
VERSION 5.7 ;
BUSBITCHARS "[]" ;
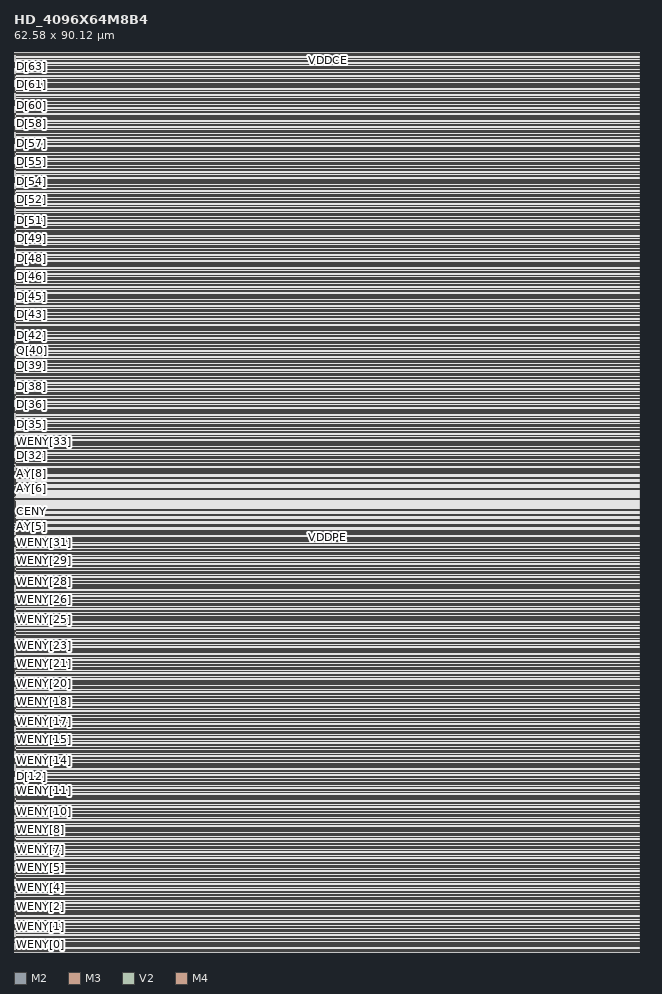
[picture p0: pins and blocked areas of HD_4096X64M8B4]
MACRO HD_4096X64M8B4
	FOREIGN HD_4096X64M8B4 0 0 ;
	SYMMETRY X Y ;
	SIZE 62.58 BY 90.12 ;
	CLASS BLOCK ;
	PIN AY[0]
		USE SIGNAL ;
		DIRECTION OUTPUT ;
		SHAPE ABUTMENT ;
		PORT
			 LAYER M2 ;
			RECT 0.0714 44.5114 0.1097 44.549 ;
			 LAYER M3 ;
			RECT 0.0714 44.5114 0.1097 44.6118 ;
			 LAYER V2 ;
			RECT 0.0831 44.5235 0.098 44.5361 ;
		END

		ANTENNADIFFAREA 0.00194719 ;
		ANTENNAPARTIALMETALAREA 0.00195671 ;
	END AY[0]

	PIN AY[10]
		USE SIGNAL ;
		DIRECTION OUTPUT ;
		SHAPE ABUTMENT ;
		PORT
			 LAYER M3 ;
			RECT 0.0714 47.0714 0.1097 47.1718 ;
		END

		ANTENNADIFFAREA 0.00194719 ;
		ANTENNAPARTIALMETALAREA 0.00195671 ;
	END AY[10]

	PIN AY[11]
		USE SIGNAL ;
		DIRECTION OUTPUT ;
		SHAPE ABUTMENT ;
		PORT
			 LAYER M2 ;
			RECT 0.0098 47.8871 0.0481 47.9247 ;
			 LAYER M3 ;
			RECT 0.0098 47.8243 0.0481 47.9247 ;
			 LAYER V2 ;
			RECT 0.0215 47.8992 0.0364 47.9118 ;
		END

		ANTENNADIFFAREA 0.00194719 ;
		ANTENNAPARTIALMETALAREA 0.00195671 ;
	END AY[11]

	PIN AY[1]
		USE SIGNAL ;
		DIRECTION OUTPUT ;
		SHAPE ABUTMENT ;
		PORT
			 LAYER M2 ;
			RECT 0.0714 44.8125 0.1097 44.8502 ;
			 LAYER M3 ;
			RECT 0.0714 44.8125 0.1097 44.9129 ;
			 LAYER V2 ;
			RECT 0.0831 44.8247 0.098 44.8373 ;
		END

		ANTENNADIFFAREA 0.00194719 ;
		ANTENNAPARTIALMETALAREA 0.00195671 ;
	END AY[1]

	PIN AY[2]
		USE SIGNAL ;
		DIRECTION OUTPUT ;
		SHAPE ABUTMENT ;
		PORT
			 LAYER M2 ;
			RECT 0.0714 44.9631 0.1097 45.0008 ;
			 LAYER M3 ;
			RECT 0.0714 44.9631 0.1097 45.0635 ;
			 LAYER V2 ;
			RECT 0.0831 44.9753 0.098 44.9878 ;
		END

		ANTENNADIFFAREA 0.00194719 ;
		ANTENNAPARTIALMETALAREA 0.00195671 ;
	END AY[2]

	PIN AY[3]
		USE SIGNAL ;
		DIRECTION OUTPUT ;
		SHAPE ABUTMENT ;
		PORT
			 LAYER M2 ;
			RECT 0.0098 45.6282 0.0481 45.6659 ;
			 LAYER M3 ;
			RECT 0.0098 45.5655 0.0481 45.6659 ;
			 LAYER V2 ;
			RECT 0.0215 45.6404 0.0364 45.6529 ;
		END

		ANTENNADIFFAREA 0.00194719 ;
		ANTENNAPARTIALMETALAREA 0.00195671 ;
	END AY[3]

	PIN AY[4]
		USE SIGNAL ;
		DIRECTION OUTPUT ;
		SHAPE ABUTMENT ;
		PORT
			 LAYER M2 ;
			RECT 0.0098 44.7247 0.0481 44.7624 ;
			 LAYER M3 ;
			RECT 0.0098 44.662 0.0481 44.7624 ;
			 LAYER V2 ;
			RECT 0.0215 44.7369 0.0364 44.7494 ;
		END

		ANTENNADIFFAREA 0.00194719 ;
		ANTENNAPARTIALMETALAREA 0.00195671 ;
	END AY[4]

	PIN AY[5]
		USE SIGNAL ;
		DIRECTION OUTPUT ;
		SHAPE ABUTMENT ;
		PORT
			 LAYER M2 ;
			RECT 0.0714 43.3067 0.1097 43.3443 ;
			 LAYER M3 ;
			RECT 0.0714 43.3067 0.1097 43.4071 ;
			 LAYER V2 ;
			RECT 0.0831 43.3188 0.098 43.3314 ;
		END

		ANTENNADIFFAREA 0.00194719 ;
		ANTENNAPARTIALMETALAREA 0.00195671 ;
	END AY[5]

	PIN AY[6]
		USE SIGNAL ;
		DIRECTION OUTPUT ;
		SHAPE ABUTMENT ;
		PORT
			 LAYER M2 ;
			RECT 0.0098 46.3812 0.0481 46.4188 ;
		END

		ANTENNADIFFAREA 0.00194719 ;
		ANTENNAPARTIALMETALAREA 0.00195671 ;
	END AY[6]

	PIN AY[7]
		USE SIGNAL ;
		DIRECTION OUTPUT ;
		SHAPE ABUTMENT ;
		PORT
			 LAYER M2 ;
			RECT 0.0714 46.1678 0.1097 46.2055 ;
			 LAYER M3 ;
			RECT 0.0714 46.1678 0.1097 46.2682 ;
			 LAYER V2 ;
			RECT 0.0831 46.18 0.098 46.1925 ;
		END

		ANTENNADIFFAREA 0.00194719 ;
		ANTENNAPARTIALMETALAREA 0.00195671 ;
	END AY[7]

	PIN AY[8]
		USE SIGNAL ;
		DIRECTION OUTPUT ;
		SHAPE ABUTMENT ;
		PORT
			 LAYER M2 ;
			RECT 0.0098 47.0714 0.0481 47.109 ;
		END

		ANTENNADIFFAREA 0.00194719 ;
		ANTENNAPARTIALMETALAREA 0.00195671 ;
	END AY[8]

	PIN AY[9]
		USE SIGNAL ;
		DIRECTION OUTPUT ;
		SHAPE ABUTMENT ;
		PORT
			 LAYER M2 ;
			RECT 0.0714 47.3725 0.1097 47.4102 ;
			 LAYER M3 ;
			RECT 0.0714 47.3725 0.1097 47.4729 ;
			 LAYER V2 ;
			RECT 0.0831 47.3847 0.098 47.3973 ;
		END

		ANTENNADIFFAREA 0.00194719 ;
		ANTENNAPARTIALMETALAREA 0.00195671 ;
	END AY[9]

	PIN A[0]
		USE SIGNAL ;
		DIRECTION INPUT ;
		SHAPE ABUTMENT ;
		PORT
			 LAYER M2 ;
			RECT 0.0098 44.2729 0.0481 44.3106 ;
			 LAYER M3 ;
			RECT 0.0098 44.2102 0.0481 44.3106 ;
			 LAYER V2 ;
			RECT 0.0215 44.2851 0.0364 44.2976 ;
		END

		ANTENNAGATEAREA 0.00027817 ;
		ANTENNADIFFAREA 0.00194719 ;
		ANTENNAPARTIALMETALAREA 0.00195671 ;
	END A[0]

	PIN A[10]
		USE SIGNAL ;
		DIRECTION INPUT ;
		SHAPE ABUTMENT ;
		PORT
			 LAYER M2 ;
			RECT 0.0098 47.4353 0.0481 47.4729 ;
			 LAYER M3 ;
			RECT 0.0098 47.3725 0.0481 47.4729 ;
			 LAYER V2 ;
			RECT 0.0215 47.4475 0.0364 47.46 ;
		END

		ANTENNAGATEAREA 0.00027817 ;
		ANTENNADIFFAREA 0.00194719 ;
		ANTENNAPARTIALMETALAREA 0.00195671 ;
	END A[10]

	PIN A[11]
		USE SIGNAL ;
		DIRECTION INPUT ;
		SHAPE ABUTMENT ;
		PORT
			 LAYER M2 ;
			RECT 0.0098 47.1341 0.0481 47.1718 ;
		END

		ANTENNAGATEAREA 0.00027817 ;
		ANTENNADIFFAREA 0.00194719 ;
		ANTENNAPARTIALMETALAREA 0.00195671 ;
	END A[11]

	PIN A[1]
		USE SIGNAL ;
		DIRECTION INPUT ;
		SHAPE ABUTMENT ;
		PORT
			 LAYER M2 ;
			RECT 0.0098 43.52 0.0481 43.5576 ;
			 LAYER M3 ;
			RECT 0.0098 43.4573 0.0481 43.5576 ;
			 LAYER V2 ;
			RECT 0.0215 43.5322 0.0364 43.5447 ;
		END

		ANTENNAGATEAREA 0.00027817 ;
		ANTENNADIFFAREA 0.00194719 ;
		ANTENNAPARTIALMETALAREA 0.00195671 ;
	END A[1]

	PIN A[2]
		USE SIGNAL ;
		DIRECTION INPUT ;
		SHAPE ABUTMENT ;
		PORT
			 LAYER M2 ;
			RECT 0.0714 46.9208 0.1097 46.9584 ;
			 LAYER M3 ;
			RECT 0.0714 46.9208 0.1097 47.0212 ;
			 LAYER V2 ;
			RECT 0.0831 46.9329 0.098 46.9455 ;
		END

		ANTENNAGATEAREA 0.00027817 ;
		ANTENNADIFFAREA 0.00194719 ;
		ANTENNAPARTIALMETALAREA 0.00195671 ;
	END A[2]

	PIN A[3]
		USE SIGNAL ;
		DIRECTION INPUT ;
		SHAPE ABUTMENT ;
		PORT
			 LAYER M2 ;
			RECT 0.0098 45.7788 0.0481 45.8165 ;
			 LAYER M3 ;
			RECT 0.0098 45.7161 0.0481 45.8165 ;
			 LAYER V2 ;
			RECT 0.0215 45.791 0.0364 45.8035 ;
		END

		ANTENNAGATEAREA 0.00027817 ;
		ANTENNADIFFAREA 0.00194719 ;
		ANTENNAPARTIALMETALAREA 0.00195671 ;
	END A[3]

	PIN A[4]
		USE SIGNAL ;
		DIRECTION INPUT ;
		SHAPE ABUTMENT ;
		PORT
			 LAYER M2 ;
			RECT 0.0098 45.1765 0.0481 45.2141 ;
			 LAYER M3 ;
			RECT 0.0098 45.1137 0.0481 45.2141 ;
			 LAYER V2 ;
			RECT 0.0215 45.1886 0.0364 45.2012 ;
		END

		ANTENNAGATEAREA 0.00027817 ;
		ANTENNADIFFAREA 0.00194719 ;
		ANTENNAPARTIALMETALAREA 0.00195671 ;
	END A[4]

	PIN A[5]
		USE SIGNAL ;
		DIRECTION INPUT ;
		SHAPE ABUTMENT ;
		PORT
			 LAYER M2 ;
			RECT 0.0714 44.3608 0.1097 44.3984 ;
			 LAYER M3 ;
			RECT 0.0714 44.3608 0.1097 44.4612 ;
			 LAYER V2 ;
			RECT 0.0831 44.3729 0.098 44.3855 ;
		END

		ANTENNAGATEAREA 0.00027817 ;
		ANTENNADIFFAREA 0.00194719 ;
		ANTENNAPARTIALMETALAREA 0.00195671 ;
	END A[5]

	PIN A[6]
		USE SIGNAL ;
		DIRECTION INPUT ;
		SHAPE ABUTMENT ;
		PORT
			 LAYER M2 ;
			RECT 0.0098 45.9294 0.0481 45.9671 ;
			 LAYER M3 ;
			RECT 0.0098 45.8667 0.0481 45.9671 ;
			 LAYER V2 ;
			RECT 0.0215 45.9416 0.0364 45.9541 ;
		END

		ANTENNAGATEAREA 0.00027817 ;
		ANTENNADIFFAREA 0.00194719 ;
		ANTENNAPARTIALMETALAREA 0.00195671 ;
	END A[6]

	PIN A[7]
		USE SIGNAL ;
		DIRECTION INPUT ;
		SHAPE ABUTMENT ;
		PORT
			 LAYER M2 ;
			RECT 0.0098 46.5318 0.0481 46.5694 ;
		END

		ANTENNAGATEAREA 0.00027817 ;
		ANTENNADIFFAREA 0.00194719 ;
		ANTENNAPARTIALMETALAREA 0.00195671 ;
	END A[7]

	PIN A[8]
		USE SIGNAL ;
		DIRECTION INPUT ;
		SHAPE ABUTMENT ;
		PORT
			 LAYER M2 ;
			RECT 0.0098 46.8329 0.0481 46.8706 ;
			 LAYER M3 ;
			RECT 0.0098 46.7702 0.0481 46.8706 ;
			 LAYER V2 ;
			RECT 0.0215 46.8451 0.0364 46.8576 ;
		END

		ANTENNAGATEAREA 0.00027817 ;
		ANTENNADIFFAREA 0.00194719 ;
		ANTENNAPARTIALMETALAREA 0.00195671 ;
	END A[8]

	PIN A[9]
		USE SIGNAL ;
		DIRECTION INPUT ;
		SHAPE ABUTMENT ;
		PORT
			 LAYER M2 ;
			RECT 0.0098 46.9835 0.0481 47.0212 ;
			 LAYER M3 ;
			RECT 0.0098 46.9208 0.0481 47.0212 ;
			 LAYER V2 ;
			RECT 0.0215 46.9957 0.0364 47.0082 ;
		END

		ANTENNAGATEAREA 0.00027817 ;
		ANTENNADIFFAREA 0.00194719 ;
		ANTENNAPARTIALMETALAREA 0.00195671 ;
	END A[9]

	PIN CEN
		USE SIGNAL ;
		DIRECTION INPUT ;
		SHAPE ABUTMENT ;
		PORT
			 LAYER M2 ;
			RECT 0.0714 47.9749 0.1097 48.0125 ;
			 LAYER M3 ;
			RECT 0.0714 47.9749 0.1097 48.0753 ;
			 LAYER V2 ;
			RECT 0.0831 47.9871 0.098 47.9996 ;
		END

		ANTENNAGATEAREA 0.00027817 ;
		ANTENNADIFFAREA 0.00194719 ;
		ANTENNAPARTIALMETALAREA 0.00195671 ;
	END CEN

	PIN CENY
		USE SIGNAL ;
		DIRECTION OUTPUT ;
		SHAPE ABUTMENT ;
		PORT
			 LAYER M2 ;
			RECT 0.0098 44.1224 0.0481 44.16 ;
		END

		ANTENNADIFFAREA 0.00194719 ;
		ANTENNAPARTIALMETALAREA 0.00195671 ;
	END CENY

	PIN CLK
		USE SIGNAL ;
		DIRECTION INPUT ;
		SHAPE ABUTMENT ;
		PORT
			 LAYER M2 ;
			RECT 0.0098 44.5741 0.0481 44.6118 ;
			 LAYER M3 ;
			RECT 0.0098 44.5114 0.0481 44.6118 ;
			 LAYER V2 ;
			RECT 0.0215 44.5863 0.0364 44.5988 ;
		END

		ANTENNAGATEAREA 0.00027817 ;
		ANTENNADIFFAREA 0.00194719 ;
		ANTENNAPARTIALMETALAREA 0.00195671 ;
	END CLK

	PIN DFTRAMBYP
		USE SIGNAL ;
		DIRECTION INPUT ;
		SHAPE ABUTMENT ;
		PORT
			 LAYER M2 ;
			RECT 0.0714 43.0055 0.1097 43.0431 ;
			 LAYER M3 ;
			RECT 0.0714 43.0055 0.1097 43.1059 ;
			 LAYER V2 ;
			RECT 0.0831 43.0176 0.098 43.0302 ;
		END

		ANTENNAGATEAREA 0.00027817 ;
		ANTENNADIFFAREA 0.00194719 ;
		ANTENNAPARTIALMETALAREA 0.00195671 ;
	END DFTRAMBYP

	PIN D[0]
		USE SIGNAL ;
		DIRECTION INPUT ;
		SHAPE ABUTMENT ;
		PORT
			 LAYER M2 ;
			RECT 0.0098 1.3678 0.0481 1.4055 ;
			 LAYER M3 ;
			RECT 0.0098 1.3678 0.0481 1.4682 ;
			 LAYER V2 ;
			RECT 0.0215 1.3808 0.0364 1.3933 ;
		END

		ANTENNAGATEAREA 0.00027817 ;
		ANTENNADIFFAREA 0.00194719 ;
		ANTENNAPARTIALMETALAREA 0.00195671 ;
	END D[0]

	PIN D[10]
		USE SIGNAL ;
		DIRECTION INPUT ;
		SHAPE ABUTMENT ;
		PORT
			 LAYER M2 ;
			RECT 0.0098 14.1678 0.0481 14.2055 ;
			 LAYER M3 ;
			RECT 0.0098 14.1678 0.0481 14.2682 ;
			 LAYER V2 ;
			RECT 0.0215 14.1808 0.0364 14.1933 ;
		END

		ANTENNAGATEAREA 0.00027817 ;
		ANTENNADIFFAREA 0.00194719 ;
		ANTENNAPARTIALMETALAREA 0.00195671 ;
	END D[10]

	PIN D[11]
		USE SIGNAL ;
		DIRECTION INPUT ;
		SHAPE ABUTMENT ;
		PORT
			 LAYER M2 ;
			RECT 0.0098 15.4478 0.0481 15.4855 ;
			 LAYER M3 ;
			RECT 0.0098 15.4478 0.0481 15.5482 ;
			 LAYER V2 ;
			RECT 0.0215 15.4608 0.0364 15.4733 ;
		END

		ANTENNAGATEAREA 0.00027817 ;
		ANTENNADIFFAREA 0.00194719 ;
		ANTENNAPARTIALMETALAREA 0.00195671 ;
	END D[11]

	PIN D[12]
		USE SIGNAL ;
		DIRECTION INPUT ;
		SHAPE ABUTMENT ;
		PORT
			 LAYER M2 ;
			RECT 0.0098 16.7278 0.0481 16.7655 ;
			 LAYER M3 ;
			RECT 0.0098 16.7278 0.0481 16.8282 ;
			 LAYER V2 ;
			RECT 0.0215 16.7408 0.0364 16.7533 ;
		END

		ANTENNAGATEAREA 0.00027817 ;
		ANTENNADIFFAREA 0.00194719 ;
		ANTENNAPARTIALMETALAREA 0.00195671 ;
	END D[12]

	PIN D[13]
		USE SIGNAL ;
		DIRECTION INPUT ;
		SHAPE ABUTMENT ;
		PORT
			 LAYER M2 ;
			RECT 0.0098 18.0078 0.0481 18.0455 ;
			 LAYER M3 ;
			RECT 0.0098 18.0078 0.0481 18.1082 ;
			 LAYER V2 ;
			RECT 0.0215 18.0208 0.0364 18.0333 ;
		END

		ANTENNAGATEAREA 0.00027817 ;
		ANTENNADIFFAREA 0.00194719 ;
		ANTENNAPARTIALMETALAREA 0.00195671 ;
	END D[13]

	PIN D[14]
		USE SIGNAL ;
		DIRECTION INPUT ;
		SHAPE ABUTMENT ;
		PORT
			 LAYER M2 ;
			RECT 0.0098 19.2878 0.0481 19.3255 ;
			 LAYER M3 ;
			RECT 0.0098 19.2878 0.0481 19.3882 ;
			 LAYER V2 ;
			RECT 0.0215 19.3008 0.0364 19.3133 ;
		END

		ANTENNAGATEAREA 0.00027817 ;
		ANTENNADIFFAREA 0.00194719 ;
		ANTENNAPARTIALMETALAREA 0.00195671 ;
	END D[14]

	PIN D[15]
		USE SIGNAL ;
		DIRECTION INPUT ;
		SHAPE ABUTMENT ;
		PORT
			 LAYER M2 ;
			RECT 0.0098 20.5678 0.0481 20.6055 ;
			 LAYER M3 ;
			RECT 0.0098 20.5678 0.0481 20.6682 ;
			 LAYER V2 ;
			RECT 0.0215 20.5808 0.0364 20.5933 ;
		END

		ANTENNAGATEAREA 0.00027817 ;
		ANTENNADIFFAREA 0.00194719 ;
		ANTENNAPARTIALMETALAREA 0.00195671 ;
	END D[15]

	PIN D[16]
		USE SIGNAL ;
		DIRECTION INPUT ;
		SHAPE ABUTMENT ;
		PORT
			 LAYER M2 ;
			RECT 0.0098 21.8478 0.0481 21.8855 ;
			 LAYER M3 ;
			RECT 0.0098 21.8478 0.0481 21.9482 ;
			 LAYER V2 ;
			RECT 0.0215 21.8608 0.0364 21.8733 ;
		END

		ANTENNAGATEAREA 0.00027817 ;
		ANTENNADIFFAREA 0.00194719 ;
		ANTENNAPARTIALMETALAREA 0.00195671 ;
	END D[16]

	PIN D[17]
		USE SIGNAL ;
		DIRECTION INPUT ;
		SHAPE ABUTMENT ;
		PORT
			 LAYER M2 ;
			RECT 0.0098 23.1278 0.0481 23.1655 ;
			 LAYER M3 ;
			RECT 0.0098 23.1278 0.0481 23.2282 ;
			 LAYER V2 ;
			RECT 0.0215 23.1408 0.0364 23.1533 ;
		END

		ANTENNAGATEAREA 0.00027817 ;
		ANTENNADIFFAREA 0.00194719 ;
		ANTENNAPARTIALMETALAREA 0.00195671 ;
	END D[17]

	PIN D[18]
		USE SIGNAL ;
		DIRECTION INPUT ;
		SHAPE ABUTMENT ;
		PORT
			 LAYER M2 ;
			RECT 0.0098 24.4078 0.0481 24.4455 ;
			 LAYER M3 ;
			RECT 0.0098 24.4078 0.0481 24.5082 ;
			 LAYER V2 ;
			RECT 0.0215 24.4208 0.0364 24.4333 ;
		END

		ANTENNAGATEAREA 0.00027817 ;
		ANTENNADIFFAREA 0.00194719 ;
		ANTENNAPARTIALMETALAREA 0.00195671 ;
	END D[18]

	PIN D[19]
		USE SIGNAL ;
		DIRECTION INPUT ;
		SHAPE ABUTMENT ;
		PORT
			 LAYER M2 ;
			RECT 0.0098 25.6878 0.0481 25.7255 ;
			 LAYER M3 ;
			RECT 0.0098 25.6878 0.0481 25.7882 ;
			 LAYER V2 ;
			RECT 0.0215 25.7008 0.0364 25.7133 ;
		END

		ANTENNAGATEAREA 0.00027817 ;
		ANTENNADIFFAREA 0.00194719 ;
		ANTENNAPARTIALMETALAREA 0.00195671 ;
	END D[19]

	PIN D[1]
		USE SIGNAL ;
		DIRECTION INPUT ;
		SHAPE ABUTMENT ;
		PORT
			 LAYER M2 ;
			RECT 0.0098 2.6478 0.0481 2.6855 ;
			 LAYER M3 ;
			RECT 0.0098 2.6478 0.0481 2.7482 ;
			 LAYER V2 ;
			RECT 0.0215 2.6608 0.0364 2.6733 ;
		END

		ANTENNAGATEAREA 0.00027817 ;
		ANTENNADIFFAREA 0.00194719 ;
		ANTENNAPARTIALMETALAREA 0.00195671 ;
	END D[1]

	PIN D[20]
		USE SIGNAL ;
		DIRECTION INPUT ;
		SHAPE ABUTMENT ;
		PORT
			 LAYER M2 ;
			RECT 0.0098 26.9678 0.0481 27.0055 ;
			 LAYER M3 ;
			RECT 0.0098 26.9678 0.0481 27.0682 ;
			 LAYER V2 ;
			RECT 0.0215 26.9808 0.0364 26.9933 ;
		END

		ANTENNAGATEAREA 0.00027817 ;
		ANTENNADIFFAREA 0.00194719 ;
		ANTENNAPARTIALMETALAREA 0.00195671 ;
	END D[20]

	PIN D[21]
		USE SIGNAL ;
		DIRECTION INPUT ;
		SHAPE ABUTMENT ;
		PORT
			 LAYER M2 ;
			RECT 0.0098 28.2478 0.0481 28.2855 ;
			 LAYER M3 ;
			RECT 0.0098 28.2478 0.0481 28.3482 ;
			 LAYER V2 ;
			RECT 0.0215 28.2608 0.0364 28.2733 ;
		END

		ANTENNAGATEAREA 0.00027817 ;
		ANTENNADIFFAREA 0.00194719 ;
		ANTENNAPARTIALMETALAREA 0.00195671 ;
	END D[21]

	PIN D[22]
		USE SIGNAL ;
		DIRECTION INPUT ;
		SHAPE ABUTMENT ;
		PORT
			 LAYER M2 ;
			RECT 0.0098 29.5278 0.0481 29.5655 ;
			 LAYER M3 ;
			RECT 0.0098 29.5278 0.0481 29.6282 ;
			 LAYER V2 ;
			RECT 0.0215 29.5408 0.0364 29.5533 ;
		END

		ANTENNAGATEAREA 0.00027817 ;
		ANTENNADIFFAREA 0.00194719 ;
		ANTENNAPARTIALMETALAREA 0.00195671 ;
	END D[22]

	PIN D[23]
		USE SIGNAL ;
		DIRECTION INPUT ;
		SHAPE ABUTMENT ;
		PORT
			 LAYER M2 ;
			RECT 0.0098 30.8078 0.0481 30.8455 ;
			 LAYER M3 ;
			RECT 0.0098 30.8078 0.0481 30.9082 ;
			 LAYER V2 ;
			RECT 0.0215 30.8208 0.0364 30.8333 ;
		END

		ANTENNAGATEAREA 0.00027817 ;
		ANTENNADIFFAREA 0.00194719 ;
		ANTENNAPARTIALMETALAREA 0.00195671 ;
	END D[23]

	PIN D[24]
		USE SIGNAL ;
		DIRECTION INPUT ;
		SHAPE ABUTMENT ;
		PORT
			 LAYER M2 ;
			RECT 0.0098 32.0878 0.0481 32.1255 ;
			 LAYER M3 ;
			RECT 0.0098 32.0878 0.0481 32.1882 ;
			 LAYER V2 ;
			RECT 0.0215 32.1008 0.0364 32.1133 ;
		END

		ANTENNAGATEAREA 0.00027817 ;
		ANTENNADIFFAREA 0.00194719 ;
		ANTENNAPARTIALMETALAREA 0.00195671 ;
	END D[24]

	PIN D[25]
		USE SIGNAL ;
		DIRECTION INPUT ;
		SHAPE ABUTMENT ;
		PORT
			 LAYER M2 ;
			RECT 0.0098 33.3678 0.0481 33.4055 ;
			 LAYER M3 ;
			RECT 0.0098 33.3678 0.0481 33.4682 ;
			 LAYER V2 ;
			RECT 0.0215 33.3808 0.0364 33.3933 ;
		END

		ANTENNAGATEAREA 0.00027817 ;
		ANTENNADIFFAREA 0.00194719 ;
		ANTENNAPARTIALMETALAREA 0.00195671 ;
	END D[25]

	PIN D[26]
		USE SIGNAL ;
		DIRECTION INPUT ;
		SHAPE ABUTMENT ;
		PORT
			 LAYER M2 ;
			RECT 0.0098 34.6478 0.0481 34.6855 ;
			 LAYER M3 ;
			RECT 0.0098 34.6478 0.0481 34.7482 ;
			 LAYER V2 ;
			RECT 0.0215 34.6608 0.0364 34.6733 ;
		END

		ANTENNAGATEAREA 0.00027817 ;
		ANTENNADIFFAREA 0.00194719 ;
		ANTENNAPARTIALMETALAREA 0.00195671 ;
	END D[26]

	PIN D[27]
		USE SIGNAL ;
		DIRECTION INPUT ;
		SHAPE ABUTMENT ;
		PORT
			 LAYER M2 ;
			RECT 0.0098 35.9278 0.0481 35.9655 ;
			 LAYER M3 ;
			RECT 0.0098 35.9278 0.0481 36.0282 ;
			 LAYER V2 ;
			RECT 0.0215 35.9408 0.0364 35.9533 ;
		END

		ANTENNAGATEAREA 0.00027817 ;
		ANTENNADIFFAREA 0.00194719 ;
		ANTENNAPARTIALMETALAREA 0.00195671 ;
	END D[27]

	PIN D[28]
		USE SIGNAL ;
		DIRECTION INPUT ;
		SHAPE ABUTMENT ;
		PORT
			 LAYER M2 ;
			RECT 0.0098 37.2078 0.0481 37.2455 ;
			 LAYER M3 ;
			RECT 0.0098 37.2078 0.0481 37.3082 ;
			 LAYER V2 ;
			RECT 0.0215 37.2208 0.0364 37.2333 ;
		END

		ANTENNAGATEAREA 0.00027817 ;
		ANTENNADIFFAREA 0.00194719 ;
		ANTENNAPARTIALMETALAREA 0.00195671 ;
	END D[28]

	PIN D[29]
		USE SIGNAL ;
		DIRECTION INPUT ;
		SHAPE ABUTMENT ;
		PORT
			 LAYER M2 ;
			RECT 0.0098 38.4878 0.0481 38.5255 ;
			 LAYER M3 ;
			RECT 0.0098 38.4878 0.0481 38.5882 ;
			 LAYER V2 ;
			RECT 0.0215 38.5008 0.0364 38.5133 ;
		END

		ANTENNAGATEAREA 0.00027817 ;
		ANTENNADIFFAREA 0.00194719 ;
		ANTENNAPARTIALMETALAREA 0.00195671 ;
	END D[29]

	PIN D[2]
		USE SIGNAL ;
		DIRECTION INPUT ;
		SHAPE ABUTMENT ;
		PORT
			 LAYER M2 ;
			RECT 0.0098 3.9278 0.0481 3.9655 ;
			 LAYER M3 ;
			RECT 0.0098 3.9278 0.0481 4.0282 ;
			 LAYER V2 ;
			RECT 0.0215 3.9408 0.0364 3.9533 ;
		END

		ANTENNAGATEAREA 0.00027817 ;
		ANTENNADIFFAREA 0.00194719 ;
		ANTENNAPARTIALMETALAREA 0.00195671 ;
	END D[2]

	PIN D[30]
		USE SIGNAL ;
		DIRECTION INPUT ;
		SHAPE ABUTMENT ;
		PORT
			 LAYER M2 ;
			RECT 0.0098 39.7678 0.0481 39.8055 ;
			 LAYER M3 ;
			RECT 0.0098 39.7678 0.0481 39.8682 ;
			 LAYER V2 ;
			RECT 0.0215 39.7808 0.0364 39.7933 ;
		END

		ANTENNAGATEAREA 0.00027817 ;
		ANTENNADIFFAREA 0.00194719 ;
		ANTENNAPARTIALMETALAREA 0.00195671 ;
	END D[30]

	PIN D[31]
		USE SIGNAL ;
		DIRECTION INPUT ;
		SHAPE ABUTMENT ;
		PORT
			 LAYER M2 ;
			RECT 0.0098 41.0478 0.0481 41.0855 ;
			 LAYER M3 ;
			RECT 0.0098 41.0478 0.0481 41.1482 ;
			 LAYER V2 ;
			RECT 0.0215 41.0608 0.0364 41.0733 ;
		END

		ANTENNAGATEAREA 0.00027817 ;
		ANTENNADIFFAREA 0.00194719 ;
		ANTENNAPARTIALMETALAREA 0.00195671 ;
	END D[31]

	PIN D[32]
		USE SIGNAL ;
		DIRECTION INPUT ;
		SHAPE ABUTMENT ;
		PORT
			 LAYER M2 ;
			RECT 0.0098 48.9851 0.0481 49.0227 ;
			 LAYER M3 ;
			RECT 0.0098 48.9224 0.0481 49.0227 ;
			 LAYER V2 ;
			RECT 0.0215 48.9973 0.0364 49.0098 ;
		END

		ANTENNAGATEAREA 0.00027817 ;
		ANTENNADIFFAREA 0.00194719 ;
		ANTENNAPARTIALMETALAREA 0.00195671 ;
	END D[32]

	PIN D[33]
		USE SIGNAL ;
		DIRECTION INPUT ;
		SHAPE ABUTMENT ;
		PORT
			 LAYER M2 ;
			RECT 0.0098 50.2651 0.0481 50.3027 ;
			 LAYER M3 ;
			RECT 0.0098 50.2024 0.0481 50.3027 ;
			 LAYER V2 ;
			RECT 0.0215 50.2773 0.0364 50.2898 ;
		END

		ANTENNAGATEAREA 0.00027817 ;
		ANTENNADIFFAREA 0.00194719 ;
		ANTENNAPARTIALMETALAREA 0.00195671 ;
	END D[33]

	PIN D[34]
		USE SIGNAL ;
		DIRECTION INPUT ;
		SHAPE ABUTMENT ;
		PORT
			 LAYER M2 ;
			RECT 0.0098 51.5451 0.0481 51.5827 ;
			 LAYER M3 ;
			RECT 0.0098 51.4824 0.0481 51.5827 ;
			 LAYER V2 ;
			RECT 0.0215 51.5573 0.0364 51.5698 ;
		END

		ANTENNAGATEAREA 0.00027817 ;
		ANTENNADIFFAREA 0.00194719 ;
		ANTENNAPARTIALMETALAREA 0.00195671 ;
	END D[34]

	PIN D[35]
		USE SIGNAL ;
		DIRECTION INPUT ;
		SHAPE ABUTMENT ;
		PORT
			 LAYER M2 ;
			RECT 0.0098 52.8251 0.0481 52.8627 ;
			 LAYER M3 ;
			RECT 0.0098 52.7624 0.0481 52.8627 ;
			 LAYER V2 ;
			RECT 0.0215 52.8373 0.0364 52.8498 ;
		END

		ANTENNAGATEAREA 0.00027817 ;
		ANTENNADIFFAREA 0.00194719 ;
		ANTENNAPARTIALMETALAREA 0.00195671 ;
	END D[35]

	PIN D[36]
		USE SIGNAL ;
		DIRECTION INPUT ;
		SHAPE ABUTMENT ;
		PORT
			 LAYER M2 ;
			RECT 0.0098 54.1051 0.0481 54.1427 ;
			 LAYER M3 ;
			RECT 0.0098 54.0424 0.0481 54.1427 ;
			 LAYER V2 ;
			RECT 0.0215 54.1173 0.0364 54.1298 ;
		END

		ANTENNAGATEAREA 0.00027817 ;
		ANTENNADIFFAREA 0.00194719 ;
		ANTENNAPARTIALMETALAREA 0.00195671 ;
	END D[36]

	PIN D[37]
		USE SIGNAL ;
		DIRECTION INPUT ;
		SHAPE ABUTMENT ;
		PORT
			 LAYER M2 ;
			RECT 0.0098 55.3851 0.0481 55.4227 ;
			 LAYER M3 ;
			RECT 0.0098 55.3224 0.0481 55.4227 ;
			 LAYER V2 ;
			RECT 0.0215 55.3973 0.0364 55.4098 ;
		END

		ANTENNAGATEAREA 0.00027817 ;
		ANTENNADIFFAREA 0.00194719 ;
		ANTENNAPARTIALMETALAREA 0.00195671 ;
	END D[37]

	PIN D[38]
		USE SIGNAL ;
		DIRECTION INPUT ;
		SHAPE ABUTMENT ;
		PORT
			 LAYER M2 ;
			RECT 0.0098 56.6651 0.0481 56.7027 ;
			 LAYER M3 ;
			RECT 0.0098 56.6024 0.0481 56.7027 ;
			 LAYER V2 ;
			RECT 0.0215 56.6773 0.0364 56.6898 ;
		END

		ANTENNAGATEAREA 0.00027817 ;
		ANTENNADIFFAREA 0.00194719 ;
		ANTENNAPARTIALMETALAREA 0.00195671 ;
	END D[38]

	PIN D[39]
		USE SIGNAL ;
		DIRECTION INPUT ;
		SHAPE ABUTMENT ;
		PORT
			 LAYER M2 ;
			RECT 0.0098 57.9451 0.0481 57.9827 ;
			 LAYER M3 ;
			RECT 0.0098 57.8824 0.0481 57.9827 ;
			 LAYER V2 ;
			RECT 0.0215 57.9573 0.0364 57.9698 ;
		END

		ANTENNAGATEAREA 0.00027817 ;
		ANTENNADIFFAREA 0.00194719 ;
		ANTENNAPARTIALMETALAREA 0.00195671 ;
	END D[39]

	PIN D[3]
		USE SIGNAL ;
		DIRECTION INPUT ;
		SHAPE ABUTMENT ;
		PORT
			 LAYER M2 ;
			RECT 0.0098 5.2078 0.0481 5.2455 ;
			 LAYER M3 ;
			RECT 0.0098 5.2078 0.0481 5.3082 ;
			 LAYER V2 ;
			RECT 0.0215 5.2208 0.0364 5.2333 ;
		END

		ANTENNAGATEAREA 0.00027817 ;
		ANTENNADIFFAREA 0.00194719 ;
		ANTENNAPARTIALMETALAREA 0.00195671 ;
	END D[3]

	PIN D[40]
		USE SIGNAL ;
		DIRECTION INPUT ;
		SHAPE ABUTMENT ;
		PORT
			 LAYER M2 ;
			RECT 0.0098 59.2251 0.0481 59.2627 ;
			 LAYER M3 ;
			RECT 0.0098 59.1624 0.0481 59.2627 ;
			 LAYER V2 ;
			RECT 0.0215 59.2373 0.0364 59.2498 ;
		END

		ANTENNAGATEAREA 0.00027817 ;
		ANTENNADIFFAREA 0.00194719 ;
		ANTENNAPARTIALMETALAREA 0.00195671 ;
	END D[40]

	PIN D[41]
		USE SIGNAL ;
		DIRECTION INPUT ;
		SHAPE ABUTMENT ;
		PORT
			 LAYER M2 ;
			RECT 0.0098 60.5051 0.0481 60.5427 ;
			 LAYER M3 ;
			RECT 0.0098 60.4424 0.0481 60.5427 ;
			 LAYER V2 ;
			RECT 0.0215 60.5173 0.0364 60.5298 ;
		END

		ANTENNAGATEAREA 0.00027817 ;
		ANTENNADIFFAREA 0.00194719 ;
		ANTENNAPARTIALMETALAREA 0.00195671 ;
	END D[41]

	PIN D[42]
		USE SIGNAL ;
		DIRECTION INPUT ;
		SHAPE ABUTMENT ;
		PORT
			 LAYER M2 ;
			RECT 0.0098 61.7851 0.0481 61.8227 ;
			 LAYER M3 ;
			RECT 0.0098 61.7224 0.0481 61.8227 ;
			 LAYER V2 ;
			RECT 0.0215 61.7973 0.0364 61.8098 ;
		END

		ANTENNAGATEAREA 0.00027817 ;
		ANTENNADIFFAREA 0.00194719 ;
		ANTENNAPARTIALMETALAREA 0.00195671 ;
	END D[42]

	PIN D[43]
		USE SIGNAL ;
		DIRECTION INPUT ;
		SHAPE ABUTMENT ;
		PORT
			 LAYER M2 ;
			RECT 0.0098 63.0651 0.0481 63.1027 ;
			 LAYER M3 ;
			RECT 0.0098 63.0024 0.0481 63.1027 ;
			 LAYER V2 ;
			RECT 0.0215 63.0773 0.0364 63.0898 ;
		END

		ANTENNAGATEAREA 0.00027817 ;
		ANTENNADIFFAREA 0.00194719 ;
		ANTENNAPARTIALMETALAREA 0.00195671 ;
	END D[43]

	PIN D[44]
		USE SIGNAL ;
		DIRECTION INPUT ;
		SHAPE ABUTMENT ;
		PORT
			 LAYER M2 ;
			RECT 0.0098 64.3451 0.0481 64.3827 ;
			 LAYER M3 ;
			RECT 0.0098 64.2824 0.0481 64.3827 ;
			 LAYER V2 ;
			RECT 0.0215 64.3573 0.0364 64.3698 ;
		END

		ANTENNAGATEAREA 0.00027817 ;
		ANTENNADIFFAREA 0.00194719 ;
		ANTENNAPARTIALMETALAREA 0.00195671 ;
	END D[44]

	PIN D[45]
		USE SIGNAL ;
		DIRECTION INPUT ;
		SHAPE ABUTMENT ;
		PORT
			 LAYER M2 ;
			RECT 0.0098 65.6251 0.0481 65.6627 ;
			 LAYER M3 ;
			RECT 0.0098 65.5624 0.0481 65.6627 ;
			 LAYER V2 ;
			RECT 0.0215 65.6373 0.0364 65.6498 ;
		END

		ANTENNAGATEAREA 0.00027817 ;
		ANTENNADIFFAREA 0.00194719 ;
		ANTENNAPARTIALMETALAREA 0.00195671 ;
	END D[45]

	PIN D[46]
		USE SIGNAL ;
		DIRECTION INPUT ;
		SHAPE ABUTMENT ;
		PORT
			 LAYER M2 ;
			RECT 0.0098 66.9051 0.0481 66.9427 ;
			 LAYER M3 ;
			RECT 0.0098 66.8424 0.0481 66.9427 ;
			 LAYER V2 ;
			RECT 0.0215 66.9173 0.0364 66.9298 ;
		END

		ANTENNAGATEAREA 0.00027817 ;
		ANTENNADIFFAREA 0.00194719 ;
		ANTENNAPARTIALMETALAREA 0.00195671 ;
	END D[46]

	PIN D[47]
		USE SIGNAL ;
		DIRECTION INPUT ;
		SHAPE ABUTMENT ;
		PORT
			 LAYER M2 ;
			RECT 0.0098 68.1851 0.0481 68.2227 ;
			 LAYER M3 ;
			RECT 0.0098 68.1224 0.0481 68.2227 ;
			 LAYER V2 ;
			RECT 0.0215 68.1973 0.0364 68.2098 ;
		END

		ANTENNAGATEAREA 0.00027817 ;
		ANTENNADIFFAREA 0.00194719 ;
		ANTENNAPARTIALMETALAREA 0.00195671 ;
	END D[47]

	PIN D[48]
		USE SIGNAL ;
		DIRECTION INPUT ;
		SHAPE ABUTMENT ;
		PORT
			 LAYER M2 ;
			RECT 0.0098 69.4651 0.0481 69.5027 ;
			 LAYER M3 ;
			RECT 0.0098 69.4024 0.0481 69.5027 ;
			 LAYER V2 ;
			RECT 0.0215 69.4773 0.0364 69.4898 ;
		END

		ANTENNAGATEAREA 0.00027817 ;
		ANTENNADIFFAREA 0.00194719 ;
		ANTENNAPARTIALMETALAREA 0.00195671 ;
	END D[48]

	PIN D[49]
		USE SIGNAL ;
		DIRECTION INPUT ;
		SHAPE ABUTMENT ;
		PORT
			 LAYER M2 ;
			RECT 0.0098 70.7451 0.0481 70.7827 ;
			 LAYER M3 ;
			RECT 0.0098 70.6824 0.0481 70.7827 ;
			 LAYER V2 ;
			RECT 0.0215 70.7573 0.0364 70.7698 ;
		END

		ANTENNAGATEAREA 0.00027817 ;
		ANTENNADIFFAREA 0.00194719 ;
		ANTENNAPARTIALMETALAREA 0.00195671 ;
	END D[49]

	PIN D[4]
		USE SIGNAL ;
		DIRECTION INPUT ;
		SHAPE ABUTMENT ;
		PORT
			 LAYER M2 ;
			RECT 0.0098 6.4878 0.0481 6.5255 ;
			 LAYER M3 ;
			RECT 0.0098 6.4878 0.0481 6.5882 ;
			 LAYER V2 ;
			RECT 0.0215 6.5008 0.0364 6.5133 ;
		END

		ANTENNAGATEAREA 0.00027817 ;
		ANTENNADIFFAREA 0.00194719 ;
		ANTENNAPARTIALMETALAREA 0.00195671 ;
	END D[4]

	PIN D[50]
		USE SIGNAL ;
		DIRECTION INPUT ;
		SHAPE ABUTMENT ;
		PORT
			 LAYER M2 ;
			RECT 0.0098 72.0251 0.0481 72.0627 ;
			 LAYER M3 ;
			RECT 0.0098 71.9624 0.0481 72.0627 ;
			 LAYER V2 ;
			RECT 0.0215 72.0373 0.0364 72.0498 ;
		END

		ANTENNAGATEAREA 0.00027817 ;
		ANTENNADIFFAREA 0.00194719 ;
		ANTENNAPARTIALMETALAREA 0.00195671 ;
	END D[50]

	PIN D[51]
		USE SIGNAL ;
		DIRECTION INPUT ;
		SHAPE ABUTMENT ;
		PORT
			 LAYER M2 ;
			RECT 0.0098 73.3051 0.0481 73.3427 ;
			 LAYER M3 ;
			RECT 0.0098 73.2424 0.0481 73.3427 ;
			 LAYER V2 ;
			RECT 0.0215 73.3173 0.0364 73.3298 ;
		END

		ANTENNAGATEAREA 0.00027817 ;
		ANTENNADIFFAREA 0.00194719 ;
		ANTENNAPARTIALMETALAREA 0.00195671 ;
	END D[51]

	PIN D[52]
		USE SIGNAL ;
		DIRECTION INPUT ;
		SHAPE ABUTMENT ;
		PORT
			 LAYER M2 ;
			RECT 0.0098 74.5851 0.0481 74.6227 ;
			 LAYER M3 ;
			RECT 0.0098 74.5224 0.0481 74.6227 ;
			 LAYER V2 ;
			RECT 0.0215 74.5973 0.0364 74.6098 ;
		END

		ANTENNAGATEAREA 0.00027817 ;
		ANTENNADIFFAREA 0.00194719 ;
		ANTENNAPARTIALMETALAREA 0.00195671 ;
	END D[52]

	PIN D[53]
		USE SIGNAL ;
		DIRECTION INPUT ;
		SHAPE ABUTMENT ;
		PORT
			 LAYER M2 ;
			RECT 0.0098 75.8651 0.0481 75.9027 ;
			 LAYER M3 ;
			RECT 0.0098 75.8024 0.0481 75.9027 ;
			 LAYER V2 ;
			RECT 0.0215 75.8773 0.0364 75.8898 ;
		END

		ANTENNAGATEAREA 0.00027817 ;
		ANTENNADIFFAREA 0.00194719 ;
		ANTENNAPARTIALMETALAREA 0.00195671 ;
	END D[53]

	PIN D[54]
		USE SIGNAL ;
		DIRECTION INPUT ;
		SHAPE ABUTMENT ;
		PORT
			 LAYER M2 ;
			RECT 0.0098 77.1451 0.0481 77.1827 ;
			 LAYER M3 ;
			RECT 0.0098 77.0824 0.0481 77.1827 ;
			 LAYER V2 ;
			RECT 0.0215 77.1573 0.0364 77.1698 ;
		END

		ANTENNAGATEAREA 0.00027817 ;
		ANTENNADIFFAREA 0.00194719 ;
		ANTENNAPARTIALMETALAREA 0.00195671 ;
	END D[54]

	PIN D[55]
		USE SIGNAL ;
		DIRECTION INPUT ;
		SHAPE ABUTMENT ;
		PORT
			 LAYER M2 ;
			RECT 0.0098 78.4251 0.0481 78.4627 ;
			 LAYER M3 ;
			RECT 0.0098 78.3624 0.0481 78.4627 ;
			 LAYER V2 ;
			RECT 0.0215 78.4373 0.0364 78.4498 ;
		END

		ANTENNAGATEAREA 0.00027817 ;
		ANTENNADIFFAREA 0.00194719 ;
		ANTENNAPARTIALMETALAREA 0.00195671 ;
	END D[55]

	PIN D[56]
		USE SIGNAL ;
		DIRECTION INPUT ;
		SHAPE ABUTMENT ;
		PORT
			 LAYER M2 ;
			RECT 0.0098 79.7051 0.0481 79.7427 ;
			 LAYER M3 ;
			RECT 0.0098 79.6424 0.0481 79.7427 ;
			 LAYER V2 ;
			RECT 0.0215 79.7173 0.0364 79.7298 ;
		END

		ANTENNAGATEAREA 0.00027817 ;
		ANTENNADIFFAREA 0.00194719 ;
		ANTENNAPARTIALMETALAREA 0.00195671 ;
	END D[56]

	PIN D[57]
		USE SIGNAL ;
		DIRECTION INPUT ;
		SHAPE ABUTMENT ;
		PORT
			 LAYER M2 ;
			RECT 0.0098 80.9851 0.0481 81.0227 ;
			 LAYER M3 ;
			RECT 0.0098 80.9224 0.0481 81.0227 ;
			 LAYER V2 ;
			RECT 0.0215 80.9973 0.0364 81.0098 ;
		END

		ANTENNAGATEAREA 0.00027817 ;
		ANTENNADIFFAREA 0.00194719 ;
		ANTENNAPARTIALMETALAREA 0.00195671 ;
	END D[57]

	PIN D[58]
		USE SIGNAL ;
		DIRECTION INPUT ;
		SHAPE ABUTMENT ;
		PORT
			 LAYER M2 ;
			RECT 0.0098 82.2651 0.0481 82.3027 ;
			 LAYER M3 ;
			RECT 0.0098 82.2024 0.0481 82.3027 ;
			 LAYER V2 ;
			RECT 0.0215 82.2773 0.0364 82.2898 ;
		END

		ANTENNAGATEAREA 0.00027817 ;
		ANTENNADIFFAREA 0.00194719 ;
		ANTENNAPARTIALMETALAREA 0.00195671 ;
	END D[58]

	PIN D[59]
		USE SIGNAL ;
		DIRECTION INPUT ;
		SHAPE ABUTMENT ;
		PORT
			 LAYER M2 ;
			RECT 0.0098 83.5451 0.0481 83.5827 ;
			 LAYER M3 ;
			RECT 0.0098 83.4824 0.0481 83.5827 ;
			 LAYER V2 ;
			RECT 0.0215 83.5573 0.0364 83.5698 ;
		END

		ANTENNAGATEAREA 0.00027817 ;
		ANTENNADIFFAREA 0.00194719 ;
		ANTENNAPARTIALMETALAREA 0.00195671 ;
	END D[59]

	PIN D[5]
		USE SIGNAL ;
		DIRECTION INPUT ;
		SHAPE ABUTMENT ;
		PORT
			 LAYER M2 ;
			RECT 0.0098 7.7678 0.0481 7.8055 ;
			 LAYER M3 ;
			RECT 0.0098 7.7678 0.0481 7.8682 ;
			 LAYER V2 ;
			RECT 0.0215 7.7808 0.0364 7.7933 ;
		END

		ANTENNAGATEAREA 0.00027817 ;
		ANTENNADIFFAREA 0.00194719 ;
		ANTENNAPARTIALMETALAREA 0.00195671 ;
	END D[5]

	PIN D[60]
		USE SIGNAL ;
		DIRECTION INPUT ;
		SHAPE ABUTMENT ;
		PORT
			 LAYER M2 ;
			RECT 0.0098 84.8251 0.0481 84.8627 ;
			 LAYER M3 ;
			RECT 0.0098 84.7624 0.0481 84.8627 ;
			 LAYER V2 ;
			RECT 0.0215 84.8373 0.0364 84.8498 ;
		END

		ANTENNAGATEAREA 0.00027817 ;
		ANTENNADIFFAREA 0.00194719 ;
		ANTENNAPARTIALMETALAREA 0.00195671 ;
	END D[60]

	PIN D[61]
		USE SIGNAL ;
		DIRECTION INPUT ;
		SHAPE ABUTMENT ;
		PORT
			 LAYER M2 ;
			RECT 0.0098 86.1051 0.0481 86.1427 ;
			 LAYER M3 ;
			RECT 0.0098 86.0424 0.0481 86.1427 ;
			 LAYER V2 ;
			RECT 0.0215 86.1173 0.0364 86.1298 ;
		END

		ANTENNAGATEAREA 0.00027817 ;
		ANTENNADIFFAREA 0.00194719 ;
		ANTENNAPARTIALMETALAREA 0.00195671 ;
	END D[61]

	PIN D[62]
		USE SIGNAL ;
		DIRECTION INPUT ;
		SHAPE ABUTMENT ;
		PORT
			 LAYER M2 ;
			RECT 0.0098 87.3851 0.0481 87.4227 ;
			 LAYER M3 ;
			RECT 0.0098 87.3224 0.0481 87.4227 ;
			 LAYER V2 ;
			RECT 0.0215 87.3973 0.0364 87.4098 ;
		END

		ANTENNAGATEAREA 0.00027817 ;
		ANTENNADIFFAREA 0.00194719 ;
		ANTENNAPARTIALMETALAREA 0.00195671 ;
	END D[62]

	PIN D[63]
		USE SIGNAL ;
		DIRECTION INPUT ;
		SHAPE ABUTMENT ;
		PORT
			 LAYER M2 ;
			RECT 0.0098 88.6651 0.0481 88.7027 ;
			 LAYER M3 ;
			RECT 0.0098 88.6024 0.0481 88.7027 ;
			 LAYER V2 ;
			RECT 0.0215 88.6773 0.0364 88.6898 ;
		END

		ANTENNAGATEAREA 0.00027817 ;
		ANTENNADIFFAREA 0.00194719 ;
		ANTENNAPARTIALMETALAREA 0.00195671 ;
	END D[63]

	PIN D[6]
		USE SIGNAL ;
		DIRECTION INPUT ;
		SHAPE ABUTMENT ;
		PORT
			 LAYER M2 ;
			RECT 0.0098 9.0478 0.0481 9.0855 ;
			 LAYER M3 ;
			RECT 0.0098 9.0478 0.0481 9.1482 ;
			 LAYER V2 ;
			RECT 0.0215 9.0608 0.0364 9.0733 ;
		END

		ANTENNAGATEAREA 0.00027817 ;
		ANTENNADIFFAREA 0.00194719 ;
		ANTENNAPARTIALMETALAREA 0.00195671 ;
	END D[6]

	PIN D[7]
		USE SIGNAL ;
		DIRECTION INPUT ;
		SHAPE ABUTMENT ;
		PORT
			 LAYER M2 ;
			RECT 0.0098 10.3278 0.0481 10.3655 ;
			 LAYER M3 ;
			RECT 0.0098 10.3278 0.0481 10.4282 ;
			 LAYER V2 ;
			RECT 0.0215 10.3408 0.0364 10.3533 ;
		END

		ANTENNAGATEAREA 0.00027817 ;
		ANTENNADIFFAREA 0.00194719 ;
		ANTENNAPARTIALMETALAREA 0.00195671 ;
	END D[7]

	PIN D[8]
		USE SIGNAL ;
		DIRECTION INPUT ;
		SHAPE ABUTMENT ;
		PORT
			 LAYER M2 ;
			RECT 0.0098 11.6078 0.0481 11.6455 ;
			 LAYER M3 ;
			RECT 0.0098 11.6078 0.0481 11.7082 ;
			 LAYER V2 ;
			RECT 0.0215 11.6208 0.0364 11.6333 ;
		END

		ANTENNAGATEAREA 0.00027817 ;
		ANTENNADIFFAREA 0.00194719 ;
		ANTENNAPARTIALMETALAREA 0.00195671 ;
	END D[8]

	PIN D[9]
		USE SIGNAL ;
		DIRECTION INPUT ;
		SHAPE ABUTMENT ;
		PORT
			 LAYER M2 ;
			RECT 0.0098 12.8878 0.0481 12.9255 ;
			 LAYER M3 ;
			RECT 0.0098 12.8878 0.0481 12.9882 ;
			 LAYER V2 ;
			RECT 0.0215 12.9008 0.0364 12.9133 ;
		END

		ANTENNAGATEAREA 0.00027817 ;
		ANTENNADIFFAREA 0.00194719 ;
		ANTENNAPARTIALMETALAREA 0.00195671 ;
	END D[9]

	PIN EMAS
		USE SIGNAL ;
		DIRECTION INPUT ;
		SHAPE ABUTMENT ;
		PORT
			 LAYER M2 ;
			RECT 0.0714 43.6078 0.1097 43.6455 ;
			 LAYER M3 ;
			RECT 0.0714 43.6078 0.1097 43.7082 ;
			 LAYER V2 ;
			RECT 0.0831 43.62 0.098 43.6325 ;
		END

		ANTENNAGATEAREA 0.00027817 ;
		ANTENNADIFFAREA 0.00194719 ;
		ANTENNAPARTIALMETALAREA 0.00195671 ;
	END EMAS

	PIN EMAW[0]
		USE SIGNAL ;
		DIRECTION INPUT ;
		SHAPE ABUTMENT ;
		PORT
			 LAYER M2 ;
			RECT 0.0714 42.4031 0.1097 42.4408 ;
			 LAYER M3 ;
			RECT 0.0714 42.4031 0.1097 42.5035 ;
			 LAYER V2 ;
			RECT 0.0831 42.4153 0.098 42.4278 ;
		END

		ANTENNAGATEAREA 0.00027817 ;
		ANTENNADIFFAREA 0.00194719 ;
		ANTENNAPARTIALMETALAREA 0.00195671 ;
	END EMAW[0]

	PIN EMAW[1]
		USE SIGNAL ;
		DIRECTION INPUT ;
		SHAPE ABUTMENT ;
		PORT
			 LAYER M2 ;
			RECT 0.0098 42.4659 0.0481 42.5035 ;
			 LAYER M3 ;
			RECT 0.0098 42.4031 0.0481 42.5035 ;
			 LAYER V2 ;
			RECT 0.0215 42.478 0.0364 42.4906 ;
		END

		ANTENNAGATEAREA 0.00027817 ;
		ANTENNADIFFAREA 0.00194719 ;
		ANTENNAPARTIALMETALAREA 0.00195671 ;
	END EMAW[1]

	PIN EMA[0]
		USE SIGNAL ;
		DIRECTION INPUT ;
		SHAPE ABUTMENT ;
		PORT
			 LAYER M2 ;
			RECT 0.0098 42.1647 0.0481 42.2024 ;
			 LAYER M3 ;
			RECT 0.0098 42.102 0.0481 42.2024 ;
			 LAYER V2 ;
			RECT 0.0215 42.1769 0.0364 42.1894 ;
		END

		ANTENNAGATEAREA 0.00027817 ;
		ANTENNADIFFAREA 0.00194719 ;
		ANTENNAPARTIALMETALAREA 0.00195671 ;
	END EMA[0]

	PIN EMA[1]
		USE SIGNAL ;
		DIRECTION INPUT ;
		SHAPE ABUTMENT ;
		PORT
			 LAYER M2 ;
			RECT 0.0714 42.2525 0.1097 42.2902 ;
			 LAYER M3 ;
			RECT 0.0714 42.2525 0.1097 42.3529 ;
			 LAYER V2 ;
			RECT 0.0831 42.2647 0.098 42.2773 ;
		END

		ANTENNAGATEAREA 0.00027817 ;
		ANTENNADIFFAREA 0.00194719 ;
		ANTENNAPARTIALMETALAREA 0.00195671 ;
	END EMA[1]

	PIN EMA[2]
		USE SIGNAL ;
		DIRECTION INPUT ;
		SHAPE ABUTMENT ;
		PORT
			 LAYER M2 ;
			RECT 0.0714 43.1561 0.1097 43.1937 ;
			 LAYER M3 ;
			RECT 0.0714 43.1561 0.1097 43.2565 ;
			 LAYER V2 ;
			RECT 0.0831 43.1682 0.098 43.1808 ;
		END

		ANTENNAGATEAREA 0.00027817 ;
		ANTENNADIFFAREA 0.00194719 ;
		ANTENNAPARTIALMETALAREA 0.00195671 ;
	END EMA[2]

	PIN GWEN
		USE SIGNAL ;
		DIRECTION INPUT ;
		SHAPE ABUTMENT ;
		PORT
			 LAYER M2 ;
			RECT 0.0098 43.0682 0.0481 43.1059 ;
			 LAYER M3 ;
			RECT 0.0098 43.0055 0.0481 43.1059 ;
			 LAYER V2 ;
			RECT 0.0215 43.0804 0.0364 43.0929 ;
		END

		ANTENNAGATEAREA 0.00027817 ;
		ANTENNADIFFAREA 0.00194719 ;
		ANTENNAPARTIALMETALAREA 0.00195671 ;
	END GWEN

	PIN GWENY
		USE SIGNAL ;
		DIRECTION OUTPUT ;
		SHAPE ABUTMENT ;
		PORT
			 LAYER M2 ;
			RECT 0.0714 43.7584 0.1097 43.7961 ;
			 LAYER M3 ;
			RECT 0.0714 43.7584 0.1097 43.8588 ;
			 LAYER V2 ;
			RECT 0.0831 43.7706 0.098 43.7831 ;
		END

		ANTENNADIFFAREA 0.00194719 ;
		ANTENNAPARTIALMETALAREA 0.00195671 ;
	END GWENY

	PIN Q[0]
		USE SIGNAL ;
		DIRECTION OUTPUT ;
		SHAPE ABUTMENT ;
		PORT
			 LAYER M2 ;
			RECT 0.0098 1.0918 0.0481 1.1922 ;
			 LAYER M3 ;
			RECT 0.0098 1.0918 0.0481 1.1922 ;
			 LAYER V2 ;
			RECT 0.021 1.1667 0.0359 1.1792 ;
		END

		ANTENNADIFFAREA 0.00194719 ;
		ANTENNAPARTIALMETALAREA 0.00195671 ;
	END Q[0]

	PIN Q[10]
		USE SIGNAL ;
		DIRECTION OUTPUT ;
		SHAPE ABUTMENT ;
		PORT
			 LAYER M2 ;
			RECT 0.0098 13.8918 0.0481 13.9922 ;
			 LAYER M3 ;
			RECT 0.0098 13.8918 0.0481 13.9922 ;
			 LAYER V2 ;
			RECT 0.021 13.9667 0.0359 13.9792 ;
		END

		ANTENNADIFFAREA 0.00194719 ;
		ANTENNAPARTIALMETALAREA 0.00195671 ;
	END Q[10]

	PIN Q[11]
		USE SIGNAL ;
		DIRECTION OUTPUT ;
		SHAPE ABUTMENT ;
		PORT
			 LAYER M2 ;
			RECT 0.0098 15.1718 0.0481 15.2722 ;
			 LAYER M3 ;
			RECT 0.0098 15.1718 0.0481 15.2722 ;
			 LAYER V2 ;
			RECT 0.021 15.2467 0.0359 15.2592 ;
		END

		ANTENNADIFFAREA 0.00194719 ;
		ANTENNAPARTIALMETALAREA 0.00195671 ;
	END Q[11]

	PIN Q[12]
		USE SIGNAL ;
		DIRECTION OUTPUT ;
		SHAPE ABUTMENT ;
		PORT
			 LAYER M2 ;
			RECT 0.0098 16.4518 0.0481 16.5522 ;
			 LAYER M3 ;
			RECT 0.0098 16.4518 0.0481 16.5522 ;
			 LAYER V2 ;
			RECT 0.021 16.5267 0.0359 16.5392 ;
		END

		ANTENNADIFFAREA 0.00194719 ;
		ANTENNAPARTIALMETALAREA 0.00195671 ;
	END Q[12]

	PIN Q[13]
		USE SIGNAL ;
		DIRECTION OUTPUT ;
		SHAPE ABUTMENT ;
		PORT
			 LAYER M2 ;
			RECT 0.0098 17.7318 0.0481 17.8322 ;
			 LAYER M3 ;
			RECT 0.0098 17.7318 0.0481 17.8322 ;
			 LAYER V2 ;
			RECT 0.021 17.8067 0.0359 17.8192 ;
		END

		ANTENNADIFFAREA 0.00194719 ;
		ANTENNAPARTIALMETALAREA 0.00195671 ;
	END Q[13]

	PIN Q[14]
		USE SIGNAL ;
		DIRECTION OUTPUT ;
		SHAPE ABUTMENT ;
		PORT
			 LAYER M2 ;
			RECT 0.0098 19.0118 0.0481 19.1122 ;
			 LAYER M3 ;
			RECT 0.0098 19.0118 0.0481 19.1122 ;
			 LAYER V2 ;
			RECT 0.021 19.0867 0.0359 19.0992 ;
		END

		ANTENNADIFFAREA 0.00194719 ;
		ANTENNAPARTIALMETALAREA 0.00195671 ;
	END Q[14]

	PIN Q[15]
		USE SIGNAL ;
		DIRECTION OUTPUT ;
		SHAPE ABUTMENT ;
		PORT
			 LAYER M2 ;
			RECT 0.0098 20.2918 0.0481 20.3922 ;
			 LAYER M3 ;
			RECT 0.0098 20.2918 0.0481 20.3922 ;
			 LAYER V2 ;
			RECT 0.021 20.3667 0.0359 20.3792 ;
		END

		ANTENNADIFFAREA 0.00194719 ;
		ANTENNAPARTIALMETALAREA 0.00195671 ;
	END Q[15]

	PIN Q[16]
		USE SIGNAL ;
		DIRECTION OUTPUT ;
		SHAPE ABUTMENT ;
		PORT
			 LAYER M2 ;
			RECT 0.0098 21.5718 0.0481 21.6722 ;
			 LAYER M3 ;
			RECT 0.0098 21.5718 0.0481 21.6722 ;
			 LAYER V2 ;
			RECT 0.021 21.6467 0.0359 21.6592 ;
		END

		ANTENNADIFFAREA 0.00194719 ;
		ANTENNAPARTIALMETALAREA 0.00195671 ;
	END Q[16]

	PIN Q[17]
		USE SIGNAL ;
		DIRECTION OUTPUT ;
		SHAPE ABUTMENT ;
		PORT
			 LAYER M2 ;
			RECT 0.0098 22.8518 0.0481 22.9522 ;
			 LAYER M3 ;
			RECT 0.0098 22.8518 0.0481 22.9522 ;
			 LAYER V2 ;
			RECT 0.021 22.9267 0.0359 22.9392 ;
		END

		ANTENNADIFFAREA 0.00194719 ;
		ANTENNAPARTIALMETALAREA 0.00195671 ;
	END Q[17]

	PIN Q[18]
		USE SIGNAL ;
		DIRECTION OUTPUT ;
		SHAPE ABUTMENT ;
		PORT
			 LAYER M2 ;
			RECT 0.0098 24.1318 0.0481 24.2322 ;
			 LAYER M3 ;
			RECT 0.0098 24.1318 0.0481 24.2322 ;
			 LAYER V2 ;
			RECT 0.021 24.2067 0.0359 24.2192 ;
		END

		ANTENNADIFFAREA 0.00194719 ;
		ANTENNAPARTIALMETALAREA 0.00195671 ;
	END Q[18]

	PIN Q[19]
		USE SIGNAL ;
		DIRECTION OUTPUT ;
		SHAPE ABUTMENT ;
		PORT
			 LAYER M2 ;
			RECT 0.0098 25.4118 0.0481 25.5122 ;
			 LAYER M3 ;
			RECT 0.0098 25.4118 0.0481 25.5122 ;
			 LAYER V2 ;
			RECT 0.021 25.4867 0.0359 25.4992 ;
		END

		ANTENNADIFFAREA 0.00194719 ;
		ANTENNAPARTIALMETALAREA 0.00195671 ;
	END Q[19]

	PIN Q[1]
		USE SIGNAL ;
		DIRECTION OUTPUT ;
		SHAPE ABUTMENT ;
		PORT
			 LAYER M2 ;
			RECT 0.0098 2.3718 0.0481 2.4722 ;
			 LAYER M3 ;
			RECT 0.0098 2.3718 0.0481 2.4722 ;
			 LAYER V2 ;
			RECT 0.021 2.4467 0.0359 2.4592 ;
		END

		ANTENNADIFFAREA 0.00194719 ;
		ANTENNAPARTIALMETALAREA 0.00195671 ;
	END Q[1]

	PIN Q[20]
		USE SIGNAL ;
		DIRECTION OUTPUT ;
		SHAPE ABUTMENT ;
		PORT
			 LAYER M2 ;
			RECT 0.0098 26.6918 0.0481 26.7922 ;
			 LAYER M3 ;
			RECT 0.0098 26.6918 0.0481 26.7922 ;
			 LAYER V2 ;
			RECT 0.021 26.7667 0.0359 26.7792 ;
		END

		ANTENNADIFFAREA 0.00194719 ;
		ANTENNAPARTIALMETALAREA 0.00195671 ;
	END Q[20]

	PIN Q[21]
		USE SIGNAL ;
		DIRECTION OUTPUT ;
		SHAPE ABUTMENT ;
		PORT
			 LAYER M2 ;
			RECT 0.0098 27.9718 0.0481 28.0722 ;
			 LAYER M3 ;
			RECT 0.0098 27.9718 0.0481 28.0722 ;
			 LAYER V2 ;
			RECT 0.021 28.0467 0.0359 28.0592 ;
		END

		ANTENNADIFFAREA 0.00194719 ;
		ANTENNAPARTIALMETALAREA 0.00195671 ;
	END Q[21]

	PIN Q[22]
		USE SIGNAL ;
		DIRECTION OUTPUT ;
		SHAPE ABUTMENT ;
		PORT
			 LAYER M2 ;
			RECT 0.0098 29.2518 0.0481 29.3522 ;
			 LAYER M3 ;
			RECT 0.0098 29.2518 0.0481 29.3522 ;
			 LAYER V2 ;
			RECT 0.021 29.3267 0.0359 29.3392 ;
		END

		ANTENNADIFFAREA 0.00194719 ;
		ANTENNAPARTIALMETALAREA 0.00195671 ;
	END Q[22]

	PIN Q[23]
		USE SIGNAL ;
		DIRECTION OUTPUT ;
		SHAPE ABUTMENT ;
		PORT
			 LAYER M2 ;
			RECT 0.0098 30.5318 0.0481 30.6322 ;
			 LAYER M3 ;
			RECT 0.0098 30.5318 0.0481 30.6322 ;
			 LAYER V2 ;
			RECT 0.021 30.6067 0.0359 30.6192 ;
		END

		ANTENNADIFFAREA 0.00194719 ;
		ANTENNAPARTIALMETALAREA 0.00195671 ;
	END Q[23]

	PIN Q[24]
		USE SIGNAL ;
		DIRECTION OUTPUT ;
		SHAPE ABUTMENT ;
		PORT
			 LAYER M2 ;
			RECT 0.0098 31.8118 0.0481 31.9122 ;
			 LAYER M3 ;
			RECT 0.0098 31.8118 0.0481 31.9122 ;
			 LAYER V2 ;
			RECT 0.021 31.8867 0.0359 31.8992 ;
		END

		ANTENNADIFFAREA 0.00194719 ;
		ANTENNAPARTIALMETALAREA 0.00195671 ;
	END Q[24]

	PIN Q[25]
		USE SIGNAL ;
		DIRECTION OUTPUT ;
		SHAPE ABUTMENT ;
		PORT
			 LAYER M2 ;
			RECT 0.0098 33.0918 0.0481 33.1922 ;
			 LAYER M3 ;
			RECT 0.0098 33.0918 0.0481 33.1922 ;
			 LAYER V2 ;
			RECT 0.021 33.1667 0.0359 33.1792 ;
		END

		ANTENNADIFFAREA 0.00194719 ;
		ANTENNAPARTIALMETALAREA 0.00195671 ;
	END Q[25]

	PIN Q[26]
		USE SIGNAL ;
		DIRECTION OUTPUT ;
		SHAPE ABUTMENT ;
		PORT
			 LAYER M2 ;
			RECT 0.0098 34.3718 0.0481 34.4722 ;
			 LAYER M3 ;
			RECT 0.0098 34.3718 0.0481 34.4722 ;
			 LAYER V2 ;
			RECT 0.021 34.4467 0.0359 34.4592 ;
		END

		ANTENNADIFFAREA 0.00194719 ;
		ANTENNAPARTIALMETALAREA 0.00195671 ;
	END Q[26]

	PIN Q[27]
		USE SIGNAL ;
		DIRECTION OUTPUT ;
		SHAPE ABUTMENT ;
		PORT
			 LAYER M2 ;
			RECT 0.0098 35.6518 0.0481 35.7522 ;
			 LAYER M3 ;
			RECT 0.0098 35.6518 0.0481 35.7522 ;
			 LAYER V2 ;
			RECT 0.021 35.7267 0.0359 35.7392 ;
		END

		ANTENNADIFFAREA 0.00194719 ;
		ANTENNAPARTIALMETALAREA 0.00195671 ;
	END Q[27]

	PIN Q[28]
		USE SIGNAL ;
		DIRECTION OUTPUT ;
		SHAPE ABUTMENT ;
		PORT
			 LAYER M2 ;
			RECT 0.0098 36.9318 0.0481 37.0322 ;
			 LAYER M3 ;
			RECT 0.0098 36.9318 0.0481 37.0322 ;
			 LAYER V2 ;
			RECT 0.021 37.0067 0.0359 37.0192 ;
		END

		ANTENNADIFFAREA 0.00194719 ;
		ANTENNAPARTIALMETALAREA 0.00195671 ;
	END Q[28]

	PIN Q[29]
		USE SIGNAL ;
		DIRECTION OUTPUT ;
		SHAPE ABUTMENT ;
		PORT
			 LAYER M2 ;
			RECT 0.0098 38.2118 0.0481 38.3122 ;
			 LAYER M3 ;
			RECT 0.0098 38.2118 0.0481 38.3122 ;
			 LAYER V2 ;
			RECT 0.021 38.2867 0.0359 38.2992 ;
		END

		ANTENNADIFFAREA 0.00194719 ;
		ANTENNAPARTIALMETALAREA 0.00195671 ;
	END Q[29]

	PIN Q[2]
		USE SIGNAL ;
		DIRECTION OUTPUT ;
		SHAPE ABUTMENT ;
		PORT
			 LAYER M2 ;
			RECT 0.0098 3.6518 0.0481 3.7522 ;
			 LAYER M3 ;
			RECT 0.0098 3.6518 0.0481 3.7522 ;
			 LAYER V2 ;
			RECT 0.021 3.7267 0.0359 3.7392 ;
		END

		ANTENNADIFFAREA 0.00194719 ;
		ANTENNAPARTIALMETALAREA 0.00195671 ;
	END Q[2]

	PIN Q[30]
		USE SIGNAL ;
		DIRECTION OUTPUT ;
		SHAPE ABUTMENT ;
		PORT
			 LAYER M2 ;
			RECT 0.0098 39.4918 0.0481 39.5922 ;
			 LAYER M3 ;
			RECT 0.0098 39.4918 0.0481 39.5922 ;
			 LAYER V2 ;
			RECT 0.021 39.5667 0.0359 39.5792 ;
		END

		ANTENNADIFFAREA 0.00194719 ;
		ANTENNAPARTIALMETALAREA 0.00195671 ;
	END Q[30]

	PIN Q[31]
		USE SIGNAL ;
		DIRECTION OUTPUT ;
		SHAPE ABUTMENT ;
		PORT
			 LAYER M2 ;
			RECT 0.0098 40.7718 0.0481 40.8722 ;
			 LAYER M3 ;
			RECT 0.0098 40.7718 0.0481 40.8722 ;
			 LAYER V2 ;
			RECT 0.021 40.8467 0.0359 40.8592 ;
		END

		ANTENNADIFFAREA 0.00194719 ;
		ANTENNAPARTIALMETALAREA 0.00195671 ;
	END Q[31]

	PIN Q[32]
		USE SIGNAL ;
		DIRECTION OUTPUT ;
		SHAPE ABUTMENT ;
		PORT
			 LAYER M2 ;
			RECT 0.0098 49.1984 0.0481 49.2988 ;
			 LAYER M3 ;
			RECT 0.0098 49.1984 0.0481 49.2988 ;
			 LAYER V2 ;
			RECT 0.021 49.2114 0.0359 49.2239 ;
		END

		ANTENNADIFFAREA 0.00194719 ;
		ANTENNAPARTIALMETALAREA 0.00195671 ;
	END Q[32]

	PIN Q[33]
		USE SIGNAL ;
		DIRECTION OUTPUT ;
		SHAPE ABUTMENT ;
		PORT
			 LAYER M2 ;
			RECT 0.0098 50.4784 0.0481 50.5788 ;
			 LAYER M3 ;
			RECT 0.0098 50.4784 0.0481 50.5788 ;
			 LAYER V2 ;
			RECT 0.021 50.4914 0.0359 50.5039 ;
		END

		ANTENNADIFFAREA 0.00194719 ;
		ANTENNAPARTIALMETALAREA 0.00195671 ;
	END Q[33]

	PIN Q[34]
		USE SIGNAL ;
		DIRECTION OUTPUT ;
		SHAPE ABUTMENT ;
		PORT
			 LAYER M2 ;
			RECT 0.0098 51.7584 0.0481 51.8588 ;
			 LAYER M3 ;
			RECT 0.0098 51.7584 0.0481 51.8588 ;
			 LAYER V2 ;
			RECT 0.021 51.7714 0.0359 51.7839 ;
		END

		ANTENNADIFFAREA 0.00194719 ;
		ANTENNAPARTIALMETALAREA 0.00195671 ;
	END Q[34]

	PIN Q[35]
		USE SIGNAL ;
		DIRECTION OUTPUT ;
		SHAPE ABUTMENT ;
		PORT
			 LAYER M2 ;
			RECT 0.0098 53.0384 0.0481 53.1388 ;
			 LAYER M3 ;
			RECT 0.0098 53.0384 0.0481 53.1388 ;
			 LAYER V2 ;
			RECT 0.021 53.0514 0.0359 53.0639 ;
		END

		ANTENNADIFFAREA 0.00194719 ;
		ANTENNAPARTIALMETALAREA 0.00195671 ;
	END Q[35]

	PIN Q[36]
		USE SIGNAL ;
		DIRECTION OUTPUT ;
		SHAPE ABUTMENT ;
		PORT
			 LAYER M2 ;
			RECT 0.0098 54.3184 0.0481 54.4188 ;
			 LAYER M3 ;
			RECT 0.0098 54.3184 0.0481 54.4188 ;
			 LAYER V2 ;
			RECT 0.021 54.3314 0.0359 54.3439 ;
		END

		ANTENNADIFFAREA 0.00194719 ;
		ANTENNAPARTIALMETALAREA 0.00195671 ;
	END Q[36]

	PIN Q[37]
		USE SIGNAL ;
		DIRECTION OUTPUT ;
		SHAPE ABUTMENT ;
		PORT
			 LAYER M2 ;
			RECT 0.0098 55.5984 0.0481 55.6988 ;
			 LAYER M3 ;
			RECT 0.0098 55.5984 0.0481 55.6988 ;
			 LAYER V2 ;
			RECT 0.021 55.6114 0.0359 55.6239 ;
		END

		ANTENNADIFFAREA 0.00194719 ;
		ANTENNAPARTIALMETALAREA 0.00195671 ;
	END Q[37]

	PIN Q[38]
		USE SIGNAL ;
		DIRECTION OUTPUT ;
		SHAPE ABUTMENT ;
		PORT
			 LAYER M2 ;
			RECT 0.0098 56.8784 0.0481 56.9788 ;
			 LAYER M3 ;
			RECT 0.0098 56.8784 0.0481 56.9788 ;
			 LAYER V2 ;
			RECT 0.021 56.8914 0.0359 56.9039 ;
		END

		ANTENNADIFFAREA 0.00194719 ;
		ANTENNAPARTIALMETALAREA 0.00195671 ;
	END Q[38]

	PIN Q[39]
		USE SIGNAL ;
		DIRECTION OUTPUT ;
		SHAPE ABUTMENT ;
		PORT
			 LAYER M2 ;
			RECT 0.0098 58.1584 0.0481 58.2588 ;
			 LAYER M3 ;
			RECT 0.0098 58.1584 0.0481 58.2588 ;
			 LAYER V2 ;
			RECT 0.021 58.1714 0.0359 58.1839 ;
		END

		ANTENNADIFFAREA 0.00194719 ;
		ANTENNAPARTIALMETALAREA 0.00195671 ;
	END Q[39]

	PIN Q[3]
		USE SIGNAL ;
		DIRECTION OUTPUT ;
		SHAPE ABUTMENT ;
		PORT
			 LAYER M2 ;
			RECT 0.0098 4.9318 0.0481 5.0322 ;
			 LAYER M3 ;
			RECT 0.0098 4.9318 0.0481 5.0322 ;
			 LAYER V2 ;
			RECT 0.021 5.0067 0.0359 5.0192 ;
		END

		ANTENNADIFFAREA 0.00194719 ;
		ANTENNAPARTIALMETALAREA 0.00195671 ;
	END Q[3]

	PIN Q[40]
		USE SIGNAL ;
		DIRECTION OUTPUT ;
		SHAPE ABUTMENT ;
		PORT
			 LAYER M2 ;
			RECT 0.0098 59.4384 0.0481 59.5388 ;
			 LAYER M3 ;
			RECT 0.0098 59.4384 0.0481 59.5388 ;
			 LAYER V2 ;
			RECT 0.021 59.4514 0.0359 59.4639 ;
		END

		ANTENNADIFFAREA 0.00194719 ;
		ANTENNAPARTIALMETALAREA 0.00195671 ;
	END Q[40]

	PIN Q[41]
		USE SIGNAL ;
		DIRECTION OUTPUT ;
		SHAPE ABUTMENT ;
		PORT
			 LAYER M2 ;
			RECT 0.0098 60.7184 0.0481 60.8188 ;
			 LAYER M3 ;
			RECT 0.0098 60.7184 0.0481 60.8188 ;
			 LAYER V2 ;
			RECT 0.021 60.7314 0.0359 60.7439 ;
		END

		ANTENNADIFFAREA 0.00194719 ;
		ANTENNAPARTIALMETALAREA 0.00195671 ;
	END Q[41]

	PIN Q[42]
		USE SIGNAL ;
		DIRECTION OUTPUT ;
		SHAPE ABUTMENT ;
		PORT
			 LAYER M2 ;
			RECT 0.0098 61.9984 0.0481 62.0988 ;
			 LAYER M3 ;
			RECT 0.0098 61.9984 0.0481 62.0988 ;
			 LAYER V2 ;
			RECT 0.021 62.0114 0.0359 62.0239 ;
		END

		ANTENNADIFFAREA 0.00194719 ;
		ANTENNAPARTIALMETALAREA 0.00195671 ;
	END Q[42]

	PIN Q[43]
		USE SIGNAL ;
		DIRECTION OUTPUT ;
		SHAPE ABUTMENT ;
		PORT
			 LAYER M2 ;
			RECT 0.0098 63.2784 0.0481 63.3788 ;
			 LAYER M3 ;
			RECT 0.0098 63.2784 0.0481 63.3788 ;
			 LAYER V2 ;
			RECT 0.021 63.2914 0.0359 63.3039 ;
		END

		ANTENNADIFFAREA 0.00194719 ;
		ANTENNAPARTIALMETALAREA 0.00195671 ;
	END Q[43]

	PIN Q[44]
		USE SIGNAL ;
		DIRECTION OUTPUT ;
		SHAPE ABUTMENT ;
		PORT
			 LAYER M2 ;
			RECT 0.0098 64.5584 0.0481 64.6588 ;
			 LAYER M3 ;
			RECT 0.0098 64.5584 0.0481 64.6588 ;
			 LAYER V2 ;
			RECT 0.021 64.5714 0.0359 64.5839 ;
		END

		ANTENNADIFFAREA 0.00194719 ;
		ANTENNAPARTIALMETALAREA 0.00195671 ;
	END Q[44]

	PIN Q[45]
		USE SIGNAL ;
		DIRECTION OUTPUT ;
		SHAPE ABUTMENT ;
		PORT
			 LAYER M2 ;
			RECT 0.0098 65.8384 0.0481 65.9388 ;
			 LAYER M3 ;
			RECT 0.0098 65.8384 0.0481 65.9388 ;
			 LAYER V2 ;
			RECT 0.021 65.8514 0.0359 65.8639 ;
		END

		ANTENNADIFFAREA 0.00194719 ;
		ANTENNAPARTIALMETALAREA 0.00195671 ;
	END Q[45]

	PIN Q[46]
		USE SIGNAL ;
		DIRECTION OUTPUT ;
		SHAPE ABUTMENT ;
		PORT
			 LAYER M2 ;
			RECT 0.0098 67.1184 0.0481 67.2188 ;
			 LAYER M3 ;
			RECT 0.0098 67.1184 0.0481 67.2188 ;
			 LAYER V2 ;
			RECT 0.021 67.1314 0.0359 67.1439 ;
		END

		ANTENNADIFFAREA 0.00194719 ;
		ANTENNAPARTIALMETALAREA 0.00195671 ;
	END Q[46]

	PIN Q[47]
		USE SIGNAL ;
		DIRECTION OUTPUT ;
		SHAPE ABUTMENT ;
		PORT
			 LAYER M2 ;
			RECT 0.0098 68.3984 0.0481 68.4988 ;
			 LAYER M3 ;
			RECT 0.0098 68.3984 0.0481 68.4988 ;
			 LAYER V2 ;
			RECT 0.021 68.4114 0.0359 68.4239 ;
		END

		ANTENNADIFFAREA 0.00194719 ;
		ANTENNAPARTIALMETALAREA 0.00195671 ;
	END Q[47]

	PIN Q[48]
		USE SIGNAL ;
		DIRECTION OUTPUT ;
		SHAPE ABUTMENT ;
		PORT
			 LAYER M2 ;
			RECT 0.0098 69.6784 0.0481 69.7788 ;
			 LAYER M3 ;
			RECT 0.0098 69.6784 0.0481 69.7788 ;
			 LAYER V2 ;
			RECT 0.021 69.6914 0.0359 69.7039 ;
		END

		ANTENNADIFFAREA 0.00194719 ;
		ANTENNAPARTIALMETALAREA 0.00195671 ;
	END Q[48]

	PIN Q[49]
		USE SIGNAL ;
		DIRECTION OUTPUT ;
		SHAPE ABUTMENT ;
		PORT
			 LAYER M2 ;
			RECT 0.0098 70.9584 0.0481 71.0588 ;
			 LAYER M3 ;
			RECT 0.0098 70.9584 0.0481 71.0588 ;
			 LAYER V2 ;
			RECT 0.021 70.9714 0.0359 70.9839 ;
		END

		ANTENNADIFFAREA 0.00194719 ;
		ANTENNAPARTIALMETALAREA 0.00195671 ;
	END Q[49]

	PIN Q[4]
		USE SIGNAL ;
		DIRECTION OUTPUT ;
		SHAPE ABUTMENT ;
		PORT
			 LAYER M2 ;
			RECT 0.0098 6.2118 0.0481 6.3122 ;
			 LAYER M3 ;
			RECT 0.0098 6.2118 0.0481 6.3122 ;
			 LAYER V2 ;
			RECT 0.021 6.2867 0.0359 6.2992 ;
		END

		ANTENNADIFFAREA 0.00194719 ;
		ANTENNAPARTIALMETALAREA 0.00195671 ;
	END Q[4]

	PIN Q[50]
		USE SIGNAL ;
		DIRECTION OUTPUT ;
		SHAPE ABUTMENT ;
		PORT
			 LAYER M2 ;
			RECT 0.0098 72.2384 0.0481 72.3388 ;
			 LAYER M3 ;
			RECT 0.0098 72.2384 0.0481 72.3388 ;
			 LAYER V2 ;
			RECT 0.021 72.2514 0.0359 72.2639 ;
		END

		ANTENNADIFFAREA 0.00194719 ;
		ANTENNAPARTIALMETALAREA 0.00195671 ;
	END Q[50]

	PIN Q[51]
		USE SIGNAL ;
		DIRECTION OUTPUT ;
		SHAPE ABUTMENT ;
		PORT
			 LAYER M2 ;
			RECT 0.0098 73.5184 0.0481 73.6188 ;
			 LAYER M3 ;
			RECT 0.0098 73.5184 0.0481 73.6188 ;
			 LAYER V2 ;
			RECT 0.021 73.5314 0.0359 73.5439 ;
		END

		ANTENNADIFFAREA 0.00194719 ;
		ANTENNAPARTIALMETALAREA 0.00195671 ;
	END Q[51]

	PIN Q[52]
		USE SIGNAL ;
		DIRECTION OUTPUT ;
		SHAPE ABUTMENT ;
		PORT
			 LAYER M2 ;
			RECT 0.0098 74.7984 0.0481 74.8988 ;
			 LAYER M3 ;
			RECT 0.0098 74.7984 0.0481 74.8988 ;
			 LAYER V2 ;
			RECT 0.021 74.8114 0.0359 74.8239 ;
		END

		ANTENNADIFFAREA 0.00194719 ;
		ANTENNAPARTIALMETALAREA 0.00195671 ;
	END Q[52]

	PIN Q[53]
		USE SIGNAL ;
		DIRECTION OUTPUT ;
		SHAPE ABUTMENT ;
		PORT
			 LAYER M2 ;
			RECT 0.0098 76.0784 0.0481 76.1788 ;
			 LAYER M3 ;
			RECT 0.0098 76.0784 0.0481 76.1788 ;
			 LAYER V2 ;
			RECT 0.021 76.0914 0.0359 76.1039 ;
		END

		ANTENNADIFFAREA 0.00194719 ;
		ANTENNAPARTIALMETALAREA 0.00195671 ;
	END Q[53]

	PIN Q[54]
		USE SIGNAL ;
		DIRECTION OUTPUT ;
		SHAPE ABUTMENT ;
		PORT
			 LAYER M2 ;
			RECT 0.0098 77.3584 0.0481 77.4588 ;
			 LAYER M3 ;
			RECT 0.0098 77.3584 0.0481 77.4588 ;
			 LAYER V2 ;
			RECT 0.021 77.3714 0.0359 77.3839 ;
		END

		ANTENNADIFFAREA 0.00194719 ;
		ANTENNAPARTIALMETALAREA 0.00195671 ;
	END Q[54]

	PIN Q[55]
		USE SIGNAL ;
		DIRECTION OUTPUT ;
		SHAPE ABUTMENT ;
		PORT
			 LAYER M2 ;
			RECT 0.0098 78.6384 0.0481 78.7388 ;
			 LAYER M3 ;
			RECT 0.0098 78.6384 0.0481 78.7388 ;
			 LAYER V2 ;
			RECT 0.021 78.6514 0.0359 78.6639 ;
		END

		ANTENNADIFFAREA 0.00194719 ;
		ANTENNAPARTIALMETALAREA 0.00195671 ;
	END Q[55]

	PIN Q[56]
		USE SIGNAL ;
		DIRECTION OUTPUT ;
		SHAPE ABUTMENT ;
		PORT
			 LAYER M2 ;
			RECT 0.0098 79.9184 0.0481 80.0188 ;
			 LAYER M3 ;
			RECT 0.0098 79.9184 0.0481 80.0188 ;
			 LAYER V2 ;
			RECT 0.021 79.9314 0.0359 79.9439 ;
		END

		ANTENNADIFFAREA 0.00194719 ;
		ANTENNAPARTIALMETALAREA 0.00195671 ;
	END Q[56]

	PIN Q[57]
		USE SIGNAL ;
		DIRECTION OUTPUT ;
		SHAPE ABUTMENT ;
		PORT
			 LAYER M2 ;
			RECT 0.0098 81.1984 0.0481 81.2988 ;
			 LAYER M3 ;
			RECT 0.0098 81.1984 0.0481 81.2988 ;
			 LAYER V2 ;
			RECT 0.021 81.2114 0.0359 81.2239 ;
		END

		ANTENNADIFFAREA 0.00194719 ;
		ANTENNAPARTIALMETALAREA 0.00195671 ;
	END Q[57]

	PIN Q[58]
		USE SIGNAL ;
		DIRECTION OUTPUT ;
		SHAPE ABUTMENT ;
		PORT
			 LAYER M2 ;
			RECT 0.0098 82.4784 0.0481 82.5788 ;
			 LAYER M3 ;
			RECT 0.0098 82.4784 0.0481 82.5788 ;
			 LAYER V2 ;
			RECT 0.021 82.4914 0.0359 82.5039 ;
		END

		ANTENNADIFFAREA 0.00194719 ;
		ANTENNAPARTIALMETALAREA 0.00195671 ;
	END Q[58]

	PIN Q[59]
		USE SIGNAL ;
		DIRECTION OUTPUT ;
		SHAPE ABUTMENT ;
		PORT
			 LAYER M2 ;
			RECT 0.0098 83.7584 0.0481 83.8588 ;
			 LAYER M3 ;
			RECT 0.0098 83.7584 0.0481 83.8588 ;
			 LAYER V2 ;
			RECT 0.021 83.7714 0.0359 83.7839 ;
		END

		ANTENNADIFFAREA 0.00194719 ;
		ANTENNAPARTIALMETALAREA 0.00195671 ;
	END Q[59]

	PIN Q[5]
		USE SIGNAL ;
		DIRECTION OUTPUT ;
		SHAPE ABUTMENT ;
		PORT
			 LAYER M2 ;
			RECT 0.0098 7.4918 0.0481 7.5922 ;
			 LAYER M3 ;
			RECT 0.0098 7.4918 0.0481 7.5922 ;
			 LAYER V2 ;
			RECT 0.021 7.5667 0.0359 7.5792 ;
		END

		ANTENNADIFFAREA 0.00194719 ;
		ANTENNAPARTIALMETALAREA 0.00195671 ;
	END Q[5]

	PIN Q[60]
		USE SIGNAL ;
		DIRECTION OUTPUT ;
		SHAPE ABUTMENT ;
		PORT
			 LAYER M2 ;
			RECT 0.0098 85.0384 0.0481 85.1388 ;
			 LAYER M3 ;
			RECT 0.0098 85.0384 0.0481 85.1388 ;
			 LAYER V2 ;
			RECT 0.021 85.0514 0.0359 85.0639 ;
		END

		ANTENNADIFFAREA 0.00194719 ;
		ANTENNAPARTIALMETALAREA 0.00195671 ;
	END Q[60]

	PIN Q[61]
		USE SIGNAL ;
		DIRECTION OUTPUT ;
		SHAPE ABUTMENT ;
		PORT
			 LAYER M2 ;
			RECT 0.0098 86.3184 0.0481 86.4188 ;
			 LAYER M3 ;
			RECT 0.0098 86.3184 0.0481 86.4188 ;
			 LAYER V2 ;
			RECT 0.021 86.3314 0.0359 86.3439 ;
		END

		ANTENNADIFFAREA 0.00194719 ;
		ANTENNAPARTIALMETALAREA 0.00195671 ;
	END Q[61]

	PIN Q[62]
		USE SIGNAL ;
		DIRECTION OUTPUT ;
		SHAPE ABUTMENT ;
		PORT
			 LAYER M2 ;
			RECT 0.0098 87.5984 0.0481 87.6988 ;
			 LAYER M3 ;
			RECT 0.0098 87.5984 0.0481 87.6988 ;
			 LAYER V2 ;
			RECT 0.021 87.6114 0.0359 87.6239 ;
		END

		ANTENNADIFFAREA 0.00194719 ;
		ANTENNAPARTIALMETALAREA 0.00195671 ;
	END Q[62]

	PIN Q[63]
		USE SIGNAL ;
		DIRECTION OUTPUT ;
		SHAPE ABUTMENT ;
		PORT
			 LAYER M2 ;
			RECT 0.0098 88.8784 0.0481 88.9788 ;
			 LAYER M3 ;
			RECT 0.0098 88.8784 0.0481 88.9788 ;
			 LAYER V2 ;
			RECT 0.021 88.8914 0.0359 88.9039 ;
		END

		ANTENNADIFFAREA 0.00194719 ;
		ANTENNAPARTIALMETALAREA 0.00195671 ;
	END Q[63]

	PIN Q[6]
		USE SIGNAL ;
		DIRECTION OUTPUT ;
		SHAPE ABUTMENT ;
		PORT
			 LAYER M2 ;
			RECT 0.0098 8.7718 0.0481 8.8722 ;
			 LAYER M3 ;
			RECT 0.0098 8.7718 0.0481 8.8722 ;
			 LAYER V2 ;
			RECT 0.021 8.8467 0.0359 8.8592 ;
		END

		ANTENNADIFFAREA 0.00194719 ;
		ANTENNAPARTIALMETALAREA 0.00195671 ;
	END Q[6]

	PIN Q[7]
		USE SIGNAL ;
		DIRECTION OUTPUT ;
		SHAPE ABUTMENT ;
		PORT
			 LAYER M2 ;
			RECT 0.0098 10.0518 0.0481 10.1522 ;
			 LAYER M3 ;
			RECT 0.0098 10.0518 0.0481 10.1522 ;
			 LAYER V2 ;
			RECT 0.021 10.1267 0.0359 10.1392 ;
		END

		ANTENNADIFFAREA 0.00194719 ;
		ANTENNAPARTIALMETALAREA 0.00195671 ;
	END Q[7]

	PIN Q[8]
		USE SIGNAL ;
		DIRECTION OUTPUT ;
		SHAPE ABUTMENT ;
		PORT
			 LAYER M2 ;
			RECT 0.0098 11.3318 0.0481 11.4322 ;
			 LAYER M3 ;
			RECT 0.0098 11.3318 0.0481 11.4322 ;
			 LAYER V2 ;
			RECT 0.021 11.4067 0.0359 11.4192 ;
		END

		ANTENNADIFFAREA 0.00194719 ;
		ANTENNAPARTIALMETALAREA 0.00195671 ;
	END Q[8]

	PIN Q[9]
		USE SIGNAL ;
		DIRECTION OUTPUT ;
		SHAPE ABUTMENT ;
		PORT
			 LAYER M2 ;
			RECT 0.0098 12.6118 0.0481 12.7122 ;
			 LAYER M3 ;
			RECT 0.0098 12.6118 0.0481 12.7122 ;
			 LAYER V2 ;
			RECT 0.021 12.6867 0.0359 12.6992 ;
		END

		ANTENNADIFFAREA 0.00194719 ;
		ANTENNAPARTIALMETALAREA 0.00195671 ;
	END Q[9]

	PIN RAWL
		USE SIGNAL ;
		DIRECTION INPUT ;
		SHAPE ABUTMENT ;
		PORT
			 LAYER M2 ;
			RECT 0.0714 41.6502 0.1097 41.6878 ;
			 LAYER M3 ;
			RECT 0.0714 41.6502 0.1097 41.7506 ;
			 LAYER V2 ;
			RECT 0.0831 41.6624 0.098 41.6749 ;
		END

		ANTENNAGATEAREA 0.00027817 ;
		ANTENNADIFFAREA 0.00194719 ;
		ANTENNAPARTIALMETALAREA 0.00195671 ;
	END RAWL

	PIN RAWLM[0]
		USE SIGNAL ;
		DIRECTION INPUT ;
		SHAPE ABUTMENT ;
		PORT
			 LAYER M2 ;
			RECT 0.0098 45.4149 0.0481 45.4525 ;
		END

		ANTENNAGATEAREA 0.00027817 ;
		ANTENNADIFFAREA 0.00194719 ;
		ANTENNAPARTIALMETALAREA 0.00195671 ;
	END RAWLM[0]

	PIN RAWLM[1]
		USE SIGNAL ;
		DIRECTION INPUT ;
		SHAPE ABUTMENT ;
		PORT
			 LAYER M3 ;
			RECT 0.0714 46.3184 0.1097 46.4188 ;
		END

		ANTENNAGATEAREA 0.00027817 ;
		ANTENNADIFFAREA 0.00194719 ;
		ANTENNAPARTIALMETALAREA 0.00195671 ;
	END RAWLM[1]

	PIN RET1N
		USE SIGNAL ;
		DIRECTION INPUT ;
		SHAPE ABUTMENT ;
		PORT
			 LAYER M2 ;
			RECT 0.0098 43.2188 0.0481 43.2565 ;
			 LAYER M3 ;
			RECT 0.0098 43.1561 0.0481 43.2565 ;
			 LAYER V2 ;
			RECT 0.0215 43.231 0.0364 43.2435 ;
		END

		ANTENNAGATEAREA 0.00027817 ;
		ANTENNADIFFAREA 0.00194719 ;
		ANTENNAPARTIALMETALAREA 0.00195671 ;
	END RET1N

	PIN SE
		USE SIGNAL ;
		DIRECTION INPUT ;
		SHAPE ABUTMENT ;
		PORT
			 LAYER M3 ;
			RECT 0.0714 46.469 0.1097 46.5694 ;
		END

		ANTENNAGATEAREA 0.00027817 ;
		ANTENNADIFFAREA 0.00194719 ;
		ANTENNAPARTIALMETALAREA 0.00195671 ;
	END SE

	PIN SI[0]
		USE SIGNAL ;
		DIRECTION INPUT ;
		SHAPE ABUTMENT ;
		PORT
			 LAYER M2 ;
			RECT 0.0714 0.0627 0.1097 0.1004 ;
			 LAYER M3 ;
			RECT 0.0714 0.0627 0.1097 0.1631 ;
			 LAYER V2 ;
			RECT 0.0831 0.0749 0.098 0.0875 ;
		END

		ANTENNAGATEAREA 0.00027817 ;
		ANTENNADIFFAREA 0.00194719 ;
		ANTENNAPARTIALMETALAREA 0.00195671 ;
	END SI[0]

	PIN SI[1]
		USE SIGNAL ;
		DIRECTION INPUT ;
		SHAPE ABUTMENT ;
		PORT
			 LAYER M2 ;
			RECT 0.0714 89.9702 0.1097 90.0078 ;
			 LAYER M3 ;
			RECT 0.0714 89.9075 0.1097 90.0078 ;
			 LAYER V2 ;
			RECT 0.0831 89.9831 0.098 89.9957 ;
		END

		ANTENNAGATEAREA 0.00027817 ;
		ANTENNADIFFAREA 0.00194719 ;
		ANTENNAPARTIALMETALAREA 0.00195671 ;
	END SI[1]

	PIN SO[0]
		USE SIGNAL ;
		DIRECTION OUTPUT ;
		SHAPE ABUTMENT ;
		PORT
			 LAYER M2 ;
			RECT 0.0714 47.222 0.1097 47.2596 ;
			 LAYER M3 ;
			RECT 0.0714 47.222 0.1097 47.3224 ;
			 LAYER V2 ;
			RECT 0.0831 47.2341 0.098 47.2467 ;
		END

		ANTENNADIFFAREA 0.00194719 ;
		ANTENNAPARTIALMETALAREA 0.00195671 ;
	END SO[0]

	PIN SO[1]
		USE SIGNAL ;
		DIRECTION OUTPUT ;
		SHAPE ABUTMENT ;
		PORT
			 LAYER M2 ;
			RECT 0.0714 45.2643 0.1097 45.302 ;
			 LAYER M3 ;
			RECT 0.0714 45.2643 0.1097 45.3647 ;
			 LAYER V2 ;
			RECT 0.0831 45.2765 0.098 45.289 ;
		END

		ANTENNADIFFAREA 0.00194719 ;
		ANTENNAPARTIALMETALAREA 0.00195671 ;
	END SO[1]

	PIN STOV
		USE SIGNAL ;
		DIRECTION INPUT ;
		SHAPE ABUTMENT ;
		PORT
			 LAYER M2 ;
			RECT 0.0098 43.6706 0.0481 43.7082 ;
			 LAYER M3 ;
			RECT 0.0098 43.6078 0.0481 43.7082 ;
			 LAYER V2 ;
			RECT 0.0215 43.6827 0.0364 43.6953 ;
		END

		ANTENNAGATEAREA 0.00027817 ;
		ANTENNADIFFAREA 0.00194719 ;
		ANTENNAPARTIALMETALAREA 0.00195671 ;
	END STOV

	PIN TA[0]
		USE SIGNAL ;
		DIRECTION INPUT ;
		SHAPE ABUTMENT ;
		PORT
			 LAYER M2 ;
			RECT 0.0098 44.4235 0.0481 44.4612 ;
			 LAYER M3 ;
			RECT 0.0098 44.3608 0.0481 44.4612 ;
			 LAYER V2 ;
			RECT 0.0215 44.4357 0.0364 44.4482 ;
		END

		ANTENNAGATEAREA 0.00027817 ;
		ANTENNADIFFAREA 0.00194719 ;
		ANTENNAPARTIALMETALAREA 0.00195671 ;
	END TA[0]

	PIN TA[10]
		USE SIGNAL ;
		DIRECTION INPUT ;
		SHAPE ABUTMENT ;
		PORT
			 LAYER M2 ;
			RECT 0.0714 47.8243 0.1097 47.862 ;
			 LAYER M3 ;
			RECT 0.0714 47.8243 0.1097 47.9247 ;
			 LAYER V2 ;
			RECT 0.0831 47.8365 0.098 47.849 ;
		END

		ANTENNAGATEAREA 0.00027817 ;
		ANTENNADIFFAREA 0.00194719 ;
		ANTENNAPARTIALMETALAREA 0.00195671 ;
	END TA[10]

	PIN TA[11]
		USE SIGNAL ;
		DIRECTION INPUT ;
		SHAPE ABUTMENT ;
		PORT
			 LAYER M2 ;
			RECT 0.0098 48.0376 0.0481 48.0753 ;
			 LAYER M3 ;
			RECT 0.0098 47.9749 0.0481 48.0753 ;
			 LAYER V2 ;
			RECT 0.0215 48.0498 0.0364 48.0624 ;
		END

		ANTENNAGATEAREA 0.00027817 ;
		ANTENNADIFFAREA 0.00194719 ;
		ANTENNAPARTIALMETALAREA 0.00195671 ;
	END TA[11]

	PIN TA[1]
		USE SIGNAL ;
		DIRECTION INPUT ;
		SHAPE ABUTMENT ;
		PORT
			 LAYER M2 ;
			RECT 0.0714 44.662 0.1097 44.6996 ;
			 LAYER M3 ;
			RECT 0.0714 44.662 0.1097 44.7624 ;
			 LAYER V2 ;
			RECT 0.0831 44.6741 0.098 44.6867 ;
		END

		ANTENNAGATEAREA 0.00027817 ;
		ANTENNADIFFAREA 0.00194719 ;
		ANTENNAPARTIALMETALAREA 0.00195671 ;
	END TA[1]

	PIN TA[2]
		USE SIGNAL ;
		DIRECTION INPUT ;
		SHAPE ABUTMENT ;
		PORT
			 LAYER M2 ;
			RECT 0.0098 45.0259 0.0481 45.0635 ;
			 LAYER M3 ;
			RECT 0.0098 44.9631 0.0481 45.0635 ;
			 LAYER V2 ;
			RECT 0.0215 45.038 0.0364 45.0506 ;
		END

		ANTENNAGATEAREA 0.00027817 ;
		ANTENNADIFFAREA 0.00194719 ;
		ANTENNAPARTIALMETALAREA 0.00195671 ;
	END TA[2]

	PIN TA[3]
		USE SIGNAL ;
		DIRECTION INPUT ;
		SHAPE ABUTMENT ;
		PORT
			 LAYER M2 ;
			RECT 0.0714 45.7161 0.1097 45.7537 ;
			 LAYER M3 ;
			RECT 0.0714 45.7161 0.1097 45.8165 ;
			 LAYER V2 ;
			RECT 0.0831 45.7282 0.098 45.7408 ;
		END

		ANTENNAGATEAREA 0.00027817 ;
		ANTENNADIFFAREA 0.00194719 ;
		ANTENNAPARTIALMETALAREA 0.00195671 ;
	END TA[3]

	PIN TA[4]
		USE SIGNAL ;
		DIRECTION INPUT ;
		SHAPE ABUTMENT ;
		PORT
			 LAYER M2 ;
			RECT 0.0098 44.8753 0.0481 44.9129 ;
			 LAYER M3 ;
			RECT 0.0098 44.8125 0.0481 44.9129 ;
			 LAYER V2 ;
			RECT 0.0215 44.8875 0.0364 44.9 ;
		END

		ANTENNAGATEAREA 0.00027817 ;
		ANTENNADIFFAREA 0.00194719 ;
		ANTENNAPARTIALMETALAREA 0.00195671 ;
	END TA[4]

	PIN TA[5]
		USE SIGNAL ;
		DIRECTION INPUT ;
		SHAPE ABUTMENT ;
		PORT
			 LAYER M2 ;
			RECT 0.0098 43.3694 0.0481 43.4071 ;
			 LAYER M3 ;
			RECT 0.0098 43.3067 0.0481 43.4071 ;
			 LAYER V2 ;
			RECT 0.0215 43.3816 0.0364 43.3941 ;
		END

		ANTENNAGATEAREA 0.00027817 ;
		ANTENNADIFFAREA 0.00194719 ;
		ANTENNAPARTIALMETALAREA 0.00195671 ;
	END TA[5]

	PIN TA[6]
		USE SIGNAL ;
		DIRECTION INPUT ;
		SHAPE ABUTMENT ;
		PORT
			 LAYER M2 ;
			RECT 0.0098 46.0173 0.0481 46.0549 ;
		END

		ANTENNAGATEAREA 0.00027817 ;
		ANTENNADIFFAREA 0.00194719 ;
		ANTENNAPARTIALMETALAREA 0.00195671 ;
	END TA[6]

	PIN TA[7]
		USE SIGNAL ;
		DIRECTION INPUT ;
		SHAPE ABUTMENT ;
		PORT
			 LAYER M2 ;
			RECT 0.0098 46.469 0.0481 46.5067 ;
		END

		ANTENNAGATEAREA 0.00027817 ;
		ANTENNADIFFAREA 0.00194719 ;
		ANTENNAPARTIALMETALAREA 0.00195671 ;
	END TA[7]

	PIN TA[8]
		USE SIGNAL ;
		DIRECTION INPUT ;
		SHAPE ABUTMENT ;
		PORT
			 LAYER M2 ;
			RECT 0.0098 47.2847 0.0481 47.3224 ;
			 LAYER M3 ;
			RECT 0.0098 47.222 0.0481 47.3224 ;
			 LAYER V2 ;
			RECT 0.0215 47.2969 0.0364 47.3094 ;
		END

		ANTENNAGATEAREA 0.00027817 ;
		ANTENNADIFFAREA 0.00194719 ;
		ANTENNAPARTIALMETALAREA 0.00195671 ;
	END TA[8]

	PIN TA[9]
		USE SIGNAL ;
		DIRECTION INPUT ;
		SHAPE ABUTMENT ;
		PORT
			 LAYER M2 ;
			RECT 0.0714 46.7702 0.1097 46.8078 ;
			 LAYER M3 ;
			RECT 0.0714 46.7702 0.1097 46.8706 ;
			 LAYER V2 ;
			RECT 0.0831 46.7824 0.098 46.7949 ;
		END

		ANTENNAGATEAREA 0.00027817 ;
		ANTENNADIFFAREA 0.00194719 ;
		ANTENNAPARTIALMETALAREA 0.00195671 ;
	END TA[9]

	PIN TCEN
		USE SIGNAL ;
		DIRECTION INPUT ;
		SHAPE ABUTMENT ;
		PORT
			 LAYER M2 ;
			RECT 0.0098 43.8212 0.0481 43.8588 ;
			 LAYER M3 ;
			RECT 0.0098 43.7584 0.0481 43.8588 ;
			 LAYER V2 ;
			RECT 0.0215 43.8333 0.0364 43.8459 ;
		END

		ANTENNAGATEAREA 0.00027817 ;
		ANTENNADIFFAREA 0.00194719 ;
		ANTENNAPARTIALMETALAREA 0.00195671 ;
	END TCEN

	PIN TD[0]
		USE SIGNAL ;
		DIRECTION INPUT ;
		SHAPE ABUTMENT ;
		PORT
			 LAYER M2 ;
			RECT 0.0098 0.9663 0.0481 1.0039 ;
			 LAYER M3 ;
			RECT 0.0098 0.9663 0.0481 1.0667 ;
			 LAYER V2 ;
			RECT 0.0215 0.9792 0.0364 0.9918 ;
		END

		ANTENNAGATEAREA 0.00027817 ;
		ANTENNADIFFAREA 0.00194719 ;
		ANTENNAPARTIALMETALAREA 0.00195671 ;
	END TD[0]

	PIN TD[10]
		USE SIGNAL ;
		DIRECTION INPUT ;
		SHAPE ABUTMENT ;
		PORT
			 LAYER M2 ;
			RECT 0.0098 13.7663 0.0481 13.8039 ;
			 LAYER M3 ;
			RECT 0.0098 13.7663 0.0481 13.8667 ;
			 LAYER V2 ;
			RECT 0.0215 13.7792 0.0364 13.7918 ;
		END

		ANTENNAGATEAREA 0.00027817 ;
		ANTENNADIFFAREA 0.00194719 ;
		ANTENNAPARTIALMETALAREA 0.00195671 ;
	END TD[10]

	PIN TD[11]
		USE SIGNAL ;
		DIRECTION INPUT ;
		SHAPE ABUTMENT ;
		PORT
			 LAYER M2 ;
			RECT 0.0098 15.0463 0.0481 15.0839 ;
			 LAYER M3 ;
			RECT 0.0098 15.0463 0.0481 15.1467 ;
			 LAYER V2 ;
			RECT 0.0215 15.0592 0.0364 15.0718 ;
		END

		ANTENNAGATEAREA 0.00027817 ;
		ANTENNADIFFAREA 0.00194719 ;
		ANTENNAPARTIALMETALAREA 0.00195671 ;
	END TD[11]

	PIN TD[12]
		USE SIGNAL ;
		DIRECTION INPUT ;
		SHAPE ABUTMENT ;
		PORT
			 LAYER M2 ;
			RECT 0.0098 16.3263 0.0481 16.3639 ;
			 LAYER M3 ;
			RECT 0.0098 16.3263 0.0481 16.4267 ;
			 LAYER V2 ;
			RECT 0.0215 16.3392 0.0364 16.3518 ;
		END

		ANTENNAGATEAREA 0.00027817 ;
		ANTENNADIFFAREA 0.00194719 ;
		ANTENNAPARTIALMETALAREA 0.00195671 ;
	END TD[12]

	PIN TD[13]
		USE SIGNAL ;
		DIRECTION INPUT ;
		SHAPE ABUTMENT ;
		PORT
			 LAYER M2 ;
			RECT 0.0098 17.6063 0.0481 17.6439 ;
			 LAYER M3 ;
			RECT 0.0098 17.6063 0.0481 17.7067 ;
			 LAYER V2 ;
			RECT 0.0215 17.6192 0.0364 17.6318 ;
		END

		ANTENNAGATEAREA 0.00027817 ;
		ANTENNADIFFAREA 0.00194719 ;
		ANTENNAPARTIALMETALAREA 0.00195671 ;
	END TD[13]

	PIN TD[14]
		USE SIGNAL ;
		DIRECTION INPUT ;
		SHAPE ABUTMENT ;
		PORT
			 LAYER M2 ;
			RECT 0.0098 18.8863 0.0481 18.9239 ;
			 LAYER M3 ;
			RECT 0.0098 18.8863 0.0481 18.9867 ;
			 LAYER V2 ;
			RECT 0.0215 18.8992 0.0364 18.9118 ;
		END

		ANTENNAGATEAREA 0.00027817 ;
		ANTENNADIFFAREA 0.00194719 ;
		ANTENNAPARTIALMETALAREA 0.00195671 ;
	END TD[14]

	PIN TD[15]
		USE SIGNAL ;
		DIRECTION INPUT ;
		SHAPE ABUTMENT ;
		PORT
			 LAYER M2 ;
			RECT 0.0098 20.1663 0.0481 20.2039 ;
			 LAYER M3 ;
			RECT 0.0098 20.1663 0.0481 20.2667 ;
			 LAYER V2 ;
			RECT 0.0215 20.1792 0.0364 20.1918 ;
		END

		ANTENNAGATEAREA 0.00027817 ;
		ANTENNADIFFAREA 0.00194719 ;
		ANTENNAPARTIALMETALAREA 0.00195671 ;
	END TD[15]

	PIN TD[16]
		USE SIGNAL ;
		DIRECTION INPUT ;
		SHAPE ABUTMENT ;
		PORT
			 LAYER M2 ;
			RECT 0.0098 21.4463 0.0481 21.4839 ;
			 LAYER M3 ;
			RECT 0.0098 21.4463 0.0481 21.5467 ;
			 LAYER V2 ;
			RECT 0.0215 21.4592 0.0364 21.4718 ;
		END

		ANTENNAGATEAREA 0.00027817 ;
		ANTENNADIFFAREA 0.00194719 ;
		ANTENNAPARTIALMETALAREA 0.00195671 ;
	END TD[16]

	PIN TD[17]
		USE SIGNAL ;
		DIRECTION INPUT ;
		SHAPE ABUTMENT ;
		PORT
			 LAYER M2 ;
			RECT 0.0098 22.7263 0.0481 22.7639 ;
			 LAYER M3 ;
			RECT 0.0098 22.7263 0.0481 22.8267 ;
			 LAYER V2 ;
			RECT 0.0215 22.7392 0.0364 22.7518 ;
		END

		ANTENNAGATEAREA 0.00027817 ;
		ANTENNADIFFAREA 0.00194719 ;
		ANTENNAPARTIALMETALAREA 0.00195671 ;
	END TD[17]

	PIN TD[18]
		USE SIGNAL ;
		DIRECTION INPUT ;
		SHAPE ABUTMENT ;
		PORT
			 LAYER M2 ;
			RECT 0.0098 24.0063 0.0481 24.0439 ;
			 LAYER M3 ;
			RECT 0.0098 24.0063 0.0481 24.1067 ;
			 LAYER V2 ;
			RECT 0.0215 24.0192 0.0364 24.0318 ;
		END

		ANTENNAGATEAREA 0.00027817 ;
		ANTENNADIFFAREA 0.00194719 ;
		ANTENNAPARTIALMETALAREA 0.00195671 ;
	END TD[18]

	PIN TD[19]
		USE SIGNAL ;
		DIRECTION INPUT ;
		SHAPE ABUTMENT ;
		PORT
			 LAYER M2 ;
			RECT 0.0098 25.2863 0.0481 25.3239 ;
			 LAYER M3 ;
			RECT 0.0098 25.2863 0.0481 25.3867 ;
			 LAYER V2 ;
			RECT 0.0215 25.2992 0.0364 25.3118 ;
		END

		ANTENNAGATEAREA 0.00027817 ;
		ANTENNADIFFAREA 0.00194719 ;
		ANTENNAPARTIALMETALAREA 0.00195671 ;
	END TD[19]

	PIN TD[1]
		USE SIGNAL ;
		DIRECTION INPUT ;
		SHAPE ABUTMENT ;
		PORT
			 LAYER M2 ;
			RECT 0.0098 2.2463 0.0481 2.2839 ;
			 LAYER M3 ;
			RECT 0.0098 2.2463 0.0481 2.3467 ;
			 LAYER V2 ;
			RECT 0.0215 2.2592 0.0364 2.2718 ;
		END

		ANTENNAGATEAREA 0.00027817 ;
		ANTENNADIFFAREA 0.00194719 ;
		ANTENNAPARTIALMETALAREA 0.00195671 ;
	END TD[1]

	PIN TD[20]
		USE SIGNAL ;
		DIRECTION INPUT ;
		SHAPE ABUTMENT ;
		PORT
			 LAYER M2 ;
			RECT 0.0098 26.5663 0.0481 26.6039 ;
			 LAYER M3 ;
			RECT 0.0098 26.5663 0.0481 26.6667 ;
			 LAYER V2 ;
			RECT 0.0215 26.5792 0.0364 26.5918 ;
		END

		ANTENNAGATEAREA 0.00027817 ;
		ANTENNADIFFAREA 0.00194719 ;
		ANTENNAPARTIALMETALAREA 0.00195671 ;
	END TD[20]

	PIN TD[21]
		USE SIGNAL ;
		DIRECTION INPUT ;
		SHAPE ABUTMENT ;
		PORT
			 LAYER M2 ;
			RECT 0.0098 27.8463 0.0481 27.8839 ;
			 LAYER M3 ;
			RECT 0.0098 27.8463 0.0481 27.9467 ;
			 LAYER V2 ;
			RECT 0.0215 27.8592 0.0364 27.8718 ;
		END

		ANTENNAGATEAREA 0.00027817 ;
		ANTENNADIFFAREA 0.00194719 ;
		ANTENNAPARTIALMETALAREA 0.00195671 ;
	END TD[21]

	PIN TD[22]
		USE SIGNAL ;
		DIRECTION INPUT ;
		SHAPE ABUTMENT ;
		PORT
			 LAYER M2 ;
			RECT 0.0098 29.1263 0.0481 29.1639 ;
			 LAYER M3 ;
			RECT 0.0098 29.1263 0.0481 29.2267 ;
			 LAYER V2 ;
			RECT 0.0215 29.1392 0.0364 29.1518 ;
		END

		ANTENNAGATEAREA 0.00027817 ;
		ANTENNADIFFAREA 0.00194719 ;
		ANTENNAPARTIALMETALAREA 0.00195671 ;
	END TD[22]

	PIN TD[23]
		USE SIGNAL ;
		DIRECTION INPUT ;
		SHAPE ABUTMENT ;
		PORT
			 LAYER M2 ;
			RECT 0.0098 30.4063 0.0481 30.4439 ;
			 LAYER M3 ;
			RECT 0.0098 30.4063 0.0481 30.5067 ;
			 LAYER V2 ;
			RECT 0.0215 30.4192 0.0364 30.4318 ;
		END

		ANTENNAGATEAREA 0.00027817 ;
		ANTENNADIFFAREA 0.00194719 ;
		ANTENNAPARTIALMETALAREA 0.00195671 ;
	END TD[23]

	PIN TD[24]
		USE SIGNAL ;
		DIRECTION INPUT ;
		SHAPE ABUTMENT ;
		PORT
			 LAYER M2 ;
			RECT 0.0098 31.6863 0.0481 31.7239 ;
			 LAYER M3 ;
			RECT 0.0098 31.6863 0.0481 31.7867 ;
			 LAYER V2 ;
			RECT 0.0215 31.6992 0.0364 31.7118 ;
		END

		ANTENNAGATEAREA 0.00027817 ;
		ANTENNADIFFAREA 0.00194719 ;
		ANTENNAPARTIALMETALAREA 0.00195671 ;
	END TD[24]

	PIN TD[25]
		USE SIGNAL ;
		DIRECTION INPUT ;
		SHAPE ABUTMENT ;
		PORT
			 LAYER M2 ;
			RECT 0.0098 32.9663 0.0481 33.0039 ;
			 LAYER M3 ;
			RECT 0.0098 32.9663 0.0481 33.0667 ;
			 LAYER V2 ;
			RECT 0.0215 32.9792 0.0364 32.9918 ;
		END

		ANTENNAGATEAREA 0.00027817 ;
		ANTENNADIFFAREA 0.00194719 ;
		ANTENNAPARTIALMETALAREA 0.00195671 ;
	END TD[25]

	PIN TD[26]
		USE SIGNAL ;
		DIRECTION INPUT ;
		SHAPE ABUTMENT ;
		PORT
			 LAYER M2 ;
			RECT 0.0098 34.2463 0.0481 34.2839 ;
			 LAYER M3 ;
			RECT 0.0098 34.2463 0.0481 34.3467 ;
			 LAYER V2 ;
			RECT 0.0215 34.2592 0.0364 34.2718 ;
		END

		ANTENNAGATEAREA 0.00027817 ;
		ANTENNADIFFAREA 0.00194719 ;
		ANTENNAPARTIALMETALAREA 0.00195671 ;
	END TD[26]

	PIN TD[27]
		USE SIGNAL ;
		DIRECTION INPUT ;
		SHAPE ABUTMENT ;
		PORT
			 LAYER M2 ;
			RECT 0.0098 35.5263 0.0481 35.5639 ;
			 LAYER M3 ;
			RECT 0.0098 35.5263 0.0481 35.6267 ;
			 LAYER V2 ;
			RECT 0.0215 35.5392 0.0364 35.5518 ;
		END

		ANTENNAGATEAREA 0.00027817 ;
		ANTENNADIFFAREA 0.00194719 ;
		ANTENNAPARTIALMETALAREA 0.00195671 ;
	END TD[27]

	PIN TD[28]
		USE SIGNAL ;
		DIRECTION INPUT ;
		SHAPE ABUTMENT ;
		PORT
			 LAYER M2 ;
			RECT 0.0098 36.8063 0.0481 36.8439 ;
			 LAYER M3 ;
			RECT 0.0098 36.8063 0.0481 36.9067 ;
			 LAYER V2 ;
			RECT 0.0215 36.8192 0.0364 36.8318 ;
		END

		ANTENNAGATEAREA 0.00027817 ;
		ANTENNADIFFAREA 0.00194719 ;
		ANTENNAPARTIALMETALAREA 0.00195671 ;
	END TD[28]

	PIN TD[29]
		USE SIGNAL ;
		DIRECTION INPUT ;
		SHAPE ABUTMENT ;
		PORT
			 LAYER M2 ;
			RECT 0.0098 38.0863 0.0481 38.1239 ;
			 LAYER M3 ;
			RECT 0.0098 38.0863 0.0481 38.1867 ;
			 LAYER V2 ;
			RECT 0.0215 38.0992 0.0364 38.1118 ;
		END

		ANTENNAGATEAREA 0.00027817 ;
		ANTENNADIFFAREA 0.00194719 ;
		ANTENNAPARTIALMETALAREA 0.00195671 ;
	END TD[29]

	PIN TD[2]
		USE SIGNAL ;
		DIRECTION INPUT ;
		SHAPE ABUTMENT ;
		PORT
			 LAYER M2 ;
			RECT 0.0098 3.5263 0.0481 3.5639 ;
			 LAYER M3 ;
			RECT 0.0098 3.5263 0.0481 3.6267 ;
			 LAYER V2 ;
			RECT 0.0215 3.5392 0.0364 3.5518 ;
		END

		ANTENNAGATEAREA 0.00027817 ;
		ANTENNADIFFAREA 0.00194719 ;
		ANTENNAPARTIALMETALAREA 0.00195671 ;
	END TD[2]

	PIN TD[30]
		USE SIGNAL ;
		DIRECTION INPUT ;
		SHAPE ABUTMENT ;
		PORT
			 LAYER M2 ;
			RECT 0.0098 39.3663 0.0481 39.4039 ;
			 LAYER M3 ;
			RECT 0.0098 39.3663 0.0481 39.4667 ;
			 LAYER V2 ;
			RECT 0.0215 39.3792 0.0364 39.3918 ;
		END

		ANTENNAGATEAREA 0.00027817 ;
		ANTENNADIFFAREA 0.00194719 ;
		ANTENNAPARTIALMETALAREA 0.00195671 ;
	END TD[30]

	PIN TD[31]
		USE SIGNAL ;
		DIRECTION INPUT ;
		SHAPE ABUTMENT ;
		PORT
			 LAYER M2 ;
			RECT 0.0098 40.6463 0.0481 40.6839 ;
			 LAYER M3 ;
			RECT 0.0098 40.6463 0.0481 40.7467 ;
			 LAYER V2 ;
			RECT 0.0215 40.6592 0.0364 40.6718 ;
		END

		ANTENNAGATEAREA 0.00027817 ;
		ANTENNADIFFAREA 0.00194719 ;
		ANTENNAPARTIALMETALAREA 0.00195671 ;
	END TD[31]

	PIN TD[32]
		USE SIGNAL ;
		DIRECTION INPUT ;
		SHAPE ABUTMENT ;
		PORT
			 LAYER M2 ;
			RECT 0.0098 49.3867 0.0481 49.4243 ;
			 LAYER M3 ;
			RECT 0.0098 49.3239 0.0481 49.4243 ;
			 LAYER V2 ;
			RECT 0.0215 49.3988 0.0364 49.4114 ;
		END

		ANTENNAGATEAREA 0.00027817 ;
		ANTENNADIFFAREA 0.00194719 ;
		ANTENNAPARTIALMETALAREA 0.00195671 ;
	END TD[32]

	PIN TD[33]
		USE SIGNAL ;
		DIRECTION INPUT ;
		SHAPE ABUTMENT ;
		PORT
			 LAYER M2 ;
			RECT 0.0098 50.6667 0.0481 50.7043 ;
			 LAYER M3 ;
			RECT 0.0098 50.6039 0.0481 50.7043 ;
			 LAYER V2 ;
			RECT 0.0215 50.6788 0.0364 50.6914 ;
		END

		ANTENNAGATEAREA 0.00027817 ;
		ANTENNADIFFAREA 0.00194719 ;
		ANTENNAPARTIALMETALAREA 0.00195671 ;
	END TD[33]

	PIN TD[34]
		USE SIGNAL ;
		DIRECTION INPUT ;
		SHAPE ABUTMENT ;
		PORT
			 LAYER M2 ;
			RECT 0.0098 51.9467 0.0481 51.9843 ;
			 LAYER M3 ;
			RECT 0.0098 51.8839 0.0481 51.9843 ;
			 LAYER V2 ;
			RECT 0.0215 51.9588 0.0364 51.9714 ;
		END

		ANTENNAGATEAREA 0.00027817 ;
		ANTENNADIFFAREA 0.00194719 ;
		ANTENNAPARTIALMETALAREA 0.00195671 ;
	END TD[34]

	PIN TD[35]
		USE SIGNAL ;
		DIRECTION INPUT ;
		SHAPE ABUTMENT ;
		PORT
			 LAYER M2 ;
			RECT 0.0098 53.2267 0.0481 53.2643 ;
			 LAYER M3 ;
			RECT 0.0098 53.1639 0.0481 53.2643 ;
			 LAYER V2 ;
			RECT 0.0215 53.2388 0.0364 53.2514 ;
		END

		ANTENNAGATEAREA 0.00027817 ;
		ANTENNADIFFAREA 0.00194719 ;
		ANTENNAPARTIALMETALAREA 0.00195671 ;
	END TD[35]

	PIN TD[36]
		USE SIGNAL ;
		DIRECTION INPUT ;
		SHAPE ABUTMENT ;
		PORT
			 LAYER M2 ;
			RECT 0.0098 54.5067 0.0481 54.5443 ;
			 LAYER M3 ;
			RECT 0.0098 54.4439 0.0481 54.5443 ;
			 LAYER V2 ;
			RECT 0.0215 54.5188 0.0364 54.5314 ;
		END

		ANTENNAGATEAREA 0.00027817 ;
		ANTENNADIFFAREA 0.00194719 ;
		ANTENNAPARTIALMETALAREA 0.00195671 ;
	END TD[36]

	PIN TD[37]
		USE SIGNAL ;
		DIRECTION INPUT ;
		SHAPE ABUTMENT ;
		PORT
			 LAYER M2 ;
			RECT 0.0098 55.7867 0.0481 55.8243 ;
			 LAYER M3 ;
			RECT 0.0098 55.7239 0.0481 55.8243 ;
			 LAYER V2 ;
			RECT 0.0215 55.7988 0.0364 55.8114 ;
		END

		ANTENNAGATEAREA 0.00027817 ;
		ANTENNADIFFAREA 0.00194719 ;
		ANTENNAPARTIALMETALAREA 0.00195671 ;
	END TD[37]

	PIN TD[38]
		USE SIGNAL ;
		DIRECTION INPUT ;
		SHAPE ABUTMENT ;
		PORT
			 LAYER M2 ;
			RECT 0.0098 57.0667 0.0481 57.1043 ;
			 LAYER M3 ;
			RECT 0.0098 57.0039 0.0481 57.1043 ;
			 LAYER V2 ;
			RECT 0.0215 57.0788 0.0364 57.0914 ;
		END

		ANTENNAGATEAREA 0.00027817 ;
		ANTENNADIFFAREA 0.00194719 ;
		ANTENNAPARTIALMETALAREA 0.00195671 ;
	END TD[38]

	PIN TD[39]
		USE SIGNAL ;
		DIRECTION INPUT ;
		SHAPE ABUTMENT ;
		PORT
			 LAYER M2 ;
			RECT 0.0098 58.3467 0.0481 58.3843 ;
			 LAYER M3 ;
			RECT 0.0098 58.2839 0.0481 58.3843 ;
			 LAYER V2 ;
			RECT 0.0215 58.3588 0.0364 58.3714 ;
		END

		ANTENNAGATEAREA 0.00027817 ;
		ANTENNADIFFAREA 0.00194719 ;
		ANTENNAPARTIALMETALAREA 0.00195671 ;
	END TD[39]

	PIN TD[3]
		USE SIGNAL ;
		DIRECTION INPUT ;
		SHAPE ABUTMENT ;
		PORT
			 LAYER M2 ;
			RECT 0.0098 4.8063 0.0481 4.8439 ;
			 LAYER M3 ;
			RECT 0.0098 4.8063 0.0481 4.9067 ;
			 LAYER V2 ;
			RECT 0.0215 4.8192 0.0364 4.8318 ;
		END

		ANTENNAGATEAREA 0.00027817 ;
		ANTENNADIFFAREA 0.00194719 ;
		ANTENNAPARTIALMETALAREA 0.00195671 ;
	END TD[3]

	PIN TD[40]
		USE SIGNAL ;
		DIRECTION INPUT ;
		SHAPE ABUTMENT ;
		PORT
			 LAYER M2 ;
			RECT 0.0098 59.6267 0.0481 59.6643 ;
			 LAYER M3 ;
			RECT 0.0098 59.5639 0.0481 59.6643 ;
			 LAYER V2 ;
			RECT 0.0215 59.6388 0.0364 59.6514 ;
		END

		ANTENNAGATEAREA 0.00027817 ;
		ANTENNADIFFAREA 0.00194719 ;
		ANTENNAPARTIALMETALAREA 0.00195671 ;
	END TD[40]

	PIN TD[41]
		USE SIGNAL ;
		DIRECTION INPUT ;
		SHAPE ABUTMENT ;
		PORT
			 LAYER M2 ;
			RECT 0.0098 60.9067 0.0481 60.9443 ;
			 LAYER M3 ;
			RECT 0.0098 60.8439 0.0481 60.9443 ;
			 LAYER V2 ;
			RECT 0.0215 60.9188 0.0364 60.9314 ;
		END

		ANTENNAGATEAREA 0.00027817 ;
		ANTENNADIFFAREA 0.00194719 ;
		ANTENNAPARTIALMETALAREA 0.00195671 ;
	END TD[41]

	PIN TD[42]
		USE SIGNAL ;
		DIRECTION INPUT ;
		SHAPE ABUTMENT ;
		PORT
			 LAYER M2 ;
			RECT 0.0098 62.1867 0.0481 62.2243 ;
			 LAYER M3 ;
			RECT 0.0098 62.1239 0.0481 62.2243 ;
			 LAYER V2 ;
			RECT 0.0215 62.1988 0.0364 62.2114 ;
		END

		ANTENNAGATEAREA 0.00027817 ;
		ANTENNADIFFAREA 0.00194719 ;
		ANTENNAPARTIALMETALAREA 0.00195671 ;
	END TD[42]

	PIN TD[43]
		USE SIGNAL ;
		DIRECTION INPUT ;
		SHAPE ABUTMENT ;
		PORT
			 LAYER M2 ;
			RECT 0.0098 63.4667 0.0481 63.5043 ;
			 LAYER M3 ;
			RECT 0.0098 63.4039 0.0481 63.5043 ;
			 LAYER V2 ;
			RECT 0.0215 63.4788 0.0364 63.4914 ;
		END

		ANTENNAGATEAREA 0.00027817 ;
		ANTENNADIFFAREA 0.00194719 ;
		ANTENNAPARTIALMETALAREA 0.00195671 ;
	END TD[43]

	PIN TD[44]
		USE SIGNAL ;
		DIRECTION INPUT ;
		SHAPE ABUTMENT ;
		PORT
			 LAYER M2 ;
			RECT 0.0098 64.7467 0.0481 64.7843 ;
			 LAYER M3 ;
			RECT 0.0098 64.6839 0.0481 64.7843 ;
			 LAYER V2 ;
			RECT 0.0215 64.7588 0.0364 64.7714 ;
		END

		ANTENNAGATEAREA 0.00027817 ;
		ANTENNADIFFAREA 0.00194719 ;
		ANTENNAPARTIALMETALAREA 0.00195671 ;
	END TD[44]

	PIN TD[45]
		USE SIGNAL ;
		DIRECTION INPUT ;
		SHAPE ABUTMENT ;
		PORT
			 LAYER M2 ;
			RECT 0.0098 66.0267 0.0481 66.0643 ;
			 LAYER M3 ;
			RECT 0.0098 65.9639 0.0481 66.0643 ;
			 LAYER V2 ;
			RECT 0.0215 66.0388 0.0364 66.0514 ;
		END

		ANTENNAGATEAREA 0.00027817 ;
		ANTENNADIFFAREA 0.00194719 ;
		ANTENNAPARTIALMETALAREA 0.00195671 ;
	END TD[45]

	PIN TD[46]
		USE SIGNAL ;
		DIRECTION INPUT ;
		SHAPE ABUTMENT ;
		PORT
			 LAYER M2 ;
			RECT 0.0098 67.3067 0.0481 67.3443 ;
			 LAYER M3 ;
			RECT 0.0098 67.2439 0.0481 67.3443 ;
			 LAYER V2 ;
			RECT 0.0215 67.3188 0.0364 67.3314 ;
		END

		ANTENNAGATEAREA 0.00027817 ;
		ANTENNADIFFAREA 0.00194719 ;
		ANTENNAPARTIALMETALAREA 0.00195671 ;
	END TD[46]

	PIN TD[47]
		USE SIGNAL ;
		DIRECTION INPUT ;
		SHAPE ABUTMENT ;
		PORT
			 LAYER M2 ;
			RECT 0.0098 68.5867 0.0481 68.6243 ;
			 LAYER M3 ;
			RECT 0.0098 68.5239 0.0481 68.6243 ;
			 LAYER V2 ;
			RECT 0.0215 68.5988 0.0364 68.6114 ;
		END

		ANTENNAGATEAREA 0.00027817 ;
		ANTENNADIFFAREA 0.00194719 ;
		ANTENNAPARTIALMETALAREA 0.00195671 ;
	END TD[47]

	PIN TD[48]
		USE SIGNAL ;
		DIRECTION INPUT ;
		SHAPE ABUTMENT ;
		PORT
			 LAYER M2 ;
			RECT 0.0098 69.8667 0.0481 69.9043 ;
			 LAYER M3 ;
			RECT 0.0098 69.8039 0.0481 69.9043 ;
			 LAYER V2 ;
			RECT 0.0215 69.8788 0.0364 69.8914 ;
		END

		ANTENNAGATEAREA 0.00027817 ;
		ANTENNADIFFAREA 0.00194719 ;
		ANTENNAPARTIALMETALAREA 0.00195671 ;
	END TD[48]

	PIN TD[49]
		USE SIGNAL ;
		DIRECTION INPUT ;
		SHAPE ABUTMENT ;
		PORT
			 LAYER M2 ;
			RECT 0.0098 71.1467 0.0481 71.1843 ;
			 LAYER M3 ;
			RECT 0.0098 71.0839 0.0481 71.1843 ;
			 LAYER V2 ;
			RECT 0.0215 71.1588 0.0364 71.1714 ;
		END

		ANTENNAGATEAREA 0.00027817 ;
		ANTENNADIFFAREA 0.00194719 ;
		ANTENNAPARTIALMETALAREA 0.00195671 ;
	END TD[49]

	PIN TD[4]
		USE SIGNAL ;
		DIRECTION INPUT ;
		SHAPE ABUTMENT ;
		PORT
			 LAYER M2 ;
			RECT 0.0098 6.0863 0.0481 6.1239 ;
			 LAYER M3 ;
			RECT 0.0098 6.0863 0.0481 6.1867 ;
			 LAYER V2 ;
			RECT 0.0215 6.0992 0.0364 6.1118 ;
		END

		ANTENNAGATEAREA 0.00027817 ;
		ANTENNADIFFAREA 0.00194719 ;
		ANTENNAPARTIALMETALAREA 0.00195671 ;
	END TD[4]

	PIN TD[50]
		USE SIGNAL ;
		DIRECTION INPUT ;
		SHAPE ABUTMENT ;
		PORT
			 LAYER M2 ;
			RECT 0.0098 72.4267 0.0481 72.4643 ;
			 LAYER M3 ;
			RECT 0.0098 72.3639 0.0481 72.4643 ;
			 LAYER V2 ;
			RECT 0.0215 72.4388 0.0364 72.4514 ;
		END

		ANTENNAGATEAREA 0.00027817 ;
		ANTENNADIFFAREA 0.00194719 ;
		ANTENNAPARTIALMETALAREA 0.00195671 ;
	END TD[50]

	PIN TD[51]
		USE SIGNAL ;
		DIRECTION INPUT ;
		SHAPE ABUTMENT ;
		PORT
			 LAYER M2 ;
			RECT 0.0098 73.7067 0.0481 73.7443 ;
			 LAYER M3 ;
			RECT 0.0098 73.6439 0.0481 73.7443 ;
			 LAYER V2 ;
			RECT 0.0215 73.7188 0.0364 73.7314 ;
		END

		ANTENNAGATEAREA 0.00027817 ;
		ANTENNADIFFAREA 0.00194719 ;
		ANTENNAPARTIALMETALAREA 0.00195671 ;
	END TD[51]

	PIN TD[52]
		USE SIGNAL ;
		DIRECTION INPUT ;
		SHAPE ABUTMENT ;
		PORT
			 LAYER M2 ;
			RECT 0.0098 74.9867 0.0481 75.0243 ;
			 LAYER M3 ;
			RECT 0.0098 74.9239 0.0481 75.0243 ;
			 LAYER V2 ;
			RECT 0.0215 74.9988 0.0364 75.0114 ;
		END

		ANTENNAGATEAREA 0.00027817 ;
		ANTENNADIFFAREA 0.00194719 ;
		ANTENNAPARTIALMETALAREA 0.00195671 ;
	END TD[52]

	PIN TD[53]
		USE SIGNAL ;
		DIRECTION INPUT ;
		SHAPE ABUTMENT ;
		PORT
			 LAYER M2 ;
			RECT 0.0098 76.2667 0.0481 76.3043 ;
			 LAYER M3 ;
			RECT 0.0098 76.2039 0.0481 76.3043 ;
			 LAYER V2 ;
			RECT 0.0215 76.2788 0.0364 76.2914 ;
		END

		ANTENNAGATEAREA 0.00027817 ;
		ANTENNADIFFAREA 0.00194719 ;
		ANTENNAPARTIALMETALAREA 0.00195671 ;
	END TD[53]

	PIN TD[54]
		USE SIGNAL ;
		DIRECTION INPUT ;
		SHAPE ABUTMENT ;
		PORT
			 LAYER M2 ;
			RECT 0.0098 77.5467 0.0481 77.5843 ;
			 LAYER M3 ;
			RECT 0.0098 77.4839 0.0481 77.5843 ;
			 LAYER V2 ;
			RECT 0.0215 77.5588 0.0364 77.5714 ;
		END

		ANTENNAGATEAREA 0.00027817 ;
		ANTENNADIFFAREA 0.00194719 ;
		ANTENNAPARTIALMETALAREA 0.00195671 ;
	END TD[54]

	PIN TD[55]
		USE SIGNAL ;
		DIRECTION INPUT ;
		SHAPE ABUTMENT ;
		PORT
			 LAYER M2 ;
			RECT 0.0098 78.8267 0.0481 78.8643 ;
			 LAYER M3 ;
			RECT 0.0098 78.7639 0.0481 78.8643 ;
			 LAYER V2 ;
			RECT 0.0215 78.8388 0.0364 78.8514 ;
		END

		ANTENNAGATEAREA 0.00027817 ;
		ANTENNADIFFAREA 0.00194719 ;
		ANTENNAPARTIALMETALAREA 0.00195671 ;
	END TD[55]

	PIN TD[56]
		USE SIGNAL ;
		DIRECTION INPUT ;
		SHAPE ABUTMENT ;
		PORT
			 LAYER M2 ;
			RECT 0.0098 80.1067 0.0481 80.1443 ;
			 LAYER M3 ;
			RECT 0.0098 80.0439 0.0481 80.1443 ;
			 LAYER V2 ;
			RECT 0.0215 80.1188 0.0364 80.1314 ;
		END

		ANTENNAGATEAREA 0.00027817 ;
		ANTENNADIFFAREA 0.00194719 ;
		ANTENNAPARTIALMETALAREA 0.00195671 ;
	END TD[56]

	PIN TD[57]
		USE SIGNAL ;
		DIRECTION INPUT ;
		SHAPE ABUTMENT ;
		PORT
			 LAYER M2 ;
			RECT 0.0098 81.3867 0.0481 81.4243 ;
			 LAYER M3 ;
			RECT 0.0098 81.3239 0.0481 81.4243 ;
			 LAYER V2 ;
			RECT 0.0215 81.3988 0.0364 81.4114 ;
		END

		ANTENNAGATEAREA 0.00027817 ;
		ANTENNADIFFAREA 0.00194719 ;
		ANTENNAPARTIALMETALAREA 0.00195671 ;
	END TD[57]

	PIN TD[58]
		USE SIGNAL ;
		DIRECTION INPUT ;
		SHAPE ABUTMENT ;
		PORT
			 LAYER M2 ;
			RECT 0.0098 82.6667 0.0481 82.7043 ;
			 LAYER M3 ;
			RECT 0.0098 82.6039 0.0481 82.7043 ;
			 LAYER V2 ;
			RECT 0.0215 82.6788 0.0364 82.6914 ;
		END

		ANTENNAGATEAREA 0.00027817 ;
		ANTENNADIFFAREA 0.00194719 ;
		ANTENNAPARTIALMETALAREA 0.00195671 ;
	END TD[58]

	PIN TD[59]
		USE SIGNAL ;
		DIRECTION INPUT ;
		SHAPE ABUTMENT ;
		PORT
			 LAYER M2 ;
			RECT 0.0098 83.9467 0.0481 83.9843 ;
			 LAYER M3 ;
			RECT 0.0098 83.8839 0.0481 83.9843 ;
			 LAYER V2 ;
			RECT 0.0215 83.9588 0.0364 83.9714 ;
		END

		ANTENNAGATEAREA 0.00027817 ;
		ANTENNADIFFAREA 0.00194719 ;
		ANTENNAPARTIALMETALAREA 0.00195671 ;
	END TD[59]

	PIN TD[5]
		USE SIGNAL ;
		DIRECTION INPUT ;
		SHAPE ABUTMENT ;
		PORT
			 LAYER M2 ;
			RECT 0.0098 7.3663 0.0481 7.4039 ;
			 LAYER M3 ;
			RECT 0.0098 7.3663 0.0481 7.4667 ;
			 LAYER V2 ;
			RECT 0.0215 7.3792 0.0364 7.3918 ;
		END

		ANTENNAGATEAREA 0.00027817 ;
		ANTENNADIFFAREA 0.00194719 ;
		ANTENNAPARTIALMETALAREA 0.00195671 ;
	END TD[5]

	PIN TD[60]
		USE SIGNAL ;
		DIRECTION INPUT ;
		SHAPE ABUTMENT ;
		PORT
			 LAYER M2 ;
			RECT 0.0098 85.2267 0.0481 85.2643 ;
			 LAYER M3 ;
			RECT 0.0098 85.1639 0.0481 85.2643 ;
			 LAYER V2 ;
			RECT 0.0215 85.2388 0.0364 85.2514 ;
		END

		ANTENNAGATEAREA 0.00027817 ;
		ANTENNADIFFAREA 0.00194719 ;
		ANTENNAPARTIALMETALAREA 0.00195671 ;
	END TD[60]

	PIN TD[61]
		USE SIGNAL ;
		DIRECTION INPUT ;
		SHAPE ABUTMENT ;
		PORT
			 LAYER M2 ;
			RECT 0.0098 86.5067 0.0481 86.5443 ;
			 LAYER M3 ;
			RECT 0.0098 86.4439 0.0481 86.5443 ;
			 LAYER V2 ;
			RECT 0.0215 86.5188 0.0364 86.5314 ;
		END

		ANTENNAGATEAREA 0.00027817 ;
		ANTENNADIFFAREA 0.00194719 ;
		ANTENNAPARTIALMETALAREA 0.00195671 ;
	END TD[61]

	PIN TD[62]
		USE SIGNAL ;
		DIRECTION INPUT ;
		SHAPE ABUTMENT ;
		PORT
			 LAYER M2 ;
			RECT 0.0098 87.7867 0.0481 87.8243 ;
			 LAYER M3 ;
			RECT 0.0098 87.7239 0.0481 87.8243 ;
			 LAYER V2 ;
			RECT 0.0215 87.7988 0.0364 87.8114 ;
		END

		ANTENNAGATEAREA 0.00027817 ;
		ANTENNADIFFAREA 0.00194719 ;
		ANTENNAPARTIALMETALAREA 0.00195671 ;
	END TD[62]

	PIN TD[63]
		USE SIGNAL ;
		DIRECTION INPUT ;
		SHAPE ABUTMENT ;
		PORT
			 LAYER M2 ;
			RECT 0.0098 89.0667 0.0481 89.1043 ;
			 LAYER M3 ;
			RECT 0.0098 89.0039 0.0481 89.1043 ;
			 LAYER V2 ;
			RECT 0.0215 89.0788 0.0364 89.0914 ;
		END

		ANTENNAGATEAREA 0.00027817 ;
		ANTENNADIFFAREA 0.00194719 ;
		ANTENNAPARTIALMETALAREA 0.00195671 ;
	END TD[63]

	PIN TD[6]
		USE SIGNAL ;
		DIRECTION INPUT ;
		SHAPE ABUTMENT ;
		PORT
			 LAYER M2 ;
			RECT 0.0098 8.6463 0.0481 8.6839 ;
			 LAYER M3 ;
			RECT 0.0098 8.6463 0.0481 8.7467 ;
			 LAYER V2 ;
			RECT 0.0215 8.6592 0.0364 8.6718 ;
		END

		ANTENNAGATEAREA 0.00027817 ;
		ANTENNADIFFAREA 0.00194719 ;
		ANTENNAPARTIALMETALAREA 0.00195671 ;
	END TD[6]

	PIN TD[7]
		USE SIGNAL ;
		DIRECTION INPUT ;
		SHAPE ABUTMENT ;
		PORT
			 LAYER M2 ;
			RECT 0.0098 9.9263 0.0481 9.9639 ;
			 LAYER M3 ;
			RECT 0.0098 9.9263 0.0481 10.0267 ;
			 LAYER V2 ;
			RECT 0.0215 9.9392 0.0364 9.9518 ;
		END

		ANTENNAGATEAREA 0.00027817 ;
		ANTENNADIFFAREA 0.00194719 ;
		ANTENNAPARTIALMETALAREA 0.00195671 ;
	END TD[7]

	PIN TD[8]
		USE SIGNAL ;
		DIRECTION INPUT ;
		SHAPE ABUTMENT ;
		PORT
			 LAYER M2 ;
			RECT 0.0098 11.2063 0.0481 11.2439 ;
			 LAYER M3 ;
			RECT 0.0098 11.2063 0.0481 11.3067 ;
			 LAYER V2 ;
			RECT 0.0215 11.2192 0.0364 11.2318 ;
		END

		ANTENNAGATEAREA 0.00027817 ;
		ANTENNADIFFAREA 0.00194719 ;
		ANTENNAPARTIALMETALAREA 0.00195671 ;
	END TD[8]

	PIN TD[9]
		USE SIGNAL ;
		DIRECTION INPUT ;
		SHAPE ABUTMENT ;
		PORT
			 LAYER M2 ;
			RECT 0.0098 12.4863 0.0481 12.5239 ;
			 LAYER M3 ;
			RECT 0.0098 12.4863 0.0481 12.5867 ;
			 LAYER V2 ;
			RECT 0.0215 12.4992 0.0364 12.5118 ;
		END

		ANTENNAGATEAREA 0.00027817 ;
		ANTENNADIFFAREA 0.00194719 ;
		ANTENNAPARTIALMETALAREA 0.00195671 ;
	END TD[9]

	PIN TEN
		USE SIGNAL ;
		DIRECTION INPUT ;
		SHAPE ABUTMENT ;
		PORT
			 LAYER M2 ;
			RECT 0.0098 42.7671 0.0481 42.8047 ;
			 LAYER M3 ;
			RECT 0.0098 42.7043 0.0481 42.8047 ;
			 LAYER V2 ;
			RECT 0.0215 42.7792 0.0364 42.7918 ;
		END

		ANTENNAGATEAREA 0.00027817 ;
		ANTENNADIFFAREA 0.00194719 ;
		ANTENNAPARTIALMETALAREA 0.00195671 ;
	END TEN

	PIN TGWEN
		USE SIGNAL ;
		DIRECTION INPUT ;
		SHAPE ABUTMENT ;
		PORT
			 LAYER M2 ;
			RECT 0.0714 43.909 0.1097 43.9467 ;
			 LAYER M3 ;
			RECT 0.0714 43.909 0.1097 44.0094 ;
			 LAYER V2 ;
			RECT 0.0831 43.9212 0.098 43.9337 ;
		END

		ANTENNAGATEAREA 0.00027817 ;
		ANTENNADIFFAREA 0.00194719 ;
		ANTENNAPARTIALMETALAREA 0.00195671 ;
	END TGWEN

	PIN TWEN[0]
		USE SIGNAL ;
		DIRECTION INPUT ;
		SHAPE ABUTMENT ;
		PORT
			 LAYER M2 ;
			RECT 0.0714 1.4306 0.1097 1.4682 ;
			 LAYER M3 ;
			RECT 0.0714 1.3678 0.1097 1.4682 ;
			 LAYER V2 ;
			RECT 0.0831 1.4435 0.098 1.4561 ;
		END

		ANTENNAGATEAREA 0.00027817 ;
		ANTENNADIFFAREA 0.00194719 ;
		ANTENNAPARTIALMETALAREA 0.00195671 ;
	END TWEN[0]

	PIN TWEN[10]
		USE SIGNAL ;
		DIRECTION INPUT ;
		SHAPE ABUTMENT ;
		PORT
			 LAYER M2 ;
			RECT 0.0714 14.2306 0.1097 14.2682 ;
			 LAYER M3 ;
			RECT 0.0714 14.1678 0.1097 14.2682 ;
			 LAYER V2 ;
			RECT 0.0831 14.2435 0.098 14.2561 ;
		END

		ANTENNAGATEAREA 0.00027817 ;
		ANTENNADIFFAREA 0.00194719 ;
		ANTENNAPARTIALMETALAREA 0.00195671 ;
	END TWEN[10]

	PIN TWEN[11]
		USE SIGNAL ;
		DIRECTION INPUT ;
		SHAPE ABUTMENT ;
		PORT
			 LAYER M2 ;
			RECT 0.0714 15.5106 0.1097 15.5482 ;
			 LAYER M3 ;
			RECT 0.0714 15.4478 0.1097 15.5482 ;
			 LAYER V2 ;
			RECT 0.0831 15.5235 0.098 15.5361 ;
		END

		ANTENNAGATEAREA 0.00027817 ;
		ANTENNADIFFAREA 0.00194719 ;
		ANTENNAPARTIALMETALAREA 0.00195671 ;
	END TWEN[11]

	PIN TWEN[12]
		USE SIGNAL ;
		DIRECTION INPUT ;
		SHAPE ABUTMENT ;
		PORT
			 LAYER M2 ;
			RECT 0.0714 16.7906 0.1097 16.8282 ;
			 LAYER M3 ;
			RECT 0.0714 16.7278 0.1097 16.8282 ;
			 LAYER V2 ;
			RECT 0.0831 16.8035 0.098 16.8161 ;
		END

		ANTENNAGATEAREA 0.00027817 ;
		ANTENNADIFFAREA 0.00194719 ;
		ANTENNAPARTIALMETALAREA 0.00195671 ;
	END TWEN[12]

	PIN TWEN[13]
		USE SIGNAL ;
		DIRECTION INPUT ;
		SHAPE ABUTMENT ;
		PORT
			 LAYER M2 ;
			RECT 0.0714 18.0706 0.1097 18.1082 ;
			 LAYER M3 ;
			RECT 0.0714 18.0078 0.1097 18.1082 ;
			 LAYER V2 ;
			RECT 0.0831 18.0835 0.098 18.0961 ;
		END

		ANTENNAGATEAREA 0.00027817 ;
		ANTENNADIFFAREA 0.00194719 ;
		ANTENNAPARTIALMETALAREA 0.00195671 ;
	END TWEN[13]

	PIN TWEN[14]
		USE SIGNAL ;
		DIRECTION INPUT ;
		SHAPE ABUTMENT ;
		PORT
			 LAYER M2 ;
			RECT 0.0714 19.3506 0.1097 19.3882 ;
			 LAYER M3 ;
			RECT 0.0714 19.2878 0.1097 19.3882 ;
			 LAYER V2 ;
			RECT 0.0831 19.3635 0.098 19.3761 ;
		END

		ANTENNAGATEAREA 0.00027817 ;
		ANTENNADIFFAREA 0.00194719 ;
		ANTENNAPARTIALMETALAREA 0.00195671 ;
	END TWEN[14]

	PIN TWEN[15]
		USE SIGNAL ;
		DIRECTION INPUT ;
		SHAPE ABUTMENT ;
		PORT
			 LAYER M2 ;
			RECT 0.0714 20.6306 0.1097 20.6682 ;
			 LAYER M3 ;
			RECT 0.0714 20.5678 0.1097 20.6682 ;
			 LAYER V2 ;
			RECT 0.0831 20.6435 0.098 20.6561 ;
		END

		ANTENNAGATEAREA 0.00027817 ;
		ANTENNADIFFAREA 0.00194719 ;
		ANTENNAPARTIALMETALAREA 0.00195671 ;
	END TWEN[15]

	PIN TWEN[16]
		USE SIGNAL ;
		DIRECTION INPUT ;
		SHAPE ABUTMENT ;
		PORT
			 LAYER M2 ;
			RECT 0.0714 21.9106 0.1097 21.9482 ;
			 LAYER M3 ;
			RECT 0.0714 21.8478 0.1097 21.9482 ;
			 LAYER V2 ;
			RECT 0.0831 21.9235 0.098 21.9361 ;
		END

		ANTENNAGATEAREA 0.00027817 ;
		ANTENNADIFFAREA 0.00194719 ;
		ANTENNAPARTIALMETALAREA 0.00195671 ;
	END TWEN[16]

	PIN TWEN[17]
		USE SIGNAL ;
		DIRECTION INPUT ;
		SHAPE ABUTMENT ;
		PORT
			 LAYER M2 ;
			RECT 0.0714 23.1906 0.1097 23.2282 ;
			 LAYER M3 ;
			RECT 0.0714 23.1278 0.1097 23.2282 ;
			 LAYER V2 ;
			RECT 0.0831 23.2035 0.098 23.2161 ;
		END

		ANTENNAGATEAREA 0.00027817 ;
		ANTENNADIFFAREA 0.00194719 ;
		ANTENNAPARTIALMETALAREA 0.00195671 ;
	END TWEN[17]

	PIN TWEN[18]
		USE SIGNAL ;
		DIRECTION INPUT ;
		SHAPE ABUTMENT ;
		PORT
			 LAYER M2 ;
			RECT 0.0714 24.4706 0.1097 24.5082 ;
			 LAYER M3 ;
			RECT 0.0714 24.4078 0.1097 24.5082 ;
			 LAYER V2 ;
			RECT 0.0831 24.4835 0.098 24.4961 ;
		END

		ANTENNAGATEAREA 0.00027817 ;
		ANTENNADIFFAREA 0.00194719 ;
		ANTENNAPARTIALMETALAREA 0.00195671 ;
	END TWEN[18]

	PIN TWEN[19]
		USE SIGNAL ;
		DIRECTION INPUT ;
		SHAPE ABUTMENT ;
		PORT
			 LAYER M2 ;
			RECT 0.0714 25.7506 0.1097 25.7882 ;
			 LAYER M3 ;
			RECT 0.0714 25.6878 0.1097 25.7882 ;
			 LAYER V2 ;
			RECT 0.0831 25.7635 0.098 25.7761 ;
		END

		ANTENNAGATEAREA 0.00027817 ;
		ANTENNADIFFAREA 0.00194719 ;
		ANTENNAPARTIALMETALAREA 0.00195671 ;
	END TWEN[19]

	PIN TWEN[1]
		USE SIGNAL ;
		DIRECTION INPUT ;
		SHAPE ABUTMENT ;
		PORT
			 LAYER M2 ;
			RECT 0.0714 2.7106 0.1097 2.7482 ;
			 LAYER M3 ;
			RECT 0.0714 2.6478 0.1097 2.7482 ;
			 LAYER V2 ;
			RECT 0.0831 2.7235 0.098 2.7361 ;
		END

		ANTENNAGATEAREA 0.00027817 ;
		ANTENNADIFFAREA 0.00194719 ;
		ANTENNAPARTIALMETALAREA 0.00195671 ;
	END TWEN[1]

	PIN TWEN[20]
		USE SIGNAL ;
		DIRECTION INPUT ;
		SHAPE ABUTMENT ;
		PORT
			 LAYER M2 ;
			RECT 0.0714 27.0306 0.1097 27.0682 ;
			 LAYER M3 ;
			RECT 0.0714 26.9678 0.1097 27.0682 ;
			 LAYER V2 ;
			RECT 0.0831 27.0435 0.098 27.0561 ;
		END

		ANTENNAGATEAREA 0.00027817 ;
		ANTENNADIFFAREA 0.00194719 ;
		ANTENNAPARTIALMETALAREA 0.00195671 ;
	END TWEN[20]

	PIN TWEN[21]
		USE SIGNAL ;
		DIRECTION INPUT ;
		SHAPE ABUTMENT ;
		PORT
			 LAYER M2 ;
			RECT 0.0714 28.3106 0.1097 28.3482 ;
			 LAYER M3 ;
			RECT 0.0714 28.2478 0.1097 28.3482 ;
			 LAYER V2 ;
			RECT 0.0831 28.3235 0.098 28.3361 ;
		END

		ANTENNAGATEAREA 0.00027817 ;
		ANTENNADIFFAREA 0.00194719 ;
		ANTENNAPARTIALMETALAREA 0.00195671 ;
	END TWEN[21]

	PIN TWEN[22]
		USE SIGNAL ;
		DIRECTION INPUT ;
		SHAPE ABUTMENT ;
		PORT
			 LAYER M2 ;
			RECT 0.0714 29.5906 0.1097 29.6282 ;
			 LAYER M3 ;
			RECT 0.0714 29.5278 0.1097 29.6282 ;
			 LAYER V2 ;
			RECT 0.0831 29.6035 0.098 29.6161 ;
		END

		ANTENNAGATEAREA 0.00027817 ;
		ANTENNADIFFAREA 0.00194719 ;
		ANTENNAPARTIALMETALAREA 0.00195671 ;
	END TWEN[22]

	PIN TWEN[23]
		USE SIGNAL ;
		DIRECTION INPUT ;
		SHAPE ABUTMENT ;
		PORT
			 LAYER M2 ;
			RECT 0.0714 30.8706 0.1097 30.9082 ;
			 LAYER M3 ;
			RECT 0.0714 30.8078 0.1097 30.9082 ;
			 LAYER V2 ;
			RECT 0.0831 30.8835 0.098 30.8961 ;
		END

		ANTENNAGATEAREA 0.00027817 ;
		ANTENNADIFFAREA 0.00194719 ;
		ANTENNAPARTIALMETALAREA 0.00195671 ;
	END TWEN[23]

	PIN TWEN[24]
		USE SIGNAL ;
		DIRECTION INPUT ;
		SHAPE ABUTMENT ;
		PORT
			 LAYER M2 ;
			RECT 0.0714 32.1506 0.1097 32.1882 ;
			 LAYER M3 ;
			RECT 0.0714 32.0878 0.1097 32.1882 ;
			 LAYER V2 ;
			RECT 0.0831 32.1635 0.098 32.1761 ;
		END

		ANTENNAGATEAREA 0.00027817 ;
		ANTENNADIFFAREA 0.00194719 ;
		ANTENNAPARTIALMETALAREA 0.00195671 ;
	END TWEN[24]

	PIN TWEN[25]
		USE SIGNAL ;
		DIRECTION INPUT ;
		SHAPE ABUTMENT ;
		PORT
			 LAYER M2 ;
			RECT 0.0714 33.4306 0.1097 33.4682 ;
			 LAYER M3 ;
			RECT 0.0714 33.3678 0.1097 33.4682 ;
			 LAYER V2 ;
			RECT 0.0831 33.4435 0.098 33.4561 ;
		END

		ANTENNAGATEAREA 0.00027817 ;
		ANTENNADIFFAREA 0.00194719 ;
		ANTENNAPARTIALMETALAREA 0.00195671 ;
	END TWEN[25]

	PIN TWEN[26]
		USE SIGNAL ;
		DIRECTION INPUT ;
		SHAPE ABUTMENT ;
		PORT
			 LAYER M2 ;
			RECT 0.0714 34.7106 0.1097 34.7482 ;
			 LAYER M3 ;
			RECT 0.0714 34.6478 0.1097 34.7482 ;
			 LAYER V2 ;
			RECT 0.0831 34.7235 0.098 34.7361 ;
		END

		ANTENNAGATEAREA 0.00027817 ;
		ANTENNADIFFAREA 0.00194719 ;
		ANTENNAPARTIALMETALAREA 0.00195671 ;
	END TWEN[26]

	PIN TWEN[27]
		USE SIGNAL ;
		DIRECTION INPUT ;
		SHAPE ABUTMENT ;
		PORT
			 LAYER M2 ;
			RECT 0.0714 35.9906 0.1097 36.0282 ;
			 LAYER M3 ;
			RECT 0.0714 35.9278 0.1097 36.0282 ;
			 LAYER V2 ;
			RECT 0.0831 36.0035 0.098 36.0161 ;
		END

		ANTENNAGATEAREA 0.00027817 ;
		ANTENNADIFFAREA 0.00194719 ;
		ANTENNAPARTIALMETALAREA 0.00195671 ;
	END TWEN[27]

	PIN TWEN[28]
		USE SIGNAL ;
		DIRECTION INPUT ;
		SHAPE ABUTMENT ;
		PORT
			 LAYER M2 ;
			RECT 0.0714 37.2706 0.1097 37.3082 ;
			 LAYER M3 ;
			RECT 0.0714 37.2078 0.1097 37.3082 ;
			 LAYER V2 ;
			RECT 0.0831 37.2835 0.098 37.2961 ;
		END

		ANTENNAGATEAREA 0.00027817 ;
		ANTENNADIFFAREA 0.00194719 ;
		ANTENNAPARTIALMETALAREA 0.00195671 ;
	END TWEN[28]

	PIN TWEN[29]
		USE SIGNAL ;
		DIRECTION INPUT ;
		SHAPE ABUTMENT ;
		PORT
			 LAYER M2 ;
			RECT 0.0714 38.5506 0.1097 38.5882 ;
			 LAYER M3 ;
			RECT 0.0714 38.4878 0.1097 38.5882 ;
			 LAYER V2 ;
			RECT 0.0831 38.5635 0.098 38.5761 ;
		END

		ANTENNAGATEAREA 0.00027817 ;
		ANTENNADIFFAREA 0.00194719 ;
		ANTENNAPARTIALMETALAREA 0.00195671 ;
	END TWEN[29]

	PIN TWEN[2]
		USE SIGNAL ;
		DIRECTION INPUT ;
		SHAPE ABUTMENT ;
		PORT
			 LAYER M2 ;
			RECT 0.0714 3.9906 0.1097 4.0282 ;
			 LAYER M3 ;
			RECT 0.0714 3.9278 0.1097 4.0282 ;
			 LAYER V2 ;
			RECT 0.0831 4.0035 0.098 4.0161 ;
		END

		ANTENNAGATEAREA 0.00027817 ;
		ANTENNADIFFAREA 0.00194719 ;
		ANTENNAPARTIALMETALAREA 0.00195671 ;
	END TWEN[2]

	PIN TWEN[30]
		USE SIGNAL ;
		DIRECTION INPUT ;
		SHAPE ABUTMENT ;
		PORT
			 LAYER M2 ;
			RECT 0.0714 39.8306 0.1097 39.8682 ;
			 LAYER M3 ;
			RECT 0.0714 39.7678 0.1097 39.8682 ;
			 LAYER V2 ;
			RECT 0.0831 39.8435 0.098 39.8561 ;
		END

		ANTENNAGATEAREA 0.00027817 ;
		ANTENNADIFFAREA 0.00194719 ;
		ANTENNAPARTIALMETALAREA 0.00195671 ;
	END TWEN[30]

	PIN TWEN[31]
		USE SIGNAL ;
		DIRECTION INPUT ;
		SHAPE ABUTMENT ;
		PORT
			 LAYER M2 ;
			RECT 0.0714 41.1106 0.1097 41.1482 ;
			 LAYER M3 ;
			RECT 0.0714 41.0478 0.1097 41.1482 ;
			 LAYER V2 ;
			RECT 0.0831 41.1235 0.098 41.1361 ;
		END

		ANTENNAGATEAREA 0.00027817 ;
		ANTENNADIFFAREA 0.00194719 ;
		ANTENNAPARTIALMETALAREA 0.00195671 ;
	END TWEN[31]

	PIN TWEN[32]
		USE SIGNAL ;
		DIRECTION INPUT ;
		SHAPE ABUTMENT ;
		PORT
			 LAYER M2 ;
			RECT 0.0714 48.9224 0.1097 48.96 ;
			 LAYER M3 ;
			RECT 0.0714 48.9224 0.1097 49.0227 ;
			 LAYER V2 ;
			RECT 0.0831 48.9345 0.098 48.9471 ;
		END

		ANTENNAGATEAREA 0.00027817 ;
		ANTENNADIFFAREA 0.00194719 ;
		ANTENNAPARTIALMETALAREA 0.00195671 ;
	END TWEN[32]

	PIN TWEN[33]
		USE SIGNAL ;
		DIRECTION INPUT ;
		SHAPE ABUTMENT ;
		PORT
			 LAYER M2 ;
			RECT 0.0714 50.2024 0.1097 50.24 ;
			 LAYER M3 ;
			RECT 0.0714 50.2024 0.1097 50.3027 ;
			 LAYER V2 ;
			RECT 0.0831 50.2145 0.098 50.2271 ;
		END

		ANTENNAGATEAREA 0.00027817 ;
		ANTENNADIFFAREA 0.00194719 ;
		ANTENNAPARTIALMETALAREA 0.00195671 ;
	END TWEN[33]

	PIN TWEN[34]
		USE SIGNAL ;
		DIRECTION INPUT ;
		SHAPE ABUTMENT ;
		PORT
			 LAYER M2 ;
			RECT 0.0714 51.4824 0.1097 51.52 ;
			 LAYER M3 ;
			RECT 0.0714 51.4824 0.1097 51.5827 ;
			 LAYER V2 ;
			RECT 0.0831 51.4945 0.098 51.5071 ;
		END

		ANTENNAGATEAREA 0.00027817 ;
		ANTENNADIFFAREA 0.00194719 ;
		ANTENNAPARTIALMETALAREA 0.00195671 ;
	END TWEN[34]

	PIN TWEN[35]
		USE SIGNAL ;
		DIRECTION INPUT ;
		SHAPE ABUTMENT ;
		PORT
			 LAYER M2 ;
			RECT 0.0714 52.7624 0.1097 52.8 ;
			 LAYER M3 ;
			RECT 0.0714 52.7624 0.1097 52.8627 ;
			 LAYER V2 ;
			RECT 0.0831 52.7745 0.098 52.7871 ;
		END

		ANTENNAGATEAREA 0.00027817 ;
		ANTENNADIFFAREA 0.00194719 ;
		ANTENNAPARTIALMETALAREA 0.00195671 ;
	END TWEN[35]

	PIN TWEN[36]
		USE SIGNAL ;
		DIRECTION INPUT ;
		SHAPE ABUTMENT ;
		PORT
			 LAYER M2 ;
			RECT 0.0714 54.0424 0.1097 54.08 ;
			 LAYER M3 ;
			RECT 0.0714 54.0424 0.1097 54.1427 ;
			 LAYER V2 ;
			RECT 0.0831 54.0545 0.098 54.0671 ;
		END

		ANTENNAGATEAREA 0.00027817 ;
		ANTENNADIFFAREA 0.00194719 ;
		ANTENNAPARTIALMETALAREA 0.00195671 ;
	END TWEN[36]

	PIN TWEN[37]
		USE SIGNAL ;
		DIRECTION INPUT ;
		SHAPE ABUTMENT ;
		PORT
			 LAYER M2 ;
			RECT 0.0714 55.3224 0.1097 55.36 ;
			 LAYER M3 ;
			RECT 0.0714 55.3224 0.1097 55.4227 ;
			 LAYER V2 ;
			RECT 0.0831 55.3345 0.098 55.3471 ;
		END

		ANTENNAGATEAREA 0.00027817 ;
		ANTENNADIFFAREA 0.00194719 ;
		ANTENNAPARTIALMETALAREA 0.00195671 ;
	END TWEN[37]

	PIN TWEN[38]
		USE SIGNAL ;
		DIRECTION INPUT ;
		SHAPE ABUTMENT ;
		PORT
			 LAYER M2 ;
			RECT 0.0714 56.6024 0.1097 56.64 ;
			 LAYER M3 ;
			RECT 0.0714 56.6024 0.1097 56.7027 ;
			 LAYER V2 ;
			RECT 0.0831 56.6145 0.098 56.6271 ;
		END

		ANTENNAGATEAREA 0.00027817 ;
		ANTENNADIFFAREA 0.00194719 ;
		ANTENNAPARTIALMETALAREA 0.00195671 ;
	END TWEN[38]

	PIN TWEN[39]
		USE SIGNAL ;
		DIRECTION INPUT ;
		SHAPE ABUTMENT ;
		PORT
			 LAYER M2 ;
			RECT 0.0714 57.8824 0.1097 57.92 ;
			 LAYER M3 ;
			RECT 0.0714 57.8824 0.1097 57.9827 ;
			 LAYER V2 ;
			RECT 0.0831 57.8945 0.098 57.9071 ;
		END

		ANTENNAGATEAREA 0.00027817 ;
		ANTENNADIFFAREA 0.00194719 ;
		ANTENNAPARTIALMETALAREA 0.00195671 ;
	END TWEN[39]

	PIN TWEN[3]
		USE SIGNAL ;
		DIRECTION INPUT ;
		SHAPE ABUTMENT ;
		PORT
			 LAYER M2 ;
			RECT 0.0714 5.2706 0.1097 5.3082 ;
			 LAYER M3 ;
			RECT 0.0714 5.2078 0.1097 5.3082 ;
			 LAYER V2 ;
			RECT 0.0831 5.2835 0.098 5.2961 ;
		END

		ANTENNAGATEAREA 0.00027817 ;
		ANTENNADIFFAREA 0.00194719 ;
		ANTENNAPARTIALMETALAREA 0.00195671 ;
	END TWEN[3]

	PIN TWEN[40]
		USE SIGNAL ;
		DIRECTION INPUT ;
		SHAPE ABUTMENT ;
		PORT
			 LAYER M2 ;
			RECT 0.0714 59.1624 0.1097 59.2 ;
			 LAYER M3 ;
			RECT 0.0714 59.1624 0.1097 59.2627 ;
			 LAYER V2 ;
			RECT 0.0831 59.1745 0.098 59.1871 ;
		END

		ANTENNAGATEAREA 0.00027817 ;
		ANTENNADIFFAREA 0.00194719 ;
		ANTENNAPARTIALMETALAREA 0.00195671 ;
	END TWEN[40]

	PIN TWEN[41]
		USE SIGNAL ;
		DIRECTION INPUT ;
		SHAPE ABUTMENT ;
		PORT
			 LAYER M2 ;
			RECT 0.0714 60.4424 0.1097 60.48 ;
			 LAYER M3 ;
			RECT 0.0714 60.4424 0.1097 60.5427 ;
			 LAYER V2 ;
			RECT 0.0831 60.4545 0.098 60.4671 ;
		END

		ANTENNAGATEAREA 0.00027817 ;
		ANTENNADIFFAREA 0.00194719 ;
		ANTENNAPARTIALMETALAREA 0.00195671 ;
	END TWEN[41]

	PIN TWEN[42]
		USE SIGNAL ;
		DIRECTION INPUT ;
		SHAPE ABUTMENT ;
		PORT
			 LAYER M2 ;
			RECT 0.0714 61.7224 0.1097 61.76 ;
			 LAYER M3 ;
			RECT 0.0714 61.7224 0.1097 61.8227 ;
			 LAYER V2 ;
			RECT 0.0831 61.7345 0.098 61.7471 ;
		END

		ANTENNAGATEAREA 0.00027817 ;
		ANTENNADIFFAREA 0.00194719 ;
		ANTENNAPARTIALMETALAREA 0.00195671 ;
	END TWEN[42]

	PIN TWEN[43]
		USE SIGNAL ;
		DIRECTION INPUT ;
		SHAPE ABUTMENT ;
		PORT
			 LAYER M2 ;
			RECT 0.0714 63.0024 0.1097 63.04 ;
			 LAYER M3 ;
			RECT 0.0714 63.0024 0.1097 63.1027 ;
			 LAYER V2 ;
			RECT 0.0831 63.0145 0.098 63.0271 ;
		END

		ANTENNAGATEAREA 0.00027817 ;
		ANTENNADIFFAREA 0.00194719 ;
		ANTENNAPARTIALMETALAREA 0.00195671 ;
	END TWEN[43]

	PIN TWEN[44]
		USE SIGNAL ;
		DIRECTION INPUT ;
		SHAPE ABUTMENT ;
		PORT
			 LAYER M2 ;
			RECT 0.0714 64.2824 0.1097 64.32 ;
			 LAYER M3 ;
			RECT 0.0714 64.2824 0.1097 64.3827 ;
			 LAYER V2 ;
			RECT 0.0831 64.2945 0.098 64.3071 ;
		END

		ANTENNAGATEAREA 0.00027817 ;
		ANTENNADIFFAREA 0.00194719 ;
		ANTENNAPARTIALMETALAREA 0.00195671 ;
	END TWEN[44]

	PIN TWEN[45]
		USE SIGNAL ;
		DIRECTION INPUT ;
		SHAPE ABUTMENT ;
		PORT
			 LAYER M2 ;
			RECT 0.0714 65.5624 0.1097 65.6 ;
			 LAYER M3 ;
			RECT 0.0714 65.5624 0.1097 65.6627 ;
			 LAYER V2 ;
			RECT 0.0831 65.5745 0.098 65.5871 ;
		END

		ANTENNAGATEAREA 0.00027817 ;
		ANTENNADIFFAREA 0.00194719 ;
		ANTENNAPARTIALMETALAREA 0.00195671 ;
	END TWEN[45]

	PIN TWEN[46]
		USE SIGNAL ;
		DIRECTION INPUT ;
		SHAPE ABUTMENT ;
		PORT
			 LAYER M2 ;
			RECT 0.0714 66.8424 0.1097 66.88 ;
			 LAYER M3 ;
			RECT 0.0714 66.8424 0.1097 66.9427 ;
			 LAYER V2 ;
			RECT 0.0831 66.8545 0.098 66.8671 ;
		END

		ANTENNAGATEAREA 0.00027817 ;
		ANTENNADIFFAREA 0.00194719 ;
		ANTENNAPARTIALMETALAREA 0.00195671 ;
	END TWEN[46]

	PIN TWEN[47]
		USE SIGNAL ;
		DIRECTION INPUT ;
		SHAPE ABUTMENT ;
		PORT
			 LAYER M2 ;
			RECT 0.0714 68.1224 0.1097 68.16 ;
			 LAYER M3 ;
			RECT 0.0714 68.1224 0.1097 68.2227 ;
			 LAYER V2 ;
			RECT 0.0831 68.1345 0.098 68.1471 ;
		END

		ANTENNAGATEAREA 0.00027817 ;
		ANTENNADIFFAREA 0.00194719 ;
		ANTENNAPARTIALMETALAREA 0.00195671 ;
	END TWEN[47]

	PIN TWEN[48]
		USE SIGNAL ;
		DIRECTION INPUT ;
		SHAPE ABUTMENT ;
		PORT
			 LAYER M2 ;
			RECT 0.0714 69.4024 0.1097 69.44 ;
			 LAYER M3 ;
			RECT 0.0714 69.4024 0.1097 69.5027 ;
			 LAYER V2 ;
			RECT 0.0831 69.4145 0.098 69.4271 ;
		END

		ANTENNAGATEAREA 0.00027817 ;
		ANTENNADIFFAREA 0.00194719 ;
		ANTENNAPARTIALMETALAREA 0.00195671 ;
	END TWEN[48]

	PIN TWEN[49]
		USE SIGNAL ;
		DIRECTION INPUT ;
		SHAPE ABUTMENT ;
		PORT
			 LAYER M2 ;
			RECT 0.0714 70.6824 0.1097 70.72 ;
			 LAYER M3 ;
			RECT 0.0714 70.6824 0.1097 70.7827 ;
			 LAYER V2 ;
			RECT 0.0831 70.6945 0.098 70.7071 ;
		END

		ANTENNAGATEAREA 0.00027817 ;
		ANTENNADIFFAREA 0.00194719 ;
		ANTENNAPARTIALMETALAREA 0.00195671 ;
	END TWEN[49]

	PIN TWEN[4]
		USE SIGNAL ;
		DIRECTION INPUT ;
		SHAPE ABUTMENT ;
		PORT
			 LAYER M2 ;
			RECT 0.0714 6.5506 0.1097 6.5882 ;
			 LAYER M3 ;
			RECT 0.0714 6.4878 0.1097 6.5882 ;
			 LAYER V2 ;
			RECT 0.0831 6.5635 0.098 6.5761 ;
		END

		ANTENNAGATEAREA 0.00027817 ;
		ANTENNADIFFAREA 0.00194719 ;
		ANTENNAPARTIALMETALAREA 0.00195671 ;
	END TWEN[4]

	PIN TWEN[50]
		USE SIGNAL ;
		DIRECTION INPUT ;
		SHAPE ABUTMENT ;
		PORT
			 LAYER M2 ;
			RECT 0.0714 71.9624 0.1097 72 ;
			 LAYER M3 ;
			RECT 0.0714 71.9624 0.1097 72.0627 ;
			 LAYER V2 ;
			RECT 0.0831 71.9745 0.098 71.9871 ;
		END

		ANTENNAGATEAREA 0.00027817 ;
		ANTENNADIFFAREA 0.00194719 ;
		ANTENNAPARTIALMETALAREA 0.00195671 ;
	END TWEN[50]

	PIN TWEN[51]
		USE SIGNAL ;
		DIRECTION INPUT ;
		SHAPE ABUTMENT ;
		PORT
			 LAYER M2 ;
			RECT 0.0714 73.2424 0.1097 73.28 ;
			 LAYER M3 ;
			RECT 0.0714 73.2424 0.1097 73.3427 ;
			 LAYER V2 ;
			RECT 0.0831 73.2545 0.098 73.2671 ;
		END

		ANTENNAGATEAREA 0.00027817 ;
		ANTENNADIFFAREA 0.00194719 ;
		ANTENNAPARTIALMETALAREA 0.00195671 ;
	END TWEN[51]

	PIN TWEN[52]
		USE SIGNAL ;
		DIRECTION INPUT ;
		SHAPE ABUTMENT ;
		PORT
			 LAYER M2 ;
			RECT 0.0714 74.5224 0.1097 74.56 ;
			 LAYER M3 ;
			RECT 0.0714 74.5224 0.1097 74.6227 ;
			 LAYER V2 ;
			RECT 0.0831 74.5345 0.098 74.5471 ;
		END

		ANTENNAGATEAREA 0.00027817 ;
		ANTENNADIFFAREA 0.00194719 ;
		ANTENNAPARTIALMETALAREA 0.00195671 ;
	END TWEN[52]

	PIN TWEN[53]
		USE SIGNAL ;
		DIRECTION INPUT ;
		SHAPE ABUTMENT ;
		PORT
			 LAYER M2 ;
			RECT 0.0714 75.8024 0.1097 75.84 ;
			 LAYER M3 ;
			RECT 0.0714 75.8024 0.1097 75.9027 ;
			 LAYER V2 ;
			RECT 0.0831 75.8145 0.098 75.8271 ;
		END

		ANTENNAGATEAREA 0.00027817 ;
		ANTENNADIFFAREA 0.00194719 ;
		ANTENNAPARTIALMETALAREA 0.00195671 ;
	END TWEN[53]

	PIN TWEN[54]
		USE SIGNAL ;
		DIRECTION INPUT ;
		SHAPE ABUTMENT ;
		PORT
			 LAYER M2 ;
			RECT 0.0714 77.0824 0.1097 77.12 ;
			 LAYER M3 ;
			RECT 0.0714 77.0824 0.1097 77.1827 ;
			 LAYER V2 ;
			RECT 0.0831 77.0945 0.098 77.1071 ;
		END

		ANTENNAGATEAREA 0.00027817 ;
		ANTENNADIFFAREA 0.00194719 ;
		ANTENNAPARTIALMETALAREA 0.00195671 ;
	END TWEN[54]

	PIN TWEN[55]
		USE SIGNAL ;
		DIRECTION INPUT ;
		SHAPE ABUTMENT ;
		PORT
			 LAYER M2 ;
			RECT 0.0714 78.3624 0.1097 78.4 ;
			 LAYER M3 ;
			RECT 0.0714 78.3624 0.1097 78.4627 ;
			 LAYER V2 ;
			RECT 0.0831 78.3745 0.098 78.3871 ;
		END

		ANTENNAGATEAREA 0.00027817 ;
		ANTENNADIFFAREA 0.00194719 ;
		ANTENNAPARTIALMETALAREA 0.00195671 ;
	END TWEN[55]

	PIN TWEN[56]
		USE SIGNAL ;
		DIRECTION INPUT ;
		SHAPE ABUTMENT ;
		PORT
			 LAYER M2 ;
			RECT 0.0714 79.6424 0.1097 79.68 ;
			 LAYER M3 ;
			RECT 0.0714 79.6424 0.1097 79.7427 ;
			 LAYER V2 ;
			RECT 0.0831 79.6545 0.098 79.6671 ;
		END

		ANTENNAGATEAREA 0.00027817 ;
		ANTENNADIFFAREA 0.00194719 ;
		ANTENNAPARTIALMETALAREA 0.00195671 ;
	END TWEN[56]

	PIN TWEN[57]
		USE SIGNAL ;
		DIRECTION INPUT ;
		SHAPE ABUTMENT ;
		PORT
			 LAYER M2 ;
			RECT 0.0714 80.9224 0.1097 80.96 ;
			 LAYER M3 ;
			RECT 0.0714 80.9224 0.1097 81.0227 ;
			 LAYER V2 ;
			RECT 0.0831 80.9345 0.098 80.9471 ;
		END

		ANTENNAGATEAREA 0.00027817 ;
		ANTENNADIFFAREA 0.00194719 ;
		ANTENNAPARTIALMETALAREA 0.00195671 ;
	END TWEN[57]

	PIN TWEN[58]
		USE SIGNAL ;
		DIRECTION INPUT ;
		SHAPE ABUTMENT ;
		PORT
			 LAYER M2 ;
			RECT 0.0714 82.2024 0.1097 82.24 ;
			 LAYER M3 ;
			RECT 0.0714 82.2024 0.1097 82.3027 ;
			 LAYER V2 ;
			RECT 0.0831 82.2145 0.098 82.2271 ;
		END

		ANTENNAGATEAREA 0.00027817 ;
		ANTENNADIFFAREA 0.00194719 ;
		ANTENNAPARTIALMETALAREA 0.00195671 ;
	END TWEN[58]

	PIN TWEN[59]
		USE SIGNAL ;
		DIRECTION INPUT ;
		SHAPE ABUTMENT ;
		PORT
			 LAYER M2 ;
			RECT 0.0714 83.4824 0.1097 83.52 ;
			 LAYER M3 ;
			RECT 0.0714 83.4824 0.1097 83.5827 ;
			 LAYER V2 ;
			RECT 0.0831 83.4945 0.098 83.5071 ;
		END

		ANTENNAGATEAREA 0.00027817 ;
		ANTENNADIFFAREA 0.00194719 ;
		ANTENNAPARTIALMETALAREA 0.00195671 ;
	END TWEN[59]

	PIN TWEN[5]
		USE SIGNAL ;
		DIRECTION INPUT ;
		SHAPE ABUTMENT ;
		PORT
			 LAYER M2 ;
			RECT 0.0714 7.8306 0.1097 7.8682 ;
			 LAYER M3 ;
			RECT 0.0714 7.7678 0.1097 7.8682 ;
			 LAYER V2 ;
			RECT 0.0831 7.8435 0.098 7.8561 ;
		END

		ANTENNAGATEAREA 0.00027817 ;
		ANTENNADIFFAREA 0.00194719 ;
		ANTENNAPARTIALMETALAREA 0.00195671 ;
	END TWEN[5]

	PIN TWEN[60]
		USE SIGNAL ;
		DIRECTION INPUT ;
		SHAPE ABUTMENT ;
		PORT
			 LAYER M2 ;
			RECT 0.0714 84.7624 0.1097 84.8 ;
			 LAYER M3 ;
			RECT 0.0714 84.7624 0.1097 84.8627 ;
			 LAYER V2 ;
			RECT 0.0831 84.7745 0.098 84.7871 ;
		END

		ANTENNAGATEAREA 0.00027817 ;
		ANTENNADIFFAREA 0.00194719 ;
		ANTENNAPARTIALMETALAREA 0.00195671 ;
	END TWEN[60]

	PIN TWEN[61]
		USE SIGNAL ;
		DIRECTION INPUT ;
		SHAPE ABUTMENT ;
		PORT
			 LAYER M2 ;
			RECT 0.0714 86.0424 0.1097 86.08 ;
			 LAYER M3 ;
			RECT 0.0714 86.0424 0.1097 86.1427 ;
			 LAYER V2 ;
			RECT 0.0831 86.0545 0.098 86.0671 ;
		END

		ANTENNAGATEAREA 0.00027817 ;
		ANTENNADIFFAREA 0.00194719 ;
		ANTENNAPARTIALMETALAREA 0.00195671 ;
	END TWEN[61]

	PIN TWEN[62]
		USE SIGNAL ;
		DIRECTION INPUT ;
		SHAPE ABUTMENT ;
		PORT
			 LAYER M2 ;
			RECT 0.0714 87.3224 0.1097 87.36 ;
			 LAYER M3 ;
			RECT 0.0714 87.3224 0.1097 87.4227 ;
			 LAYER V2 ;
			RECT 0.0831 87.3345 0.098 87.3471 ;
		END

		ANTENNAGATEAREA 0.00027817 ;
		ANTENNADIFFAREA 0.00194719 ;
		ANTENNAPARTIALMETALAREA 0.00195671 ;
	END TWEN[62]

	PIN TWEN[63]
		USE SIGNAL ;
		DIRECTION INPUT ;
		SHAPE ABUTMENT ;
		PORT
			 LAYER M2 ;
			RECT 0.0714 88.6024 0.1097 88.64 ;
			 LAYER M3 ;
			RECT 0.0714 88.6024 0.1097 88.7027 ;
			 LAYER V2 ;
			RECT 0.0831 88.6145 0.098 88.6271 ;
		END

		ANTENNAGATEAREA 0.00027817 ;
		ANTENNADIFFAREA 0.00194719 ;
		ANTENNAPARTIALMETALAREA 0.00195671 ;
	END TWEN[63]

	PIN TWEN[6]
		USE SIGNAL ;
		DIRECTION INPUT ;
		SHAPE ABUTMENT ;
		PORT
			 LAYER M2 ;
			RECT 0.0714 9.1106 0.1097 9.1482 ;
			 LAYER M3 ;
			RECT 0.0714 9.0478 0.1097 9.1482 ;
			 LAYER V2 ;
			RECT 0.0831 9.1235 0.098 9.1361 ;
		END

		ANTENNAGATEAREA 0.00027817 ;
		ANTENNADIFFAREA 0.00194719 ;
		ANTENNAPARTIALMETALAREA 0.00195671 ;
	END TWEN[6]

	PIN TWEN[7]
		USE SIGNAL ;
		DIRECTION INPUT ;
		SHAPE ABUTMENT ;
		PORT
			 LAYER M2 ;
			RECT 0.0714 10.3906 0.1097 10.4282 ;
			 LAYER M3 ;
			RECT 0.0714 10.3278 0.1097 10.4282 ;
			 LAYER V2 ;
			RECT 0.0831 10.4035 0.098 10.4161 ;
		END

		ANTENNAGATEAREA 0.00027817 ;
		ANTENNADIFFAREA 0.00194719 ;
		ANTENNAPARTIALMETALAREA 0.00195671 ;
	END TWEN[7]

	PIN TWEN[8]
		USE SIGNAL ;
		DIRECTION INPUT ;
		SHAPE ABUTMENT ;
		PORT
			 LAYER M2 ;
			RECT 0.0714 11.6706 0.1097 11.7082 ;
			 LAYER M3 ;
			RECT 0.0714 11.6078 0.1097 11.7082 ;
			 LAYER V2 ;
			RECT 0.0831 11.6835 0.098 11.6961 ;
		END

		ANTENNAGATEAREA 0.00027817 ;
		ANTENNADIFFAREA 0.00194719 ;
		ANTENNAPARTIALMETALAREA 0.00195671 ;
	END TWEN[8]

	PIN TWEN[9]
		USE SIGNAL ;
		DIRECTION INPUT ;
		SHAPE ABUTMENT ;
		PORT
			 LAYER M2 ;
			RECT 0.0714 12.9506 0.1097 12.9882 ;
			 LAYER M3 ;
			RECT 0.0714 12.8878 0.1097 12.9882 ;
			 LAYER V2 ;
			RECT 0.0831 12.9635 0.098 12.9761 ;
		END

		ANTENNAGATEAREA 0.00027817 ;
		ANTENNADIFFAREA 0.00194719 ;
		ANTENNAPARTIALMETALAREA 0.00195671 ;
	END TWEN[9]

	PIN VDDCE
		USE POWER ;
		DIRECTION INOUT ;
		PORT
			 LAYER M4 ;
			RECT 0.2105 89.229 62.601 89.2761 ;
		END

		PORT
			 LAYER M4 ;
			RECT 0.2105 68.749 62.601 68.7961 ;
		END

		PORT
			 LAYER M4 ;
			RECT 0.2105 68.109 62.601 68.1561 ;
		END

		PORT
			 LAYER M4 ;
			RECT 0.2105 67.469 62.601 67.5161 ;
		END

		PORT
			 LAYER M4 ;
			RECT 0.2105 87.949 62.601 87.9961 ;
		END

		PORT
			 LAYER M4 ;
			RECT 0.2105 66.829 62.601 66.8761 ;
		END

		PORT
			 LAYER M4 ;
			RECT 0.2105 66.189 62.601 66.2361 ;
		END

		PORT
			 LAYER M4 ;
			RECT 0.2105 65.549 62.601 65.5961 ;
		END

		PORT
			 LAYER M4 ;
			RECT 0.2105 64.909 62.601 64.9561 ;
		END

		PORT
			 LAYER M4 ;
			RECT 0.2105 64.269 62.601 64.3161 ;
		END

		PORT
			 LAYER M4 ;
			RECT 0.2105 63.629 62.601 63.6761 ;
		END

		PORT
			 LAYER M4 ;
			RECT 0.2105 62.989 62.601 63.0361 ;
		END

		PORT
			 LAYER M4 ;
			RECT 0.2105 62.349 62.601 62.3961 ;
		END

		PORT
			 LAYER M4 ;
			RECT 0.2105 61.709 62.601 61.7561 ;
		END

		PORT
			 LAYER M4 ;
			RECT 0.2105 61.069 62.601 61.1161 ;
		END

		PORT
			 LAYER M4 ;
			RECT 0.2105 87.309 62.601 87.3561 ;
		END

		PORT
			 LAYER M4 ;
			RECT 0.2105 60.429 62.601 60.4761 ;
		END

		PORT
			 LAYER M4 ;
			RECT 0.2105 59.789 62.601 59.8361 ;
		END

		PORT
			 LAYER M4 ;
			RECT 0.2105 59.149 62.601 59.1961 ;
		END

		PORT
			 LAYER M4 ;
			RECT 0.2105 58.509 62.601 58.5561 ;
		END

		PORT
			 LAYER M4 ;
			RECT 0.2105 57.869 62.601 57.9161 ;
		END

		PORT
			 LAYER M4 ;
			RECT 0.2105 57.229 62.601 57.2761 ;
		END

		PORT
			 LAYER M4 ;
			RECT 0.2105 56.589 62.601 56.6361 ;
		END

		PORT
			 LAYER M4 ;
			RECT 0.2105 55.949 62.601 55.9961 ;
		END

		PORT
			 LAYER M4 ;
			RECT 0.2105 55.309 62.601 55.3561 ;
		END

		PORT
			 LAYER M4 ;
			RECT 0.2105 54.669 62.601 54.7161 ;
		END

		PORT
			 LAYER M4 ;
			RECT 0.2105 86.669 62.601 86.7161 ;
		END

		PORT
			 LAYER M4 ;
			RECT 0.2105 54.029 62.601 54.0761 ;
		END

		PORT
			 LAYER M4 ;
			RECT 0.2105 53.389 62.601 53.4361 ;
		END

		PORT
			 LAYER M4 ;
			RECT 0.2105 52.749 62.601 52.7961 ;
		END

		PORT
			 LAYER M4 ;
			RECT 0.2105 52.109 62.601 52.1561 ;
		END

		PORT
			 LAYER M4 ;
			RECT 0.2105 51.469 62.601 51.5161 ;
		END

		PORT
			 LAYER M4 ;
			RECT 0.2105 50.829 62.601 50.8761 ;
		END

		PORT
			 LAYER M4 ;
			RECT 0.2105 50.189 62.601 50.2361 ;
		END

		PORT
			 LAYER M4 ;
			RECT 0.2105 49.549 62.601 49.5961 ;
		END

		PORT
			 LAYER M4 ;
			RECT 0.2105 48.909 62.601 48.9561 ;
		END

		PORT
			 LAYER M4 ;
			RECT 0.2105 86.029 62.601 86.0761 ;
		END

		PORT
			 LAYER M4 ;
			RECT 0.2105 85.389 62.601 85.4361 ;
		END

		PORT
			 LAYER M4 ;
			RECT 0.2105 41.1145 62.601 41.1616 ;
		END

		PORT
			 LAYER M4 ;
			RECT 0.2105 40.4745 62.601 40.5216 ;
		END

		PORT
			 LAYER M4 ;
			RECT 0.2105 39.8345 62.601 39.8816 ;
		END

		PORT
			 LAYER M4 ;
			RECT 0.2105 39.1945 62.601 39.2416 ;
		END

		PORT
			 LAYER M4 ;
			RECT 0.2105 38.5545 62.601 38.6016 ;
		END

		PORT
			 LAYER M4 ;
			RECT 0.2105 37.9145 62.601 37.9616 ;
		END

		PORT
			 LAYER M4 ;
			RECT 0.2105 37.2745 62.601 37.3216 ;
		END

		PORT
			 LAYER M4 ;
			RECT 0.2105 36.6345 62.601 36.6816 ;
		END

		PORT
			 LAYER M4 ;
			RECT 0.2105 35.9945 62.601 36.0416 ;
		END

		PORT
			 LAYER M4 ;
			RECT 0.2105 35.3545 62.601 35.4016 ;
		END

		PORT
			 LAYER M4 ;
			RECT 0.2105 84.749 62.601 84.7961 ;
		END

		PORT
			 LAYER M4 ;
			RECT 0.2105 34.7145 62.601 34.7616 ;
		END

		PORT
			 LAYER M4 ;
			RECT 0.2105 34.0745 62.601 34.1216 ;
		END

		PORT
			 LAYER M4 ;
			RECT 0.2105 33.4345 62.601 33.4816 ;
		END

		PORT
			 LAYER M4 ;
			RECT 0.2105 32.7945 62.601 32.8416 ;
		END

		PORT
			 LAYER M4 ;
			RECT 0.2105 32.1545 62.601 32.2016 ;
		END

		PORT
			 LAYER M4 ;
			RECT 0.2105 31.5145 62.601 31.5616 ;
		END

		PORT
			 LAYER M4 ;
			RECT 0.2105 30.8745 62.601 30.9216 ;
		END

		PORT
			 LAYER M4 ;
			RECT 0.2105 30.2345 62.601 30.2816 ;
		END

		PORT
			 LAYER M4 ;
			RECT 0.2105 29.5945 62.601 29.6416 ;
		END

		PORT
			 LAYER M4 ;
			RECT 0.2105 28.9545 62.601 29.0016 ;
		END

		PORT
			 LAYER M4 ;
			RECT 0.2105 84.109 62.601 84.1561 ;
		END

		PORT
			 LAYER M4 ;
			RECT 0.2105 28.3145 62.601 28.3616 ;
		END

		PORT
			 LAYER M4 ;
			RECT 0.2105 27.6745 62.601 27.7216 ;
		END

		PORT
			 LAYER M4 ;
			RECT 0.2105 27.0345 62.601 27.0816 ;
		END

		PORT
			 LAYER M4 ;
			RECT 0.2105 26.3945 62.601 26.4416 ;
		END

		PORT
			 LAYER M4 ;
			RECT 0.2105 25.7545 62.601 25.8016 ;
		END

		PORT
			 LAYER M4 ;
			RECT 0.2105 25.1145 62.601 25.1616 ;
		END

		PORT
			 LAYER M4 ;
			RECT 0.2105 24.4745 62.601 24.5216 ;
		END

		PORT
			 LAYER M4 ;
			RECT 0.2105 23.8345 62.601 23.8816 ;
		END

		PORT
			 LAYER M4 ;
			RECT 0.2105 23.1945 62.601 23.2416 ;
		END

		PORT
			 LAYER M4 ;
			RECT 0.2105 22.5545 62.601 22.6016 ;
		END

		PORT
			 LAYER M4 ;
			RECT 0.2105 83.469 62.601 83.5161 ;
		END

		PORT
			 LAYER M4 ;
			RECT 0.2105 21.9145 62.601 21.9616 ;
		END

		PORT
			 LAYER M4 ;
			RECT 0.2105 21.2745 62.601 21.3216 ;
		END

		PORT
			 LAYER M4 ;
			RECT 0.2105 20.6345 62.601 20.6816 ;
		END

		PORT
			 LAYER M4 ;
			RECT 0.2105 19.9945 62.601 20.0416 ;
		END

		PORT
			 LAYER M4 ;
			RECT 0.2105 19.3545 62.601 19.4016 ;
		END

		PORT
			 LAYER M4 ;
			RECT 0.2105 18.7145 62.601 18.7616 ;
		END

		PORT
			 LAYER M4 ;
			RECT 0.2105 18.0745 62.601 18.1216 ;
		END

		PORT
			 LAYER M4 ;
			RECT 0.2105 17.4345 62.601 17.4816 ;
		END

		PORT
			 LAYER M4 ;
			RECT 0.2105 16.7945 62.601 16.8416 ;
		END

		PORT
			 LAYER M4 ;
			RECT 0.2105 16.1545 62.601 16.2016 ;
		END

		PORT
			 LAYER M4 ;
			RECT 0.2105 82.829 62.601 82.8761 ;
		END

		PORT
			 LAYER M4 ;
			RECT 0.2105 15.5145 62.601 15.5616 ;
		END

		PORT
			 LAYER M4 ;
			RECT 0.2105 14.8745 62.601 14.9216 ;
		END

		PORT
			 LAYER M4 ;
			RECT 0.2105 14.2345 62.601 14.2816 ;
		END

		PORT
			 LAYER M4 ;
			RECT 0.2105 13.5945 62.601 13.6416 ;
		END

		PORT
			 LAYER M4 ;
			RECT 0.2105 12.9545 62.601 13.0016 ;
		END

		PORT
			 LAYER M4 ;
			RECT 0.2105 12.3145 62.601 12.3616 ;
		END

		PORT
			 LAYER M4 ;
			RECT 0.2105 11.6745 62.601 11.7216 ;
		END

		PORT
			 LAYER M4 ;
			RECT 0.2105 11.0345 62.601 11.0816 ;
		END

		PORT
			 LAYER M4 ;
			RECT 0.2105 10.3945 62.601 10.4416 ;
		END

		PORT
			 LAYER M4 ;
			RECT 0.2105 9.7545 62.601 9.8016 ;
		END

		PORT
			 LAYER M4 ;
			RECT 0.2105 82.189 62.601 82.2361 ;
		END

		PORT
			 LAYER M4 ;
			RECT 0.2105 9.1145 62.601 9.1616 ;
		END

		PORT
			 LAYER M4 ;
			RECT 0.2105 8.4745 62.601 8.5216 ;
		END

		PORT
			 LAYER M4 ;
			RECT 0.2105 7.8345 62.601 7.8816 ;
		END

		PORT
			 LAYER M4 ;
			RECT 0.2105 7.1945 62.601 7.2416 ;
		END

		PORT
			 LAYER M4 ;
			RECT 0.2105 6.5545 62.601 6.6016 ;
		END

		PORT
			 LAYER M4 ;
			RECT 0.2105 5.9145 62.601 5.9616 ;
		END

		PORT
			 LAYER M4 ;
			RECT 0.2105 5.2745 62.601 5.3216 ;
		END

		PORT
			 LAYER M4 ;
			RECT 0.2105 4.6345 62.601 4.6816 ;
		END

		PORT
			 LAYER M4 ;
			RECT 0.2105 3.9945 62.601 4.0416 ;
		END

		PORT
			 LAYER M4 ;
			RECT 0.2105 3.3545 62.601 3.4016 ;
		END

		PORT
			 LAYER M4 ;
			RECT 0.2105 81.549 62.601 81.5961 ;
		END

		PORT
			 LAYER M4 ;
			RECT 0.2105 2.7145 62.601 2.7616 ;
		END

		PORT
			 LAYER M4 ;
			RECT 0.2105 2.0745 62.601 2.1216 ;
		END

		PORT
			 LAYER M4 ;
			RECT 0.2105 1.4345 62.601 1.4816 ;
		END

		PORT
			 LAYER M4 ;
			RECT 0.2105 0.7945 62.601 0.8416 ;
		END

		PORT
			 LAYER M4 ;
			RECT 0.2105 80.909 62.601 80.9561 ;
		END

		PORT
			 LAYER M4 ;
			RECT 0.2105 80.269 62.601 80.3161 ;
		END

		PORT
			 LAYER M4 ;
			RECT 0.2105 79.629 62.601 79.6761 ;
		END

		PORT
			 LAYER M4 ;
			RECT 0.2105 78.989 62.601 79.0361 ;
		END

		PORT
			 LAYER M4 ;
			RECT 0.2105 78.349 62.601 78.3961 ;
		END

		PORT
			 LAYER M4 ;
			RECT 0.2105 77.709 62.601 77.7561 ;
		END

		PORT
			 LAYER M4 ;
			RECT 0.2105 77.069 62.601 77.1161 ;
		END

		PORT
			 LAYER M4 ;
			RECT 0.2105 76.429 62.601 76.4761 ;
		END

		PORT
			 LAYER M4 ;
			RECT 0.2105 75.789 62.601 75.8361 ;
		END

		PORT
			 LAYER M4 ;
			RECT 0.2105 75.149 62.601 75.1961 ;
		END

		PORT
			 LAYER M4 ;
			RECT 0.2105 74.509 62.601 74.5561 ;
		END

		PORT
			 LAYER M4 ;
			RECT 0.2105 73.869 62.601 73.9161 ;
		END

		PORT
			 LAYER M4 ;
			RECT 0.2105 88.589 62.601 88.6361 ;
		END

		PORT
			 LAYER M4 ;
			RECT 0.2105 73.229 62.601 73.2761 ;
		END

		PORT
			 LAYER M4 ;
			RECT 0.2105 72.589 62.601 72.6361 ;
		END

		PORT
			 LAYER M4 ;
			RECT 0.2105 71.949 62.601 71.9961 ;
		END

		PORT
			 LAYER M4 ;
			RECT 0.2105 71.309 62.601 71.3561 ;
		END

		PORT
			 LAYER M4 ;
			RECT 0.2105 70.669 62.601 70.7161 ;
		END

		PORT
			 LAYER M4 ;
			RECT 0.2105 70.029 62.601 70.0761 ;
		END

		PORT
			 LAYER M4 ;
			RECT 0.2105 69.389 62.601 69.4361 ;
		END

		PORT
			 LAYER M4 ;
			RECT 0.2105 89.9859 62.601 90.0173 ;
		END

		PORT
			 LAYER M4 ;
			RECT 0.2105 0.0533 62.601 0.0847 ;
		END

		PORT
			 LAYER M4 ;
			RECT 0.2105 41.8275 62.601 41.8745 ;
		END

		PORT
			 LAYER M4 ;
			RECT 0.2105 42.1192 62.601 42.1663 ;
		END

		PORT
			 LAYER M4 ;
			RECT 0.2105 48.0737 62.601 48.1208 ;
		END

		PORT
			 LAYER M4 ;
			RECT 0.2105 48.3655 62.601 48.4125 ;
		END

		PORT
			 LAYER M4 ;
			RECT 0.2105 41.2643 62.601 41.2957 ;
		END

		PORT
			 LAYER M4 ;
			RECT 0.2105 48.7784 62.601 48.8098 ;
		END

		PORT
			 LAYER M4 ;
			RECT 0.2105 89.8604 62.601 89.8918 ;
		END

		PORT
			 LAYER M4 ;
			RECT 0.2105 0.1788 62.601 0.2102 ;
		END

	END VDDCE

	PIN VDDPE
		USE POWER ;
		DIRECTION INOUT ;
		PORT
			 LAYER M4 ;
			RECT 0.2105 89.462 62.601 89.509 ;
		END

		PORT
			 LAYER M4 ;
			RECT 0.2105 88.182 62.601 88.229 ;
		END

		PORT
			 LAYER M4 ;
			RECT 0.2105 68.982 62.601 69.029 ;
		END

		PORT
			 LAYER M4 ;
			RECT 0.2105 68.342 62.601 68.389 ;
		END

		PORT
			 LAYER M4 ;
			RECT 0.2105 67.702 62.601 67.749 ;
		END

		PORT
			 LAYER M4 ;
			RECT 0.2105 67.062 62.601 67.109 ;
		END

		PORT
			 LAYER M4 ;
			RECT 0.2105 66.422 62.601 66.469 ;
		END

		PORT
			 LAYER M4 ;
			RECT 0.2105 65.782 62.601 65.829 ;
		END

		PORT
			 LAYER M4 ;
			RECT 0.2105 65.142 62.601 65.189 ;
		END

		PORT
			 LAYER M4 ;
			RECT 0.2105 64.502 62.601 64.549 ;
		END

		PORT
			 LAYER M4 ;
			RECT 0.2105 63.862 62.601 63.909 ;
		END

		PORT
			 LAYER M4 ;
			RECT 0.2105 63.222 62.601 63.269 ;
		END

		PORT
			 LAYER M4 ;
			RECT 0.2105 87.542 62.601 87.589 ;
		END

		PORT
			 LAYER M4 ;
			RECT 0.2105 62.582 62.601 62.629 ;
		END

		PORT
			 LAYER M4 ;
			RECT 0.2105 61.942 62.601 61.989 ;
		END

		PORT
			 LAYER M4 ;
			RECT 0.2105 61.302 62.601 61.349 ;
		END

		PORT
			 LAYER M4 ;
			RECT 0.2105 60.662 62.601 60.709 ;
		END

		PORT
			 LAYER M4 ;
			RECT 0.2105 60.022 62.601 60.069 ;
		END

		PORT
			 LAYER M4 ;
			RECT 0.2105 59.382 62.601 59.429 ;
		END

		PORT
			 LAYER M4 ;
			RECT 0.2105 58.742 62.601 58.789 ;
		END

		PORT
			 LAYER M4 ;
			RECT 0.2105 58.102 62.601 58.149 ;
		END

		PORT
			 LAYER M4 ;
			RECT 0.2105 57.462 62.601 57.509 ;
		END

		PORT
			 LAYER M4 ;
			RECT 0.2105 56.822 62.601 56.869 ;
		END

		PORT
			 LAYER M4 ;
			RECT 0.2105 86.902 62.601 86.949 ;
		END

		PORT
			 LAYER M4 ;
			RECT 0.2105 56.182 62.601 56.229 ;
		END

		PORT
			 LAYER M4 ;
			RECT 0.2105 55.542 62.601 55.589 ;
		END

		PORT
			 LAYER M4 ;
			RECT 0.2105 54.902 62.601 54.949 ;
		END

		PORT
			 LAYER M4 ;
			RECT 0.2105 54.262 62.601 54.309 ;
		END

		PORT
			 LAYER M4 ;
			RECT 0.2105 53.622 62.601 53.669 ;
		END

		PORT
			 LAYER M4 ;
			RECT 0.2105 52.982 62.601 53.029 ;
		END

		PORT
			 LAYER M4 ;
			RECT 0.2105 52.342 62.601 52.389 ;
		END

		PORT
			 LAYER M4 ;
			RECT 0.2105 51.702 62.601 51.749 ;
		END

		PORT
			 LAYER M4 ;
			RECT 0.2105 51.062 62.601 51.109 ;
		END

		PORT
			 LAYER M4 ;
			RECT 0.2105 50.422 62.601 50.469 ;
		END

		PORT
			 LAYER M4 ;
			RECT 0.2105 86.262 62.601 86.309 ;
		END

		PORT
			 LAYER M4 ;
			RECT 0.2105 49.782 62.601 49.829 ;
		END

		PORT
			 LAYER M4 ;
			RECT 0.2105 49.142 62.601 49.189 ;
		END

		PORT
			 LAYER M4 ;
			RECT 0.2105 85.622 62.601 85.669 ;
		END

		PORT
			 LAYER M4 ;
			RECT 0.2105 40.8816 62.601 40.9286 ;
		END

		PORT
			 LAYER M4 ;
			RECT 0.2105 40.2416 62.601 40.2886 ;
		END

		PORT
			 LAYER M4 ;
			RECT 0.2105 39.6016 62.601 39.6486 ;
		END

		PORT
			 LAYER M4 ;
			RECT 0.2105 38.9616 62.601 39.0086 ;
		END

		PORT
			 LAYER M4 ;
			RECT 0.2105 38.3216 62.601 38.3686 ;
		END

		PORT
			 LAYER M4 ;
			RECT 0.2105 37.6816 62.601 37.7286 ;
		END

		PORT
			 LAYER M4 ;
			RECT 0.2105 37.0416 62.601 37.0886 ;
		END

		PORT
			 LAYER M4 ;
			RECT 0.2105 84.982 62.601 85.029 ;
		END

		PORT
			 LAYER M4 ;
			RECT 0.2105 36.4016 62.601 36.4486 ;
		END

		PORT
			 LAYER M4 ;
			RECT 0.2105 35.7616 62.601 35.8086 ;
		END

		PORT
			 LAYER M4 ;
			RECT 0.2105 35.1216 62.601 35.1686 ;
		END

		PORT
			 LAYER M4 ;
			RECT 0.2105 34.4816 62.601 34.5286 ;
		END

		PORT
			 LAYER M4 ;
			RECT 0.2105 33.8416 62.601 33.8886 ;
		END

		PORT
			 LAYER M4 ;
			RECT 0.2105 33.2016 62.601 33.2486 ;
		END

		PORT
			 LAYER M4 ;
			RECT 0.2105 32.5616 62.601 32.6086 ;
		END

		PORT
			 LAYER M4 ;
			RECT 0.2105 31.9216 62.601 31.9686 ;
		END

		PORT
			 LAYER M4 ;
			RECT 0.2105 31.2816 62.601 31.3286 ;
		END

		PORT
			 LAYER M4 ;
			RECT 0.2105 30.6416 62.601 30.6886 ;
		END

		PORT
			 LAYER M4 ;
			RECT 0.2105 84.342 62.601 84.389 ;
		END

		PORT
			 LAYER M4 ;
			RECT 0.2105 30.0016 62.601 30.0486 ;
		END

		PORT
			 LAYER M4 ;
			RECT 0.2105 29.3616 62.601 29.4086 ;
		END

		PORT
			 LAYER M4 ;
			RECT 0.2105 28.7216 62.601 28.7686 ;
		END

		PORT
			 LAYER M4 ;
			RECT 0.2105 28.0816 62.601 28.1286 ;
		END

		PORT
			 LAYER M4 ;
			RECT 0.2105 27.4416 62.601 27.4886 ;
		END

		PORT
			 LAYER M4 ;
			RECT 0.2105 26.8016 62.601 26.8486 ;
		END

		PORT
			 LAYER M4 ;
			RECT 0.2105 26.1616 62.601 26.2086 ;
		END

		PORT
			 LAYER M4 ;
			RECT 0.2105 25.5216 62.601 25.5686 ;
		END

		PORT
			 LAYER M4 ;
			RECT 0.2105 24.8816 62.601 24.9286 ;
		END

		PORT
			 LAYER M4 ;
			RECT 0.2105 24.2416 62.601 24.2886 ;
		END

		PORT
			 LAYER M4 ;
			RECT 0.2105 83.702 62.601 83.749 ;
		END

		PORT
			 LAYER M4 ;
			RECT 0.2105 23.6016 62.601 23.6486 ;
		END

		PORT
			 LAYER M4 ;
			RECT 0.2105 22.9616 62.601 23.0086 ;
		END

		PORT
			 LAYER M4 ;
			RECT 0.2105 22.3216 62.601 22.3686 ;
		END

		PORT
			 LAYER M4 ;
			RECT 0.2105 21.6816 62.601 21.7286 ;
		END

		PORT
			 LAYER M4 ;
			RECT 0.2105 21.0416 62.601 21.0886 ;
		END

		PORT
			 LAYER M4 ;
			RECT 0.2105 20.4016 62.601 20.4486 ;
		END

		PORT
			 LAYER M4 ;
			RECT 0.2105 19.7616 62.601 19.8086 ;
		END

		PORT
			 LAYER M4 ;
			RECT 0.2105 19.1216 62.601 19.1686 ;
		END

		PORT
			 LAYER M4 ;
			RECT 0.2105 18.4816 62.601 18.5286 ;
		END

		PORT
			 LAYER M4 ;
			RECT 0.2105 17.8416 62.601 17.8886 ;
		END

		PORT
			 LAYER M4 ;
			RECT 0.2105 83.062 62.601 83.109 ;
		END

		PORT
			 LAYER M4 ;
			RECT 0.2105 17.2016 62.601 17.2486 ;
		END

		PORT
			 LAYER M4 ;
			RECT 0.2105 16.5616 62.601 16.6086 ;
		END

		PORT
			 LAYER M4 ;
			RECT 0.2105 15.9216 62.601 15.9686 ;
		END

		PORT
			 LAYER M4 ;
			RECT 0.2105 15.2816 62.601 15.3286 ;
		END

		PORT
			 LAYER M4 ;
			RECT 0.2105 14.6416 62.601 14.6886 ;
		END

		PORT
			 LAYER M4 ;
			RECT 0.2105 14.0016 62.601 14.0486 ;
		END

		PORT
			 LAYER M4 ;
			RECT 0.2105 13.3616 62.601 13.4086 ;
		END

		PORT
			 LAYER M4 ;
			RECT 0.2105 12.7216 62.601 12.7686 ;
		END

		PORT
			 LAYER M4 ;
			RECT 0.2105 12.0816 62.601 12.1286 ;
		END

		PORT
			 LAYER M4 ;
			RECT 0.2105 11.4416 62.601 11.4886 ;
		END

		PORT
			 LAYER M4 ;
			RECT 0.2105 82.422 62.601 82.469 ;
		END

		PORT
			 LAYER M4 ;
			RECT 0.2105 10.8016 62.601 10.8486 ;
		END

		PORT
			 LAYER M4 ;
			RECT 0.2105 10.1616 62.601 10.2086 ;
		END

		PORT
			 LAYER M4 ;
			RECT 0.2105 9.5216 62.601 9.5686 ;
		END

		PORT
			 LAYER M4 ;
			RECT 0.2105 8.8816 62.601 8.9286 ;
		END

		PORT
			 LAYER M4 ;
			RECT 0.2105 8.2416 62.601 8.2886 ;
		END

		PORT
			 LAYER M4 ;
			RECT 0.2105 7.6016 62.601 7.6486 ;
		END

		PORT
			 LAYER M4 ;
			RECT 0.2105 6.9616 62.601 7.0086 ;
		END

		PORT
			 LAYER M4 ;
			RECT 0.2105 6.3216 62.601 6.3686 ;
		END

		PORT
			 LAYER M4 ;
			RECT 0.2105 5.6816 62.601 5.7286 ;
		END

		PORT
			 LAYER M4 ;
			RECT 0.2105 5.0416 62.601 5.0886 ;
		END

		PORT
			 LAYER M4 ;
			RECT 0.2105 81.782 62.601 81.829 ;
		END

		PORT
			 LAYER M4 ;
			RECT 0.2105 4.4016 62.601 4.4486 ;
		END

		PORT
			 LAYER M4 ;
			RECT 0.2105 3.7616 62.601 3.8086 ;
		END

		PORT
			 LAYER M4 ;
			RECT 0.2105 3.1216 62.601 3.1686 ;
		END

		PORT
			 LAYER M4 ;
			RECT 0.2105 2.4816 62.601 2.5286 ;
		END

		PORT
			 LAYER M4 ;
			RECT 0.2105 1.8416 62.601 1.8886 ;
		END

		PORT
			 LAYER M4 ;
			RECT 0.2105 1.2016 62.601 1.2486 ;
		END

		PORT
			 LAYER M4 ;
			RECT 0.2105 0.5616 62.601 0.6086 ;
		END

		PORT
			 LAYER M4 ;
			RECT 0.2105 81.142 62.601 81.189 ;
		END

		PORT
			 LAYER M4 ;
			RECT 0.2105 80.502 62.601 80.549 ;
		END

		PORT
			 LAYER M4 ;
			RECT 0.2105 79.862 62.601 79.909 ;
		END

		PORT
			 LAYER M4 ;
			RECT 0.2105 79.222 62.601 79.269 ;
		END

		PORT
			 LAYER M4 ;
			RECT 0.2105 78.582 62.601 78.629 ;
		END

		PORT
			 LAYER M4 ;
			RECT 0.2105 77.942 62.601 77.989 ;
		END

		PORT
			 LAYER M4 ;
			RECT 0.2105 77.302 62.601 77.349 ;
		END

		PORT
			 LAYER M4 ;
			RECT 0.2105 76.662 62.601 76.709 ;
		END

		PORT
			 LAYER M4 ;
			RECT 0.2105 76.022 62.601 76.069 ;
		END

		PORT
			 LAYER M4 ;
			RECT 0.2105 88.822 62.601 88.869 ;
		END

		PORT
			 LAYER M4 ;
			RECT 0.2105 75.382 62.601 75.429 ;
		END

		PORT
			 LAYER M4 ;
			RECT 0.2105 74.742 62.601 74.789 ;
		END

		PORT
			 LAYER M4 ;
			RECT 0.2105 74.102 62.601 74.149 ;
		END

		PORT
			 LAYER M4 ;
			RECT 0.2105 73.462 62.601 73.509 ;
		END

		PORT
			 LAYER M4 ;
			RECT 0.2105 72.822 62.601 72.869 ;
		END

		PORT
			 LAYER M4 ;
			RECT 0.2105 72.182 62.601 72.229 ;
		END

		PORT
			 LAYER M4 ;
			RECT 0.2105 71.542 62.601 71.589 ;
		END

		PORT
			 LAYER M4 ;
			RECT 0.2105 70.902 62.601 70.949 ;
		END

		PORT
			 LAYER M4 ;
			RECT 0.2105 70.262 62.601 70.309 ;
		END

		PORT
			 LAYER M4 ;
			RECT 0.2105 69.622 62.601 69.669 ;
		END

		PORT
			 LAYER M4 ;
			RECT 0.2105 41.4682 62.601 41.5153 ;
		END

		PORT
			 LAYER M4 ;
			RECT 0.2105 41.9059 62.601 41.9529 ;
		END

		PORT
			 LAYER M4 ;
			RECT 0.2105 42.1976 62.601 42.2447 ;
		END

		PORT
			 LAYER M4 ;
			RECT 0.2105 42.7247 62.601 42.7718 ;
		END

		PORT
			 LAYER M4 ;
			RECT 0.2105 43.2518 62.601 43.2988 ;
		END

		PORT
			 LAYER M4 ;
			RECT 0.2105 43.7788 62.601 43.8259 ;
		END

		PORT
			 LAYER M4 ;
			RECT 0.2105 44.3059 62.601 44.3529 ;
		END

		PORT
			 LAYER M4 ;
			RECT 0.2105 45.36 62.601 45.4071 ;
		END

		PORT
			 LAYER M4 ;
			RECT 0.2105 46.4141 62.601 46.4612 ;
		END

		PORT
			 LAYER M4 ;
			RECT 0.2105 46.9412 62.601 46.9882 ;
		END

		PORT
			 LAYER M4 ;
			RECT 0.2105 47.4682 62.601 47.5153 ;
		END

		PORT
			 LAYER M4 ;
			RECT 0.2105 47.9953 62.601 48.0424 ;
		END

		PORT
			 LAYER M4 ;
			RECT 0.2105 48.2871 62.601 48.3341 ;
		END

		PORT
			 LAYER M4 ;
			RECT 0.2105 41.3271 62.601 41.3584 ;
		END

		PORT
			 LAYER M4 ;
			RECT 0.2105 48.7157 62.601 48.7471 ;
		END

	END VDDPE

	PIN VSSE
		USE GROUND ;
		DIRECTION INOUT ;
		PORT
			 LAYER M4 ;
			RECT 0.2105 41.2016 62.601 41.2329 ;
		END

		PORT
			 LAYER M4 ;
			RECT 0.2105 48.8412 62.601 48.8725 ;
		END

		PORT
			 LAYER M4 ;
			RECT 0.2105 89.9231 62.601 89.9545 ;
		END

		PORT
			 LAYER M4 ;
			RECT 0.2105 0.1161 62.601 0.1475 ;
		END

		PORT
			 LAYER M4 ;
			RECT 0.2105 48.1522 62.601 48.1992 ;
		END

		PORT
			 LAYER M4 ;
			RECT 0.2105 41.3898 62.601 41.4369 ;
		END

		PORT
			 LAYER M4 ;
			RECT 0.2105 42.0408 62.601 42.0878 ;
		END

		PORT
			 LAYER M4 ;
			RECT 0.2105 42.6463 62.601 42.6933 ;
		END

		PORT
			 LAYER M4 ;
			RECT 0.2105 43.1733 62.601 43.2204 ;
		END

		PORT
			 LAYER M4 ;
			RECT 0.2105 43.7004 62.601 43.7475 ;
		END

		PORT
			 LAYER M4 ;
			RECT 0.2105 44.2275 62.601 44.2745 ;
		END

		PORT
			 LAYER M4 ;
			RECT 0.2105 45.2816 62.601 45.3286 ;
		END

		PORT
			 LAYER M4 ;
			RECT 0.2105 46.3357 62.601 46.3827 ;
		END

		PORT
			 LAYER M4 ;
			RECT 0.2105 46.8627 62.601 46.9098 ;
		END

		PORT
			 LAYER M4 ;
			RECT 0.2105 47.3898 62.601 47.4369 ;
		END

		PORT
			 LAYER M4 ;
			RECT 0.2105 47.9169 62.601 47.9639 ;
		END

		PORT
			 LAYER M4 ;
			RECT 0.2105 89.7733 62.601 89.8204 ;
		END

		PORT
			 LAYER M4 ;
			RECT 0.2105 68.6533 62.601 68.7004 ;
		END

		PORT
			 LAYER M4 ;
			RECT 0.2105 68.0133 62.601 68.0604 ;
		END

		PORT
			 LAYER M4 ;
			RECT 0.2105 67.3733 62.601 67.4204 ;
		END

		PORT
			 LAYER M4 ;
			RECT 0.2105 66.7333 62.601 66.7804 ;
		END

		PORT
			 LAYER M4 ;
			RECT 0.2105 66.0933 62.601 66.1404 ;
		END

		PORT
			 LAYER M4 ;
			RECT 0.2105 65.4533 62.601 65.5004 ;
		END

		PORT
			 LAYER M4 ;
			RECT 0.2105 87.8533 62.601 87.9004 ;
		END

		PORT
			 LAYER M4 ;
			RECT 0.2105 64.8133 62.601 64.8604 ;
		END

		PORT
			 LAYER M4 ;
			RECT 0.2105 64.1733 62.601 64.2204 ;
		END

		PORT
			 LAYER M4 ;
			RECT 0.2105 63.5333 62.601 63.5804 ;
		END

		PORT
			 LAYER M4 ;
			RECT 0.2105 62.8933 62.601 62.9404 ;
		END

		PORT
			 LAYER M4 ;
			RECT 0.2105 62.2533 62.601 62.3004 ;
		END

		PORT
			 LAYER M4 ;
			RECT 0.2105 61.6133 62.601 61.6604 ;
		END

		PORT
			 LAYER M4 ;
			RECT 0.2105 60.9733 62.601 61.0204 ;
		END

		PORT
			 LAYER M4 ;
			RECT 0.2105 60.3333 62.601 60.3804 ;
		END

		PORT
			 LAYER M4 ;
			RECT 0.2105 59.6933 62.601 59.7404 ;
		END

		PORT
			 LAYER M4 ;
			RECT 0.2105 59.0533 62.601 59.1004 ;
		END

		PORT
			 LAYER M4 ;
			RECT 0.2105 87.2133 62.601 87.2604 ;
		END

		PORT
			 LAYER M4 ;
			RECT 0.2105 58.4133 62.601 58.4604 ;
		END

		PORT
			 LAYER M4 ;
			RECT 0.2105 57.7733 62.601 57.8204 ;
		END

		PORT
			 LAYER M4 ;
			RECT 0.2105 57.1333 62.601 57.1804 ;
		END

		PORT
			 LAYER M4 ;
			RECT 0.2105 56.4933 62.601 56.5404 ;
		END

		PORT
			 LAYER M4 ;
			RECT 0.2105 55.8533 62.601 55.9004 ;
		END

		PORT
			 LAYER M4 ;
			RECT 0.2105 55.2133 62.601 55.2604 ;
		END

		PORT
			 LAYER M4 ;
			RECT 0.2105 54.5733 62.601 54.6204 ;
		END

		PORT
			 LAYER M4 ;
			RECT 0.2105 53.9333 62.601 53.9804 ;
		END

		PORT
			 LAYER M4 ;
			RECT 0.2105 53.2933 62.601 53.3404 ;
		END

		PORT
			 LAYER M4 ;
			RECT 0.2105 52.6533 62.601 52.7004 ;
		END

		PORT
			 LAYER M4 ;
			RECT 0.2105 86.5733 62.601 86.6204 ;
		END

		PORT
			 LAYER M4 ;
			RECT 0.2105 52.0133 62.601 52.0604 ;
		END

		PORT
			 LAYER M4 ;
			RECT 0.2105 51.3733 62.601 51.4204 ;
		END

		PORT
			 LAYER M4 ;
			RECT 0.2105 50.7333 62.601 50.7804 ;
		END

		PORT
			 LAYER M4 ;
			RECT 0.2105 50.0933 62.601 50.1404 ;
		END

		PORT
			 LAYER M4 ;
			RECT 0.2105 49.4533 62.601 49.5004 ;
		END

		PORT
			 LAYER M4 ;
			RECT 0.2105 85.9333 62.601 85.9804 ;
		END

		PORT
			 LAYER M4 ;
			RECT 0.2105 40.5702 62.601 40.6173 ;
		END

		PORT
			 LAYER M4 ;
			RECT 0.2105 39.9302 62.601 39.9773 ;
		END

		PORT
			 LAYER M4 ;
			RECT 0.2105 39.2902 62.601 39.3373 ;
		END

		PORT
			 LAYER M4 ;
			RECT 0.2105 85.2933 62.601 85.3404 ;
		END

		PORT
			 LAYER M4 ;
			RECT 0.2105 38.6502 62.601 38.6973 ;
		END

		PORT
			 LAYER M4 ;
			RECT 0.2105 38.0102 62.601 38.0573 ;
		END

		PORT
			 LAYER M4 ;
			RECT 0.2105 37.3702 62.601 37.4173 ;
		END

		PORT
			 LAYER M4 ;
			RECT 0.2105 36.7302 62.601 36.7773 ;
		END

		PORT
			 LAYER M4 ;
			RECT 0.2105 36.0902 62.601 36.1373 ;
		END

		PORT
			 LAYER M4 ;
			RECT 0.2105 35.4502 62.601 35.4973 ;
		END

		PORT
			 LAYER M4 ;
			RECT 0.2105 34.8102 62.601 34.8573 ;
		END

		PORT
			 LAYER M4 ;
			RECT 0.2105 34.1702 62.601 34.2173 ;
		END

		PORT
			 LAYER M4 ;
			RECT 0.2105 33.5302 62.601 33.5773 ;
		END

		PORT
			 LAYER M4 ;
			RECT 0.2105 32.8902 62.601 32.9373 ;
		END

		PORT
			 LAYER M4 ;
			RECT 0.2105 84.6533 62.601 84.7004 ;
		END

		PORT
			 LAYER M4 ;
			RECT 0.2105 32.2502 62.601 32.2973 ;
		END

		PORT
			 LAYER M4 ;
			RECT 0.2105 31.6102 62.601 31.6573 ;
		END

		PORT
			 LAYER M4 ;
			RECT 0.2105 30.9702 62.601 31.0173 ;
		END

		PORT
			 LAYER M4 ;
			RECT 0.2105 30.3302 62.601 30.3773 ;
		END

		PORT
			 LAYER M4 ;
			RECT 0.2105 29.6902 62.601 29.7373 ;
		END

		PORT
			 LAYER M4 ;
			RECT 0.2105 29.0502 62.601 29.0973 ;
		END

		PORT
			 LAYER M4 ;
			RECT 0.2105 28.4102 62.601 28.4573 ;
		END

		PORT
			 LAYER M4 ;
			RECT 0.2105 27.7702 62.601 27.8173 ;
		END

		PORT
			 LAYER M4 ;
			RECT 0.2105 27.1302 62.601 27.1773 ;
		END

		PORT
			 LAYER M4 ;
			RECT 0.2105 26.4902 62.601 26.5373 ;
		END

		PORT
			 LAYER M4 ;
			RECT 0.2105 84.0133 62.601 84.0604 ;
		END

		PORT
			 LAYER M4 ;
			RECT 0.2105 25.8502 62.601 25.8973 ;
		END

		PORT
			 LAYER M4 ;
			RECT 0.2105 25.2102 62.601 25.2573 ;
		END

		PORT
			 LAYER M4 ;
			RECT 0.2105 24.5702 62.601 24.6173 ;
		END

		PORT
			 LAYER M4 ;
			RECT 0.2105 23.9302 62.601 23.9773 ;
		END

		PORT
			 LAYER M4 ;
			RECT 0.2105 23.2902 62.601 23.3373 ;
		END

		PORT
			 LAYER M4 ;
			RECT 0.2105 22.6502 62.601 22.6973 ;
		END

		PORT
			 LAYER M4 ;
			RECT 0.2105 22.0102 62.601 22.0573 ;
		END

		PORT
			 LAYER M4 ;
			RECT 0.2105 21.3702 62.601 21.4173 ;
		END

		PORT
			 LAYER M4 ;
			RECT 0.2105 20.7302 62.601 20.7773 ;
		END

		PORT
			 LAYER M4 ;
			RECT 0.2105 20.0902 62.601 20.1373 ;
		END

		PORT
			 LAYER M4 ;
			RECT 0.2105 83.3733 62.601 83.4204 ;
		END

		PORT
			 LAYER M4 ;
			RECT 0.2105 19.4502 62.601 19.4973 ;
		END

		PORT
			 LAYER M4 ;
			RECT 0.2105 18.8102 62.601 18.8573 ;
		END

		PORT
			 LAYER M4 ;
			RECT 0.2105 18.1702 62.601 18.2173 ;
		END

		PORT
			 LAYER M4 ;
			RECT 0.2105 17.5302 62.601 17.5773 ;
		END

		PORT
			 LAYER M4 ;
			RECT 0.2105 16.8902 62.601 16.9373 ;
		END

		PORT
			 LAYER M4 ;
			RECT 0.2105 16.2502 62.601 16.2973 ;
		END

		PORT
			 LAYER M4 ;
			RECT 0.2105 15.6102 62.601 15.6573 ;
		END

		PORT
			 LAYER M4 ;
			RECT 0.2105 14.9702 62.601 15.0173 ;
		END

		PORT
			 LAYER M4 ;
			RECT 0.2105 14.3302 62.601 14.3773 ;
		END

		PORT
			 LAYER M4 ;
			RECT 0.2105 13.6902 62.601 13.7373 ;
		END

		PORT
			 LAYER M4 ;
			RECT 0.2105 82.7333 62.601 82.7804 ;
		END

		PORT
			 LAYER M4 ;
			RECT 0.2105 13.0502 62.601 13.0973 ;
		END

		PORT
			 LAYER M4 ;
			RECT 0.2105 12.4102 62.601 12.4573 ;
		END

		PORT
			 LAYER M4 ;
			RECT 0.2105 11.7702 62.601 11.8173 ;
		END

		PORT
			 LAYER M4 ;
			RECT 0.2105 11.1302 62.601 11.1773 ;
		END

		PORT
			 LAYER M4 ;
			RECT 0.2105 10.4902 62.601 10.5373 ;
		END

		PORT
			 LAYER M4 ;
			RECT 0.2105 9.8502 62.601 9.8973 ;
		END

		PORT
			 LAYER M4 ;
			RECT 0.2105 9.2102 62.601 9.2573 ;
		END

		PORT
			 LAYER M4 ;
			RECT 0.2105 8.5702 62.601 8.6173 ;
		END

		PORT
			 LAYER M4 ;
			RECT 0.2105 7.9302 62.601 7.9773 ;
		END

		PORT
			 LAYER M4 ;
			RECT 0.2105 7.2902 62.601 7.3373 ;
		END

		PORT
			 LAYER M4 ;
			RECT 0.2105 82.0933 62.601 82.1404 ;
		END

		PORT
			 LAYER M4 ;
			RECT 0.2105 6.6502 62.601 6.6973 ;
		END

		PORT
			 LAYER M4 ;
			RECT 0.2105 6.0102 62.601 6.0573 ;
		END

		PORT
			 LAYER M4 ;
			RECT 0.2105 5.3702 62.601 5.4173 ;
		END

		PORT
			 LAYER M4 ;
			RECT 0.2105 4.7302 62.601 4.7773 ;
		END

		PORT
			 LAYER M4 ;
			RECT 0.2105 4.0902 62.601 4.1373 ;
		END

		PORT
			 LAYER M4 ;
			RECT 0.2105 3.4502 62.601 3.4973 ;
		END

		PORT
			 LAYER M4 ;
			RECT 0.2105 2.8102 62.601 2.8573 ;
		END

		PORT
			 LAYER M4 ;
			RECT 0.2105 2.1702 62.601 2.2173 ;
		END

		PORT
			 LAYER M4 ;
			RECT 0.2105 1.5302 62.601 1.5773 ;
		END

		PORT
			 LAYER M4 ;
			RECT 0.2105 0.8902 62.601 0.9373 ;
		END

		PORT
			 LAYER M4 ;
			RECT 0.2105 81.4533 62.601 81.5004 ;
		END

		PORT
			 LAYER M4 ;
			RECT 0.2105 0.2502 62.601 0.2973 ;
		END

		PORT
			 LAYER M4 ;
			RECT 0.2105 80.8133 62.601 80.8604 ;
		END

		PORT
			 LAYER M4 ;
			RECT 0.2105 80.1733 62.601 80.2204 ;
		END

		PORT
			 LAYER M4 ;
			RECT 0.2105 79.5333 62.601 79.5804 ;
		END

		PORT
			 LAYER M4 ;
			RECT 0.2105 78.8933 62.601 78.9404 ;
		END

		PORT
			 LAYER M4 ;
			RECT 0.2105 78.2533 62.601 78.3004 ;
		END

		PORT
			 LAYER M4 ;
			RECT 0.2105 89.1333 62.601 89.1804 ;
		END

		PORT
			 LAYER M4 ;
			RECT 0.2105 77.6133 62.601 77.6604 ;
		END

		PORT
			 LAYER M4 ;
			RECT 0.2105 76.9733 62.601 77.0204 ;
		END

		PORT
			 LAYER M4 ;
			RECT 0.2105 76.3333 62.601 76.3804 ;
		END

		PORT
			 LAYER M4 ;
			RECT 0.2105 75.6933 62.601 75.7404 ;
		END

		PORT
			 LAYER M4 ;
			RECT 0.2105 75.0533 62.601 75.1004 ;
		END

		PORT
			 LAYER M4 ;
			RECT 0.2105 74.4133 62.601 74.4604 ;
		END

		PORT
			 LAYER M4 ;
			RECT 0.2105 73.7733 62.601 73.8204 ;
		END

		PORT
			 LAYER M4 ;
			RECT 0.2105 73.1333 62.601 73.1804 ;
		END

		PORT
			 LAYER M4 ;
			RECT 0.2105 72.4933 62.601 72.5404 ;
		END

		PORT
			 LAYER M4 ;
			RECT 0.2105 71.8533 62.601 71.9004 ;
		END

		PORT
			 LAYER M4 ;
			RECT 0.2105 88.4933 62.601 88.5404 ;
		END

		PORT
			 LAYER M4 ;
			RECT 0.2105 71.2133 62.601 71.2604 ;
		END

		PORT
			 LAYER M4 ;
			RECT 0.2105 70.5733 62.601 70.6204 ;
		END

		PORT
			 LAYER M4 ;
			RECT 0.2105 69.9333 62.601 69.9804 ;
		END

		PORT
			 LAYER M4 ;
			RECT 0.2105 69.2933 62.601 69.3404 ;
		END

	END VSSE

	PIN WABL
		USE SIGNAL ;
		DIRECTION INPUT ;
		SHAPE ABUTMENT ;
		PORT
			 LAYER M2 ;
			RECT 0.0098 48.64 0.0481 48.6776 ;
			 LAYER M3 ;
			RECT 0.0098 48.5773 0.0481 48.6776 ;
			 LAYER V2 ;
			RECT 0.0215 48.6522 0.0364 48.6647 ;
		END

		ANTENNAGATEAREA 0.00027817 ;
		ANTENNADIFFAREA 0.00194719 ;
		ANTENNAPARTIALMETALAREA 0.00195671 ;
	END WABL

	PIN WABLM[0]
		USE SIGNAL ;
		DIRECTION INPUT ;
		SHAPE ABUTMENT ;
		PORT
			 LAYER M2 ;
			RECT 0.0714 41.4996 0.1097 41.5373 ;
			 LAYER M3 ;
			RECT 0.0714 41.4996 0.1097 41.6 ;
			 LAYER V2 ;
			RECT 0.0831 41.5118 0.098 41.5243 ;
		END

		ANTENNAGATEAREA 0.00027817 ;
		ANTENNADIFFAREA 0.00194719 ;
		ANTENNAPARTIALMETALAREA 0.00195671 ;
	END WABLM[0]

	PIN WABLM[1]
		USE SIGNAL ;
		DIRECTION INPUT ;
		SHAPE ABUTMENT ;
		PORT
			 LAYER M3 ;
			RECT 0.0714 46.0173 0.1097 46.1176 ;
		END

		ANTENNAGATEAREA 0.00027817 ;
		ANTENNADIFFAREA 0.00194719 ;
		ANTENNAPARTIALMETALAREA 0.00195671 ;
	END WABLM[1]

	PIN WENY[0]
		USE SIGNAL ;
		DIRECTION OUTPUT ;
		SHAPE ABUTMENT ;
		PORT
			 LAYER M2 ;
			RECT 0.0098 1.2424 0.0481 1.3427 ;
			 LAYER M3 ;
			RECT 0.0098 1.2424 0.0481 1.3427 ;
			 LAYER V2 ;
			RECT 0.021 1.2553 0.0359 1.2678 ;
		END

		ANTENNADIFFAREA 0.00194719 ;
		ANTENNAPARTIALMETALAREA 0.00195671 ;
	END WENY[0]

	PIN WENY[10]
		USE SIGNAL ;
		DIRECTION OUTPUT ;
		SHAPE ABUTMENT ;
		PORT
			 LAYER M2 ;
			RECT 0.0098 14.0424 0.0481 14.1427 ;
			 LAYER M3 ;
			RECT 0.0098 14.0424 0.0481 14.1427 ;
			 LAYER V2 ;
			RECT 0.021 14.0553 0.0359 14.0678 ;
		END

		ANTENNADIFFAREA 0.00194719 ;
		ANTENNAPARTIALMETALAREA 0.00195671 ;
	END WENY[10]

	PIN WENY[11]
		USE SIGNAL ;
		DIRECTION OUTPUT ;
		SHAPE ABUTMENT ;
		PORT
			 LAYER M2 ;
			RECT 0.0098 15.3224 0.0481 15.4227 ;
			 LAYER M3 ;
			RECT 0.0098 15.3224 0.0481 15.4227 ;
			 LAYER V2 ;
			RECT 0.021 15.3353 0.0359 15.3478 ;
		END

		ANTENNADIFFAREA 0.00194719 ;
		ANTENNAPARTIALMETALAREA 0.00195671 ;
	END WENY[11]

	PIN WENY[12]
		USE SIGNAL ;
		DIRECTION OUTPUT ;
		SHAPE ABUTMENT ;
		PORT
			 LAYER M2 ;
			RECT 0.0098 16.6024 0.0481 16.7027 ;
			 LAYER M3 ;
			RECT 0.0098 16.6024 0.0481 16.7027 ;
			 LAYER V2 ;
			RECT 0.021 16.6153 0.0359 16.6278 ;
		END

		ANTENNADIFFAREA 0.00194719 ;
		ANTENNAPARTIALMETALAREA 0.00195671 ;
	END WENY[12]

	PIN WENY[13]
		USE SIGNAL ;
		DIRECTION OUTPUT ;
		SHAPE ABUTMENT ;
		PORT
			 LAYER M2 ;
			RECT 0.0098 17.8824 0.0481 17.9827 ;
			 LAYER M3 ;
			RECT 0.0098 17.8824 0.0481 17.9827 ;
			 LAYER V2 ;
			RECT 0.021 17.8953 0.0359 17.9078 ;
		END

		ANTENNADIFFAREA 0.00194719 ;
		ANTENNAPARTIALMETALAREA 0.00195671 ;
	END WENY[13]

	PIN WENY[14]
		USE SIGNAL ;
		DIRECTION OUTPUT ;
		SHAPE ABUTMENT ;
		PORT
			 LAYER M2 ;
			RECT 0.0098 19.1624 0.0481 19.2627 ;
			 LAYER M3 ;
			RECT 0.0098 19.1624 0.0481 19.2627 ;
			 LAYER V2 ;
			RECT 0.021 19.1753 0.0359 19.1878 ;
		END

		ANTENNADIFFAREA 0.00194719 ;
		ANTENNAPARTIALMETALAREA 0.00195671 ;
	END WENY[14]

	PIN WENY[15]
		USE SIGNAL ;
		DIRECTION OUTPUT ;
		SHAPE ABUTMENT ;
		PORT
			 LAYER M2 ;
			RECT 0.0098 20.4424 0.0481 20.5427 ;
			 LAYER M3 ;
			RECT 0.0098 20.4424 0.0481 20.5427 ;
			 LAYER V2 ;
			RECT 0.021 20.4553 0.0359 20.4678 ;
		END

		ANTENNADIFFAREA 0.00194719 ;
		ANTENNAPARTIALMETALAREA 0.00195671 ;
	END WENY[15]

	PIN WENY[16]
		USE SIGNAL ;
		DIRECTION OUTPUT ;
		SHAPE ABUTMENT ;
		PORT
			 LAYER M2 ;
			RECT 0.0098 21.7224 0.0481 21.8227 ;
			 LAYER M3 ;
			RECT 0.0098 21.7224 0.0481 21.8227 ;
			 LAYER V2 ;
			RECT 0.021 21.7353 0.0359 21.7478 ;
		END

		ANTENNADIFFAREA 0.00194719 ;
		ANTENNAPARTIALMETALAREA 0.00195671 ;
	END WENY[16]

	PIN WENY[17]
		USE SIGNAL ;
		DIRECTION OUTPUT ;
		SHAPE ABUTMENT ;
		PORT
			 LAYER M2 ;
			RECT 0.0098 23.0024 0.0481 23.1027 ;
			 LAYER M3 ;
			RECT 0.0098 23.0024 0.0481 23.1027 ;
			 LAYER V2 ;
			RECT 0.021 23.0153 0.0359 23.0278 ;
		END

		ANTENNADIFFAREA 0.00194719 ;
		ANTENNAPARTIALMETALAREA 0.00195671 ;
	END WENY[17]

	PIN WENY[18]
		USE SIGNAL ;
		DIRECTION OUTPUT ;
		SHAPE ABUTMENT ;
		PORT
			 LAYER M2 ;
			RECT 0.0098 24.2824 0.0481 24.3827 ;
			 LAYER M3 ;
			RECT 0.0098 24.2824 0.0481 24.3827 ;
			 LAYER V2 ;
			RECT 0.021 24.2953 0.0359 24.3078 ;
		END

		ANTENNADIFFAREA 0.00194719 ;
		ANTENNAPARTIALMETALAREA 0.00195671 ;
	END WENY[18]

	PIN WENY[19]
		USE SIGNAL ;
		DIRECTION OUTPUT ;
		SHAPE ABUTMENT ;
		PORT
			 LAYER M2 ;
			RECT 0.0098 25.5624 0.0481 25.6627 ;
			 LAYER M3 ;
			RECT 0.0098 25.5624 0.0481 25.6627 ;
			 LAYER V2 ;
			RECT 0.021 25.5753 0.0359 25.5878 ;
		END

		ANTENNADIFFAREA 0.00194719 ;
		ANTENNAPARTIALMETALAREA 0.00195671 ;
	END WENY[19]

	PIN WENY[1]
		USE SIGNAL ;
		DIRECTION OUTPUT ;
		SHAPE ABUTMENT ;
		PORT
			 LAYER M2 ;
			RECT 0.0098 2.5224 0.0481 2.6227 ;
			 LAYER M3 ;
			RECT 0.0098 2.5224 0.0481 2.6227 ;
			 LAYER V2 ;
			RECT 0.021 2.5353 0.0359 2.5478 ;
		END

		ANTENNADIFFAREA 0.00194719 ;
		ANTENNAPARTIALMETALAREA 0.00195671 ;
	END WENY[1]

	PIN WENY[20]
		USE SIGNAL ;
		DIRECTION OUTPUT ;
		SHAPE ABUTMENT ;
		PORT
			 LAYER M2 ;
			RECT 0.0098 26.8424 0.0481 26.9427 ;
			 LAYER M3 ;
			RECT 0.0098 26.8424 0.0481 26.9427 ;
			 LAYER V2 ;
			RECT 0.021 26.8553 0.0359 26.8678 ;
		END

		ANTENNADIFFAREA 0.00194719 ;
		ANTENNAPARTIALMETALAREA 0.00195671 ;
	END WENY[20]

	PIN WENY[21]
		USE SIGNAL ;
		DIRECTION OUTPUT ;
		SHAPE ABUTMENT ;
		PORT
			 LAYER M2 ;
			RECT 0.0098 28.1224 0.0481 28.2227 ;
			 LAYER M3 ;
			RECT 0.0098 28.1224 0.0481 28.2227 ;
			 LAYER V2 ;
			RECT 0.021 28.1353 0.0359 28.1478 ;
		END

		ANTENNADIFFAREA 0.00194719 ;
		ANTENNAPARTIALMETALAREA 0.00195671 ;
	END WENY[21]

	PIN WENY[22]
		USE SIGNAL ;
		DIRECTION OUTPUT ;
		SHAPE ABUTMENT ;
		PORT
			 LAYER M2 ;
			RECT 0.0098 29.4024 0.0481 29.5027 ;
			 LAYER M3 ;
			RECT 0.0098 29.4024 0.0481 29.5027 ;
			 LAYER V2 ;
			RECT 0.021 29.4153 0.0359 29.4278 ;
		END

		ANTENNADIFFAREA 0.00194719 ;
		ANTENNAPARTIALMETALAREA 0.00195671 ;
	END WENY[22]

	PIN WENY[23]
		USE SIGNAL ;
		DIRECTION OUTPUT ;
		SHAPE ABUTMENT ;
		PORT
			 LAYER M2 ;
			RECT 0.0098 30.6824 0.0481 30.7827 ;
			 LAYER M3 ;
			RECT 0.0098 30.6824 0.0481 30.7827 ;
			 LAYER V2 ;
			RECT 0.021 30.6953 0.0359 30.7078 ;
		END

		ANTENNADIFFAREA 0.00194719 ;
		ANTENNAPARTIALMETALAREA 0.00195671 ;
	END WENY[23]

	PIN WENY[24]
		USE SIGNAL ;
		DIRECTION OUTPUT ;
		SHAPE ABUTMENT ;
		PORT
			 LAYER M2 ;
			RECT 0.0098 31.9624 0.0481 32.0627 ;
			 LAYER M3 ;
			RECT 0.0098 31.9624 0.0481 32.0627 ;
			 LAYER V2 ;
			RECT 0.021 31.9753 0.0359 31.9878 ;
		END

		ANTENNADIFFAREA 0.00194719 ;
		ANTENNAPARTIALMETALAREA 0.00195671 ;
	END WENY[24]

	PIN WENY[25]
		USE SIGNAL ;
		DIRECTION OUTPUT ;
		SHAPE ABUTMENT ;
		PORT
			 LAYER M2 ;
			RECT 0.0098 33.2424 0.0481 33.3427 ;
			 LAYER M3 ;
			RECT 0.0098 33.2424 0.0481 33.3427 ;
			 LAYER V2 ;
			RECT 0.021 33.2553 0.0359 33.2678 ;
		END

		ANTENNADIFFAREA 0.00194719 ;
		ANTENNAPARTIALMETALAREA 0.00195671 ;
	END WENY[25]

	PIN WENY[26]
		USE SIGNAL ;
		DIRECTION OUTPUT ;
		SHAPE ABUTMENT ;
		PORT
			 LAYER M2 ;
			RECT 0.0098 34.5224 0.0481 34.6227 ;
			 LAYER M3 ;
			RECT 0.0098 34.5224 0.0481 34.6227 ;
			 LAYER V2 ;
			RECT 0.021 34.5353 0.0359 34.5478 ;
		END

		ANTENNADIFFAREA 0.00194719 ;
		ANTENNAPARTIALMETALAREA 0.00195671 ;
	END WENY[26]

	PIN WENY[27]
		USE SIGNAL ;
		DIRECTION OUTPUT ;
		SHAPE ABUTMENT ;
		PORT
			 LAYER M2 ;
			RECT 0.0098 35.8024 0.0481 35.9027 ;
			 LAYER M3 ;
			RECT 0.0098 35.8024 0.0481 35.9027 ;
			 LAYER V2 ;
			RECT 0.021 35.8153 0.0359 35.8278 ;
		END

		ANTENNADIFFAREA 0.00194719 ;
		ANTENNAPARTIALMETALAREA 0.00195671 ;
	END WENY[27]

	PIN WENY[28]
		USE SIGNAL ;
		DIRECTION OUTPUT ;
		SHAPE ABUTMENT ;
		PORT
			 LAYER M2 ;
			RECT 0.0098 37.0824 0.0481 37.1827 ;
			 LAYER M3 ;
			RECT 0.0098 37.0824 0.0481 37.1827 ;
			 LAYER V2 ;
			RECT 0.021 37.0953 0.0359 37.1078 ;
		END

		ANTENNADIFFAREA 0.00194719 ;
		ANTENNAPARTIALMETALAREA 0.00195671 ;
	END WENY[28]

	PIN WENY[29]
		USE SIGNAL ;
		DIRECTION OUTPUT ;
		SHAPE ABUTMENT ;
		PORT
			 LAYER M2 ;
			RECT 0.0098 38.3624 0.0481 38.4627 ;
			 LAYER M3 ;
			RECT 0.0098 38.3624 0.0481 38.4627 ;
			 LAYER V2 ;
			RECT 0.021 38.3753 0.0359 38.3878 ;
		END

		ANTENNADIFFAREA 0.00194719 ;
		ANTENNAPARTIALMETALAREA 0.00195671 ;
	END WENY[29]

	PIN WENY[2]
		USE SIGNAL ;
		DIRECTION OUTPUT ;
		SHAPE ABUTMENT ;
		PORT
			 LAYER M2 ;
			RECT 0.0098 3.8024 0.0481 3.9027 ;
			 LAYER M3 ;
			RECT 0.0098 3.8024 0.0481 3.9027 ;
			 LAYER V2 ;
			RECT 0.021 3.8153 0.0359 3.8278 ;
		END

		ANTENNADIFFAREA 0.00194719 ;
		ANTENNAPARTIALMETALAREA 0.00195671 ;
	END WENY[2]

	PIN WENY[30]
		USE SIGNAL ;
		DIRECTION OUTPUT ;
		SHAPE ABUTMENT ;
		PORT
			 LAYER M2 ;
			RECT 0.0098 39.6424 0.0481 39.7427 ;
			 LAYER M3 ;
			RECT 0.0098 39.6424 0.0481 39.7427 ;
			 LAYER V2 ;
			RECT 0.021 39.6553 0.0359 39.6678 ;
		END

		ANTENNADIFFAREA 0.00194719 ;
		ANTENNAPARTIALMETALAREA 0.00195671 ;
	END WENY[30]

	PIN WENY[31]
		USE SIGNAL ;
		DIRECTION OUTPUT ;
		SHAPE ABUTMENT ;
		PORT
			 LAYER M2 ;
			RECT 0.0098 40.9224 0.0481 41.0227 ;
			 LAYER M3 ;
			RECT 0.0098 40.9224 0.0481 41.0227 ;
			 LAYER V2 ;
			RECT 0.021 40.9353 0.0359 40.9478 ;
		END

		ANTENNADIFFAREA 0.00194719 ;
		ANTENNAPARTIALMETALAREA 0.00195671 ;
	END WENY[31]

	PIN WENY[32]
		USE SIGNAL ;
		DIRECTION OUTPUT ;
		SHAPE ABUTMENT ;
		PORT
			 LAYER M2 ;
			RECT 0.0098 49.0478 0.0481 49.1482 ;
			 LAYER M3 ;
			RECT 0.0098 49.0478 0.0481 49.1482 ;
			 LAYER V2 ;
			RECT 0.021 49.1227 0.0359 49.1353 ;
		END

		ANTENNADIFFAREA 0.00194719 ;
		ANTENNAPARTIALMETALAREA 0.00195671 ;
	END WENY[32]

	PIN WENY[33]
		USE SIGNAL ;
		DIRECTION OUTPUT ;
		SHAPE ABUTMENT ;
		PORT
			 LAYER M2 ;
			RECT 0.0098 50.3278 0.0481 50.4282 ;
			 LAYER M3 ;
			RECT 0.0098 50.3278 0.0481 50.4282 ;
			 LAYER V2 ;
			RECT 0.021 50.4027 0.0359 50.4153 ;
		END

		ANTENNADIFFAREA 0.00194719 ;
		ANTENNAPARTIALMETALAREA 0.00195671 ;
	END WENY[33]

	PIN WENY[34]
		USE SIGNAL ;
		DIRECTION OUTPUT ;
		SHAPE ABUTMENT ;
		PORT
			 LAYER M2 ;
			RECT 0.0098 51.6078 0.0481 51.7082 ;
			 LAYER M3 ;
			RECT 0.0098 51.6078 0.0481 51.7082 ;
			 LAYER V2 ;
			RECT 0.021 51.6827 0.0359 51.6953 ;
		END

		ANTENNADIFFAREA 0.00194719 ;
		ANTENNAPARTIALMETALAREA 0.00195671 ;
	END WENY[34]

	PIN WENY[35]
		USE SIGNAL ;
		DIRECTION OUTPUT ;
		SHAPE ABUTMENT ;
		PORT
			 LAYER M2 ;
			RECT 0.0098 52.8878 0.0481 52.9882 ;
			 LAYER M3 ;
			RECT 0.0098 52.8878 0.0481 52.9882 ;
			 LAYER V2 ;
			RECT 0.021 52.9627 0.0359 52.9753 ;
		END

		ANTENNADIFFAREA 0.00194719 ;
		ANTENNAPARTIALMETALAREA 0.00195671 ;
	END WENY[35]

	PIN WENY[36]
		USE SIGNAL ;
		DIRECTION OUTPUT ;
		SHAPE ABUTMENT ;
		PORT
			 LAYER M2 ;
			RECT 0.0098 54.1678 0.0481 54.2682 ;
			 LAYER M3 ;
			RECT 0.0098 54.1678 0.0481 54.2682 ;
			 LAYER V2 ;
			RECT 0.021 54.2427 0.0359 54.2553 ;
		END

		ANTENNADIFFAREA 0.00194719 ;
		ANTENNAPARTIALMETALAREA 0.00195671 ;
	END WENY[36]

	PIN WENY[37]
		USE SIGNAL ;
		DIRECTION OUTPUT ;
		SHAPE ABUTMENT ;
		PORT
			 LAYER M2 ;
			RECT 0.0098 55.4478 0.0481 55.5482 ;
			 LAYER M3 ;
			RECT 0.0098 55.4478 0.0481 55.5482 ;
			 LAYER V2 ;
			RECT 0.021 55.5227 0.0359 55.5353 ;
		END

		ANTENNADIFFAREA 0.00194719 ;
		ANTENNAPARTIALMETALAREA 0.00195671 ;
	END WENY[37]

	PIN WENY[38]
		USE SIGNAL ;
		DIRECTION OUTPUT ;
		SHAPE ABUTMENT ;
		PORT
			 LAYER M2 ;
			RECT 0.0098 56.7278 0.0481 56.8282 ;
			 LAYER M3 ;
			RECT 0.0098 56.7278 0.0481 56.8282 ;
			 LAYER V2 ;
			RECT 0.021 56.8027 0.0359 56.8153 ;
		END

		ANTENNADIFFAREA 0.00194719 ;
		ANTENNAPARTIALMETALAREA 0.00195671 ;
	END WENY[38]

	PIN WENY[39]
		USE SIGNAL ;
		DIRECTION OUTPUT ;
		SHAPE ABUTMENT ;
		PORT
			 LAYER M2 ;
			RECT 0.0098 58.0078 0.0481 58.1082 ;
			 LAYER M3 ;
			RECT 0.0098 58.0078 0.0481 58.1082 ;
			 LAYER V2 ;
			RECT 0.021 58.0827 0.0359 58.0953 ;
		END

		ANTENNADIFFAREA 0.00194719 ;
		ANTENNAPARTIALMETALAREA 0.00195671 ;
	END WENY[39]

	PIN WENY[3]
		USE SIGNAL ;
		DIRECTION OUTPUT ;
		SHAPE ABUTMENT ;
		PORT
			 LAYER M2 ;
			RECT 0.0098 5.0824 0.0481 5.1827 ;
			 LAYER M3 ;
			RECT 0.0098 5.0824 0.0481 5.1827 ;
			 LAYER V2 ;
			RECT 0.021 5.0953 0.0359 5.1078 ;
		END

		ANTENNADIFFAREA 0.00194719 ;
		ANTENNAPARTIALMETALAREA 0.00195671 ;
	END WENY[3]

	PIN WENY[40]
		USE SIGNAL ;
		DIRECTION OUTPUT ;
		SHAPE ABUTMENT ;
		PORT
			 LAYER M2 ;
			RECT 0.0098 59.2878 0.0481 59.3882 ;
			 LAYER M3 ;
			RECT 0.0098 59.2878 0.0481 59.3882 ;
			 LAYER V2 ;
			RECT 0.021 59.3627 0.0359 59.3753 ;
		END

		ANTENNADIFFAREA 0.00194719 ;
		ANTENNAPARTIALMETALAREA 0.00195671 ;
	END WENY[40]

	PIN WENY[41]
		USE SIGNAL ;
		DIRECTION OUTPUT ;
		SHAPE ABUTMENT ;
		PORT
			 LAYER M2 ;
			RECT 0.0098 60.5678 0.0481 60.6682 ;
			 LAYER M3 ;
			RECT 0.0098 60.5678 0.0481 60.6682 ;
			 LAYER V2 ;
			RECT 0.021 60.6427 0.0359 60.6553 ;
		END

		ANTENNADIFFAREA 0.00194719 ;
		ANTENNAPARTIALMETALAREA 0.00195671 ;
	END WENY[41]

	PIN WENY[42]
		USE SIGNAL ;
		DIRECTION OUTPUT ;
		SHAPE ABUTMENT ;
		PORT
			 LAYER M2 ;
			RECT 0.0098 61.8478 0.0481 61.9482 ;
			 LAYER M3 ;
			RECT 0.0098 61.8478 0.0481 61.9482 ;
			 LAYER V2 ;
			RECT 0.021 61.9227 0.0359 61.9353 ;
		END

		ANTENNADIFFAREA 0.00194719 ;
		ANTENNAPARTIALMETALAREA 0.00195671 ;
	END WENY[42]

	PIN WENY[43]
		USE SIGNAL ;
		DIRECTION OUTPUT ;
		SHAPE ABUTMENT ;
		PORT
			 LAYER M2 ;
			RECT 0.0098 63.1278 0.0481 63.2282 ;
			 LAYER M3 ;
			RECT 0.0098 63.1278 0.0481 63.2282 ;
			 LAYER V2 ;
			RECT 0.021 63.2027 0.0359 63.2153 ;
		END

		ANTENNADIFFAREA 0.00194719 ;
		ANTENNAPARTIALMETALAREA 0.00195671 ;
	END WENY[43]

	PIN WENY[44]
		USE SIGNAL ;
		DIRECTION OUTPUT ;
		SHAPE ABUTMENT ;
		PORT
			 LAYER M2 ;
			RECT 0.0098 64.4078 0.0481 64.5082 ;
			 LAYER M3 ;
			RECT 0.0098 64.4078 0.0481 64.5082 ;
			 LAYER V2 ;
			RECT 0.021 64.4827 0.0359 64.4953 ;
		END

		ANTENNADIFFAREA 0.00194719 ;
		ANTENNAPARTIALMETALAREA 0.00195671 ;
	END WENY[44]

	PIN WENY[45]
		USE SIGNAL ;
		DIRECTION OUTPUT ;
		SHAPE ABUTMENT ;
		PORT
			 LAYER M2 ;
			RECT 0.0098 65.6878 0.0481 65.7882 ;
			 LAYER M3 ;
			RECT 0.0098 65.6878 0.0481 65.7882 ;
			 LAYER V2 ;
			RECT 0.021 65.7627 0.0359 65.7753 ;
		END

		ANTENNADIFFAREA 0.00194719 ;
		ANTENNAPARTIALMETALAREA 0.00195671 ;
	END WENY[45]

	PIN WENY[46]
		USE SIGNAL ;
		DIRECTION OUTPUT ;
		SHAPE ABUTMENT ;
		PORT
			 LAYER M2 ;
			RECT 0.0098 66.9678 0.0481 67.0682 ;
			 LAYER M3 ;
			RECT 0.0098 66.9678 0.0481 67.0682 ;
			 LAYER V2 ;
			RECT 0.021 67.0427 0.0359 67.0553 ;
		END

		ANTENNADIFFAREA 0.00194719 ;
		ANTENNAPARTIALMETALAREA 0.00195671 ;
	END WENY[46]

	PIN WENY[47]
		USE SIGNAL ;
		DIRECTION OUTPUT ;
		SHAPE ABUTMENT ;
		PORT
			 LAYER M2 ;
			RECT 0.0098 68.2478 0.0481 68.3482 ;
			 LAYER M3 ;
			RECT 0.0098 68.2478 0.0481 68.3482 ;
			 LAYER V2 ;
			RECT 0.021 68.3227 0.0359 68.3353 ;
		END

		ANTENNADIFFAREA 0.00194719 ;
		ANTENNAPARTIALMETALAREA 0.00195671 ;
	END WENY[47]

	PIN WENY[48]
		USE SIGNAL ;
		DIRECTION OUTPUT ;
		SHAPE ABUTMENT ;
		PORT
			 LAYER M2 ;
			RECT 0.0098 69.5278 0.0481 69.6282 ;
			 LAYER M3 ;
			RECT 0.0098 69.5278 0.0481 69.6282 ;
			 LAYER V2 ;
			RECT 0.021 69.6027 0.0359 69.6153 ;
		END

		ANTENNADIFFAREA 0.00194719 ;
		ANTENNAPARTIALMETALAREA 0.00195671 ;
	END WENY[48]

	PIN WENY[49]
		USE SIGNAL ;
		DIRECTION OUTPUT ;
		SHAPE ABUTMENT ;
		PORT
			 LAYER M2 ;
			RECT 0.0098 70.8078 0.0481 70.9082 ;
			 LAYER M3 ;
			RECT 0.0098 70.8078 0.0481 70.9082 ;
			 LAYER V2 ;
			RECT 0.021 70.8827 0.0359 70.8953 ;
		END

		ANTENNADIFFAREA 0.00194719 ;
		ANTENNAPARTIALMETALAREA 0.00195671 ;
	END WENY[49]

	PIN WENY[4]
		USE SIGNAL ;
		DIRECTION OUTPUT ;
		SHAPE ABUTMENT ;
		PORT
			 LAYER M2 ;
			RECT 0.0098 6.3624 0.0481 6.4627 ;
			 LAYER M3 ;
			RECT 0.0098 6.3624 0.0481 6.4627 ;
			 LAYER V2 ;
			RECT 0.021 6.3753 0.0359 6.3878 ;
		END

		ANTENNADIFFAREA 0.00194719 ;
		ANTENNAPARTIALMETALAREA 0.00195671 ;
	END WENY[4]

	PIN WENY[50]
		USE SIGNAL ;
		DIRECTION OUTPUT ;
		SHAPE ABUTMENT ;
		PORT
			 LAYER M2 ;
			RECT 0.0098 72.0878 0.0481 72.1882 ;
			 LAYER M3 ;
			RECT 0.0098 72.0878 0.0481 72.1882 ;
			 LAYER V2 ;
			RECT 0.021 72.1627 0.0359 72.1753 ;
		END

		ANTENNADIFFAREA 0.00194719 ;
		ANTENNAPARTIALMETALAREA 0.00195671 ;
	END WENY[50]

	PIN WENY[51]
		USE SIGNAL ;
		DIRECTION OUTPUT ;
		SHAPE ABUTMENT ;
		PORT
			 LAYER M2 ;
			RECT 0.0098 73.3678 0.0481 73.4682 ;
			 LAYER M3 ;
			RECT 0.0098 73.3678 0.0481 73.4682 ;
			 LAYER V2 ;
			RECT 0.021 73.4427 0.0359 73.4553 ;
		END

		ANTENNADIFFAREA 0.00194719 ;
		ANTENNAPARTIALMETALAREA 0.00195671 ;
	END WENY[51]

	PIN WENY[52]
		USE SIGNAL ;
		DIRECTION OUTPUT ;
		SHAPE ABUTMENT ;
		PORT
			 LAYER M2 ;
			RECT 0.0098 74.6478 0.0481 74.7482 ;
			 LAYER M3 ;
			RECT 0.0098 74.6478 0.0481 74.7482 ;
			 LAYER V2 ;
			RECT 0.021 74.7227 0.0359 74.7353 ;
		END

		ANTENNADIFFAREA 0.00194719 ;
		ANTENNAPARTIALMETALAREA 0.00195671 ;
	END WENY[52]

	PIN WENY[53]
		USE SIGNAL ;
		DIRECTION OUTPUT ;
		SHAPE ABUTMENT ;
		PORT
			 LAYER M2 ;
			RECT 0.0098 75.9278 0.0481 76.0282 ;
			 LAYER M3 ;
			RECT 0.0098 75.9278 0.0481 76.0282 ;
			 LAYER V2 ;
			RECT 0.021 76.0027 0.0359 76.0153 ;
		END

		ANTENNADIFFAREA 0.00194719 ;
		ANTENNAPARTIALMETALAREA 0.00195671 ;
	END WENY[53]

	PIN WENY[54]
		USE SIGNAL ;
		DIRECTION OUTPUT ;
		SHAPE ABUTMENT ;
		PORT
			 LAYER M2 ;
			RECT 0.0098 77.2078 0.0481 77.3082 ;
			 LAYER M3 ;
			RECT 0.0098 77.2078 0.0481 77.3082 ;
			 LAYER V2 ;
			RECT 0.021 77.2827 0.0359 77.2953 ;
		END

		ANTENNADIFFAREA 0.00194719 ;
		ANTENNAPARTIALMETALAREA 0.00195671 ;
	END WENY[54]

	PIN WENY[55]
		USE SIGNAL ;
		DIRECTION OUTPUT ;
		SHAPE ABUTMENT ;
		PORT
			 LAYER M2 ;
			RECT 0.0098 78.4878 0.0481 78.5882 ;
			 LAYER M3 ;
			RECT 0.0098 78.4878 0.0481 78.5882 ;
			 LAYER V2 ;
			RECT 0.021 78.5627 0.0359 78.5753 ;
		END

		ANTENNADIFFAREA 0.00194719 ;
		ANTENNAPARTIALMETALAREA 0.00195671 ;
	END WENY[55]

	PIN WENY[56]
		USE SIGNAL ;
		DIRECTION OUTPUT ;
		SHAPE ABUTMENT ;
		PORT
			 LAYER M2 ;
			RECT 0.0098 79.7678 0.0481 79.8682 ;
			 LAYER M3 ;
			RECT 0.0098 79.7678 0.0481 79.8682 ;
			 LAYER V2 ;
			RECT 0.021 79.8427 0.0359 79.8553 ;
		END

		ANTENNADIFFAREA 0.00194719 ;
		ANTENNAPARTIALMETALAREA 0.00195671 ;
	END WENY[56]

	PIN WENY[57]
		USE SIGNAL ;
		DIRECTION OUTPUT ;
		SHAPE ABUTMENT ;
		PORT
			 LAYER M2 ;
			RECT 0.0098 81.0478 0.0481 81.1482 ;
			 LAYER M3 ;
			RECT 0.0098 81.0478 0.0481 81.1482 ;
			 LAYER V2 ;
			RECT 0.021 81.1227 0.0359 81.1353 ;
		END

		ANTENNADIFFAREA 0.00194719 ;
		ANTENNAPARTIALMETALAREA 0.00195671 ;
	END WENY[57]

	PIN WENY[58]
		USE SIGNAL ;
		DIRECTION OUTPUT ;
		SHAPE ABUTMENT ;
		PORT
			 LAYER M2 ;
			RECT 0.0098 82.3278 0.0481 82.4282 ;
			 LAYER M3 ;
			RECT 0.0098 82.3278 0.0481 82.4282 ;
			 LAYER V2 ;
			RECT 0.021 82.4027 0.0359 82.4153 ;
		END

		ANTENNADIFFAREA 0.00194719 ;
		ANTENNAPARTIALMETALAREA 0.00195671 ;
	END WENY[58]

	PIN WENY[59]
		USE SIGNAL ;
		DIRECTION OUTPUT ;
		SHAPE ABUTMENT ;
		PORT
			 LAYER M2 ;
			RECT 0.0098 83.6078 0.0481 83.7082 ;
			 LAYER M3 ;
			RECT 0.0098 83.6078 0.0481 83.7082 ;
			 LAYER V2 ;
			RECT 0.021 83.6827 0.0359 83.6953 ;
		END

		ANTENNADIFFAREA 0.00194719 ;
		ANTENNAPARTIALMETALAREA 0.00195671 ;
	END WENY[59]

	PIN WENY[5]
		USE SIGNAL ;
		DIRECTION OUTPUT ;
		SHAPE ABUTMENT ;
		PORT
			 LAYER M2 ;
			RECT 0.0098 7.6424 0.0481 7.7427 ;
			 LAYER M3 ;
			RECT 0.0098 7.6424 0.0481 7.7427 ;
			 LAYER V2 ;
			RECT 0.021 7.6553 0.0359 7.6678 ;
		END

		ANTENNADIFFAREA 0.00194719 ;
		ANTENNAPARTIALMETALAREA 0.00195671 ;
	END WENY[5]

	PIN WENY[60]
		USE SIGNAL ;
		DIRECTION OUTPUT ;
		SHAPE ABUTMENT ;
		PORT
			 LAYER M2 ;
			RECT 0.0098 84.8878 0.0481 84.9882 ;
			 LAYER M3 ;
			RECT 0.0098 84.8878 0.0481 84.9882 ;
			 LAYER V2 ;
			RECT 0.021 84.9627 0.0359 84.9753 ;
		END

		ANTENNADIFFAREA 0.00194719 ;
		ANTENNAPARTIALMETALAREA 0.00195671 ;
	END WENY[60]

	PIN WENY[61]
		USE SIGNAL ;
		DIRECTION OUTPUT ;
		SHAPE ABUTMENT ;
		PORT
			 LAYER M2 ;
			RECT 0.0098 86.1678 0.0481 86.2682 ;
			 LAYER M3 ;
			RECT 0.0098 86.1678 0.0481 86.2682 ;
			 LAYER V2 ;
			RECT 0.021 86.2427 0.0359 86.2553 ;
		END

		ANTENNADIFFAREA 0.00194719 ;
		ANTENNAPARTIALMETALAREA 0.00195671 ;
	END WENY[61]

	PIN WENY[62]
		USE SIGNAL ;
		DIRECTION OUTPUT ;
		SHAPE ABUTMENT ;
		PORT
			 LAYER M2 ;
			RECT 0.0098 87.4478 0.0481 87.5482 ;
			 LAYER M3 ;
			RECT 0.0098 87.4478 0.0481 87.5482 ;
			 LAYER V2 ;
			RECT 0.021 87.5227 0.0359 87.5353 ;
		END

		ANTENNADIFFAREA 0.00194719 ;
		ANTENNAPARTIALMETALAREA 0.00195671 ;
	END WENY[62]

	PIN WENY[63]
		USE SIGNAL ;
		DIRECTION OUTPUT ;
		SHAPE ABUTMENT ;
		PORT
			 LAYER M2 ;
			RECT 0.0098 88.7278 0.0481 88.8282 ;
			 LAYER M3 ;
			RECT 0.0098 88.7278 0.0481 88.8282 ;
			 LAYER V2 ;
			RECT 0.021 88.8027 0.0359 88.8153 ;
		END

		ANTENNADIFFAREA 0.00194719 ;
		ANTENNAPARTIALMETALAREA 0.00195671 ;
	END WENY[63]

	PIN WENY[6]
		USE SIGNAL ;
		DIRECTION OUTPUT ;
		SHAPE ABUTMENT ;
		PORT
			 LAYER M2 ;
			RECT 0.0098 8.9224 0.0481 9.0227 ;
			 LAYER M3 ;
			RECT 0.0098 8.9224 0.0481 9.0227 ;
			 LAYER V2 ;
			RECT 0.021 8.9353 0.0359 8.9478 ;
		END

		ANTENNADIFFAREA 0.00194719 ;
		ANTENNAPARTIALMETALAREA 0.00195671 ;
	END WENY[6]

	PIN WENY[7]
		USE SIGNAL ;
		DIRECTION OUTPUT ;
		SHAPE ABUTMENT ;
		PORT
			 LAYER M2 ;
			RECT 0.0098 10.2024 0.0481 10.3027 ;
			 LAYER M3 ;
			RECT 0.0098 10.2024 0.0481 10.3027 ;
			 LAYER V2 ;
			RECT 0.021 10.2153 0.0359 10.2278 ;
		END

		ANTENNADIFFAREA 0.00194719 ;
		ANTENNAPARTIALMETALAREA 0.00195671 ;
	END WENY[7]

	PIN WENY[8]
		USE SIGNAL ;
		DIRECTION OUTPUT ;
		SHAPE ABUTMENT ;
		PORT
			 LAYER M2 ;
			RECT 0.0098 11.4824 0.0481 11.5827 ;
			 LAYER M3 ;
			RECT 0.0098 11.4824 0.0481 11.5827 ;
			 LAYER V2 ;
			RECT 0.021 11.4953 0.0359 11.5078 ;
		END

		ANTENNADIFFAREA 0.00194719 ;
		ANTENNAPARTIALMETALAREA 0.00195671 ;
	END WENY[8]

	PIN WENY[9]
		USE SIGNAL ;
		DIRECTION OUTPUT ;
		SHAPE ABUTMENT ;
		PORT
			 LAYER M2 ;
			RECT 0.0098 12.7624 0.0481 12.8627 ;
			 LAYER M3 ;
			RECT 0.0098 12.7624 0.0481 12.8627 ;
			 LAYER V2 ;
			RECT 0.021 12.7753 0.0359 12.7878 ;
		END

		ANTENNADIFFAREA 0.00194719 ;
		ANTENNAPARTIALMETALAREA 0.00195671 ;
	END WENY[9]

	PIN WEN[0]
		USE SIGNAL ;
		DIRECTION INPUT ;
		SHAPE ABUTMENT ;
		PORT
			 LAYER M2 ;
			RECT 0.0714 1.029 0.1097 1.0667 ;
			 LAYER M3 ;
			RECT 0.0714 0.9663 0.1097 1.0667 ;
			 LAYER V2 ;
			RECT 0.0831 1.042 0.098 1.0545 ;
		END

		ANTENNAGATEAREA 0.00027817 ;
		ANTENNADIFFAREA 0.00194719 ;
		ANTENNAPARTIALMETALAREA 0.00195671 ;
	END WEN[0]

	PIN WEN[10]
		USE SIGNAL ;
		DIRECTION INPUT ;
		SHAPE ABUTMENT ;
		PORT
			 LAYER M2 ;
			RECT 0.0714 13.829 0.1097 13.8667 ;
			 LAYER M3 ;
			RECT 0.0714 13.7663 0.1097 13.8667 ;
			 LAYER V2 ;
			RECT 0.0831 13.842 0.098 13.8545 ;
		END

		ANTENNAGATEAREA 0.00027817 ;
		ANTENNADIFFAREA 0.00194719 ;
		ANTENNAPARTIALMETALAREA 0.00195671 ;
	END WEN[10]

	PIN WEN[11]
		USE SIGNAL ;
		DIRECTION INPUT ;
		SHAPE ABUTMENT ;
		PORT
			 LAYER M2 ;
			RECT 0.0714 15.109 0.1097 15.1467 ;
			 LAYER M3 ;
			RECT 0.0714 15.0463 0.1097 15.1467 ;
			 LAYER V2 ;
			RECT 0.0831 15.122 0.098 15.1345 ;
		END

		ANTENNAGATEAREA 0.00027817 ;
		ANTENNADIFFAREA 0.00194719 ;
		ANTENNAPARTIALMETALAREA 0.00195671 ;
	END WEN[11]

	PIN WEN[12]
		USE SIGNAL ;
		DIRECTION INPUT ;
		SHAPE ABUTMENT ;
		PORT
			 LAYER M2 ;
			RECT 0.0714 16.389 0.1097 16.4267 ;
			 LAYER M3 ;
			RECT 0.0714 16.3263 0.1097 16.4267 ;
			 LAYER V2 ;
			RECT 0.0831 16.402 0.098 16.4145 ;
		END

		ANTENNAGATEAREA 0.00027817 ;
		ANTENNADIFFAREA 0.00194719 ;
		ANTENNAPARTIALMETALAREA 0.00195671 ;
	END WEN[12]

	PIN WEN[13]
		USE SIGNAL ;
		DIRECTION INPUT ;
		SHAPE ABUTMENT ;
		PORT
			 LAYER M2 ;
			RECT 0.0714 17.669 0.1097 17.7067 ;
			 LAYER M3 ;
			RECT 0.0714 17.6063 0.1097 17.7067 ;
			 LAYER V2 ;
			RECT 0.0831 17.682 0.098 17.6945 ;
		END

		ANTENNAGATEAREA 0.00027817 ;
		ANTENNADIFFAREA 0.00194719 ;
		ANTENNAPARTIALMETALAREA 0.00195671 ;
	END WEN[13]

	PIN WEN[14]
		USE SIGNAL ;
		DIRECTION INPUT ;
		SHAPE ABUTMENT ;
		PORT
			 LAYER M2 ;
			RECT 0.0714 18.949 0.1097 18.9867 ;
			 LAYER M3 ;
			RECT 0.0714 18.8863 0.1097 18.9867 ;
			 LAYER V2 ;
			RECT 0.0831 18.962 0.098 18.9745 ;
		END

		ANTENNAGATEAREA 0.00027817 ;
		ANTENNADIFFAREA 0.00194719 ;
		ANTENNAPARTIALMETALAREA 0.00195671 ;
	END WEN[14]

	PIN WEN[15]
		USE SIGNAL ;
		DIRECTION INPUT ;
		SHAPE ABUTMENT ;
		PORT
			 LAYER M2 ;
			RECT 0.0714 20.229 0.1097 20.2667 ;
			 LAYER M3 ;
			RECT 0.0714 20.1663 0.1097 20.2667 ;
			 LAYER V2 ;
			RECT 0.0831 20.242 0.098 20.2545 ;
		END

		ANTENNAGATEAREA 0.00027817 ;
		ANTENNADIFFAREA 0.00194719 ;
		ANTENNAPARTIALMETALAREA 0.00195671 ;
	END WEN[15]

	PIN WEN[16]
		USE SIGNAL ;
		DIRECTION INPUT ;
		SHAPE ABUTMENT ;
		PORT
			 LAYER M2 ;
			RECT 0.0714 21.509 0.1097 21.5467 ;
			 LAYER M3 ;
			RECT 0.0714 21.4463 0.1097 21.5467 ;
			 LAYER V2 ;
			RECT 0.0831 21.522 0.098 21.5345 ;
		END

		ANTENNAGATEAREA 0.00027817 ;
		ANTENNADIFFAREA 0.00194719 ;
		ANTENNAPARTIALMETALAREA 0.00195671 ;
	END WEN[16]

	PIN WEN[17]
		USE SIGNAL ;
		DIRECTION INPUT ;
		SHAPE ABUTMENT ;
		PORT
			 LAYER M2 ;
			RECT 0.0714 22.789 0.1097 22.8267 ;
			 LAYER M3 ;
			RECT 0.0714 22.7263 0.1097 22.8267 ;
			 LAYER V2 ;
			RECT 0.0831 22.802 0.098 22.8145 ;
		END

		ANTENNAGATEAREA 0.00027817 ;
		ANTENNADIFFAREA 0.00194719 ;
		ANTENNAPARTIALMETALAREA 0.00195671 ;
	END WEN[17]

	PIN WEN[18]
		USE SIGNAL ;
		DIRECTION INPUT ;
		SHAPE ABUTMENT ;
		PORT
			 LAYER M2 ;
			RECT 0.0714 24.069 0.1097 24.1067 ;
			 LAYER M3 ;
			RECT 0.0714 24.0063 0.1097 24.1067 ;
			 LAYER V2 ;
			RECT 0.0831 24.082 0.098 24.0945 ;
		END

		ANTENNAGATEAREA 0.00027817 ;
		ANTENNADIFFAREA 0.00194719 ;
		ANTENNAPARTIALMETALAREA 0.00195671 ;
	END WEN[18]

	PIN WEN[19]
		USE SIGNAL ;
		DIRECTION INPUT ;
		SHAPE ABUTMENT ;
		PORT
			 LAYER M2 ;
			RECT 0.0714 25.349 0.1097 25.3867 ;
			 LAYER M3 ;
			RECT 0.0714 25.2863 0.1097 25.3867 ;
			 LAYER V2 ;
			RECT 0.0831 25.362 0.098 25.3745 ;
		END

		ANTENNAGATEAREA 0.00027817 ;
		ANTENNADIFFAREA 0.00194719 ;
		ANTENNAPARTIALMETALAREA 0.00195671 ;
	END WEN[19]

	PIN WEN[1]
		USE SIGNAL ;
		DIRECTION INPUT ;
		SHAPE ABUTMENT ;
		PORT
			 LAYER M2 ;
			RECT 0.0714 2.309 0.1097 2.3467 ;
			 LAYER M3 ;
			RECT 0.0714 2.2463 0.1097 2.3467 ;
			 LAYER V2 ;
			RECT 0.0831 2.322 0.098 2.3345 ;
		END

		ANTENNAGATEAREA 0.00027817 ;
		ANTENNADIFFAREA 0.00194719 ;
		ANTENNAPARTIALMETALAREA 0.00195671 ;
	END WEN[1]

	PIN WEN[20]
		USE SIGNAL ;
		DIRECTION INPUT ;
		SHAPE ABUTMENT ;
		PORT
			 LAYER M2 ;
			RECT 0.0714 26.629 0.1097 26.6667 ;
			 LAYER M3 ;
			RECT 0.0714 26.5663 0.1097 26.6667 ;
			 LAYER V2 ;
			RECT 0.0831 26.642 0.098 26.6545 ;
		END

		ANTENNAGATEAREA 0.00027817 ;
		ANTENNADIFFAREA 0.00194719 ;
		ANTENNAPARTIALMETALAREA 0.00195671 ;
	END WEN[20]

	PIN WEN[21]
		USE SIGNAL ;
		DIRECTION INPUT ;
		SHAPE ABUTMENT ;
		PORT
			 LAYER M2 ;
			RECT 0.0714 27.909 0.1097 27.9467 ;
			 LAYER M3 ;
			RECT 0.0714 27.8463 0.1097 27.9467 ;
			 LAYER V2 ;
			RECT 0.0831 27.922 0.098 27.9345 ;
		END

		ANTENNAGATEAREA 0.00027817 ;
		ANTENNADIFFAREA 0.00194719 ;
		ANTENNAPARTIALMETALAREA 0.00195671 ;
	END WEN[21]

	PIN WEN[22]
		USE SIGNAL ;
		DIRECTION INPUT ;
		SHAPE ABUTMENT ;
		PORT
			 LAYER M2 ;
			RECT 0.0714 29.189 0.1097 29.2267 ;
			 LAYER M3 ;
			RECT 0.0714 29.1263 0.1097 29.2267 ;
			 LAYER V2 ;
			RECT 0.0831 29.202 0.098 29.2145 ;
		END

		ANTENNAGATEAREA 0.00027817 ;
		ANTENNADIFFAREA 0.00194719 ;
		ANTENNAPARTIALMETALAREA 0.00195671 ;
	END WEN[22]

	PIN WEN[23]
		USE SIGNAL ;
		DIRECTION INPUT ;
		SHAPE ABUTMENT ;
		PORT
			 LAYER M2 ;
			RECT 0.0714 30.469 0.1097 30.5067 ;
			 LAYER M3 ;
			RECT 0.0714 30.4063 0.1097 30.5067 ;
			 LAYER V2 ;
			RECT 0.0831 30.482 0.098 30.4945 ;
		END

		ANTENNAGATEAREA 0.00027817 ;
		ANTENNADIFFAREA 0.00194719 ;
		ANTENNAPARTIALMETALAREA 0.00195671 ;
	END WEN[23]

	PIN WEN[24]
		USE SIGNAL ;
		DIRECTION INPUT ;
		SHAPE ABUTMENT ;
		PORT
			 LAYER M2 ;
			RECT 0.0714 31.749 0.1097 31.7867 ;
			 LAYER M3 ;
			RECT 0.0714 31.6863 0.1097 31.7867 ;
			 LAYER V2 ;
			RECT 0.0831 31.762 0.098 31.7745 ;
		END

		ANTENNAGATEAREA 0.00027817 ;
		ANTENNADIFFAREA 0.00194719 ;
		ANTENNAPARTIALMETALAREA 0.00195671 ;
	END WEN[24]

	PIN WEN[25]
		USE SIGNAL ;
		DIRECTION INPUT ;
		SHAPE ABUTMENT ;
		PORT
			 LAYER M2 ;
			RECT 0.0714 33.029 0.1097 33.0667 ;
			 LAYER M3 ;
			RECT 0.0714 32.9663 0.1097 33.0667 ;
			 LAYER V2 ;
			RECT 0.0831 33.042 0.098 33.0545 ;
		END

		ANTENNAGATEAREA 0.00027817 ;
		ANTENNADIFFAREA 0.00194719 ;
		ANTENNAPARTIALMETALAREA 0.00195671 ;
	END WEN[25]

	PIN WEN[26]
		USE SIGNAL ;
		DIRECTION INPUT ;
		SHAPE ABUTMENT ;
		PORT
			 LAYER M2 ;
			RECT 0.0714 34.309 0.1097 34.3467 ;
			 LAYER M3 ;
			RECT 0.0714 34.2463 0.1097 34.3467 ;
			 LAYER V2 ;
			RECT 0.0831 34.322 0.098 34.3345 ;
		END

		ANTENNAGATEAREA 0.00027817 ;
		ANTENNADIFFAREA 0.00194719 ;
		ANTENNAPARTIALMETALAREA 0.00195671 ;
	END WEN[26]

	PIN WEN[27]
		USE SIGNAL ;
		DIRECTION INPUT ;
		SHAPE ABUTMENT ;
		PORT
			 LAYER M2 ;
			RECT 0.0714 35.589 0.1097 35.6267 ;
			 LAYER M3 ;
			RECT 0.0714 35.5263 0.1097 35.6267 ;
			 LAYER V2 ;
			RECT 0.0831 35.602 0.098 35.6145 ;
		END

		ANTENNAGATEAREA 0.00027817 ;
		ANTENNADIFFAREA 0.00194719 ;
		ANTENNAPARTIALMETALAREA 0.00195671 ;
	END WEN[27]

	PIN WEN[28]
		USE SIGNAL ;
		DIRECTION INPUT ;
		SHAPE ABUTMENT ;
		PORT
			 LAYER M2 ;
			RECT 0.0714 36.869 0.1097 36.9067 ;
			 LAYER M3 ;
			RECT 0.0714 36.8063 0.1097 36.9067 ;
			 LAYER V2 ;
			RECT 0.0831 36.882 0.098 36.8945 ;
		END

		ANTENNAGATEAREA 0.00027817 ;
		ANTENNADIFFAREA 0.00194719 ;
		ANTENNAPARTIALMETALAREA 0.00195671 ;
	END WEN[28]

	PIN WEN[29]
		USE SIGNAL ;
		DIRECTION INPUT ;
		SHAPE ABUTMENT ;
		PORT
			 LAYER M2 ;
			RECT 0.0714 38.149 0.1097 38.1867 ;
			 LAYER M3 ;
			RECT 0.0714 38.0863 0.1097 38.1867 ;
			 LAYER V2 ;
			RECT 0.0831 38.162 0.098 38.1745 ;
		END

		ANTENNAGATEAREA 0.00027817 ;
		ANTENNADIFFAREA 0.00194719 ;
		ANTENNAPARTIALMETALAREA 0.00195671 ;
	END WEN[29]

	PIN WEN[2]
		USE SIGNAL ;
		DIRECTION INPUT ;
		SHAPE ABUTMENT ;
		PORT
			 LAYER M2 ;
			RECT 0.0714 3.589 0.1097 3.6267 ;
			 LAYER M3 ;
			RECT 0.0714 3.5263 0.1097 3.6267 ;
			 LAYER V2 ;
			RECT 0.0831 3.602 0.098 3.6145 ;
		END

		ANTENNAGATEAREA 0.00027817 ;
		ANTENNADIFFAREA 0.00194719 ;
		ANTENNAPARTIALMETALAREA 0.00195671 ;
	END WEN[2]

	PIN WEN[30]
		USE SIGNAL ;
		DIRECTION INPUT ;
		SHAPE ABUTMENT ;
		PORT
			 LAYER M2 ;
			RECT 0.0714 39.429 0.1097 39.4667 ;
			 LAYER M3 ;
			RECT 0.0714 39.3663 0.1097 39.4667 ;
			 LAYER V2 ;
			RECT 0.0831 39.442 0.098 39.4545 ;
		END

		ANTENNAGATEAREA 0.00027817 ;
		ANTENNADIFFAREA 0.00194719 ;
		ANTENNAPARTIALMETALAREA 0.00195671 ;
	END WEN[30]

	PIN WEN[31]
		USE SIGNAL ;
		DIRECTION INPUT ;
		SHAPE ABUTMENT ;
		PORT
			 LAYER M2 ;
			RECT 0.0714 40.709 0.1097 40.7467 ;
			 LAYER M3 ;
			RECT 0.0714 40.6463 0.1097 40.7467 ;
			 LAYER V2 ;
			RECT 0.0831 40.722 0.098 40.7345 ;
		END

		ANTENNAGATEAREA 0.00027817 ;
		ANTENNADIFFAREA 0.00194719 ;
		ANTENNAPARTIALMETALAREA 0.00195671 ;
	END WEN[31]

	PIN WEN[32]
		USE SIGNAL ;
		DIRECTION INPUT ;
		SHAPE ABUTMENT ;
		PORT
			 LAYER M2 ;
			RECT 0.0714 49.3239 0.1097 49.3616 ;
			 LAYER M3 ;
			RECT 0.0714 49.3239 0.1097 49.4243 ;
			 LAYER V2 ;
			RECT 0.0831 49.3361 0.098 49.3486 ;
		END

		ANTENNAGATEAREA 0.00027817 ;
		ANTENNADIFFAREA 0.00194719 ;
		ANTENNAPARTIALMETALAREA 0.00195671 ;
	END WEN[32]

	PIN WEN[33]
		USE SIGNAL ;
		DIRECTION INPUT ;
		SHAPE ABUTMENT ;
		PORT
			 LAYER M2 ;
			RECT 0.0714 50.6039 0.1097 50.6416 ;
			 LAYER M3 ;
			RECT 0.0714 50.6039 0.1097 50.7043 ;
			 LAYER V2 ;
			RECT 0.0831 50.6161 0.098 50.6286 ;
		END

		ANTENNAGATEAREA 0.00027817 ;
		ANTENNADIFFAREA 0.00194719 ;
		ANTENNAPARTIALMETALAREA 0.00195671 ;
	END WEN[33]

	PIN WEN[34]
		USE SIGNAL ;
		DIRECTION INPUT ;
		SHAPE ABUTMENT ;
		PORT
			 LAYER M2 ;
			RECT 0.0714 51.8839 0.1097 51.9216 ;
			 LAYER M3 ;
			RECT 0.0714 51.8839 0.1097 51.9843 ;
			 LAYER V2 ;
			RECT 0.0831 51.8961 0.098 51.9086 ;
		END

		ANTENNAGATEAREA 0.00027817 ;
		ANTENNADIFFAREA 0.00194719 ;
		ANTENNAPARTIALMETALAREA 0.00195671 ;
	END WEN[34]

	PIN WEN[35]
		USE SIGNAL ;
		DIRECTION INPUT ;
		SHAPE ABUTMENT ;
		PORT
			 LAYER M2 ;
			RECT 0.0714 53.1639 0.1097 53.2016 ;
			 LAYER M3 ;
			RECT 0.0714 53.1639 0.1097 53.2643 ;
			 LAYER V2 ;
			RECT 0.0831 53.1761 0.098 53.1886 ;
		END

		ANTENNAGATEAREA 0.00027817 ;
		ANTENNADIFFAREA 0.00194719 ;
		ANTENNAPARTIALMETALAREA 0.00195671 ;
	END WEN[35]

	PIN WEN[36]
		USE SIGNAL ;
		DIRECTION INPUT ;
		SHAPE ABUTMENT ;
		PORT
			 LAYER M2 ;
			RECT 0.0714 54.4439 0.1097 54.4816 ;
			 LAYER M3 ;
			RECT 0.0714 54.4439 0.1097 54.5443 ;
			 LAYER V2 ;
			RECT 0.0831 54.4561 0.098 54.4686 ;
		END

		ANTENNAGATEAREA 0.00027817 ;
		ANTENNADIFFAREA 0.00194719 ;
		ANTENNAPARTIALMETALAREA 0.00195671 ;
	END WEN[36]

	PIN WEN[37]
		USE SIGNAL ;
		DIRECTION INPUT ;
		SHAPE ABUTMENT ;
		PORT
			 LAYER M2 ;
			RECT 0.0714 55.7239 0.1097 55.7616 ;
			 LAYER M3 ;
			RECT 0.0714 55.7239 0.1097 55.8243 ;
			 LAYER V2 ;
			RECT 0.0831 55.7361 0.098 55.7486 ;
		END

		ANTENNAGATEAREA 0.00027817 ;
		ANTENNADIFFAREA 0.00194719 ;
		ANTENNAPARTIALMETALAREA 0.00195671 ;
	END WEN[37]

	PIN WEN[38]
		USE SIGNAL ;
		DIRECTION INPUT ;
		SHAPE ABUTMENT ;
		PORT
			 LAYER M2 ;
			RECT 0.0714 57.0039 0.1097 57.0416 ;
			 LAYER M3 ;
			RECT 0.0714 57.0039 0.1097 57.1043 ;
			 LAYER V2 ;
			RECT 0.0831 57.0161 0.098 57.0286 ;
		END

		ANTENNAGATEAREA 0.00027817 ;
		ANTENNADIFFAREA 0.00194719 ;
		ANTENNAPARTIALMETALAREA 0.00195671 ;
	END WEN[38]

	PIN WEN[39]
		USE SIGNAL ;
		DIRECTION INPUT ;
		SHAPE ABUTMENT ;
		PORT
			 LAYER M2 ;
			RECT 0.0714 58.2839 0.1097 58.3216 ;
			 LAYER M3 ;
			RECT 0.0714 58.2839 0.1097 58.3843 ;
			 LAYER V2 ;
			RECT 0.0831 58.2961 0.098 58.3086 ;
		END

		ANTENNAGATEAREA 0.00027817 ;
		ANTENNADIFFAREA 0.00194719 ;
		ANTENNAPARTIALMETALAREA 0.00195671 ;
	END WEN[39]

	PIN WEN[3]
		USE SIGNAL ;
		DIRECTION INPUT ;
		SHAPE ABUTMENT ;
		PORT
			 LAYER M2 ;
			RECT 0.0714 4.869 0.1097 4.9067 ;
			 LAYER M3 ;
			RECT 0.0714 4.8063 0.1097 4.9067 ;
			 LAYER V2 ;
			RECT 0.0831 4.882 0.098 4.8945 ;
		END

		ANTENNAGATEAREA 0.00027817 ;
		ANTENNADIFFAREA 0.00194719 ;
		ANTENNAPARTIALMETALAREA 0.00195671 ;
	END WEN[3]

	PIN WEN[40]
		USE SIGNAL ;
		DIRECTION INPUT ;
		SHAPE ABUTMENT ;
		PORT
			 LAYER M2 ;
			RECT 0.0714 59.5639 0.1097 59.6016 ;
			 LAYER M3 ;
			RECT 0.0714 59.5639 0.1097 59.6643 ;
			 LAYER V2 ;
			RECT 0.0831 59.5761 0.098 59.5886 ;
		END

		ANTENNAGATEAREA 0.00027817 ;
		ANTENNADIFFAREA 0.00194719 ;
		ANTENNAPARTIALMETALAREA 0.00195671 ;
	END WEN[40]

	PIN WEN[41]
		USE SIGNAL ;
		DIRECTION INPUT ;
		SHAPE ABUTMENT ;
		PORT
			 LAYER M2 ;
			RECT 0.0714 60.8439 0.1097 60.8816 ;
			 LAYER M3 ;
			RECT 0.0714 60.8439 0.1097 60.9443 ;
			 LAYER V2 ;
			RECT 0.0831 60.8561 0.098 60.8686 ;
		END

		ANTENNAGATEAREA 0.00027817 ;
		ANTENNADIFFAREA 0.00194719 ;
		ANTENNAPARTIALMETALAREA 0.00195671 ;
	END WEN[41]

	PIN WEN[42]
		USE SIGNAL ;
		DIRECTION INPUT ;
		SHAPE ABUTMENT ;
		PORT
			 LAYER M2 ;
			RECT 0.0714 62.1239 0.1097 62.1616 ;
			 LAYER M3 ;
			RECT 0.0714 62.1239 0.1097 62.2243 ;
			 LAYER V2 ;
			RECT 0.0831 62.1361 0.098 62.1486 ;
		END

		ANTENNAGATEAREA 0.00027817 ;
		ANTENNADIFFAREA 0.00194719 ;
		ANTENNAPARTIALMETALAREA 0.00195671 ;
	END WEN[42]

	PIN WEN[43]
		USE SIGNAL ;
		DIRECTION INPUT ;
		SHAPE ABUTMENT ;
		PORT
			 LAYER M2 ;
			RECT 0.0714 63.4039 0.1097 63.4416 ;
			 LAYER M3 ;
			RECT 0.0714 63.4039 0.1097 63.5043 ;
			 LAYER V2 ;
			RECT 0.0831 63.4161 0.098 63.4286 ;
		END

		ANTENNAGATEAREA 0.00027817 ;
		ANTENNADIFFAREA 0.00194719 ;
		ANTENNAPARTIALMETALAREA 0.00195671 ;
	END WEN[43]

	PIN WEN[44]
		USE SIGNAL ;
		DIRECTION INPUT ;
		SHAPE ABUTMENT ;
		PORT
			 LAYER M2 ;
			RECT 0.0714 64.6839 0.1097 64.7216 ;
			 LAYER M3 ;
			RECT 0.0714 64.6839 0.1097 64.7843 ;
			 LAYER V2 ;
			RECT 0.0831 64.6961 0.098 64.7086 ;
		END

		ANTENNAGATEAREA 0.00027817 ;
		ANTENNADIFFAREA 0.00194719 ;
		ANTENNAPARTIALMETALAREA 0.00195671 ;
	END WEN[44]

	PIN WEN[45]
		USE SIGNAL ;
		DIRECTION INPUT ;
		SHAPE ABUTMENT ;
		PORT
			 LAYER M2 ;
			RECT 0.0714 65.9639 0.1097 66.0016 ;
			 LAYER M3 ;
			RECT 0.0714 65.9639 0.1097 66.0643 ;
			 LAYER V2 ;
			RECT 0.0831 65.9761 0.098 65.9886 ;
		END

		ANTENNAGATEAREA 0.00027817 ;
		ANTENNADIFFAREA 0.00194719 ;
		ANTENNAPARTIALMETALAREA 0.00195671 ;
	END WEN[45]

	PIN WEN[46]
		USE SIGNAL ;
		DIRECTION INPUT ;
		SHAPE ABUTMENT ;
		PORT
			 LAYER M2 ;
			RECT 0.0714 67.2439 0.1097 67.2816 ;
			 LAYER M3 ;
			RECT 0.0714 67.2439 0.1097 67.3443 ;
			 LAYER V2 ;
			RECT 0.0831 67.2561 0.098 67.2686 ;
		END

		ANTENNAGATEAREA 0.00027817 ;
		ANTENNADIFFAREA 0.00194719 ;
		ANTENNAPARTIALMETALAREA 0.00195671 ;
	END WEN[46]

	PIN WEN[47]
		USE SIGNAL ;
		DIRECTION INPUT ;
		SHAPE ABUTMENT ;
		PORT
			 LAYER M2 ;
			RECT 0.0714 68.5239 0.1097 68.5616 ;
			 LAYER M3 ;
			RECT 0.0714 68.5239 0.1097 68.6243 ;
			 LAYER V2 ;
			RECT 0.0831 68.5361 0.098 68.5486 ;
		END

		ANTENNAGATEAREA 0.00027817 ;
		ANTENNADIFFAREA 0.00194719 ;
		ANTENNAPARTIALMETALAREA 0.00195671 ;
	END WEN[47]

	PIN WEN[48]
		USE SIGNAL ;
		DIRECTION INPUT ;
		SHAPE ABUTMENT ;
		PORT
			 LAYER M2 ;
			RECT 0.0714 69.8039 0.1097 69.8416 ;
			 LAYER M3 ;
			RECT 0.0714 69.8039 0.1097 69.9043 ;
			 LAYER V2 ;
			RECT 0.0831 69.8161 0.098 69.8286 ;
		END

		ANTENNAGATEAREA 0.00027817 ;
		ANTENNADIFFAREA 0.00194719 ;
		ANTENNAPARTIALMETALAREA 0.00195671 ;
	END WEN[48]

	PIN WEN[49]
		USE SIGNAL ;
		DIRECTION INPUT ;
		SHAPE ABUTMENT ;
		PORT
			 LAYER M2 ;
			RECT 0.0714 71.0839 0.1097 71.1216 ;
			 LAYER M3 ;
			RECT 0.0714 71.0839 0.1097 71.1843 ;
			 LAYER V2 ;
			RECT 0.0831 71.0961 0.098 71.1086 ;
		END

		ANTENNAGATEAREA 0.00027817 ;
		ANTENNADIFFAREA 0.00194719 ;
		ANTENNAPARTIALMETALAREA 0.00195671 ;
	END WEN[49]

	PIN WEN[4]
		USE SIGNAL ;
		DIRECTION INPUT ;
		SHAPE ABUTMENT ;
		PORT
			 LAYER M2 ;
			RECT 0.0714 6.149 0.1097 6.1867 ;
			 LAYER M3 ;
			RECT 0.0714 6.0863 0.1097 6.1867 ;
			 LAYER V2 ;
			RECT 0.0831 6.162 0.098 6.1745 ;
		END

		ANTENNAGATEAREA 0.00027817 ;
		ANTENNADIFFAREA 0.00194719 ;
		ANTENNAPARTIALMETALAREA 0.00195671 ;
	END WEN[4]

	PIN WEN[50]
		USE SIGNAL ;
		DIRECTION INPUT ;
		SHAPE ABUTMENT ;
		PORT
			 LAYER M2 ;
			RECT 0.0714 72.3639 0.1097 72.4016 ;
			 LAYER M3 ;
			RECT 0.0714 72.3639 0.1097 72.4643 ;
			 LAYER V2 ;
			RECT 0.0831 72.3761 0.098 72.3886 ;
		END

		ANTENNAGATEAREA 0.00027817 ;
		ANTENNADIFFAREA 0.00194719 ;
		ANTENNAPARTIALMETALAREA 0.00195671 ;
	END WEN[50]

	PIN WEN[51]
		USE SIGNAL ;
		DIRECTION INPUT ;
		SHAPE ABUTMENT ;
		PORT
			 LAYER M2 ;
			RECT 0.0714 73.6439 0.1097 73.6816 ;
			 LAYER M3 ;
			RECT 0.0714 73.6439 0.1097 73.7443 ;
			 LAYER V2 ;
			RECT 0.0831 73.6561 0.098 73.6686 ;
		END

		ANTENNAGATEAREA 0.00027817 ;
		ANTENNADIFFAREA 0.00194719 ;
		ANTENNAPARTIALMETALAREA 0.00195671 ;
	END WEN[51]

	PIN WEN[52]
		USE SIGNAL ;
		DIRECTION INPUT ;
		SHAPE ABUTMENT ;
		PORT
			 LAYER M2 ;
			RECT 0.0714 74.9239 0.1097 74.9616 ;
			 LAYER M3 ;
			RECT 0.0714 74.9239 0.1097 75.0243 ;
			 LAYER V2 ;
			RECT 0.0831 74.9361 0.098 74.9486 ;
		END

		ANTENNAGATEAREA 0.00027817 ;
		ANTENNADIFFAREA 0.00194719 ;
		ANTENNAPARTIALMETALAREA 0.00195671 ;
	END WEN[52]

	PIN WEN[53]
		USE SIGNAL ;
		DIRECTION INPUT ;
		SHAPE ABUTMENT ;
		PORT
			 LAYER M2 ;
			RECT 0.0714 76.2039 0.1097 76.2416 ;
			 LAYER M3 ;
			RECT 0.0714 76.2039 0.1097 76.3043 ;
			 LAYER V2 ;
			RECT 0.0831 76.2161 0.098 76.2286 ;
		END

		ANTENNAGATEAREA 0.00027817 ;
		ANTENNADIFFAREA 0.00194719 ;
		ANTENNAPARTIALMETALAREA 0.00195671 ;
	END WEN[53]

	PIN WEN[54]
		USE SIGNAL ;
		DIRECTION INPUT ;
		SHAPE ABUTMENT ;
		PORT
			 LAYER M2 ;
			RECT 0.0714 77.4839 0.1097 77.5216 ;
			 LAYER M3 ;
			RECT 0.0714 77.4839 0.1097 77.5843 ;
			 LAYER V2 ;
			RECT 0.0831 77.4961 0.098 77.5086 ;
		END

		ANTENNAGATEAREA 0.00027817 ;
		ANTENNADIFFAREA 0.00194719 ;
		ANTENNAPARTIALMETALAREA 0.00195671 ;
	END WEN[54]

	PIN WEN[55]
		USE SIGNAL ;
		DIRECTION INPUT ;
		SHAPE ABUTMENT ;
		PORT
			 LAYER M2 ;
			RECT 0.0714 78.7639 0.1097 78.8016 ;
			 LAYER M3 ;
			RECT 0.0714 78.7639 0.1097 78.8643 ;
			 LAYER V2 ;
			RECT 0.0831 78.7761 0.098 78.7886 ;
		END

		ANTENNAGATEAREA 0.00027817 ;
		ANTENNADIFFAREA 0.00194719 ;
		ANTENNAPARTIALMETALAREA 0.00195671 ;
	END WEN[55]

	PIN WEN[56]
		USE SIGNAL ;
		DIRECTION INPUT ;
		SHAPE ABUTMENT ;
		PORT
			 LAYER M2 ;
			RECT 0.0714 80.0439 0.1097 80.0816 ;
			 LAYER M3 ;
			RECT 0.0714 80.0439 0.1097 80.1443 ;
			 LAYER V2 ;
			RECT 0.0831 80.0561 0.098 80.0686 ;
		END

		ANTENNAGATEAREA 0.00027817 ;
		ANTENNADIFFAREA 0.00194719 ;
		ANTENNAPARTIALMETALAREA 0.00195671 ;
	END WEN[56]

	PIN WEN[57]
		USE SIGNAL ;
		DIRECTION INPUT ;
		SHAPE ABUTMENT ;
		PORT
			 LAYER M2 ;
			RECT 0.0714 81.3239 0.1097 81.3616 ;
			 LAYER M3 ;
			RECT 0.0714 81.3239 0.1097 81.4243 ;
			 LAYER V2 ;
			RECT 0.0831 81.3361 0.098 81.3486 ;
		END

		ANTENNAGATEAREA 0.00027817 ;
		ANTENNADIFFAREA 0.00194719 ;
		ANTENNAPARTIALMETALAREA 0.00195671 ;
	END WEN[57]

	PIN WEN[58]
		USE SIGNAL ;
		DIRECTION INPUT ;
		SHAPE ABUTMENT ;
		PORT
			 LAYER M2 ;
			RECT 0.0714 82.6039 0.1097 82.6416 ;
			 LAYER M3 ;
			RECT 0.0714 82.6039 0.1097 82.7043 ;
			 LAYER V2 ;
			RECT 0.0831 82.6161 0.098 82.6286 ;
		END

		ANTENNAGATEAREA 0.00027817 ;
		ANTENNADIFFAREA 0.00194719 ;
		ANTENNAPARTIALMETALAREA 0.00195671 ;
	END WEN[58]

	PIN WEN[59]
		USE SIGNAL ;
		DIRECTION INPUT ;
		SHAPE ABUTMENT ;
		PORT
			 LAYER M2 ;
			RECT 0.0714 83.8839 0.1097 83.9216 ;
			 LAYER M3 ;
			RECT 0.0714 83.8839 0.1097 83.9843 ;
			 LAYER V2 ;
			RECT 0.0831 83.8961 0.098 83.9086 ;
		END

		ANTENNAGATEAREA 0.00027817 ;
		ANTENNADIFFAREA 0.00194719 ;
		ANTENNAPARTIALMETALAREA 0.00195671 ;
	END WEN[59]

	PIN WEN[5]
		USE SIGNAL ;
		DIRECTION INPUT ;
		SHAPE ABUTMENT ;
		PORT
			 LAYER M2 ;
			RECT 0.0714 7.429 0.1097 7.4667 ;
			 LAYER M3 ;
			RECT 0.0714 7.3663 0.1097 7.4667 ;
			 LAYER V2 ;
			RECT 0.0831 7.442 0.098 7.4545 ;
		END

		ANTENNAGATEAREA 0.00027817 ;
		ANTENNADIFFAREA 0.00194719 ;
		ANTENNAPARTIALMETALAREA 0.00195671 ;
	END WEN[5]

	PIN WEN[60]
		USE SIGNAL ;
		DIRECTION INPUT ;
		SHAPE ABUTMENT ;
		PORT
			 LAYER M2 ;
			RECT 0.0714 85.1639 0.1097 85.2016 ;
			 LAYER M3 ;
			RECT 0.0714 85.1639 0.1097 85.2643 ;
			 LAYER V2 ;
			RECT 0.0831 85.1761 0.098 85.1886 ;
		END

		ANTENNAGATEAREA 0.00027817 ;
		ANTENNADIFFAREA 0.00194719 ;
		ANTENNAPARTIALMETALAREA 0.00195671 ;
	END WEN[60]

	PIN WEN[61]
		USE SIGNAL ;
		DIRECTION INPUT ;
		SHAPE ABUTMENT ;
		PORT
			 LAYER M2 ;
			RECT 0.0714 86.4439 0.1097 86.4816 ;
			 LAYER M3 ;
			RECT 0.0714 86.4439 0.1097 86.5443 ;
			 LAYER V2 ;
			RECT 0.0831 86.4561 0.098 86.4686 ;
		END

		ANTENNAGATEAREA 0.00027817 ;
		ANTENNADIFFAREA 0.00194719 ;
		ANTENNAPARTIALMETALAREA 0.00195671 ;
	END WEN[61]

	PIN WEN[62]
		USE SIGNAL ;
		DIRECTION INPUT ;
		SHAPE ABUTMENT ;
		PORT
			 LAYER M2 ;
			RECT 0.0714 87.7239 0.1097 87.7616 ;
			 LAYER M3 ;
			RECT 0.0714 87.7239 0.1097 87.8243 ;
			 LAYER V2 ;
			RECT 0.0831 87.7361 0.098 87.7486 ;
		END

		ANTENNAGATEAREA 0.00027817 ;
		ANTENNADIFFAREA 0.00194719 ;
		ANTENNAPARTIALMETALAREA 0.00195671 ;
	END WEN[62]

	PIN WEN[63]
		USE SIGNAL ;
		DIRECTION INPUT ;
		SHAPE ABUTMENT ;
		PORT
			 LAYER M2 ;
			RECT 0.0714 89.0039 0.1097 89.0416 ;
			 LAYER M3 ;
			RECT 0.0714 89.0039 0.1097 89.1043 ;
			 LAYER V2 ;
			RECT 0.0831 89.0161 0.098 89.0286 ;
		END

		ANTENNAGATEAREA 0.00027817 ;
		ANTENNADIFFAREA 0.00194719 ;
		ANTENNAPARTIALMETALAREA 0.00195671 ;
	END WEN[63]

	PIN WEN[6]
		USE SIGNAL ;
		DIRECTION INPUT ;
		SHAPE ABUTMENT ;
		PORT
			 LAYER M2 ;
			RECT 0.0714 8.709 0.1097 8.7467 ;
			 LAYER M3 ;
			RECT 0.0714 8.6463 0.1097 8.7467 ;
			 LAYER V2 ;
			RECT 0.0831 8.722 0.098 8.7345 ;
		END

		ANTENNAGATEAREA 0.00027817 ;
		ANTENNADIFFAREA 0.00194719 ;
		ANTENNAPARTIALMETALAREA 0.00195671 ;
	END WEN[6]

	PIN WEN[7]
		USE SIGNAL ;
		DIRECTION INPUT ;
		SHAPE ABUTMENT ;
		PORT
			 LAYER M2 ;
			RECT 0.0714 9.989 0.1097 10.0267 ;
			 LAYER M3 ;
			RECT 0.0714 9.9263 0.1097 10.0267 ;
			 LAYER V2 ;
			RECT 0.0831 10.002 0.098 10.0145 ;
		END

		ANTENNAGATEAREA 0.00027817 ;
		ANTENNADIFFAREA 0.00194719 ;
		ANTENNAPARTIALMETALAREA 0.00195671 ;
	END WEN[7]

	PIN WEN[8]
		USE SIGNAL ;
		DIRECTION INPUT ;
		SHAPE ABUTMENT ;
		PORT
			 LAYER M2 ;
			RECT 0.0714 11.269 0.1097 11.3067 ;
			 LAYER M3 ;
			RECT 0.0714 11.2063 0.1097 11.3067 ;
			 LAYER V2 ;
			RECT 0.0831 11.282 0.098 11.2945 ;
		END

		ANTENNAGATEAREA 0.00027817 ;
		ANTENNADIFFAREA 0.00194719 ;
		ANTENNAPARTIALMETALAREA 0.00195671 ;
	END WEN[8]

	PIN WEN[9]
		USE SIGNAL ;
		DIRECTION INPUT ;
		SHAPE ABUTMENT ;
		PORT
			 LAYER M2 ;
			RECT 0.0714 12.549 0.1097 12.5867 ;
			 LAYER M3 ;
			RECT 0.0714 12.4863 0.1097 12.5867 ;
			 LAYER V2 ;
			RECT 0.0831 12.562 0.098 12.5745 ;
		END

		ANTENNAGATEAREA 0.00027817 ;
		ANTENNADIFFAREA 0.00194719 ;
		ANTENNAPARTIALMETALAREA 0.00195671 ;
	END WEN[9]

	OBS
		 LAYER M1 SPACING 0.012 ;
		RECT 0 0 62.601 90.0706 ;
		 LAYER M2 SPACING 0.012 ;
		RECT 0.133 0 62.601 90.0706 ;
		RECT 0 0 0.133 0.0439 ;
		RECT 0 0.182 0.133 0.9475 ;
		RECT 0.0714 1.0918 0.133 1.2235 ;
		RECT 0 1.211 0.133 1.2235 ;
		RECT 0.0714 1.2235 0.133 1.349 ;
		RECT 0 1.4871 0.133 2.2275 ;
		RECT 0.0714 2.3718 0.133 2.5035 ;
		RECT 0 2.491 0.133 2.5035 ;
		RECT 0.0714 2.5035 0.133 2.629 ;
		RECT 0 2.7671 0.133 3.5075 ;
		RECT 0.0714 3.6518 0.133 3.7835 ;
		RECT 0 3.771 0.133 3.7835 ;
		RECT 0.0714 3.7835 0.133 3.909 ;
		RECT 0 4.0471 0.133 4.7875 ;
		RECT 0.0714 4.9318 0.133 5.0635 ;
		RECT 0 5.051 0.133 5.0635 ;
		RECT 0.0714 5.0635 0.133 5.189 ;
		RECT 0 5.3271 0.133 6.0675 ;
		RECT 0.0714 6.2118 0.133 6.3435 ;
		RECT 0 6.331 0.133 6.3435 ;
		RECT 0.0714 6.3435 0.133 6.469 ;
		RECT 0 6.6071 0.133 7.3475 ;
		RECT 0.0714 7.4918 0.133 7.6235 ;
		RECT 0 7.611 0.133 7.6235 ;
		RECT 0.0714 7.6235 0.133 7.749 ;
		RECT 0 7.8871 0.133 8.6275 ;
		RECT 0.0714 8.7718 0.133 8.9035 ;
		RECT 0 8.891 0.133 8.9035 ;
		RECT 0.0714 8.9035 0.133 9.029 ;
		RECT 0 9.1671 0.133 9.9075 ;
		RECT 0.0714 10.0518 0.133 10.1835 ;
		RECT 0 10.171 0.133 10.1835 ;
		RECT 0.0714 10.1835 0.133 10.309 ;
		RECT 0 10.4471 0.133 11.1875 ;
		RECT 0.0714 11.3318 0.133 11.4635 ;
		RECT 0 11.451 0.133 11.4635 ;
		RECT 0.0714 11.4635 0.133 11.589 ;
		RECT 0 11.7271 0.133 12.4675 ;
		RECT 0.0714 12.6118 0.133 12.7435 ;
		RECT 0 12.731 0.133 12.7435 ;
		RECT 0.0714 12.7435 0.133 12.869 ;
		RECT 0 13.0071 0.133 13.7475 ;
		RECT 0.0714 13.8918 0.133 14.0235 ;
		RECT 0 14.011 0.133 14.0235 ;
		RECT 0.0714 14.0235 0.133 14.149 ;
		RECT 0 14.2871 0.133 15.0275 ;
		RECT 0.0714 15.1718 0.133 15.3035 ;
		RECT 0 15.291 0.133 15.3035 ;
		RECT 0.0714 15.3035 0.133 15.429 ;
		RECT 0 15.5671 0.133 16.3075 ;
		RECT 0.0714 16.4518 0.133 16.5835 ;
		RECT 0 16.571 0.133 16.5835 ;
		RECT 0.0714 16.5835 0.133 16.709 ;
		RECT 0 16.8471 0.133 17.5875 ;
		RECT 0.0714 17.7318 0.133 17.8635 ;
		RECT 0 17.851 0.133 17.8635 ;
		RECT 0.0714 17.8635 0.133 17.989 ;
		RECT 0 18.1271 0.133 18.8675 ;
		RECT 0.0714 19.0118 0.133 19.1435 ;
		RECT 0 19.131 0.133 19.1435 ;
		RECT 0.0714 19.1435 0.133 19.269 ;
		RECT 0 19.4071 0.133 20.1475 ;
		RECT 0.0714 20.2918 0.133 20.4235 ;
		RECT 0 20.411 0.133 20.4235 ;
		RECT 0.0714 20.4235 0.133 20.549 ;
		RECT 0 20.6871 0.133 21.4275 ;
		RECT 0.0714 21.5718 0.133 21.7035 ;
		RECT 0 21.691 0.133 21.7035 ;
		RECT 0.0714 21.7035 0.133 21.829 ;
		RECT 0 21.9671 0.133 22.7075 ;
		RECT 0.0714 22.8518 0.133 22.9835 ;
		RECT 0 22.971 0.133 22.9835 ;
		RECT 0.0714 22.9835 0.133 23.109 ;
		RECT 0 23.2471 0.133 23.9875 ;
		RECT 0.0714 24.1318 0.133 24.2635 ;
		RECT 0 24.251 0.133 24.2635 ;
		RECT 0.0714 24.2635 0.133 24.389 ;
		RECT 0 24.5271 0.133 25.2675 ;
		RECT 0.0714 25.4118 0.133 25.5435 ;
		RECT 0 25.531 0.133 25.5435 ;
		RECT 0.0714 25.5435 0.133 25.669 ;
		RECT 0 25.8071 0.133 26.5475 ;
		RECT 0.0714 26.6918 0.133 26.8235 ;
		RECT 0 26.811 0.133 26.8235 ;
		RECT 0.0714 26.8235 0.133 26.949 ;
		RECT 0 27.0871 0.133 27.8275 ;
		RECT 0.0714 27.9718 0.133 28.1035 ;
		RECT 0 28.091 0.133 28.1035 ;
		RECT 0.0714 28.1035 0.133 28.229 ;
		RECT 0 28.3671 0.133 29.1075 ;
		RECT 0.0714 29.2518 0.133 29.3835 ;
		RECT 0 29.371 0.133 29.3835 ;
		RECT 0.0714 29.3835 0.133 29.509 ;
		RECT 0 29.6471 0.133 30.3875 ;
		RECT 0.0714 30.5318 0.133 30.6635 ;
		RECT 0 30.651 0.133 30.6635 ;
		RECT 0.0714 30.6635 0.133 30.789 ;
		RECT 0 30.9271 0.133 31.6675 ;
		RECT 0.0714 31.8118 0.133 31.9435 ;
		RECT 0 31.931 0.133 31.9435 ;
		RECT 0.0714 31.9435 0.133 32.069 ;
		RECT 0 32.2071 0.133 32.9475 ;
		RECT 0.0714 33.0918 0.133 33.2235 ;
		RECT 0 33.211 0.133 33.2235 ;
		RECT 0.0714 33.2235 0.133 33.349 ;
		RECT 0 33.4871 0.133 34.2275 ;
		RECT 0.0714 34.3718 0.133 34.5035 ;
		RECT 0 34.491 0.133 34.5035 ;
		RECT 0.0714 34.5035 0.133 34.629 ;
		RECT 0 34.7671 0.133 35.5075 ;
		RECT 0.0714 35.6518 0.133 35.7835 ;
		RECT 0 35.771 0.133 35.7835 ;
		RECT 0.0714 35.7835 0.133 35.909 ;
		RECT 0 36.0471 0.133 36.7875 ;
		RECT 0.0714 36.9318 0.133 37.0635 ;
		RECT 0 37.051 0.133 37.0635 ;
		RECT 0.0714 37.0635 0.133 37.189 ;
		RECT 0 37.3271 0.133 38.0675 ;
		RECT 0.0714 38.2118 0.133 38.3435 ;
		RECT 0 38.331 0.133 38.3435 ;
		RECT 0.0714 38.3435 0.133 38.469 ;
		RECT 0 38.6071 0.133 39.3475 ;
		RECT 0.0714 39.4918 0.133 39.6235 ;
		RECT 0 39.611 0.133 39.6235 ;
		RECT 0.0714 39.6235 0.133 39.749 ;
		RECT 0 39.8871 0.133 40.6275 ;
		RECT 0.0714 40.7718 0.133 40.9035 ;
		RECT 0 40.891 0.133 40.9035 ;
		RECT 0.0714 40.9035 0.133 41.029 ;
		RECT 0 41.1671 0.133 41.4808 ;
		RECT 0 41.6188 0.133 41.6314 ;
		RECT 0 41.7694 0.133 42.0831 ;
		RECT 0 42.2212 0.133 42.2337 ;
		RECT 0 42.3718 0.133 42.3843 ;
		RECT 0 42.5224 0.133 42.6855 ;
		RECT 0 42.8235 0.133 42.9867 ;
		RECT 0 43.1247 0.133 43.1373 ;
		RECT 0 43.2753 0.133 43.2878 ;
		RECT 0 43.4259 0.133 43.4384 ;
		RECT 0 43.5765 0.133 43.589 ;
		RECT 0 43.7271 0.133 43.7396 ;
		RECT 0 43.8776 0.133 43.8902 ;
		RECT 0 44.0282 0.133 44.0408 ;
		RECT 0 44.1788 0.133 44.1914 ;
		RECT 0 44.3294 0.133 44.342 ;
		RECT 0 44.48 0.133 44.4925 ;
		RECT 0 44.6306 0.133 44.6431 ;
		RECT 0 44.7812 0.133 44.7937 ;
		RECT 0 44.9318 0.133 44.9443 ;
		RECT 0 45.0824 0.133 45.0949 ;
		RECT 0 45.2329 0.133 45.2455 ;
		RECT 0 45.3835 0.133 45.3961 ;
		RECT 0 45.5341 0.133 45.5467 ;
		RECT 0 45.6847 0.133 45.6973 ;
		RECT 0 45.8353 0.133 45.8478 ;
		RECT 0 45.9859 0.133 45.9984 ;
		RECT 0 46.1365 0.133 46.149 ;
		RECT 0 46.2871 0.133 46.2996 ;
		RECT 0 46.4376 0.133 46.4502 ;
		RECT 0 46.5882 0.133 46.7514 ;
		RECT 0 46.8894 0.133 46.902 ;
		RECT 0 47.04 0.133 47.0525 ;
		RECT 0 47.1906 0.133 47.2031 ;
		RECT 0 47.3412 0.133 47.3537 ;
		RECT 0 47.4918 0.133 47.8055 ;
		RECT 0 47.9435 0.133 47.9561 ;
		RECT 0 48.0941 0.133 48.5584 ;
		RECT 0 48.6965 0.133 48.9035 ;
		RECT 0.0714 49.0478 0.133 49.1796 ;
		RECT 0 49.1671 0.133 49.1796 ;
		RECT 0.0714 49.1796 0.133 49.3051 ;
		RECT 0 49.4431 0.133 50.1835 ;
		RECT 0.0714 50.3278 0.133 50.4596 ;
		RECT 0 50.4471 0.133 50.4596 ;
		RECT 0.0714 50.4596 0.133 50.5851 ;
		RECT 0 50.7231 0.133 51.4635 ;
		RECT 0.0714 51.6078 0.133 51.7396 ;
		RECT 0 51.7271 0.133 51.7396 ;
		RECT 0.0714 51.7396 0.133 51.8651 ;
		RECT 0 52.0031 0.133 52.7435 ;
		RECT 0.0714 52.8878 0.133 53.0196 ;
		RECT 0 53.0071 0.133 53.0196 ;
		RECT 0.0714 53.0196 0.133 53.1451 ;
		RECT 0 53.2831 0.133 54.0235 ;
		RECT 0.0714 54.1678 0.133 54.2996 ;
		RECT 0 54.2871 0.133 54.2996 ;
		RECT 0.0714 54.2996 0.133 54.4251 ;
		RECT 0 54.5631 0.133 55.3035 ;
		RECT 0.0714 55.4478 0.133 55.5796 ;
		RECT 0 55.5671 0.133 55.5796 ;
		RECT 0.0714 55.5796 0.133 55.7051 ;
		RECT 0 55.8431 0.133 56.5835 ;
		RECT 0.0714 56.7278 0.133 56.8596 ;
		RECT 0 56.8471 0.133 56.8596 ;
		RECT 0.0714 56.8596 0.133 56.9851 ;
		RECT 0 57.1231 0.133 57.8635 ;
		RECT 0.0714 58.0078 0.133 58.1396 ;
		RECT 0 58.1271 0.133 58.1396 ;
		RECT 0.0714 58.1396 0.133 58.2651 ;
		RECT 0 58.4031 0.133 59.1435 ;
		RECT 0.0714 59.2878 0.133 59.4196 ;
		RECT 0 59.4071 0.133 59.4196 ;
		RECT 0.0714 59.4196 0.133 59.5451 ;
		RECT 0 59.6831 0.133 60.4235 ;
		RECT 0.0714 60.5678 0.133 60.6996 ;
		RECT 0 60.6871 0.133 60.6996 ;
		RECT 0.0714 60.6996 0.133 60.8251 ;
		RECT 0 60.9631 0.133 61.7035 ;
		RECT 0.0714 61.8478 0.133 61.9796 ;
		RECT 0 61.9671 0.133 61.9796 ;
		RECT 0.0714 61.9796 0.133 62.1051 ;
		RECT 0 62.2431 0.133 62.9835 ;
		RECT 0.0714 63.1278 0.133 63.2596 ;
		RECT 0 63.2471 0.133 63.2596 ;
		RECT 0.0714 63.2596 0.133 63.3851 ;
		RECT 0 63.5231 0.133 64.2635 ;
		RECT 0.0714 64.4078 0.133 64.5396 ;
		RECT 0 64.5271 0.133 64.5396 ;
		RECT 0.0714 64.5396 0.133 64.6651 ;
		RECT 0 64.8031 0.133 65.5435 ;
		RECT 0.0714 65.6878 0.133 65.8196 ;
		RECT 0 65.8071 0.133 65.8196 ;
		RECT 0.0714 65.8196 0.133 65.9451 ;
		RECT 0 66.0831 0.133 66.8235 ;
		RECT 0.0714 66.9678 0.133 67.0996 ;
		RECT 0 67.0871 0.133 67.0996 ;
		RECT 0.0714 67.0996 0.133 67.2251 ;
		RECT 0 67.3631 0.133 68.1035 ;
		RECT 0.0714 68.2478 0.133 68.3796 ;
		RECT 0 68.3671 0.133 68.3796 ;
		RECT 0.0714 68.3796 0.133 68.5051 ;
		RECT 0 68.6431 0.133 69.3835 ;
		RECT 0.0714 69.5278 0.133 69.6596 ;
		RECT 0 69.6471 0.133 69.6596 ;
		RECT 0.0714 69.6596 0.133 69.7851 ;
		RECT 0 69.9231 0.133 70.6635 ;
		RECT 0.0714 70.8078 0.133 70.9396 ;
		RECT 0 70.9271 0.133 70.9396 ;
		RECT 0.0714 70.9396 0.133 71.0651 ;
		RECT 0 71.2031 0.133 71.9435 ;
		RECT 0.0714 72.0878 0.133 72.2196 ;
		RECT 0 72.2071 0.133 72.2196 ;
		RECT 0.0714 72.2196 0.133 72.3451 ;
		RECT 0 72.4831 0.133 73.2235 ;
		RECT 0.0714 73.3678 0.133 73.4996 ;
		RECT 0 73.4871 0.133 73.4996 ;
		RECT 0.0714 73.4996 0.133 73.6251 ;
		RECT 0 73.7631 0.133 74.5035 ;
		RECT 0.0714 74.6478 0.133 74.7796 ;
		RECT 0 74.7671 0.133 74.7796 ;
		RECT 0.0714 74.7796 0.133 74.9051 ;
		RECT 0 75.0431 0.133 75.7835 ;
		RECT 0.0714 75.9278 0.133 76.0596 ;
		RECT 0 76.0471 0.133 76.0596 ;
		RECT 0.0714 76.0596 0.133 76.1851 ;
		RECT 0 76.3231 0.133 77.0635 ;
		RECT 0.0714 77.2078 0.133 77.3396 ;
		RECT 0 77.3271 0.133 77.3396 ;
		RECT 0.0714 77.3396 0.133 77.4651 ;
		RECT 0 77.6031 0.133 78.3435 ;
		RECT 0.0714 78.4878 0.133 78.6196 ;
		RECT 0 78.6071 0.133 78.6196 ;
		RECT 0.0714 78.6196 0.133 78.7451 ;
		RECT 0 78.8831 0.133 79.6235 ;
		RECT 0.0714 79.7678 0.133 79.8996 ;
		RECT 0 79.8871 0.133 79.8996 ;
		RECT 0.0714 79.8996 0.133 80.0251 ;
		RECT 0 80.1631 0.133 80.9035 ;
		RECT 0.0714 81.0478 0.133 81.1796 ;
		RECT 0 81.1671 0.133 81.1796 ;
		RECT 0.0714 81.1796 0.133 81.3051 ;
		RECT 0 81.4431 0.133 82.1835 ;
		RECT 0.0714 82.3278 0.133 82.4596 ;
		RECT 0 82.4471 0.133 82.4596 ;
		RECT 0.0714 82.4596 0.133 82.5851 ;
		RECT 0 82.7231 0.133 83.4635 ;
		RECT 0.0714 83.6078 0.133 83.7396 ;
		RECT 0 83.7271 0.133 83.7396 ;
		RECT 0.0714 83.7396 0.133 83.8651 ;
		RECT 0 84.0031 0.133 84.7435 ;
		RECT 0.0714 84.8878 0.133 85.0196 ;
		RECT 0 85.0071 0.133 85.0196 ;
		RECT 0.0714 85.0196 0.133 85.1451 ;
		RECT 0 85.2831 0.133 86.0235 ;
		RECT 0.0714 86.1678 0.133 86.2996 ;
		RECT 0 86.2871 0.133 86.2996 ;
		RECT 0.0714 86.2996 0.133 86.4251 ;
		RECT 0 86.5631 0.133 87.3035 ;
		RECT 0.0714 87.4478 0.133 87.5796 ;
		RECT 0 87.5671 0.133 87.5796 ;
		RECT 0.0714 87.5796 0.133 87.7051 ;
		RECT 0 87.8431 0.133 88.5835 ;
		RECT 0.0714 88.7278 0.133 88.8596 ;
		RECT 0 88.8471 0.133 88.8596 ;
		RECT 0.0714 88.8596 0.133 88.9851 ;
		RECT 0 89.1231 0.133 89.8886 ;
		RECT 0 90.0267 0.133 90.0706 ;
		 LAYER M2 ;
		RECT 0.0714 44.0596 0.1097 44.16 ;
		RECT 0.0714 45.4149 0.1097 45.5153 ;
		RECT 0.0714 46.0173 0.1097 46.1176 ;
		RECT 0.0714 46.3184 0.1097 46.4188 ;
		RECT 0.0714 46.469 0.1097 46.5694 ;
		RECT 0.0714 47.0714 0.1097 47.1718 ;
		RECT 0.0714 41.1984 0.1097 41.2361 ;
		RECT 0.0098 41.2612 0.0481 41.2988 ;
		RECT 0.0098 42.3153 0.0481 42.3529 ;
		RECT 0.0714 42.5537 0.1097 42.5914 ;
		RECT 0.0098 42.6165 0.0481 42.6541 ;
		RECT 0.0714 42.7043 0.1097 42.742 ;
		RECT 0.0098 42.8549 0.0481 42.9553 ;
		RECT 0.0714 43.4573 0.1097 43.4949 ;
		RECT 0.0098 43.9718 0.0481 44.0094 ;
		RECT 0.0098 44.0596 0.0481 44.0973 ;
		RECT 0.0714 44.2102 0.1097 44.2478 ;
		RECT 0.0714 45.1137 0.1097 45.1514 ;
		RECT 0.0714 41.349 0.1097 41.3867 ;
		RECT 0.0098 45.3271 0.0481 45.3647 ;
		RECT 0.0098 45.4776 0.0481 45.5153 ;
		RECT 0.0714 45.5655 0.1097 45.6031 ;
		RECT 0.0714 45.8667 0.1097 45.9043 ;
		RECT 0.0098 46.08 0.0481 46.1176 ;
		RECT 0.0098 46.2306 0.0481 46.2682 ;
		RECT 0.0098 46.3184 0.0481 46.3561 ;
		RECT 0.0098 46.6196 0.0481 46.6573 ;
		RECT 0.0714 46.6824 0.1097 46.72 ;
		RECT 0.0714 47.5231 0.1097 47.5608 ;
		RECT 0.0098 41.4118 0.0481 41.4494 ;
		RECT 0.0098 47.5859 0.0481 47.6235 ;
		RECT 0.0098 47.6737 0.0481 47.7741 ;
		RECT 0.0714 48.1255 0.1097 48.1631 ;
		RECT 0.0098 48.1882 0.0481 48.2259 ;
		RECT 0.0098 48.2761 0.0481 48.3765 ;
		RECT 0.0714 48.4267 0.1097 48.4643 ;
		RECT 0.0098 48.4894 0.0481 48.5271 ;
		RECT 0.0714 48.5773 0.1097 48.6149 ;
		RECT 0.0098 48.7278 0.0481 48.8282 ;
		RECT 0.0098 0.1255 0.0481 0.1631 ;
		RECT 0.0098 41.5624 0.0481 41.6 ;
		RECT 0.0098 89.9075 0.0481 89.9451 ;
		RECT 0.0098 41.7129 0.0481 41.7506 ;
		RECT 0.0098 41.8008 0.0481 41.9012 ;
		RECT 0.0714 41.9514 0.1097 41.989 ;
		RECT 0.0098 42.0141 0.0481 42.0518 ;
		RECT 0.0714 42.102 0.1097 42.1396 ;
		 LAYER M2 SPACING 0.012 ;
		RECT 0.0714 44.0596 0.1097 44.16 ;
		RECT 0.0714 45.4149 0.1097 45.5153 ;
		RECT 0.0714 46.0173 0.1097 46.1176 ;
		RECT 0.0714 46.3184 0.1097 46.4188 ;
		RECT 0.0714 46.469 0.1097 46.5694 ;
		RECT 0.0714 47.0714 0.1097 47.1718 ;
		RECT 0.0714 41.1984 0.1097 41.2361 ;
		RECT 0.0098 41.2612 0.0481 41.2988 ;
		RECT 0.0098 42.3153 0.0481 42.3529 ;
		RECT 0.0714 42.5537 0.1097 42.5914 ;
		RECT 0.0098 42.6165 0.0481 42.6541 ;
		RECT 0.0714 42.7043 0.1097 42.742 ;
		RECT 0.0098 42.8549 0.0481 42.9553 ;
		RECT 0.0714 43.4573 0.1097 43.4949 ;
		RECT 0.0098 43.9718 0.0481 44.0094 ;
		RECT 0.0098 44.0596 0.0481 44.0973 ;
		RECT 0.0714 44.2102 0.1097 44.2478 ;
		RECT 0.0714 45.1137 0.1097 45.1514 ;
		RECT 0.0714 41.349 0.1097 41.3867 ;
		RECT 0.0098 45.3271 0.0481 45.3647 ;
		RECT 0.0098 45.4776 0.0481 45.5153 ;
		RECT 0.0714 45.5655 0.1097 45.6031 ;
		RECT 0.0714 45.8667 0.1097 45.9043 ;
		RECT 0.0098 46.08 0.0481 46.1176 ;
		RECT 0.0098 46.2306 0.0481 46.2682 ;
		RECT 0.0098 46.3184 0.0481 46.3561 ;
		RECT 0.0098 46.6196 0.0481 46.6573 ;
		RECT 0.0714 46.6824 0.1097 46.72 ;
		RECT 0.0714 47.5231 0.1097 47.5608 ;
		RECT 0.0098 41.4118 0.0481 41.4494 ;
		RECT 0.0098 47.5859 0.0481 47.6235 ;
		RECT 0.0098 47.6737 0.0481 47.7741 ;
		RECT 0.0714 48.1255 0.1097 48.1631 ;
		RECT 0.0098 48.1882 0.0481 48.2259 ;
		RECT 0.0098 48.2761 0.0481 48.3765 ;
		RECT 0.0714 48.4267 0.1097 48.4643 ;
		RECT 0.0098 48.4894 0.0481 48.5271 ;
		RECT 0.0714 48.5773 0.1097 48.6149 ;
		RECT 0.0098 48.7278 0.0481 48.8282 ;
		RECT 0.0098 0.1255 0.0481 0.1631 ;
		RECT 0.0098 41.5624 0.0481 41.6 ;
		RECT 0.0098 89.9075 0.0481 89.9451 ;
		RECT 0.0098 41.7129 0.0481 41.7506 ;
		RECT 0.0098 41.8008 0.0481 41.9012 ;
		RECT 0.0714 41.9514 0.1097 41.989 ;
		RECT 0.0098 42.0141 0.0481 42.0518 ;
		RECT 0.0714 42.102 0.1097 42.1396 ;
		 LAYER M3 SPACING 0.012 ;
		RECT 0.133 0 62.601 90.0706 ;
		RECT 0 0 0.133 0.0439 ;
		RECT 0 0.182 0.133 0.9475 ;
		RECT 0.0714 1.0918 0.133 1.2235 ;
		RECT 0 1.211 0.133 1.2235 ;
		RECT 0.0714 1.2235 0.133 1.349 ;
		RECT 0 1.4871 0.133 2.2275 ;
		RECT 0.0714 2.3718 0.133 2.5035 ;
		RECT 0 2.491 0.133 2.5035 ;
		RECT 0.0714 2.5035 0.133 2.629 ;
		RECT 0 2.7671 0.133 3.5075 ;
		RECT 0.0714 3.6518 0.133 3.7835 ;
		RECT 0 3.771 0.133 3.7835 ;
		RECT 0.0714 3.7835 0.133 3.909 ;
		RECT 0 4.0471 0.133 4.7875 ;
		RECT 0.0714 4.9318 0.133 5.0635 ;
		RECT 0 5.051 0.133 5.0635 ;
		RECT 0.0714 5.0635 0.133 5.189 ;
		RECT 0 5.3271 0.133 6.0675 ;
		RECT 0.0714 6.2118 0.133 6.3435 ;
		RECT 0 6.331 0.133 6.3435 ;
		RECT 0.0714 6.3435 0.133 6.469 ;
		RECT 0 6.6071 0.133 7.3475 ;
		RECT 0.0714 7.4918 0.133 7.6235 ;
		RECT 0 7.611 0.133 7.6235 ;
		RECT 0.0714 7.6235 0.133 7.749 ;
		RECT 0 7.8871 0.133 8.6275 ;
		RECT 0.0714 8.7718 0.133 8.9035 ;
		RECT 0 8.891 0.133 8.9035 ;
		RECT 0.0714 8.9035 0.133 9.029 ;
		RECT 0 9.1671 0.133 9.9075 ;
		RECT 0.0714 10.0518 0.133 10.1835 ;
		RECT 0 10.171 0.133 10.1835 ;
		RECT 0.0714 10.1835 0.133 10.309 ;
		RECT 0 10.4471 0.133 11.1875 ;
		RECT 0.0714 11.3318 0.133 11.4635 ;
		RECT 0 11.451 0.133 11.4635 ;
		RECT 0.0714 11.4635 0.133 11.589 ;
		RECT 0 11.7271 0.133 12.4675 ;
		RECT 0.0714 12.6118 0.133 12.7435 ;
		RECT 0 12.731 0.133 12.7435 ;
		RECT 0.0714 12.7435 0.133 12.869 ;
		RECT 0 13.0071 0.133 13.7475 ;
		RECT 0.0714 13.8918 0.133 14.0235 ;
		RECT 0 14.011 0.133 14.0235 ;
		RECT 0.0714 14.0235 0.133 14.149 ;
		RECT 0 14.2871 0.133 15.0275 ;
		RECT 0.0714 15.1718 0.133 15.3035 ;
		RECT 0 15.291 0.133 15.3035 ;
		RECT 0.0714 15.3035 0.133 15.429 ;
		RECT 0 15.5671 0.133 16.3075 ;
		RECT 0.0714 16.4518 0.133 16.5835 ;
		RECT 0 16.571 0.133 16.5835 ;
		RECT 0.0714 16.5835 0.133 16.709 ;
		RECT 0 16.8471 0.133 17.5875 ;
		RECT 0.0714 17.7318 0.133 17.8635 ;
		RECT 0 17.851 0.133 17.8635 ;
		RECT 0.0714 17.8635 0.133 17.989 ;
		RECT 0 18.1271 0.133 18.8675 ;
		RECT 0.0714 19.0118 0.133 19.1435 ;
		RECT 0 19.131 0.133 19.1435 ;
		RECT 0.0714 19.1435 0.133 19.269 ;
		RECT 0 19.4071 0.133 20.1475 ;
		RECT 0.0714 20.2918 0.133 20.4235 ;
		RECT 0 20.411 0.133 20.4235 ;
		RECT 0.0714 20.4235 0.133 20.549 ;
		RECT 0 20.6871 0.133 21.4275 ;
		RECT 0.0714 21.5718 0.133 21.7035 ;
		RECT 0 21.691 0.133 21.7035 ;
		RECT 0.0714 21.7035 0.133 21.829 ;
		RECT 0 21.9671 0.133 22.7075 ;
		RECT 0.0714 22.8518 0.133 22.9835 ;
		RECT 0 22.971 0.133 22.9835 ;
		RECT 0.0714 22.9835 0.133 23.109 ;
		RECT 0 23.2471 0.133 23.9875 ;
		RECT 0.0714 24.1318 0.133 24.2635 ;
		RECT 0 24.251 0.133 24.2635 ;
		RECT 0.0714 24.2635 0.133 24.389 ;
		RECT 0 24.5271 0.133 25.2675 ;
		RECT 0.0714 25.4118 0.133 25.5435 ;
		RECT 0 25.531 0.133 25.5435 ;
		RECT 0.0714 25.5435 0.133 25.669 ;
		RECT 0 25.8071 0.133 26.5475 ;
		RECT 0.0714 26.6918 0.133 26.8235 ;
		RECT 0 26.811 0.133 26.8235 ;
		RECT 0.0714 26.8235 0.133 26.949 ;
		RECT 0 27.0871 0.133 27.8275 ;
		RECT 0.0714 27.9718 0.133 28.1035 ;
		RECT 0 28.091 0.133 28.1035 ;
		RECT 0.0714 28.1035 0.133 28.229 ;
		RECT 0 28.3671 0.133 29.1075 ;
		RECT 0.0714 29.2518 0.133 29.3835 ;
		RECT 0 29.371 0.133 29.3835 ;
		RECT 0.0714 29.3835 0.133 29.509 ;
		RECT 0 29.6471 0.133 30.3875 ;
		RECT 0.0714 30.5318 0.133 30.6635 ;
		RECT 0 30.651 0.133 30.6635 ;
		RECT 0.0714 30.6635 0.133 30.789 ;
		RECT 0 30.9271 0.133 31.6675 ;
		RECT 0.0714 31.8118 0.133 31.9435 ;
		RECT 0 31.931 0.133 31.9435 ;
		RECT 0.0714 31.9435 0.133 32.069 ;
		RECT 0 32.2071 0.133 32.9475 ;
		RECT 0.0714 33.0918 0.133 33.2235 ;
		RECT 0 33.211 0.133 33.2235 ;
		RECT 0.0714 33.2235 0.133 33.349 ;
		RECT 0 33.4871 0.133 34.2275 ;
		RECT 0.0714 34.3718 0.133 34.5035 ;
		RECT 0 34.491 0.133 34.5035 ;
		RECT 0.0714 34.5035 0.133 34.629 ;
		RECT 0 34.7671 0.133 35.5075 ;
		RECT 0.0714 35.6518 0.133 35.7835 ;
		RECT 0 35.771 0.133 35.7835 ;
		RECT 0.0714 35.7835 0.133 35.909 ;
		RECT 0 36.0471 0.133 36.7875 ;
		RECT 0.0714 36.9318 0.133 37.0635 ;
		RECT 0 37.051 0.133 37.0635 ;
		RECT 0.0714 37.0635 0.133 37.189 ;
		RECT 0 37.3271 0.133 38.0675 ;
		RECT 0.0714 38.2118 0.133 38.3435 ;
		RECT 0 38.331 0.133 38.3435 ;
		RECT 0.0714 38.3435 0.133 38.469 ;
		RECT 0 38.6071 0.133 39.3475 ;
		RECT 0.0714 39.4918 0.133 39.6235 ;
		RECT 0 39.611 0.133 39.6235 ;
		RECT 0.0714 39.6235 0.133 39.749 ;
		RECT 0 39.8871 0.133 40.6275 ;
		RECT 0.0714 40.7718 0.133 40.9035 ;
		RECT 0 40.891 0.133 40.9035 ;
		RECT 0.0714 40.9035 0.133 41.029 ;
		RECT 0 41.1671 0.133 41.4808 ;
		RECT 0 41.6188 0.133 41.6314 ;
		RECT 0 41.7694 0.133 42.0831 ;
		RECT 0 42.2212 0.133 42.2337 ;
		RECT 0 42.3718 0.133 42.3843 ;
		RECT 0 42.5224 0.133 42.6855 ;
		RECT 0 42.8235 0.133 42.9867 ;
		RECT 0 43.1247 0.133 43.1373 ;
		RECT 0 43.2753 0.133 43.2878 ;
		RECT 0 43.4259 0.133 43.4384 ;
		RECT 0 43.5765 0.133 43.589 ;
		RECT 0 43.7271 0.133 43.7396 ;
		RECT 0 43.8776 0.133 43.8902 ;
		RECT 0 44.0282 0.133 44.0408 ;
		RECT 0 44.1788 0.133 44.1914 ;
		RECT 0 44.3294 0.133 44.342 ;
		RECT 0 44.48 0.133 44.4925 ;
		RECT 0 44.6306 0.133 44.6431 ;
		RECT 0 44.7812 0.133 44.7937 ;
		RECT 0 44.9318 0.133 44.9443 ;
		RECT 0 45.0824 0.133 45.0949 ;
		RECT 0 45.2329 0.133 45.2455 ;
		RECT 0 45.3835 0.133 45.3961 ;
		RECT 0 45.5341 0.133 45.5467 ;
		RECT 0 45.6847 0.133 45.6973 ;
		RECT 0 45.8353 0.133 45.8478 ;
		RECT 0 45.9859 0.133 45.9984 ;
		RECT 0 46.1365 0.133 46.149 ;
		RECT 0 46.2871 0.133 46.2996 ;
		RECT 0 46.4376 0.133 46.4502 ;
		RECT 0 46.5882 0.133 46.7514 ;
		RECT 0 46.8894 0.133 46.902 ;
		RECT 0 47.04 0.133 47.0525 ;
		RECT 0 47.1906 0.133 47.2031 ;
		RECT 0 47.3412 0.133 47.3537 ;
		RECT 0 47.4918 0.133 47.8055 ;
		RECT 0 47.9435 0.133 47.9561 ;
		RECT 0 48.0941 0.133 48.5584 ;
		RECT 0 48.6965 0.133 48.9035 ;
		RECT 0.0714 49.0478 0.133 49.1796 ;
		RECT 0 49.1671 0.133 49.1796 ;
		RECT 0.0714 49.1796 0.133 49.3051 ;
		RECT 0 49.4431 0.133 50.1835 ;
		RECT 0.0714 50.3278 0.133 50.4596 ;
		RECT 0 50.4471 0.133 50.4596 ;
		RECT 0.0714 50.4596 0.133 50.5851 ;
		RECT 0 50.7231 0.133 51.4635 ;
		RECT 0.0714 51.6078 0.133 51.7396 ;
		RECT 0 51.7271 0.133 51.7396 ;
		RECT 0.0714 51.7396 0.133 51.8651 ;
		RECT 0 52.0031 0.133 52.7435 ;
		RECT 0.0714 52.8878 0.133 53.0196 ;
		RECT 0 53.0071 0.133 53.0196 ;
		RECT 0.0714 53.0196 0.133 53.1451 ;
		RECT 0 53.2831 0.133 54.0235 ;
		RECT 0.0714 54.1678 0.133 54.2996 ;
		RECT 0 54.2871 0.133 54.2996 ;
		RECT 0.0714 54.2996 0.133 54.4251 ;
		RECT 0 54.5631 0.133 55.3035 ;
		RECT 0.0714 55.4478 0.133 55.5796 ;
		RECT 0 55.5671 0.133 55.5796 ;
		RECT 0.0714 55.5796 0.133 55.7051 ;
		RECT 0 55.8431 0.133 56.5835 ;
		RECT 0.0714 56.7278 0.133 56.8596 ;
		RECT 0 56.8471 0.133 56.8596 ;
		RECT 0.0714 56.8596 0.133 56.9851 ;
		RECT 0 57.1231 0.133 57.8635 ;
		RECT 0.0714 58.0078 0.133 58.1396 ;
		RECT 0 58.1271 0.133 58.1396 ;
		RECT 0.0714 58.1396 0.133 58.2651 ;
		RECT 0 58.4031 0.133 59.1435 ;
		RECT 0.0714 59.2878 0.133 59.4196 ;
		RECT 0 59.4071 0.133 59.4196 ;
		RECT 0.0714 59.4196 0.133 59.5451 ;
		RECT 0 59.6831 0.133 60.4235 ;
		RECT 0.0714 60.5678 0.133 60.6996 ;
		RECT 0 60.6871 0.133 60.6996 ;
		RECT 0.0714 60.6996 0.133 60.8251 ;
		RECT 0 60.9631 0.133 61.7035 ;
		RECT 0.0714 61.8478 0.133 61.9796 ;
		RECT 0 61.9671 0.133 61.9796 ;
		RECT 0.0714 61.9796 0.133 62.1051 ;
		RECT 0 62.2431 0.133 62.9835 ;
		RECT 0.0714 63.1278 0.133 63.2596 ;
		RECT 0 63.2471 0.133 63.2596 ;
		RECT 0.0714 63.2596 0.133 63.3851 ;
		RECT 0 63.5231 0.133 64.2635 ;
		RECT 0.0714 64.4078 0.133 64.5396 ;
		RECT 0 64.5271 0.133 64.5396 ;
		RECT 0.0714 64.5396 0.133 64.6651 ;
		RECT 0 64.8031 0.133 65.5435 ;
		RECT 0.0714 65.6878 0.133 65.8196 ;
		RECT 0 65.8071 0.133 65.8196 ;
		RECT 0.0714 65.8196 0.133 65.9451 ;
		RECT 0 66.0831 0.133 66.8235 ;
		RECT 0.0714 66.9678 0.133 67.0996 ;
		RECT 0 67.0871 0.133 67.0996 ;
		RECT 0.0714 67.0996 0.133 67.2251 ;
		RECT 0 67.3631 0.133 68.1035 ;
		RECT 0.0714 68.2478 0.133 68.3796 ;
		RECT 0 68.3671 0.133 68.3796 ;
		RECT 0.0714 68.3796 0.133 68.5051 ;
		RECT 0 68.6431 0.133 69.3835 ;
		RECT 0.0714 69.5278 0.133 69.6596 ;
		RECT 0 69.6471 0.133 69.6596 ;
		RECT 0.0714 69.6596 0.133 69.7851 ;
		RECT 0 69.9231 0.133 70.6635 ;
		RECT 0.0714 70.8078 0.133 70.9396 ;
		RECT 0 70.9271 0.133 70.9396 ;
		RECT 0.0714 70.9396 0.133 71.0651 ;
		RECT 0 71.2031 0.133 71.9435 ;
		RECT 0.0714 72.0878 0.133 72.2196 ;
		RECT 0 72.2071 0.133 72.2196 ;
		RECT 0.0714 72.2196 0.133 72.3451 ;
		RECT 0 72.4831 0.133 73.2235 ;
		RECT 0.0714 73.3678 0.133 73.4996 ;
		RECT 0 73.4871 0.133 73.4996 ;
		RECT 0.0714 73.4996 0.133 73.6251 ;
		RECT 0 73.7631 0.133 74.5035 ;
		RECT 0.0714 74.6478 0.133 74.7796 ;
		RECT 0 74.7671 0.133 74.7796 ;
		RECT 0.0714 74.7796 0.133 74.9051 ;
		RECT 0 75.0431 0.133 75.7835 ;
		RECT 0.0714 75.9278 0.133 76.0596 ;
		RECT 0 76.0471 0.133 76.0596 ;
		RECT 0.0714 76.0596 0.133 76.1851 ;
		RECT 0 76.3231 0.133 77.0635 ;
		RECT 0.0714 77.2078 0.133 77.3396 ;
		RECT 0 77.3271 0.133 77.3396 ;
		RECT 0.0714 77.3396 0.133 77.4651 ;
		RECT 0 77.6031 0.133 78.3435 ;
		RECT 0.0714 78.4878 0.133 78.6196 ;
		RECT 0 78.6071 0.133 78.6196 ;
		RECT 0.0714 78.6196 0.133 78.7451 ;
		RECT 0 78.8831 0.133 79.6235 ;
		RECT 0.0714 79.7678 0.133 79.8996 ;
		RECT 0 79.8871 0.133 79.8996 ;
		RECT 0.0714 79.8996 0.133 80.0251 ;
		RECT 0 80.1631 0.133 80.9035 ;
		RECT 0.0714 81.0478 0.133 81.1796 ;
		RECT 0 81.1671 0.133 81.1796 ;
		RECT 0.0714 81.1796 0.133 81.3051 ;
		RECT 0 81.4431 0.133 82.1835 ;
		RECT 0.0714 82.3278 0.133 82.4596 ;
		RECT 0 82.4471 0.133 82.4596 ;
		RECT 0.0714 82.4596 0.133 82.5851 ;
		RECT 0 82.7231 0.133 83.4635 ;
		RECT 0.0714 83.6078 0.133 83.7396 ;
		RECT 0 83.7271 0.133 83.7396 ;
		RECT 0.0714 83.7396 0.133 83.8651 ;
		RECT 0 84.0031 0.133 84.7435 ;
		RECT 0.0714 84.8878 0.133 85.0196 ;
		RECT 0 85.0071 0.133 85.0196 ;
		RECT 0.0714 85.0196 0.133 85.1451 ;
		RECT 0 85.2831 0.133 86.0235 ;
		RECT 0.0714 86.1678 0.133 86.2996 ;
		RECT 0 86.2871 0.133 86.2996 ;
		RECT 0.0714 86.2996 0.133 86.4251 ;
		RECT 0 86.5631 0.133 87.3035 ;
		RECT 0.0714 87.4478 0.133 87.5796 ;
		RECT 0 87.5671 0.133 87.5796 ;
		RECT 0.0714 87.5796 0.133 87.7051 ;
		RECT 0 87.8431 0.133 88.5835 ;
		RECT 0.0714 88.7278 0.133 88.8596 ;
		RECT 0 88.8471 0.133 88.8596 ;
		RECT 0.0714 88.8596 0.133 88.9851 ;
		RECT 0 89.1231 0.133 89.8886 ;
		RECT 0 90.0267 0.133 90.0706 ;
		 LAYER M3 ;
		RECT 0.0098 41.1984 0.0481 41.2988 ;
		RECT 0.0714 41.1984 0.1097 41.2988 ;
		RECT 0.0098 41.349 0.0481 41.4494 ;
		RECT 0.0714 41.349 0.1097 41.4494 ;
		RECT 0.0098 41.4996 0.0481 41.6 ;
		RECT 0.0098 41.6502 0.0481 41.7506 ;
		RECT 0.0098 41.8008 0.0481 41.9012 ;
		RECT 0.0098 41.9514 0.0481 42.0518 ;
		RECT 0.0714 41.9514 0.1097 42.0518 ;
		RECT 0.0714 42.102 0.1097 42.2024 ;
		RECT 0.0098 42.2525 0.0481 42.3529 ;
		RECT 0.0098 42.5537 0.0481 42.6541 ;
		RECT 0.0714 42.5537 0.1097 42.6541 ;
		RECT 0.0714 42.7043 0.1097 42.8047 ;
		RECT 0.0098 42.8549 0.0481 42.9553 ;
		RECT 0.0714 43.4573 0.1097 43.5576 ;
		RECT 0.0098 43.909 0.0481 44.0094 ;
		RECT 0.0714 44.0596 0.1097 44.16 ;
		RECT 0.0714 44.2102 0.1097 44.3106 ;
		RECT 0.0714 45.1137 0.1097 45.2141 ;
		RECT 0.0098 45.2643 0.0481 45.3647 ;
		RECT 0.0714 45.4149 0.1097 45.5153 ;
		RECT 0.0714 45.5655 0.1097 45.6659 ;
		RECT 0.0714 45.8667 0.1097 45.9671 ;
		RECT 0.0098 46.1678 0.0481 46.2682 ;
		RECT 0.0098 46.6196 0.0481 46.72 ;
		RECT 0.0714 46.6196 0.1097 46.72 ;
		RECT 0.0098 47.5231 0.0481 47.6235 ;
		RECT 0.0714 47.5231 0.1097 47.6235 ;
		RECT 0.0098 47.6737 0.0481 47.7741 ;
		RECT 0.0098 48.1255 0.0481 48.2259 ;
		RECT 0.0714 48.1255 0.1097 48.2259 ;
		RECT 0.0098 48.2761 0.0481 48.3765 ;
		RECT 0.0098 48.4267 0.0481 48.5271 ;
		RECT 0.0714 48.4267 0.1097 48.5271 ;
		RECT 0.0714 48.5773 0.1097 48.6776 ;
		RECT 0.0098 48.7278 0.0481 48.8282 ;
		RECT 0.0098 0.0627 0.0481 0.1631 ;
		RECT 0.0098 89.9075 0.0481 90.0078 ;
		 LAYER M3 SPACING 0.012 ;
		RECT 0.0098 41.1984 0.0481 41.2988 ;
		RECT 0.0714 41.1984 0.1097 41.2988 ;
		RECT 0.0098 41.349 0.0481 41.4494 ;
		RECT 0.0714 41.349 0.1097 41.4494 ;
		RECT 0.0098 41.4996 0.0481 41.6 ;
		RECT 0.0098 41.6502 0.0481 41.7506 ;
		RECT 0.0098 41.8008 0.0481 41.9012 ;
		RECT 0.0098 41.9514 0.0481 42.0518 ;
		RECT 0.0714 41.9514 0.1097 42.0518 ;
		RECT 0.0714 42.102 0.1097 42.2024 ;
		RECT 0.0098 42.2525 0.0481 42.3529 ;
		RECT 0.0098 42.5537 0.0481 42.6541 ;
		RECT 0.0714 42.5537 0.1097 42.6541 ;
		RECT 0.0714 42.7043 0.1097 42.8047 ;
		RECT 0.0098 42.8549 0.0481 42.9553 ;
		RECT 0.0714 43.4573 0.1097 43.5576 ;
		RECT 0.0098 43.909 0.0481 44.0094 ;
		RECT 0.0714 44.0596 0.1097 44.16 ;
		RECT 0.0714 44.2102 0.1097 44.3106 ;
		RECT 0.0714 45.1137 0.1097 45.2141 ;
		RECT 0.0098 45.2643 0.0481 45.3647 ;
		RECT 0.0714 45.4149 0.1097 45.5153 ;
		RECT 0.0714 45.5655 0.1097 45.6659 ;
		RECT 0.0714 45.8667 0.1097 45.9671 ;
		RECT 0.0098 46.1678 0.0481 46.2682 ;
		RECT 0.0098 46.6196 0.0481 46.72 ;
		RECT 0.0714 46.6196 0.1097 46.72 ;
		RECT 0.0098 47.5231 0.0481 47.6235 ;
		RECT 0.0714 47.5231 0.1097 47.6235 ;
		RECT 0.0098 47.6737 0.0481 47.7741 ;
		RECT 0.0098 48.1255 0.0481 48.2259 ;
		RECT 0.0714 48.1255 0.1097 48.2259 ;
		RECT 0.0098 48.2761 0.0481 48.3765 ;
		RECT 0.0098 48.4267 0.0481 48.5271 ;
		RECT 0.0714 48.4267 0.1097 48.5271 ;
		RECT 0.0714 48.5773 0.1097 48.6776 ;
		RECT 0.0098 48.7278 0.0481 48.8282 ;
		RECT 0.0098 0.0627 0.0481 0.1631 ;
		RECT 0.0098 89.9075 0.0481 90.0078 ;
		 LAYER M4 SPACING 0.018 ;
		RECT 0.2105 0.3286 62.454 0.5302 ;
		RECT 62.454 0.3286 62.601 0.5302 ;
		RECT 0.2105 0.64 62.454 0.7631 ;
		RECT 62.454 0.64 62.601 0.7631 ;
		RECT 0.2105 0.9686 62.454 1.1702 ;
		RECT 62.454 0.9686 62.601 1.1702 ;
		RECT 0.2105 1.28 62.454 1.4031 ;
		RECT 62.454 1.28 62.601 1.4031 ;
		RECT 0.2105 1.6086 62.454 1.8102 ;
		RECT 62.454 1.6086 62.601 1.8102 ;
		RECT 0.2105 1.92 62.454 2.0431 ;
		RECT 62.454 1.92 62.601 2.0431 ;
		RECT 0.2105 2.2486 62.454 2.4502 ;
		RECT 62.454 2.2486 62.601 2.4502 ;
		RECT 0.2105 2.56 62.454 2.6831 ;
		RECT 62.454 2.56 62.601 2.6831 ;
		RECT 0.2105 2.8886 62.454 3.0902 ;
		RECT 62.454 2.8886 62.601 3.0902 ;
		RECT 0.2105 3.2 62.454 3.3231 ;
		RECT 62.454 3.2 62.601 3.3231 ;
		RECT 0.2105 3.5286 62.454 3.7302 ;
		RECT 62.454 3.5286 62.601 3.7302 ;
		RECT 0.2105 3.84 62.454 3.9631 ;
		RECT 62.454 3.84 62.601 3.9631 ;
		RECT 0.2105 4.1686 62.454 4.3702 ;
		RECT 62.454 4.1686 62.601 4.3702 ;
		RECT 0.2105 4.48 62.454 4.6031 ;
		RECT 62.454 4.48 62.601 4.6031 ;
		RECT 0.2105 4.8086 62.454 5.0102 ;
		RECT 62.454 4.8086 62.601 5.0102 ;
		RECT 0.2105 5.12 62.454 5.2431 ;
		RECT 62.454 5.12 62.601 5.2431 ;
		RECT 0.2105 5.4486 62.454 5.6502 ;
		RECT 62.454 5.4486 62.601 5.6502 ;
		RECT 0.2105 5.76 62.454 5.8831 ;
		RECT 62.454 5.76 62.601 5.8831 ;
		RECT 0.2105 6.0886 62.454 6.2902 ;
		RECT 62.454 6.0886 62.601 6.2902 ;
		RECT 0.2105 6.4 62.454 6.5231 ;
		RECT 62.454 6.4 62.601 6.5231 ;
		RECT 0.2105 6.7286 62.454 6.9302 ;
		RECT 62.454 6.7286 62.601 6.9302 ;
		RECT 0.2105 7.04 62.454 7.1631 ;
		RECT 62.454 7.04 62.601 7.1631 ;
		RECT 0.2105 7.3686 62.454 7.5702 ;
		RECT 62.454 7.3686 62.601 7.5702 ;
		RECT 0.2105 7.68 62.454 7.8031 ;
		RECT 62.454 7.68 62.601 7.8031 ;
		RECT 0.2105 8.0086 62.454 8.2102 ;
		RECT 62.454 8.0086 62.601 8.2102 ;
		RECT 0.2105 8.32 62.454 8.4431 ;
		RECT 62.454 8.32 62.601 8.4431 ;
		RECT 0.2105 8.6486 62.454 8.8502 ;
		RECT 62.454 8.6486 62.601 8.8502 ;
		RECT 0.2105 8.96 62.454 9.0831 ;
		RECT 62.454 8.96 62.601 9.0831 ;
		RECT 0.2105 9.2886 62.454 9.4902 ;
		RECT 62.454 9.2886 62.601 9.4902 ;
		RECT 0.2105 9.6 62.454 9.7231 ;
		RECT 62.454 9.6 62.601 9.7231 ;
		RECT 0.2105 9.9286 62.454 10.1302 ;
		RECT 62.454 9.9286 62.601 10.1302 ;
		RECT 0.2105 10.24 62.454 10.3631 ;
		RECT 62.454 10.24 62.601 10.3631 ;
		RECT 0.2105 10.5686 62.454 10.7702 ;
		RECT 62.454 10.5686 62.601 10.7702 ;
		RECT 0.2105 10.88 62.454 11.0031 ;
		RECT 62.454 10.88 62.601 11.0031 ;
		RECT 0.2105 11.2086 62.454 11.4102 ;
		RECT 62.454 11.2086 62.601 11.4102 ;
		RECT 0.2105 11.52 62.454 11.6431 ;
		RECT 62.454 11.52 62.601 11.6431 ;
		RECT 0.2105 11.8486 62.454 12.0502 ;
		RECT 62.454 11.8486 62.601 12.0502 ;
		RECT 0.2105 12.16 62.454 12.2831 ;
		RECT 62.454 12.16 62.601 12.2831 ;
		RECT 0.2105 12.4886 62.454 12.6902 ;
		RECT 62.454 12.4886 62.601 12.6902 ;
		RECT 0.2105 12.8 62.454 12.9231 ;
		RECT 62.454 12.8 62.601 12.9231 ;
		RECT 0.2105 13.1286 62.454 13.3302 ;
		RECT 62.454 13.1286 62.601 13.3302 ;
		RECT 0.2105 13.44 62.454 13.5631 ;
		RECT 62.454 13.44 62.601 13.5631 ;
		RECT 0.2105 13.7686 62.454 13.9702 ;
		RECT 62.454 13.7686 62.601 13.9702 ;
		RECT 0.2105 14.08 62.454 14.2031 ;
		RECT 62.454 14.08 62.601 14.2031 ;
		RECT 0.2105 14.4086 62.454 14.6102 ;
		RECT 62.454 14.4086 62.601 14.6102 ;
		RECT 0.2105 14.72 62.454 14.8431 ;
		RECT 62.454 14.72 62.601 14.8431 ;
		RECT 0.2105 15.0486 62.454 15.2502 ;
		RECT 62.454 15.0486 62.601 15.2502 ;
		RECT 0.2105 15.36 62.454 15.4831 ;
		RECT 62.454 15.36 62.601 15.4831 ;
		RECT 0.2105 15.6886 62.454 15.8902 ;
		RECT 62.454 15.6886 62.601 15.8902 ;
		RECT 0.2105 16 62.454 16.1231 ;
		RECT 62.454 16 62.601 16.1231 ;
		RECT 0.2105 16.3286 62.454 16.5302 ;
		RECT 62.454 16.3286 62.601 16.5302 ;
		RECT 0.2105 16.64 62.454 16.7631 ;
		RECT 62.454 16.64 62.601 16.7631 ;
		RECT 0.2105 16.9686 62.454 17.1702 ;
		RECT 62.454 16.9686 62.601 17.1702 ;
		RECT 0.2105 17.28 62.454 17.4031 ;
		RECT 62.454 17.28 62.601 17.4031 ;
		RECT 0.2105 17.6086 62.454 17.8102 ;
		RECT 62.454 17.6086 62.601 17.8102 ;
		RECT 0.2105 17.92 62.454 18.0431 ;
		RECT 62.454 17.92 62.601 18.0431 ;
		RECT 0.2105 18.2486 62.454 18.4502 ;
		RECT 62.454 18.2486 62.601 18.4502 ;
		RECT 0.2105 18.56 62.454 18.6831 ;
		RECT 62.454 18.56 62.601 18.6831 ;
		RECT 0.2105 18.8886 62.454 19.0902 ;
		RECT 62.454 18.8886 62.601 19.0902 ;
		RECT 0.2105 19.2 62.454 19.3231 ;
		RECT 62.454 19.2 62.601 19.3231 ;
		RECT 0.2105 19.5286 62.454 19.7302 ;
		RECT 62.454 19.5286 62.601 19.7302 ;
		RECT 0.2105 19.84 62.454 19.9631 ;
		RECT 62.454 19.84 62.601 19.9631 ;
		RECT 0.2105 20.1686 62.454 20.3702 ;
		RECT 62.454 20.1686 62.601 20.3702 ;
		RECT 0.2105 20.48 62.454 20.6031 ;
		RECT 62.454 20.48 62.601 20.6031 ;
		RECT 0.2105 20.8086 62.454 21.0102 ;
		RECT 62.454 20.8086 62.601 21.0102 ;
		RECT 0.2105 21.12 62.454 21.2431 ;
		RECT 62.454 21.12 62.601 21.2431 ;
		RECT 0.2105 21.4486 62.454 21.6502 ;
		RECT 62.454 21.4486 62.601 21.6502 ;
		RECT 0.2105 21.76 62.454 21.8831 ;
		RECT 62.454 21.76 62.601 21.8831 ;
		RECT 0.2105 22.0886 62.454 22.2902 ;
		RECT 62.454 22.0886 62.601 22.2902 ;
		RECT 0.2105 22.4 62.454 22.5231 ;
		RECT 62.454 22.4 62.601 22.5231 ;
		RECT 0.2105 22.7286 62.454 22.9302 ;
		RECT 62.454 22.7286 62.601 22.9302 ;
		RECT 0.2105 23.04 62.454 23.1631 ;
		RECT 62.454 23.04 62.601 23.1631 ;
		RECT 0.2105 23.3686 62.454 23.5702 ;
		RECT 62.454 23.3686 62.601 23.5702 ;
		RECT 0.2105 23.68 62.454 23.8031 ;
		RECT 62.454 23.68 62.601 23.8031 ;
		RECT 0.2105 24.0086 62.454 24.2102 ;
		RECT 62.454 24.0086 62.601 24.2102 ;
		RECT 0.2105 24.32 62.454 24.4431 ;
		RECT 62.454 24.32 62.601 24.4431 ;
		RECT 0.2105 24.6486 62.454 24.8502 ;
		RECT 62.454 24.6486 62.601 24.8502 ;
		RECT 0.2105 24.96 62.454 25.0831 ;
		RECT 62.454 24.96 62.601 25.0831 ;
		RECT 0.2105 25.2886 62.454 25.4902 ;
		RECT 62.454 25.2886 62.601 25.4902 ;
		RECT 0.2105 25.6 62.454 25.7231 ;
		RECT 62.454 25.6 62.601 25.7231 ;
		RECT 0.2105 25.9286 62.454 26.1302 ;
		RECT 62.454 25.9286 62.601 26.1302 ;
		RECT 0.2105 26.24 62.454 26.3631 ;
		RECT 62.454 26.24 62.601 26.3631 ;
		RECT 0.2105 26.5686 62.454 26.7702 ;
		RECT 62.454 26.5686 62.601 26.7702 ;
		RECT 0.2105 26.88 62.454 27.0031 ;
		RECT 62.454 26.88 62.601 27.0031 ;
		RECT 0.2105 27.2086 62.454 27.4102 ;
		RECT 62.454 27.2086 62.601 27.4102 ;
		RECT 0.2105 27.52 62.454 27.6431 ;
		RECT 62.454 27.52 62.601 27.6431 ;
		RECT 0.2105 27.8486 62.454 28.0502 ;
		RECT 62.454 27.8486 62.601 28.0502 ;
		RECT 0.2105 28.16 62.454 28.2831 ;
		RECT 62.454 28.16 62.601 28.2831 ;
		RECT 0.2105 28.4886 62.454 28.6902 ;
		RECT 62.454 28.4886 62.601 28.6902 ;
		RECT 0.2105 28.8 62.454 28.9231 ;
		RECT 62.454 28.8 62.601 28.9231 ;
		RECT 0.2105 29.1286 62.454 29.3302 ;
		RECT 62.454 29.1286 62.601 29.3302 ;
		RECT 0.2105 29.44 62.454 29.5631 ;
		RECT 62.454 29.44 62.601 29.5631 ;
		RECT 0.2105 29.7686 62.454 29.9702 ;
		RECT 62.454 29.7686 62.601 29.9702 ;
		RECT 0.2105 30.08 62.454 30.2031 ;
		RECT 62.454 30.08 62.601 30.2031 ;
		RECT 0.2105 30.4086 62.454 30.6102 ;
		RECT 62.454 30.4086 62.601 30.6102 ;
		RECT 0.2105 30.72 62.454 30.8431 ;
		RECT 62.454 30.72 62.601 30.8431 ;
		RECT 0.2105 31.0486 62.454 31.2502 ;
		RECT 62.454 31.0486 62.601 31.2502 ;
		RECT 0.2105 31.36 62.454 31.4831 ;
		RECT 62.454 31.36 62.601 31.4831 ;
		RECT 0.2105 31.6886 62.454 31.8902 ;
		RECT 62.454 31.6886 62.601 31.8902 ;
		RECT 0.2105 32 62.454 32.1231 ;
		RECT 62.454 32 62.601 32.1231 ;
		RECT 0.2105 32.3286 62.454 32.5302 ;
		RECT 62.454 32.3286 62.601 32.5302 ;
		RECT 0.2105 32.64 62.454 32.7631 ;
		RECT 62.454 32.64 62.601 32.7631 ;
		RECT 0.2105 32.9686 62.454 33.1702 ;
		RECT 62.454 32.9686 62.601 33.1702 ;
		RECT 0.2105 33.28 62.454 33.4031 ;
		RECT 62.454 33.28 62.601 33.4031 ;
		RECT 0.2105 33.6086 62.454 33.8102 ;
		RECT 62.454 33.6086 62.601 33.8102 ;
		RECT 0.2105 33.92 62.454 34.0431 ;
		RECT 62.454 33.92 62.601 34.0431 ;
		RECT 0.2105 34.2486 62.454 34.4502 ;
		RECT 62.454 34.2486 62.601 34.4502 ;
		RECT 0.2105 34.56 62.454 34.6831 ;
		RECT 62.454 34.56 62.601 34.6831 ;
		RECT 0.2105 34.8886 62.454 35.0902 ;
		RECT 62.454 34.8886 62.601 35.0902 ;
		RECT 0.2105 35.2 62.454 35.3231 ;
		RECT 62.454 35.2 62.601 35.3231 ;
		RECT 0.2105 35.5286 62.454 35.7302 ;
		RECT 62.454 35.5286 62.601 35.7302 ;
		RECT 0.2105 35.84 62.454 35.9631 ;
		RECT 62.454 35.84 62.601 35.9631 ;
		RECT 0.2105 36.1686 62.454 36.3702 ;
		RECT 62.454 36.1686 62.601 36.3702 ;
		RECT 0.2105 36.48 62.454 36.6031 ;
		RECT 62.454 36.48 62.601 36.6031 ;
		RECT 0.2105 36.8086 62.454 37.0102 ;
		RECT 62.454 36.8086 62.601 37.0102 ;
		RECT 0.2105 37.12 62.454 37.2431 ;
		RECT 62.454 37.12 62.601 37.2431 ;
		RECT 0.2105 37.4486 62.454 37.6502 ;
		RECT 62.454 37.4486 62.601 37.6502 ;
		RECT 0.2105 37.76 62.454 37.8831 ;
		RECT 62.454 37.76 62.601 37.8831 ;
		RECT 0.2105 38.0886 62.454 38.2902 ;
		RECT 62.454 38.0886 62.601 38.2902 ;
		RECT 0.2105 38.4 62.454 38.5231 ;
		RECT 62.454 38.4 62.601 38.5231 ;
		RECT 0.2105 38.7286 62.454 38.9302 ;
		RECT 62.454 38.7286 62.601 38.9302 ;
		RECT 0.2105 39.04 62.454 39.1631 ;
		RECT 62.454 39.04 62.601 39.1631 ;
		RECT 0.2105 39.3686 62.454 39.5702 ;
		RECT 62.454 39.3686 62.601 39.5702 ;
		RECT 0.2105 39.68 62.454 39.8031 ;
		RECT 62.454 39.68 62.601 39.8031 ;
		RECT 0.2105 40.0086 62.454 40.2102 ;
		RECT 62.454 40.0086 62.601 40.2102 ;
		RECT 0.2105 40.32 62.454 40.4431 ;
		RECT 62.454 40.32 62.601 40.4431 ;
		RECT 0.2105 40.6486 62.454 40.8502 ;
		RECT 62.454 40.6486 62.601 40.8502 ;
		RECT 0.2105 40.96 62.454 41.0831 ;
		RECT 62.454 40.96 62.601 41.0831 ;
		RECT 0.2105 41.5467 62.454 41.7961 ;
		RECT 62.454 41.5467 62.601 41.7961 ;
		RECT 0.2105 42.2761 62.454 42.6149 ;
		RECT 62.454 42.2761 62.601 42.6149 ;
		RECT 0.2105 42.8031 62.454 43.142 ;
		RECT 62.454 42.8031 62.601 43.142 ;
		RECT 0.2105 43.3302 62.454 43.669 ;
		RECT 62.454 43.3302 62.601 43.669 ;
		RECT 0.2105 43.8573 62.454 44.1961 ;
		RECT 62.454 43.8573 62.601 44.1961 ;
		RECT 0.2105 44.3843 62.454 45.2502 ;
		RECT 62.454 44.3843 62.601 45.2502 ;
		RECT 0.2105 45.4384 62.454 46.3043 ;
		RECT 62.454 45.4384 62.601 46.3043 ;
		RECT 0.2105 46.4925 62.454 46.8314 ;
		RECT 62.454 46.4925 62.601 46.8314 ;
		RECT 0.2105 47.0196 62.454 47.3584 ;
		RECT 62.454 47.0196 62.601 47.3584 ;
		RECT 0.2105 47.5467 62.454 47.8855 ;
		RECT 62.454 47.5467 62.601 47.8855 ;
		RECT 0.2105 48.4439 62.454 48.6843 ;
		RECT 62.454 48.4439 62.601 48.6843 ;
		RECT 0.2105 48.9875 62.454 49.1106 ;
		RECT 62.454 48.9875 62.601 49.1106 ;
		RECT 0.2105 49.2204 62.454 49.422 ;
		RECT 62.454 49.2204 62.601 49.422 ;
		RECT 0.2105 49.6275 62.454 49.7506 ;
		RECT 62.454 49.6275 62.601 49.7506 ;
		RECT 0.2105 49.8604 62.454 50.062 ;
		RECT 62.454 49.8604 62.601 50.062 ;
		RECT 0.2105 50.2675 62.454 50.3906 ;
		RECT 62.454 50.2675 62.601 50.3906 ;
		RECT 0.2105 50.5004 62.454 50.702 ;
		RECT 62.454 50.5004 62.601 50.702 ;
		RECT 0.2105 50.9075 62.454 51.0306 ;
		RECT 62.454 50.9075 62.601 51.0306 ;
		RECT 0.2105 51.1404 62.454 51.342 ;
		RECT 62.454 51.1404 62.601 51.342 ;
		RECT 0.2105 51.5475 62.454 51.6706 ;
		RECT 62.454 51.5475 62.601 51.6706 ;
		RECT 0.2105 51.7804 62.454 51.982 ;
		RECT 62.454 51.7804 62.601 51.982 ;
		RECT 0.2105 52.1875 62.454 52.3106 ;
		RECT 62.454 52.1875 62.601 52.3106 ;
		RECT 0.2105 52.4204 62.454 52.622 ;
		RECT 62.454 52.4204 62.601 52.622 ;
		RECT 0.2105 52.8275 62.454 52.9506 ;
		RECT 62.454 52.8275 62.601 52.9506 ;
		RECT 0.2105 53.0604 62.454 53.262 ;
		RECT 62.454 53.0604 62.601 53.262 ;
		RECT 0.2105 53.4675 62.454 53.5906 ;
		RECT 62.454 53.4675 62.601 53.5906 ;
		RECT 0.2105 53.7004 62.454 53.902 ;
		RECT 62.454 53.7004 62.601 53.902 ;
		RECT 0.2105 54.1075 62.454 54.2306 ;
		RECT 62.454 54.1075 62.601 54.2306 ;
		RECT 0.2105 54.3404 62.454 54.542 ;
		RECT 62.454 54.3404 62.601 54.542 ;
		RECT 0.2105 54.7475 62.454 54.8706 ;
		RECT 62.454 54.7475 62.601 54.8706 ;
		RECT 0.2105 54.9804 62.454 55.182 ;
		RECT 62.454 54.9804 62.601 55.182 ;
		RECT 0.2105 55.3875 62.454 55.5106 ;
		RECT 62.454 55.3875 62.601 55.5106 ;
		RECT 0.2105 55.6204 62.454 55.822 ;
		RECT 62.454 55.6204 62.601 55.822 ;
		RECT 0.2105 56.0275 62.454 56.1506 ;
		RECT 62.454 56.0275 62.601 56.1506 ;
		RECT 0.2105 56.2604 62.454 56.462 ;
		RECT 62.454 56.2604 62.601 56.462 ;
		RECT 0.2105 56.6675 62.454 56.7906 ;
		RECT 62.454 56.6675 62.601 56.7906 ;
		RECT 0.2105 56.9004 62.454 57.102 ;
		RECT 62.454 56.9004 62.601 57.102 ;
		RECT 0.2105 57.3075 62.454 57.4306 ;
		RECT 62.454 57.3075 62.601 57.4306 ;
		RECT 0.2105 57.5404 62.454 57.742 ;
		RECT 62.454 57.5404 62.601 57.742 ;
		RECT 0.2105 57.9475 62.454 58.0706 ;
		RECT 62.454 57.9475 62.601 58.0706 ;
		RECT 0.2105 58.1804 62.454 58.382 ;
		RECT 62.454 58.1804 62.601 58.382 ;
		RECT 0.2105 58.5875 62.454 58.7106 ;
		RECT 62.454 58.5875 62.601 58.7106 ;
		RECT 0.2105 58.8204 62.454 59.022 ;
		RECT 62.454 58.8204 62.601 59.022 ;
		RECT 0.2105 59.2275 62.454 59.3506 ;
		RECT 62.454 59.2275 62.601 59.3506 ;
		RECT 0.2105 59.4604 62.454 59.662 ;
		RECT 62.454 59.4604 62.601 59.662 ;
		RECT 0.2105 59.8675 62.454 59.9906 ;
		RECT 62.454 59.8675 62.601 59.9906 ;
		RECT 0.2105 60.1004 62.454 60.302 ;
		RECT 62.454 60.1004 62.601 60.302 ;
		RECT 0.2105 60.5075 62.454 60.6306 ;
		RECT 62.454 60.5075 62.601 60.6306 ;
		RECT 0.2105 60.7404 62.454 60.942 ;
		RECT 62.454 60.7404 62.601 60.942 ;
		RECT 0.2105 61.1475 62.454 61.2706 ;
		RECT 62.454 61.1475 62.601 61.2706 ;
		RECT 0.2105 61.3804 62.454 61.582 ;
		RECT 62.454 61.3804 62.601 61.582 ;
		RECT 0.2105 61.7875 62.454 61.9106 ;
		RECT 62.454 61.7875 62.601 61.9106 ;
		RECT 0.2105 62.0204 62.454 62.222 ;
		RECT 62.454 62.0204 62.601 62.222 ;
		RECT 0.2105 62.4275 62.454 62.5506 ;
		RECT 62.454 62.4275 62.601 62.5506 ;
		RECT 0.2105 62.6604 62.454 62.862 ;
		RECT 62.454 62.6604 62.601 62.862 ;
		RECT 0.2105 63.0675 62.454 63.1906 ;
		RECT 62.454 63.0675 62.601 63.1906 ;
		RECT 0.2105 63.3004 62.454 63.502 ;
		RECT 62.454 63.3004 62.601 63.502 ;
		RECT 0.2105 63.7075 62.454 63.8306 ;
		RECT 62.454 63.7075 62.601 63.8306 ;
		RECT 0.2105 63.9404 62.454 64.142 ;
		RECT 62.454 63.9404 62.601 64.142 ;
		RECT 0.2105 64.3475 62.454 64.4706 ;
		RECT 62.454 64.3475 62.601 64.4706 ;
		RECT 0.2105 64.5804 62.454 64.782 ;
		RECT 62.454 64.5804 62.601 64.782 ;
		RECT 0.2105 64.9875 62.454 65.1106 ;
		RECT 62.454 64.9875 62.601 65.1106 ;
		RECT 0.2105 65.2204 62.454 65.422 ;
		RECT 62.454 65.2204 62.601 65.422 ;
		RECT 0.2105 65.6275 62.454 65.7506 ;
		RECT 62.454 65.6275 62.601 65.7506 ;
		RECT 0.2105 65.8604 62.454 66.062 ;
		RECT 62.454 65.8604 62.601 66.062 ;
		RECT 0.2105 66.2675 62.454 66.3906 ;
		RECT 62.454 66.2675 62.601 66.3906 ;
		RECT 0.2105 66.5004 62.454 66.702 ;
		RECT 62.454 66.5004 62.601 66.702 ;
		RECT 0.2105 66.9075 62.454 67.0306 ;
		RECT 62.454 66.9075 62.601 67.0306 ;
		RECT 0.2105 67.1404 62.454 67.342 ;
		RECT 62.454 67.1404 62.601 67.342 ;
		RECT 0.2105 67.5475 62.454 67.6706 ;
		RECT 62.454 67.5475 62.601 67.6706 ;
		RECT 0.2105 67.7804 62.454 67.982 ;
		RECT 62.454 67.7804 62.601 67.982 ;
		RECT 0.2105 68.1875 62.454 68.3106 ;
		RECT 62.454 68.1875 62.601 68.3106 ;
		RECT 0.2105 68.4204 62.454 68.622 ;
		RECT 62.454 68.4204 62.601 68.622 ;
		RECT 0.2105 68.8275 62.454 68.9506 ;
		RECT 62.454 68.8275 62.601 68.9506 ;
		RECT 0.2105 69.0604 62.454 69.262 ;
		RECT 62.454 69.0604 62.601 69.262 ;
		RECT 0.2105 69.4675 62.454 69.5906 ;
		RECT 62.454 69.4675 62.601 69.5906 ;
		RECT 0.2105 69.7004 62.454 69.902 ;
		RECT 62.454 69.7004 62.601 69.902 ;
		RECT 0.2105 70.1075 62.454 70.2306 ;
		RECT 62.454 70.1075 62.601 70.2306 ;
		RECT 0.2105 70.3404 62.454 70.542 ;
		RECT 62.454 70.3404 62.601 70.542 ;
		RECT 0.2105 70.7475 62.454 70.8706 ;
		RECT 62.454 70.7475 62.601 70.8706 ;
		RECT 0.2105 70.9804 62.454 71.182 ;
		RECT 62.454 70.9804 62.601 71.182 ;
		RECT 0.2105 71.3875 62.454 71.5106 ;
		RECT 62.454 71.3875 62.601 71.5106 ;
		RECT 0.2105 71.6204 62.454 71.822 ;
		RECT 62.454 71.6204 62.601 71.822 ;
		RECT 0.2105 72.0275 62.454 72.1506 ;
		RECT 62.454 72.0275 62.601 72.1506 ;
		RECT 0.2105 72.2604 62.454 72.462 ;
		RECT 62.454 72.2604 62.601 72.462 ;
		RECT 0.2105 72.6675 62.454 72.7906 ;
		RECT 62.454 72.6675 62.601 72.7906 ;
		RECT 0.2105 72.9004 62.454 73.102 ;
		RECT 62.454 72.9004 62.601 73.102 ;
		RECT 0.2105 73.3075 62.454 73.4306 ;
		RECT 62.454 73.3075 62.601 73.4306 ;
		RECT 0.2105 73.5404 62.454 73.742 ;
		RECT 62.454 73.5404 62.601 73.742 ;
		RECT 0.2105 73.9475 62.454 74.0706 ;
		RECT 62.454 73.9475 62.601 74.0706 ;
		RECT 0.2105 74.1804 62.454 74.382 ;
		RECT 62.454 74.1804 62.601 74.382 ;
		RECT 0.2105 74.5875 62.454 74.7106 ;
		RECT 62.454 74.5875 62.601 74.7106 ;
		RECT 0.2105 74.8204 62.454 75.022 ;
		RECT 62.454 74.8204 62.601 75.022 ;
		RECT 0.2105 75.2275 62.454 75.3506 ;
		RECT 62.454 75.2275 62.601 75.3506 ;
		RECT 0.2105 75.4604 62.454 75.662 ;
		RECT 62.454 75.4604 62.601 75.662 ;
		RECT 0.2105 75.8675 62.454 75.9906 ;
		RECT 62.454 75.8675 62.601 75.9906 ;
		RECT 0.2105 76.1004 62.454 76.302 ;
		RECT 62.454 76.1004 62.601 76.302 ;
		RECT 0.2105 76.5075 62.454 76.6306 ;
		RECT 62.454 76.5075 62.601 76.6306 ;
		RECT 0.2105 76.7404 62.454 76.942 ;
		RECT 62.454 76.7404 62.601 76.942 ;
		RECT 0.2105 77.1475 62.454 77.2706 ;
		RECT 62.454 77.1475 62.601 77.2706 ;
		RECT 0.2105 77.3804 62.454 77.582 ;
		RECT 62.454 77.3804 62.601 77.582 ;
		RECT 0.2105 77.7875 62.454 77.9106 ;
		RECT 62.454 77.7875 62.601 77.9106 ;
		RECT 0.2105 78.0204 62.454 78.222 ;
		RECT 62.454 78.0204 62.601 78.222 ;
		RECT 0.2105 78.4275 62.454 78.5506 ;
		RECT 62.454 78.4275 62.601 78.5506 ;
		RECT 0.2105 78.6604 62.454 78.862 ;
		RECT 62.454 78.6604 62.601 78.862 ;
		RECT 0.2105 79.0675 62.454 79.1906 ;
		RECT 62.454 79.0675 62.601 79.1906 ;
		RECT 0.2105 79.3004 62.454 79.502 ;
		RECT 62.454 79.3004 62.601 79.502 ;
		RECT 0.2105 79.7075 62.454 79.8306 ;
		RECT 62.454 79.7075 62.601 79.8306 ;
		RECT 0.2105 79.9404 62.454 80.142 ;
		RECT 62.454 79.9404 62.601 80.142 ;
		RECT 0.2105 80.3475 62.454 80.4706 ;
		RECT 62.454 80.3475 62.601 80.4706 ;
		RECT 0.2105 80.5804 62.454 80.782 ;
		RECT 62.454 80.5804 62.601 80.782 ;
		RECT 0.2105 80.9875 62.454 81.1106 ;
		RECT 62.454 80.9875 62.601 81.1106 ;
		RECT 0.2105 81.2204 62.454 81.422 ;
		RECT 62.454 81.2204 62.601 81.422 ;
		RECT 0.2105 81.6275 62.454 81.7506 ;
		RECT 62.454 81.6275 62.601 81.7506 ;
		RECT 0.2105 81.8604 62.454 82.062 ;
		RECT 62.454 81.8604 62.601 82.062 ;
		RECT 0.2105 82.2675 62.454 82.3906 ;
		RECT 62.454 82.2675 62.601 82.3906 ;
		RECT 0.2105 82.5004 62.454 82.702 ;
		RECT 62.454 82.5004 62.601 82.702 ;
		RECT 0.2105 82.9075 62.454 83.0306 ;
		RECT 62.454 82.9075 62.601 83.0306 ;
		RECT 0.2105 83.1404 62.454 83.342 ;
		RECT 62.454 83.1404 62.601 83.342 ;
		RECT 0.2105 83.5475 62.454 83.6706 ;
		RECT 62.454 83.5475 62.601 83.6706 ;
		RECT 0.2105 83.7804 62.454 83.982 ;
		RECT 62.454 83.7804 62.601 83.982 ;
		RECT 0.2105 84.1875 62.454 84.3106 ;
		RECT 62.454 84.1875 62.601 84.3106 ;
		RECT 0.2105 84.4204 62.454 84.622 ;
		RECT 62.454 84.4204 62.601 84.622 ;
		RECT 0.2105 84.8275 62.454 84.9506 ;
		RECT 62.454 84.8275 62.601 84.9506 ;
		RECT 0.2105 85.0604 62.454 85.262 ;
		RECT 62.454 85.0604 62.601 85.262 ;
		RECT 0.2105 85.4675 62.454 85.5906 ;
		RECT 62.454 85.4675 62.601 85.5906 ;
		RECT 0.2105 85.7004 62.454 85.902 ;
		RECT 62.454 85.7004 62.601 85.902 ;
		RECT 0.2105 86.1075 62.454 86.2306 ;
		RECT 62.454 86.1075 62.601 86.2306 ;
		RECT 0.2105 86.3404 62.454 86.542 ;
		RECT 62.454 86.3404 62.601 86.542 ;
		RECT 0.2105 86.7475 62.454 86.8706 ;
		RECT 62.454 86.7475 62.601 86.8706 ;
		RECT 0.2105 86.9804 62.454 87.182 ;
		RECT 62.454 86.9804 62.601 87.182 ;
		RECT 0.2105 87.3875 62.454 87.5106 ;
		RECT 62.454 87.3875 62.601 87.5106 ;
		RECT 0.2105 87.6204 62.454 87.822 ;
		RECT 62.454 87.6204 62.601 87.822 ;
		RECT 0.2105 88.0275 62.454 88.1506 ;
		RECT 62.454 88.0275 62.601 88.1506 ;
		RECT 0.2105 88.2604 62.454 88.462 ;
		RECT 62.454 88.2604 62.601 88.462 ;
		RECT 0.2105 88.6675 62.454 88.7906 ;
		RECT 62.454 88.6675 62.601 88.7906 ;
		RECT 0.2105 88.9004 62.454 89.102 ;
		RECT 62.454 88.9004 62.601 89.102 ;
		RECT 0.2105 89.3075 62.454 89.4306 ;
		RECT 62.454 89.3075 62.601 89.4306 ;
		RECT 0.2105 89.5404 62.454 89.742 ;
		RECT 62.454 89.5404 62.601 89.742 ;
		 LAYER M4 ;
		RECT 0.2105 0 62.454 0.022 ;
		RECT 62.454 0 62.601 0.022 ;
		RECT 0.2105 41.9843 62.454 42.0094 ;
		RECT 62.454 41.9843 62.601 42.0094 ;
		RECT 0.2105 48.2306 62.454 48.2557 ;
		RECT 62.454 48.2306 62.601 48.2557 ;
		RECT 0.2105 90.0486 62.454 90.0706 ;
		RECT 62.454 90.0486 62.601 90.0706 ;
		 LAYER M4 SPACING 0.018 ;
		RECT 0.2105 0 62.454 0.022 ;
		RECT 62.454 0 62.601 0.022 ;
		RECT 0.2105 41.9843 62.454 42.0094 ;
		RECT 62.454 41.9843 62.601 42.0094 ;
		RECT 0.2105 48.2306 62.454 48.2557 ;
		RECT 62.454 48.2306 62.601 48.2557 ;
		RECT 0.2105 90.0486 62.454 90.0706 ;
		RECT 62.454 90.0486 62.601 90.0706 ;
		 LAYER V1 SPACING 0 ;
		RECT 0 0 62.601 90.0706 ;
		 LAYER V2 SPACING 0 ;
		RECT 0.1097 0 62.601 90.0706 ;
		RECT 0 0 0.1097 0.0627 ;
		RECT 0 0.1631 0.1097 0.9663 ;
		RECT 0 1.0667 0.1097 1.0918 ;
		RECT 0 1.1922 0.1097 1.2424 ;
		RECT 0 1.3427 0.1097 1.3678 ;
		RECT 0 1.4682 0.1097 2.2463 ;
		RECT 0 2.3467 0.1097 2.3718 ;
		RECT 0 2.4722 0.1097 2.5224 ;
		RECT 0 2.6227 0.1097 2.6478 ;
		RECT 0 2.7482 0.1097 3.5263 ;
		RECT 0 3.6267 0.1097 3.6518 ;
		RECT 0 3.7522 0.1097 3.8024 ;
		RECT 0 3.9027 0.1097 3.9278 ;
		RECT 0 4.0282 0.1097 4.8063 ;
		RECT 0 4.9067 0.1097 4.9318 ;
		RECT 0 5.0322 0.1097 5.0824 ;
		RECT 0 5.1827 0.1097 5.2078 ;
		RECT 0 5.3082 0.1097 6.0863 ;
		RECT 0 6.1867 0.1097 6.2118 ;
		RECT 0 6.3122 0.1097 6.3624 ;
		RECT 0 6.4627 0.1097 6.4878 ;
		RECT 0 6.5882 0.1097 7.3663 ;
		RECT 0 7.4667 0.1097 7.4918 ;
		RECT 0 7.5922 0.1097 7.6424 ;
		RECT 0 7.7427 0.1097 7.7678 ;
		RECT 0 7.8682 0.1097 8.6463 ;
		RECT 0 8.7467 0.1097 8.7718 ;
		RECT 0 8.8722 0.1097 8.9224 ;
		RECT 0 9.0227 0.1097 9.0478 ;
		RECT 0 9.1482 0.1097 9.9263 ;
		RECT 0 10.0267 0.1097 10.0518 ;
		RECT 0 10.1522 0.1097 10.2024 ;
		RECT 0 10.3027 0.1097 10.3278 ;
		RECT 0 10.4282 0.1097 11.2063 ;
		RECT 0 11.3067 0.1097 11.3318 ;
		RECT 0 11.4322 0.1097 11.4824 ;
		RECT 0 11.5827 0.1097 11.6078 ;
		RECT 0 11.7082 0.1097 12.4863 ;
		RECT 0 12.5867 0.1097 12.6118 ;
		RECT 0 12.7122 0.1097 12.7624 ;
		RECT 0 12.8627 0.1097 12.8878 ;
		RECT 0 12.9882 0.1097 13.7663 ;
		RECT 0 13.8667 0.1097 13.8918 ;
		RECT 0 13.9922 0.1097 14.0424 ;
		RECT 0 14.1427 0.1097 14.1678 ;
		RECT 0 14.2682 0.1097 15.0463 ;
		RECT 0 15.1467 0.1097 15.1718 ;
		RECT 0 15.2722 0.1097 15.3224 ;
		RECT 0 15.4227 0.1097 15.4478 ;
		RECT 0 15.5482 0.1097 16.3263 ;
		RECT 0 16.4267 0.1097 16.4518 ;
		RECT 0 16.5522 0.1097 16.6024 ;
		RECT 0 16.7027 0.1097 16.7278 ;
		RECT 0 16.8282 0.1097 17.6063 ;
		RECT 0 17.7067 0.1097 17.7318 ;
		RECT 0 17.8322 0.1097 17.8824 ;
		RECT 0 17.9827 0.1097 18.0078 ;
		RECT 0 18.1082 0.1097 18.8863 ;
		RECT 0 18.9867 0.1097 19.0118 ;
		RECT 0 19.1122 0.1097 19.1624 ;
		RECT 0 19.2627 0.1097 19.2878 ;
		RECT 0 19.3882 0.1097 20.1663 ;
		RECT 0 20.2667 0.1097 20.2918 ;
		RECT 0 20.3922 0.1097 20.4424 ;
		RECT 0 20.5427 0.1097 20.5678 ;
		RECT 0 20.6682 0.1097 21.4463 ;
		RECT 0 21.5467 0.1097 21.5718 ;
		RECT 0 21.6722 0.1097 21.7224 ;
		RECT 0 21.8227 0.1097 21.8478 ;
		RECT 0 21.9482 0.1097 22.7263 ;
		RECT 0 22.8267 0.1097 22.8518 ;
		RECT 0 22.9522 0.1097 23.0024 ;
		RECT 0 23.1027 0.1097 23.1278 ;
		RECT 0 23.2282 0.1097 24.0063 ;
		RECT 0 24.1067 0.1097 24.1318 ;
		RECT 0 24.2322 0.1097 24.2824 ;
		RECT 0 24.3827 0.1097 24.4078 ;
		RECT 0 24.5082 0.1097 25.2863 ;
		RECT 0 25.3867 0.1097 25.4118 ;
		RECT 0 25.5122 0.1097 25.5624 ;
		RECT 0 25.6627 0.1097 25.6878 ;
		RECT 0 25.7882 0.1097 26.5663 ;
		RECT 0 26.6667 0.1097 26.6918 ;
		RECT 0 26.7922 0.1097 26.8424 ;
		RECT 0 26.9427 0.1097 26.9678 ;
		RECT 0 27.0682 0.1097 27.8463 ;
		RECT 0 27.9467 0.1097 27.9718 ;
		RECT 0 28.0722 0.1097 28.1224 ;
		RECT 0 28.2227 0.1097 28.2478 ;
		RECT 0 28.3482 0.1097 29.1263 ;
		RECT 0 29.2267 0.1097 29.2518 ;
		RECT 0 29.3522 0.1097 29.4024 ;
		RECT 0 29.5027 0.1097 29.5278 ;
		RECT 0 29.6282 0.1097 30.4063 ;
		RECT 0 30.5067 0.1097 30.5318 ;
		RECT 0 30.6322 0.1097 30.6824 ;
		RECT 0 30.7827 0.1097 30.8078 ;
		RECT 0 30.9082 0.1097 31.6863 ;
		RECT 0 31.7867 0.1097 31.8118 ;
		RECT 0 31.9122 0.1097 31.9624 ;
		RECT 0 32.0627 0.1097 32.0878 ;
		RECT 0 32.1882 0.1097 32.9663 ;
		RECT 0 33.0667 0.1097 33.0918 ;
		RECT 0 33.1922 0.1097 33.2424 ;
		RECT 0 33.3427 0.1097 33.3678 ;
		RECT 0 33.4682 0.1097 34.2463 ;
		RECT 0 34.3467 0.1097 34.3718 ;
		RECT 0 34.4722 0.1097 34.5224 ;
		RECT 0 34.6227 0.1097 34.6478 ;
		RECT 0 34.7482 0.1097 35.5263 ;
		RECT 0 35.6267 0.1097 35.6518 ;
		RECT 0 35.7522 0.1097 35.8024 ;
		RECT 0 35.9027 0.1097 35.9278 ;
		RECT 0 36.0282 0.1097 36.8063 ;
		RECT 0 36.9067 0.1097 36.9318 ;
		RECT 0 37.0322 0.1097 37.0824 ;
		RECT 0 37.1827 0.1097 37.2078 ;
		RECT 0 37.3082 0.1097 38.0863 ;
		RECT 0 38.1867 0.1097 38.2118 ;
		RECT 0 38.3122 0.1097 38.3624 ;
		RECT 0 38.4627 0.1097 38.4878 ;
		RECT 0 38.5882 0.1097 39.3663 ;
		RECT 0 39.4667 0.1097 39.4918 ;
		RECT 0 39.5922 0.1097 39.6424 ;
		RECT 0 39.7427 0.1097 39.7678 ;
		RECT 0 39.8682 0.1097 40.6463 ;
		RECT 0 40.7467 0.1097 40.7718 ;
		RECT 0 40.8722 0.1097 40.9224 ;
		RECT 0 41.0227 0.1097 41.0478 ;
		RECT 0 41.1482 0.1097 41.4996 ;
		RECT 0 41.6 0.1097 41.6502 ;
		RECT 0 41.7506 0.1097 42.102 ;
		RECT 0 42.2024 0.1097 42.2525 ;
		RECT 0 42.3529 0.1097 42.4031 ;
		RECT 0 42.5035 0.1097 42.7043 ;
		RECT 0 42.8047 0.1097 43.0055 ;
		RECT 0 43.1059 0.1097 43.1561 ;
		RECT 0 43.2565 0.1097 43.3067 ;
		RECT 0 43.4071 0.1097 43.4573 ;
		RECT 0 43.5576 0.1097 43.6078 ;
		RECT 0 43.7082 0.1097 43.7584 ;
		RECT 0 43.8588 0.1097 43.909 ;
		RECT 0 44.0094 0.1097 44.0596 ;
		RECT 0 44.0596 0.0098 44.16 ;
		RECT 0 44.16 0.1097 44.2102 ;
		RECT 0 44.3106 0.1097 44.3608 ;
		RECT 0 44.4612 0.1097 44.5114 ;
		RECT 0 44.6118 0.1097 44.662 ;
		RECT 0 44.7624 0.1097 44.8125 ;
		RECT 0 44.9129 0.1097 44.9631 ;
		RECT 0 45.0635 0.1097 45.1137 ;
		RECT 0 45.2141 0.1097 45.2643 ;
		RECT 0 45.3647 0.1097 45.4149 ;
		RECT 0 45.4149 0.0098 45.5153 ;
		RECT 0 45.5153 0.1097 45.5655 ;
		RECT 0 45.6659 0.1097 45.7161 ;
		RECT 0 45.8165 0.1097 45.8667 ;
		RECT 0 45.9671 0.1097 46.0173 ;
		RECT 0 46.0173 0.0098 46.1176 ;
		RECT 0 46.1176 0.1097 46.1678 ;
		RECT 0 46.2682 0.1097 46.3184 ;
		RECT 0 46.3184 0.0098 46.4188 ;
		RECT 0 46.4188 0.1097 46.469 ;
		RECT 0 46.469 0.0098 46.5694 ;
		RECT 0 46.5694 0.1097 46.7702 ;
		RECT 0 46.8706 0.1097 46.9208 ;
		RECT 0 47.0212 0.1097 47.0714 ;
		RECT 0 47.0714 0.0098 47.1718 ;
		RECT 0 47.1718 0.1097 47.222 ;
		RECT 0 47.3224 0.1097 47.3725 ;
		RECT 0 47.4729 0.1097 47.8243 ;
		RECT 0 47.9247 0.1097 47.9749 ;
		RECT 0 48.0753 0.1097 48.5773 ;
		RECT 0 48.6776 0.1097 48.9224 ;
		RECT 0 49.0227 0.1097 49.0478 ;
		RECT 0 49.1482 0.1097 49.1984 ;
		RECT 0 49.2988 0.1097 49.3239 ;
		RECT 0 49.4243 0.1097 50.2024 ;
		RECT 0 50.3027 0.1097 50.3278 ;
		RECT 0 50.4282 0.1097 50.4784 ;
		RECT 0 50.5788 0.1097 50.6039 ;
		RECT 0 50.7043 0.1097 51.4824 ;
		RECT 0 51.5827 0.1097 51.6078 ;
		RECT 0 51.7082 0.1097 51.7584 ;
		RECT 0 51.8588 0.1097 51.8839 ;
		RECT 0 51.9843 0.1097 52.7624 ;
		RECT 0 52.8627 0.1097 52.8878 ;
		RECT 0 52.9882 0.1097 53.0384 ;
		RECT 0 53.1388 0.1097 53.1639 ;
		RECT 0 53.2643 0.1097 54.0424 ;
		RECT 0 54.1427 0.1097 54.1678 ;
		RECT 0 54.2682 0.1097 54.3184 ;
		RECT 0 54.4188 0.1097 54.4439 ;
		RECT 0 54.5443 0.1097 55.3224 ;
		RECT 0 55.4227 0.1097 55.4478 ;
		RECT 0 55.5482 0.1097 55.5984 ;
		RECT 0 55.6988 0.1097 55.7239 ;
		RECT 0 55.8243 0.1097 56.6024 ;
		RECT 0 56.7027 0.1097 56.7278 ;
		RECT 0 56.8282 0.1097 56.8784 ;
		RECT 0 56.9788 0.1097 57.0039 ;
		RECT 0 57.1043 0.1097 57.8824 ;
		RECT 0 57.9827 0.1097 58.0078 ;
		RECT 0 58.1082 0.1097 58.1584 ;
		RECT 0 58.2588 0.1097 58.2839 ;
		RECT 0 58.3843 0.1097 59.1624 ;
		RECT 0 59.2627 0.1097 59.2878 ;
		RECT 0 59.3882 0.1097 59.4384 ;
		RECT 0 59.5388 0.1097 59.5639 ;
		RECT 0 59.6643 0.1097 60.4424 ;
		RECT 0 60.5427 0.1097 60.5678 ;
		RECT 0 60.6682 0.1097 60.7184 ;
		RECT 0 60.8188 0.1097 60.8439 ;
		RECT 0 60.9443 0.1097 61.7224 ;
		RECT 0 61.8227 0.1097 61.8478 ;
		RECT 0 61.9482 0.1097 61.9984 ;
		RECT 0 62.0988 0.1097 62.1239 ;
		RECT 0 62.2243 0.1097 63.0024 ;
		RECT 0 63.1027 0.1097 63.1278 ;
		RECT 0 63.2282 0.1097 63.2784 ;
		RECT 0 63.3788 0.1097 63.4039 ;
		RECT 0 63.5043 0.1097 64.2824 ;
		RECT 0 64.3827 0.1097 64.4078 ;
		RECT 0 64.5082 0.1097 64.5584 ;
		RECT 0 64.6588 0.1097 64.6839 ;
		RECT 0 64.7843 0.1097 65.5624 ;
		RECT 0 65.6627 0.1097 65.6878 ;
		RECT 0 65.7882 0.1097 65.8384 ;
		RECT 0 65.9388 0.1097 65.9639 ;
		RECT 0 66.0643 0.1097 66.8424 ;
		RECT 0 66.9427 0.1097 66.9678 ;
		RECT 0 67.0682 0.1097 67.1184 ;
		RECT 0 67.2188 0.1097 67.2439 ;
		RECT 0 67.3443 0.1097 68.1224 ;
		RECT 0 68.2227 0.1097 68.2478 ;
		RECT 0 68.3482 0.1097 68.3984 ;
		RECT 0 68.4988 0.1097 68.5239 ;
		RECT 0 68.6243 0.1097 69.4024 ;
		RECT 0 69.5027 0.1097 69.5278 ;
		RECT 0 69.6282 0.1097 69.6784 ;
		RECT 0 69.7788 0.1097 69.8039 ;
		RECT 0 69.9043 0.1097 70.6824 ;
		RECT 0 70.7827 0.1097 70.8078 ;
		RECT 0 70.9082 0.1097 70.9584 ;
		RECT 0 71.0588 0.1097 71.0839 ;
		RECT 0 71.1843 0.1097 71.9624 ;
		RECT 0 72.0627 0.1097 72.0878 ;
		RECT 0 72.1882 0.1097 72.2384 ;
		RECT 0 72.3388 0.1097 72.3639 ;
		RECT 0 72.4643 0.1097 73.2424 ;
		RECT 0 73.3427 0.1097 73.3678 ;
		RECT 0 73.4682 0.1097 73.5184 ;
		RECT 0 73.6188 0.1097 73.6439 ;
		RECT 0 73.7443 0.1097 74.5224 ;
		RECT 0 74.6227 0.1097 74.6478 ;
		RECT 0 74.7482 0.1097 74.7984 ;
		RECT 0 74.8988 0.1097 74.9239 ;
		RECT 0 75.0243 0.1097 75.8024 ;
		RECT 0 75.9027 0.1097 75.9278 ;
		RECT 0 76.0282 0.1097 76.0784 ;
		RECT 0 76.1788 0.1097 76.2039 ;
		RECT 0 76.3043 0.1097 77.0824 ;
		RECT 0 77.1827 0.1097 77.2078 ;
		RECT 0 77.3082 0.1097 77.3584 ;
		RECT 0 77.4588 0.1097 77.4839 ;
		RECT 0 77.5843 0.1097 78.3624 ;
		RECT 0 78.4627 0.1097 78.4878 ;
		RECT 0 78.5882 0.1097 78.6384 ;
		RECT 0 78.7388 0.1097 78.7639 ;
		RECT 0 78.8643 0.1097 79.6424 ;
		RECT 0 79.7427 0.1097 79.7678 ;
		RECT 0 79.8682 0.1097 79.9184 ;
		RECT 0 80.0188 0.1097 80.0439 ;
		RECT 0 80.1443 0.1097 80.9224 ;
		RECT 0 81.0227 0.1097 81.0478 ;
		RECT 0 81.1482 0.1097 81.1984 ;
		RECT 0 81.2988 0.1097 81.3239 ;
		RECT 0 81.4243 0.1097 82.2024 ;
		RECT 0 82.3027 0.1097 82.3278 ;
		RECT 0 82.4282 0.1097 82.4784 ;
		RECT 0 82.5788 0.1097 82.6039 ;
		RECT 0 82.7043 0.1097 83.4824 ;
		RECT 0 83.5827 0.1097 83.6078 ;
		RECT 0 83.7082 0.1097 83.7584 ;
		RECT 0 83.8588 0.1097 83.8839 ;
		RECT 0 83.9843 0.1097 84.7624 ;
		RECT 0 84.8627 0.1097 84.8878 ;
		RECT 0 84.9882 0.1097 85.0384 ;
		RECT 0 85.1388 0.1097 85.1639 ;
		RECT 0 85.2643 0.1097 86.0424 ;
		RECT 0 86.1427 0.1097 86.1678 ;
		RECT 0 86.2682 0.1097 86.3184 ;
		RECT 0 86.4188 0.1097 86.4439 ;
		RECT 0 86.5443 0.1097 87.3224 ;
		RECT 0 87.4227 0.1097 87.4478 ;
		RECT 0 87.5482 0.1097 87.5984 ;
		RECT 0 87.6988 0.1097 87.7239 ;
		RECT 0 87.8243 0.1097 88.6024 ;
		RECT 0 88.7027 0.1097 88.7278 ;
		RECT 0 88.8282 0.1097 88.8784 ;
		RECT 0 88.9788 0.1097 89.0039 ;
		RECT 0 89.1043 0.1097 89.9075 ;
		RECT 0 90.0078 0.1097 90.0706 ;
		 LAYER V2 ;
		RECT 0.0481 1.0918 0.1097 1.2424 ;
		RECT 0.0481 1.2424 0.1097 1.3678 ;
		RECT 0.0481 2.3718 0.1097 2.5224 ;
		RECT 0.0481 2.5224 0.1097 2.6478 ;
		RECT 0.0481 3.6518 0.1097 3.8024 ;
		RECT 0.0481 3.8024 0.1097 3.9278 ;
		RECT 0.0481 4.9318 0.1097 5.0824 ;
		RECT 0.0481 5.0824 0.1097 5.2078 ;
		RECT 0.0481 6.2118 0.1097 6.3624 ;
		RECT 0.0481 6.3624 0.1097 6.4878 ;
		RECT 0.0481 7.4918 0.1097 7.6424 ;
		RECT 0.0481 7.6424 0.1097 7.7678 ;
		RECT 0.0481 8.7718 0.1097 8.9224 ;
		RECT 0.0481 8.9224 0.1097 9.0478 ;
		RECT 0.0481 10.0518 0.1097 10.2024 ;
		RECT 0.0481 10.2024 0.1097 10.3278 ;
		RECT 0.0481 11.3318 0.1097 11.4824 ;
		RECT 0.0481 11.4824 0.1097 11.6078 ;
		RECT 0.0481 12.6118 0.1097 12.7624 ;
		RECT 0.0481 12.7624 0.1097 12.8878 ;
		RECT 0.0481 13.8918 0.1097 14.0424 ;
		RECT 0.0481 14.0424 0.1097 14.1678 ;
		RECT 0.0481 15.1718 0.1097 15.3224 ;
		RECT 0.0481 15.3224 0.1097 15.4478 ;
		RECT 0.0481 16.4518 0.1097 16.6024 ;
		RECT 0.0481 16.6024 0.1097 16.7278 ;
		RECT 0.0481 17.7318 0.1097 17.8824 ;
		RECT 0.0481 17.8824 0.1097 18.0078 ;
		RECT 0.0481 19.0118 0.1097 19.1624 ;
		RECT 0.0481 19.1624 0.1097 19.2878 ;
		RECT 0.0481 20.2918 0.1097 20.4424 ;
		RECT 0.0481 20.4424 0.1097 20.5678 ;
		RECT 0.0481 21.5718 0.1097 21.7224 ;
		RECT 0.0481 21.7224 0.1097 21.8478 ;
		RECT 0.0481 22.8518 0.1097 23.0024 ;
		RECT 0.0481 23.0024 0.1097 23.1278 ;
		RECT 0.0481 24.1318 0.1097 24.2824 ;
		RECT 0.0481 24.2824 0.1097 24.4078 ;
		RECT 0.0481 25.4118 0.1097 25.5624 ;
		RECT 0.0481 25.5624 0.1097 25.6878 ;
		RECT 0.0481 26.6918 0.1097 26.8424 ;
		RECT 0.0481 26.8424 0.1097 26.9678 ;
		RECT 0.0481 27.9718 0.1097 28.1224 ;
		RECT 0.0481 28.1224 0.1097 28.2478 ;
		RECT 0.0481 29.2518 0.1097 29.4024 ;
		RECT 0.0481 29.4024 0.1097 29.5278 ;
		RECT 0.0481 30.5318 0.1097 30.6824 ;
		RECT 0.0481 30.6824 0.1097 30.8078 ;
		RECT 0.0481 31.8118 0.1097 31.9624 ;
		RECT 0.0481 31.9624 0.1097 32.0878 ;
		RECT 0.0481 33.0918 0.1097 33.2424 ;
		RECT 0.0481 33.2424 0.1097 33.3678 ;
		RECT 0.0481 34.3718 0.1097 34.5224 ;
		RECT 0.0481 34.5224 0.1097 34.6478 ;
		RECT 0.0481 35.6518 0.1097 35.8024 ;
		RECT 0.0481 35.8024 0.1097 35.9278 ;
		RECT 0.0481 36.9318 0.1097 37.0824 ;
		RECT 0.0481 37.0824 0.1097 37.2078 ;
		RECT 0.0481 38.2118 0.1097 38.3624 ;
		RECT 0.0481 38.3624 0.1097 38.4878 ;
		RECT 0.0481 39.4918 0.1097 39.6424 ;
		RECT 0.0481 39.6424 0.1097 39.7678 ;
		RECT 0.0481 40.7718 0.1097 40.9224 ;
		RECT 0.0481 40.9224 0.1097 41.0478 ;
		RECT 0.0481 49.0478 0.1097 49.1984 ;
		RECT 0.0481 49.1984 0.1097 49.3239 ;
		RECT 0.0481 50.3278 0.1097 50.4784 ;
		RECT 0.0481 50.4784 0.1097 50.6039 ;
		RECT 0.0481 51.6078 0.1097 51.7584 ;
		RECT 0.0481 51.7584 0.1097 51.8839 ;
		RECT 0.0481 52.8878 0.1097 53.0384 ;
		RECT 0.0481 53.0384 0.1097 53.1639 ;
		RECT 0.0481 54.1678 0.1097 54.3184 ;
		RECT 0.0481 54.3184 0.1097 54.4439 ;
		RECT 0.0481 55.4478 0.1097 55.5984 ;
		RECT 0.0481 55.5984 0.1097 55.7239 ;
		RECT 0.0481 56.7278 0.1097 56.8784 ;
		RECT 0.0481 56.8784 0.1097 57.0039 ;
		RECT 0.0481 58.0078 0.1097 58.1584 ;
		RECT 0.0481 58.1584 0.1097 58.2839 ;
		RECT 0.0481 59.2878 0.1097 59.4384 ;
		RECT 0.0481 59.4384 0.1097 59.5639 ;
		RECT 0.0481 60.5678 0.1097 60.7184 ;
		RECT 0.0481 60.7184 0.1097 60.8439 ;
		RECT 0.0481 61.8478 0.1097 61.9984 ;
		RECT 0.0481 61.9984 0.1097 62.1239 ;
		RECT 0.0481 63.1278 0.1097 63.2784 ;
		RECT 0.0481 63.2784 0.1097 63.4039 ;
		RECT 0.0481 64.4078 0.1097 64.5584 ;
		RECT 0.0481 64.5584 0.1097 64.6839 ;
		RECT 0.0481 65.6878 0.1097 65.8384 ;
		RECT 0.0481 65.8384 0.1097 65.9639 ;
		RECT 0.0481 66.9678 0.1097 67.1184 ;
		RECT 0.0481 67.1184 0.1097 67.2439 ;
		RECT 0.0481 68.2478 0.1097 68.3984 ;
		RECT 0.0481 68.3984 0.1097 68.5239 ;
		RECT 0.0481 69.5278 0.1097 69.6784 ;
		RECT 0.0481 69.6784 0.1097 69.8039 ;
		RECT 0.0481 70.8078 0.1097 70.9584 ;
		RECT 0.0481 70.9584 0.1097 71.0839 ;
		RECT 0.0481 72.0878 0.1097 72.2384 ;
		RECT 0.0481 72.2384 0.1097 72.3639 ;
		RECT 0.0481 73.3678 0.1097 73.5184 ;
		RECT 0.0481 73.5184 0.1097 73.6439 ;
		RECT 0.0481 74.6478 0.1097 74.7984 ;
		RECT 0.0481 74.7984 0.1097 74.9239 ;
		RECT 0.0481 75.9278 0.1097 76.0784 ;
		RECT 0.0481 76.0784 0.1097 76.2039 ;
		RECT 0.0481 77.2078 0.1097 77.3584 ;
		RECT 0.0481 77.3584 0.1097 77.4839 ;
		RECT 0.0481 78.4878 0.1097 78.6384 ;
		RECT 0.0481 78.6384 0.1097 78.7639 ;
		RECT 0.0481 79.7678 0.1097 79.9184 ;
		RECT 0.0481 79.9184 0.1097 80.0439 ;
		RECT 0.0481 81.0478 0.1097 81.1984 ;
		RECT 0.0481 81.1984 0.1097 81.3239 ;
		RECT 0.0481 82.3278 0.1097 82.4784 ;
		RECT 0.0481 82.4784 0.1097 82.6039 ;
		RECT 0.0481 83.6078 0.1097 83.7584 ;
		RECT 0.0481 83.7584 0.1097 83.8839 ;
		RECT 0.0481 84.8878 0.1097 85.0384 ;
		RECT 0.0481 85.0384 0.1097 85.1639 ;
		RECT 0.0481 86.1678 0.1097 86.3184 ;
		RECT 0.0481 86.3184 0.1097 86.4439 ;
		RECT 0.0481 87.4478 0.1097 87.5984 ;
		RECT 0.0481 87.5984 0.1097 87.7239 ;
		RECT 0.0481 88.7278 0.1097 88.8784 ;
		RECT 0.0481 88.8784 0.1097 89.0039 ;
		RECT 0.0831 41.2106 0.098 41.2231 ;
		RECT 0.0215 41.2733 0.0364 41.2859 ;
		RECT 0.0831 41.3612 0.098 41.3737 ;
		RECT 0.0215 41.4239 0.0364 41.4365 ;
		RECT 0.0215 41.5745 0.0364 41.5871 ;
		RECT 0.0215 41.7251 0.0364 41.7376 ;
		RECT 0.021 41.8137 0.0359 41.8263 ;
		RECT 0.0831 41.9635 0.098 41.9761 ;
		RECT 0.0215 42.0263 0.0364 42.0388 ;
		RECT 0.0831 42.1141 0.098 42.1267 ;
		RECT 0.0215 42.3275 0.0364 42.34 ;
		RECT 0.0831 42.5659 0.098 42.5784 ;
		RECT 0.0215 42.6286 0.0364 42.6412 ;
		RECT 0.0831 42.7165 0.098 42.729 ;
		RECT 0.021 42.8678 0.0359 42.8804 ;
		RECT 0.0831 43.4694 0.098 43.482 ;
		RECT 0.0215 43.9839 0.0364 43.9965 ;
		RECT 0.0831 44.1039 0.098 44.1165 ;
		RECT 0.0831 44.2224 0.098 44.2349 ;
		RECT 0.0831 45.1259 0.098 45.1384 ;
		RECT 0.0215 45.3392 0.0364 45.3518 ;
		RECT 0.0831 45.4592 0.098 45.4718 ;
		RECT 0.0831 45.5776 0.098 45.5902 ;
		RECT 0.0831 45.8788 0.098 45.8914 ;
		RECT 0.0831 46.0616 0.098 46.0741 ;
		RECT 0.0215 46.2427 0.0364 46.2553 ;
		RECT 0.0831 46.3627 0.098 46.3753 ;
		RECT 0.0831 46.5125 0.098 46.5251 ;
		RECT 0.0215 46.6325 0.0364 46.6451 ;
		RECT 0.0831 46.6953 0.098 46.7078 ;
		RECT 0.0831 47.1157 0.098 47.1282 ;
		RECT 0.0831 47.5353 0.098 47.5478 ;
		RECT 0.0215 47.598 0.0364 47.6106 ;
		RECT 0.021 47.6867 0.0359 47.6992 ;
		RECT 0.0831 48.1376 0.098 48.1502 ;
		RECT 0.0215 48.2004 0.0364 48.2129 ;
		RECT 0.021 48.351 0.0359 48.3635 ;
		RECT 0.0831 48.4388 0.098 48.4514 ;
		RECT 0.0215 48.5016 0.0364 48.5141 ;
		RECT 0.0831 48.5894 0.098 48.602 ;
		RECT 0.021 48.8027 0.0359 48.8153 ;
		RECT 0.0215 0.1376 0.0364 0.1502 ;
		RECT 0.0215 89.9204 0.0364 89.9329 ;
		 LAYER V2 SPACING 0 ;
		RECT 0.0481 1.0918 0.1097 1.2424 ;
		RECT 0.0481 1.2424 0.1097 1.3678 ;
		RECT 0.0481 2.3718 0.1097 2.5224 ;
		RECT 0.0481 2.5224 0.1097 2.6478 ;
		RECT 0.0481 3.6518 0.1097 3.8024 ;
		RECT 0.0481 3.8024 0.1097 3.9278 ;
		RECT 0.0481 4.9318 0.1097 5.0824 ;
		RECT 0.0481 5.0824 0.1097 5.2078 ;
		RECT 0.0481 6.2118 0.1097 6.3624 ;
		RECT 0.0481 6.3624 0.1097 6.4878 ;
		RECT 0.0481 7.4918 0.1097 7.6424 ;
		RECT 0.0481 7.6424 0.1097 7.7678 ;
		RECT 0.0481 8.7718 0.1097 8.9224 ;
		RECT 0.0481 8.9224 0.1097 9.0478 ;
		RECT 0.0481 10.0518 0.1097 10.2024 ;
		RECT 0.0481 10.2024 0.1097 10.3278 ;
		RECT 0.0481 11.3318 0.1097 11.4824 ;
		RECT 0.0481 11.4824 0.1097 11.6078 ;
		RECT 0.0481 12.6118 0.1097 12.7624 ;
		RECT 0.0481 12.7624 0.1097 12.8878 ;
		RECT 0.0481 13.8918 0.1097 14.0424 ;
		RECT 0.0481 14.0424 0.1097 14.1678 ;
		RECT 0.0481 15.1718 0.1097 15.3224 ;
		RECT 0.0481 15.3224 0.1097 15.4478 ;
		RECT 0.0481 16.4518 0.1097 16.6024 ;
		RECT 0.0481 16.6024 0.1097 16.7278 ;
		RECT 0.0481 17.7318 0.1097 17.8824 ;
		RECT 0.0481 17.8824 0.1097 18.0078 ;
		RECT 0.0481 19.0118 0.1097 19.1624 ;
		RECT 0.0481 19.1624 0.1097 19.2878 ;
		RECT 0.0481 20.2918 0.1097 20.4424 ;
		RECT 0.0481 20.4424 0.1097 20.5678 ;
		RECT 0.0481 21.5718 0.1097 21.7224 ;
		RECT 0.0481 21.7224 0.1097 21.8478 ;
		RECT 0.0481 22.8518 0.1097 23.0024 ;
		RECT 0.0481 23.0024 0.1097 23.1278 ;
		RECT 0.0481 24.1318 0.1097 24.2824 ;
		RECT 0.0481 24.2824 0.1097 24.4078 ;
		RECT 0.0481 25.4118 0.1097 25.5624 ;
		RECT 0.0481 25.5624 0.1097 25.6878 ;
		RECT 0.0481 26.6918 0.1097 26.8424 ;
		RECT 0.0481 26.8424 0.1097 26.9678 ;
		RECT 0.0481 27.9718 0.1097 28.1224 ;
		RECT 0.0481 28.1224 0.1097 28.2478 ;
		RECT 0.0481 29.2518 0.1097 29.4024 ;
		RECT 0.0481 29.4024 0.1097 29.5278 ;
		RECT 0.0481 30.5318 0.1097 30.6824 ;
		RECT 0.0481 30.6824 0.1097 30.8078 ;
		RECT 0.0481 31.8118 0.1097 31.9624 ;
		RECT 0.0481 31.9624 0.1097 32.0878 ;
		RECT 0.0481 33.0918 0.1097 33.2424 ;
		RECT 0.0481 33.2424 0.1097 33.3678 ;
		RECT 0.0481 34.3718 0.1097 34.5224 ;
		RECT 0.0481 34.5224 0.1097 34.6478 ;
		RECT 0.0481 35.6518 0.1097 35.8024 ;
		RECT 0.0481 35.8024 0.1097 35.9278 ;
		RECT 0.0481 36.9318 0.1097 37.0824 ;
		RECT 0.0481 37.0824 0.1097 37.2078 ;
		RECT 0.0481 38.2118 0.1097 38.3624 ;
		RECT 0.0481 38.3624 0.1097 38.4878 ;
		RECT 0.0481 39.4918 0.1097 39.6424 ;
		RECT 0.0481 39.6424 0.1097 39.7678 ;
		RECT 0.0481 40.7718 0.1097 40.9224 ;
		RECT 0.0481 40.9224 0.1097 41.0478 ;
		RECT 0.0481 49.0478 0.1097 49.1984 ;
		RECT 0.0481 49.1984 0.1097 49.3239 ;
		RECT 0.0481 50.3278 0.1097 50.4784 ;
		RECT 0.0481 50.4784 0.1097 50.6039 ;
		RECT 0.0481 51.6078 0.1097 51.7584 ;
		RECT 0.0481 51.7584 0.1097 51.8839 ;
		RECT 0.0481 52.8878 0.1097 53.0384 ;
		RECT 0.0481 53.0384 0.1097 53.1639 ;
		RECT 0.0481 54.1678 0.1097 54.3184 ;
		RECT 0.0481 54.3184 0.1097 54.4439 ;
		RECT 0.0481 55.4478 0.1097 55.5984 ;
		RECT 0.0481 55.5984 0.1097 55.7239 ;
		RECT 0.0481 56.7278 0.1097 56.8784 ;
		RECT 0.0481 56.8784 0.1097 57.0039 ;
		RECT 0.0481 58.0078 0.1097 58.1584 ;
		RECT 0.0481 58.1584 0.1097 58.2839 ;
		RECT 0.0481 59.2878 0.1097 59.4384 ;
		RECT 0.0481 59.4384 0.1097 59.5639 ;
		RECT 0.0481 60.5678 0.1097 60.7184 ;
		RECT 0.0481 60.7184 0.1097 60.8439 ;
		RECT 0.0481 61.8478 0.1097 61.9984 ;
		RECT 0.0481 61.9984 0.1097 62.1239 ;
		RECT 0.0481 63.1278 0.1097 63.2784 ;
		RECT 0.0481 63.2784 0.1097 63.4039 ;
		RECT 0.0481 64.4078 0.1097 64.5584 ;
		RECT 0.0481 64.5584 0.1097 64.6839 ;
		RECT 0.0481 65.6878 0.1097 65.8384 ;
		RECT 0.0481 65.8384 0.1097 65.9639 ;
		RECT 0.0481 66.9678 0.1097 67.1184 ;
		RECT 0.0481 67.1184 0.1097 67.2439 ;
		RECT 0.0481 68.2478 0.1097 68.3984 ;
		RECT 0.0481 68.3984 0.1097 68.5239 ;
		RECT 0.0481 69.5278 0.1097 69.6784 ;
		RECT 0.0481 69.6784 0.1097 69.8039 ;
		RECT 0.0481 70.8078 0.1097 70.9584 ;
		RECT 0.0481 70.9584 0.1097 71.0839 ;
		RECT 0.0481 72.0878 0.1097 72.2384 ;
		RECT 0.0481 72.2384 0.1097 72.3639 ;
		RECT 0.0481 73.3678 0.1097 73.5184 ;
		RECT 0.0481 73.5184 0.1097 73.6439 ;
		RECT 0.0481 74.6478 0.1097 74.7984 ;
		RECT 0.0481 74.7984 0.1097 74.9239 ;
		RECT 0.0481 75.9278 0.1097 76.0784 ;
		RECT 0.0481 76.0784 0.1097 76.2039 ;
		RECT 0.0481 77.2078 0.1097 77.3584 ;
		RECT 0.0481 77.3584 0.1097 77.4839 ;
		RECT 0.0481 78.4878 0.1097 78.6384 ;
		RECT 0.0481 78.6384 0.1097 78.7639 ;
		RECT 0.0481 79.7678 0.1097 79.9184 ;
		RECT 0.0481 79.9184 0.1097 80.0439 ;
		RECT 0.0481 81.0478 0.1097 81.1984 ;
		RECT 0.0481 81.1984 0.1097 81.3239 ;
		RECT 0.0481 82.3278 0.1097 82.4784 ;
		RECT 0.0481 82.4784 0.1097 82.6039 ;
		RECT 0.0481 83.6078 0.1097 83.7584 ;
		RECT 0.0481 83.7584 0.1097 83.8839 ;
		RECT 0.0481 84.8878 0.1097 85.0384 ;
		RECT 0.0481 85.0384 0.1097 85.1639 ;
		RECT 0.0481 86.1678 0.1097 86.3184 ;
		RECT 0.0481 86.3184 0.1097 86.4439 ;
		RECT 0.0481 87.4478 0.1097 87.5984 ;
		RECT 0.0481 87.5984 0.1097 87.7239 ;
		RECT 0.0481 88.7278 0.1097 88.8784 ;
		RECT 0.0481 88.8784 0.1097 89.0039 ;
		RECT 0.0831 41.2106 0.098 41.2231 ;
		RECT 0.0215 41.2733 0.0364 41.2859 ;
		RECT 0.0831 41.3612 0.098 41.3737 ;
		RECT 0.0215 41.4239 0.0364 41.4365 ;
		RECT 0.0215 41.5745 0.0364 41.5871 ;
		RECT 0.0215 41.7251 0.0364 41.7376 ;
		RECT 0.021 41.8137 0.0359 41.8263 ;
		RECT 0.0831 41.9635 0.098 41.9761 ;
		RECT 0.0215 42.0263 0.0364 42.0388 ;
		RECT 0.0831 42.1141 0.098 42.1267 ;
		RECT 0.0215 42.3275 0.0364 42.34 ;
		RECT 0.0831 42.5659 0.098 42.5784 ;
		RECT 0.0215 42.6286 0.0364 42.6412 ;
		RECT 0.0831 42.7165 0.098 42.729 ;
		RECT 0.021 42.8678 0.0359 42.8804 ;
		RECT 0.0831 43.4694 0.098 43.482 ;
		RECT 0.0215 43.9839 0.0364 43.9965 ;
		RECT 0.0831 44.1039 0.098 44.1165 ;
		RECT 0.0831 44.2224 0.098 44.2349 ;
		RECT 0.0831 45.1259 0.098 45.1384 ;
		RECT 0.0215 45.3392 0.0364 45.3518 ;
		RECT 0.0831 45.4592 0.098 45.4718 ;
		RECT 0.0831 45.5776 0.098 45.5902 ;
		RECT 0.0831 45.8788 0.098 45.8914 ;
		RECT 0.0831 46.0616 0.098 46.0741 ;
		RECT 0.0215 46.2427 0.0364 46.2553 ;
		RECT 0.0831 46.3627 0.098 46.3753 ;
		RECT 0.0831 46.5125 0.098 46.5251 ;
		RECT 0.0215 46.6325 0.0364 46.6451 ;
		RECT 0.0831 46.6953 0.098 46.7078 ;
		RECT 0.0831 47.1157 0.098 47.1282 ;
		RECT 0.0831 47.5353 0.098 47.5478 ;
		RECT 0.0215 47.598 0.0364 47.6106 ;
		RECT 0.021 47.6867 0.0359 47.6992 ;
		RECT 0.0831 48.1376 0.098 48.1502 ;
		RECT 0.0215 48.2004 0.0364 48.2129 ;
		RECT 0.021 48.351 0.0359 48.3635 ;
		RECT 0.0831 48.4388 0.098 48.4514 ;
		RECT 0.0215 48.5016 0.0364 48.5141 ;
		RECT 0.0831 48.5894 0.098 48.602 ;
		RECT 0.021 48.8027 0.0359 48.8153 ;
		RECT 0.0215 0.1376 0.0364 0.1502 ;
		RECT 0.0215 89.9204 0.0364 89.9329 ;
	END

END HD_4096X64M8B4

END LIBRARY

